VERSION 5.7 ;
  NOWIREEXTENSIONATPIN ON ;
  DIVIDERCHAR "/" ;
  BUSBITCHARS "[]" ;
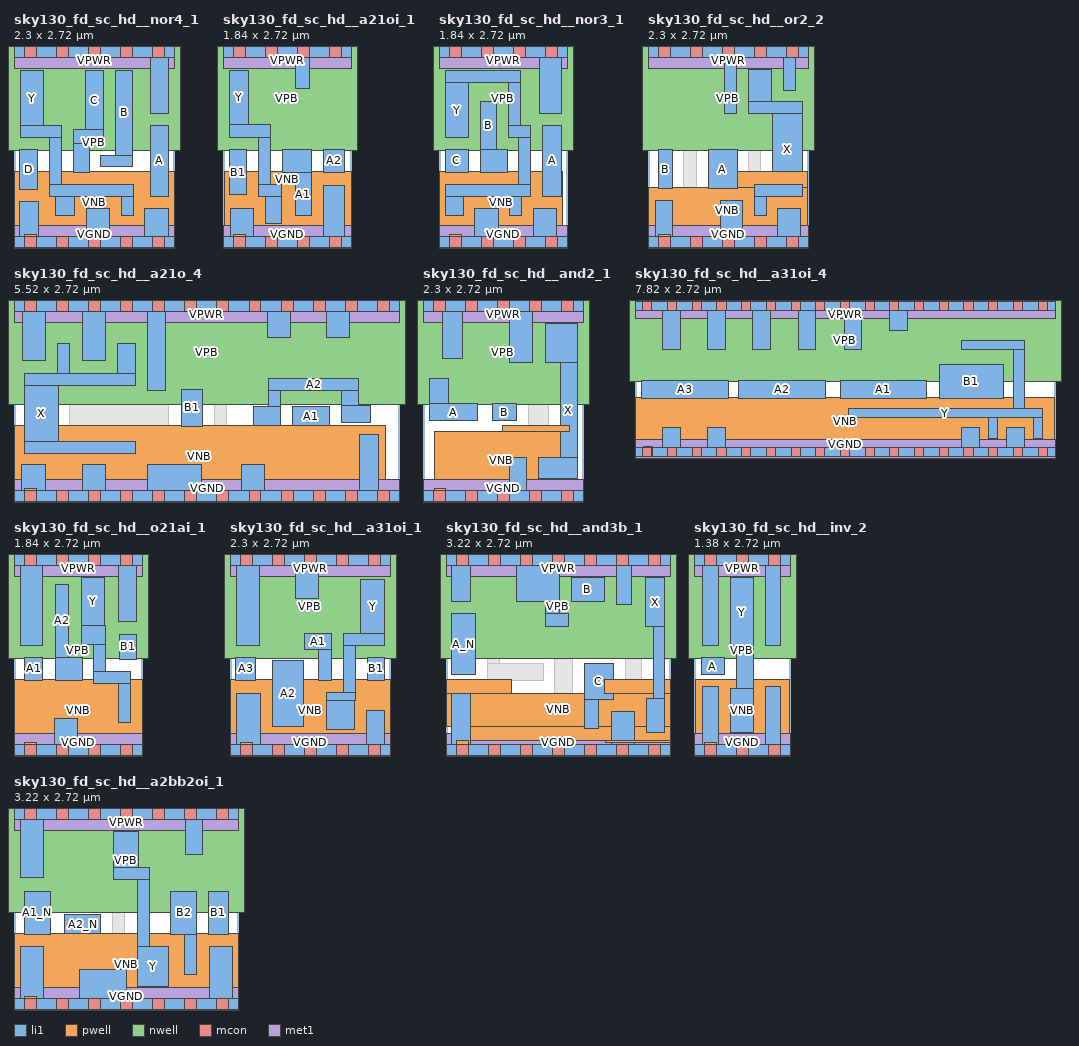
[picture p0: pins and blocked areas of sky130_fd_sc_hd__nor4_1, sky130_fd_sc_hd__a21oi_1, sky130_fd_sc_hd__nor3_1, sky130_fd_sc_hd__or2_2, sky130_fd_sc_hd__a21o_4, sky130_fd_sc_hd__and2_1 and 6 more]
MACRO sky130_fd_sc_hd__nor4_1
  CLASS BLOCK ;
  FOREIGN sky130_fd_sc_hd__nor4_1 ;
  ORIGIN 0.000 0.000 ;
  SIZE 2.300 BY 2.720 ;
  PIN D
    ANTENNAGATEAREA 0.247500 ;
    PORT
      LAYER li1 ;
        RECT 0.085 0.745 0.335 1.325 ;
    END
  END D
  PIN C
    ANTENNAGATEAREA 0.247500 ;
    PORT
      LAYER li1 ;
        RECT 1.030 1.615 1.285 2.450 ;
        RECT 0.845 1.415 1.285 1.615 ;
        RECT 0.845 0.995 1.075 1.415 ;
    END
  END C
  PIN Y
    ANTENNADIFFAREA 0.672750 ;
    PORT
      LAYER li1 ;
        RECT 0.090 1.665 0.425 2.450 ;
        RECT 0.090 1.495 0.675 1.665 ;
        RECT 0.505 0.825 0.675 1.495 ;
        RECT 0.505 0.655 1.705 0.825 ;
        RECT 0.505 0.645 0.860 0.655 ;
        RECT 0.595 0.385 0.860 0.645 ;
        RECT 1.535 0.385 1.705 0.655 ;
    END
  END Y
  PIN A
    ANTENNAGATEAREA 0.247500 ;
    PORT
      LAYER li1 ;
        RECT 1.955 0.655 2.215 1.665 ;
    END
  END A
  PIN B
    ANTENNAGATEAREA 0.247500 ;
    PORT
      LAYER li1 ;
        RECT 1.455 1.245 1.695 2.450 ;
        RECT 1.245 1.075 1.695 1.245 ;
    END
  END B
  PIN VNB
    PORT
      LAYER pwell ;
        RECT 0.005 0.105 2.295 1.015 ;
        RECT 0.145 -0.085 0.315 0.105 ;
    END
  END VNB
  PIN VPB
    PORT
      LAYER nwell ;
        RECT -0.190 1.305 2.490 2.910 ;
    END
  END VPB
  PIN VGND
    USE GROUND ;
    PORT
      LAYER li1 ;
        RECT 0.085 0.085 0.345 0.575 ;
        RECT 1.035 0.085 1.365 0.485 ;
        RECT 1.875 0.085 2.205 0.485 ;
        RECT 0.000 -0.085 2.300 0.085 ;
      LAYER mcon ;
        RECT 0.145 -0.085 0.315 0.085 ;
        RECT 0.605 -0.085 0.775 0.085 ;
        RECT 1.065 -0.085 1.235 0.085 ;
        RECT 1.525 -0.085 1.695 0.085 ;
        RECT 1.985 -0.085 2.155 0.085 ;
      LAYER met1 ;
        RECT 0.000 -0.240 2.300 0.240 ;
    END
  END VGND
  PIN VPWR
    USE POWER ;
    PORT
      LAYER li1 ;
        RECT 0.000 2.635 2.300 2.805 ;
        RECT 1.955 1.835 2.215 2.635 ;
      LAYER mcon ;
        RECT 0.145 2.635 0.315 2.805 ;
        RECT 0.605 2.635 0.775 2.805 ;
        RECT 1.065 2.635 1.235 2.805 ;
        RECT 1.525 2.635 1.695 2.805 ;
        RECT 1.985 2.635 2.155 2.805 ;
      LAYER met1 ;
        RECT 0.000 2.480 2.300 2.960 ;
    END
  END VPWR
END sky130_fd_sc_hd__nor4_1
MACRO sky130_fd_sc_hd__a21oi_1
  CLASS BLOCK ;
  FOREIGN sky130_fd_sc_hd__a21oi_1 ;
  ORIGIN 0.000 0.000 ;
  SIZE 1.840 BY 2.720 ;
  PIN A1
    ANTENNAGATEAREA 0.247500 ;
    PORT
      LAYER li1 ;
        RECT 0.850 0.995 1.265 1.325 ;
        RECT 1.035 0.375 1.265 0.995 ;
    END
  END A1
  PIN B1
    ANTENNAGATEAREA 0.247500 ;
    PORT
      LAYER li1 ;
        RECT 0.095 0.675 0.335 1.325 ;
    END
  END B1
  PIN Y
    ANTENNADIFFAREA 0.447000 ;
    PORT
      LAYER li1 ;
        RECT 0.095 1.685 0.370 2.455 ;
        RECT 0.095 1.495 0.680 1.685 ;
        RECT 0.505 0.825 0.680 1.495 ;
        RECT 0.505 0.645 0.835 0.825 ;
        RECT 0.610 0.265 0.835 0.645 ;
    END
  END Y
  PIN A2
    ANTENNAGATEAREA 0.247500 ;
    PORT
      LAYER li1 ;
        RECT 1.445 0.995 1.740 1.325 ;
    END
  END A2
  PIN VNB
    PORT
      LAYER pwell ;
        RECT 0.020 0.105 1.835 1.015 ;
        RECT 0.145 -0.085 0.315 0.105 ;
    END
  END VNB
  PIN VPB
    PORT
      LAYER nwell ;
        RECT -0.190 1.305 2.030 2.910 ;
    END
  END VPB
  PIN VPWR
    USE POWER ;
    PORT
      LAYER li1 ;
        RECT 0.000 2.635 1.840 2.805 ;
        RECT 1.040 2.195 1.235 2.635 ;
      LAYER mcon ;
        RECT 0.145 2.635 0.315 2.805 ;
        RECT 0.605 2.635 0.775 2.805 ;
        RECT 1.065 2.635 1.235 2.805 ;
        RECT 1.525 2.635 1.695 2.805 ;
      LAYER met1 ;
        RECT 0.000 2.480 1.840 2.960 ;
    END
  END VPWR
  PIN VGND
    USE GROUND ;
    PORT
      LAYER li1 ;
        RECT 0.110 0.085 0.440 0.475 ;
        RECT 1.445 0.085 1.745 0.815 ;
        RECT 0.000 -0.085 1.840 0.085 ;
      LAYER mcon ;
        RECT 0.145 -0.085 0.315 0.085 ;
        RECT 0.605 -0.085 0.775 0.085 ;
        RECT 1.065 -0.085 1.235 0.085 ;
        RECT 1.525 -0.085 1.695 0.085 ;
      LAYER met1 ;
        RECT 0.000 -0.240 1.840 0.240 ;
    END
  END VGND
  OBS
      LAYER li1 ;
        RECT 0.540 2.025 0.870 2.455 ;
        RECT 1.415 2.025 1.745 2.455 ;
        RECT 0.540 1.855 1.745 2.025 ;
        RECT 0.850 1.525 1.745 1.855 ;
  END
END sky130_fd_sc_hd__a21oi_1
MACRO sky130_fd_sc_hd__nor3_1
  CLASS BLOCK ;
  FOREIGN sky130_fd_sc_hd__nor3_1 ;
  ORIGIN 0.000 0.000 ;
  SIZE 1.840 BY 2.720 ;
  PIN C
    ANTENNAGATEAREA 0.247500 ;
    PORT
      LAYER li1 ;
        RECT 0.090 0.995 0.425 1.325 ;
    END
  END C
  PIN Y
    ANTENNADIFFAREA 0.604500 ;
    PORT
      LAYER li1 ;
        RECT 0.090 2.280 1.170 2.450 ;
        RECT 0.090 1.495 0.425 2.280 ;
        RECT 1.000 1.665 1.170 2.280 ;
        RECT 1.000 1.495 1.315 1.665 ;
        RECT 1.145 0.825 1.315 1.495 ;
        RECT 0.090 0.655 1.315 0.825 ;
        RECT 0.090 0.385 0.345 0.655 ;
        RECT 1.015 0.385 1.185 0.655 ;
    END
  END Y
  PIN A
    ANTENNAGATEAREA 0.247500 ;
    PORT
      LAYER li1 ;
        RECT 1.485 0.655 1.755 1.665 ;
    END
  END A
  PIN B
    ANTENNAGATEAREA 0.247500 ;
    PORT
      LAYER li1 ;
        RECT 0.595 1.325 0.830 2.005 ;
        RECT 0.595 0.995 0.975 1.325 ;
    END
  END B
  PIN VNB
    PORT
      LAYER pwell ;
        RECT 0.005 0.105 1.775 1.015 ;
        RECT 0.150 -0.085 0.320 0.105 ;
    END
  END VNB
  PIN VPB
    PORT
      LAYER nwell ;
        RECT -0.190 1.305 2.030 2.910 ;
    END
  END VPB
  PIN VGND
    USE GROUND ;
    PORT
      LAYER li1 ;
        RECT 0.515 0.085 0.845 0.485 ;
        RECT 1.355 0.085 1.685 0.485 ;
        RECT 0.000 -0.085 1.840 0.085 ;
      LAYER mcon ;
        RECT 0.145 -0.085 0.315 0.085 ;
        RECT 0.605 -0.085 0.775 0.085 ;
        RECT 1.065 -0.085 1.235 0.085 ;
        RECT 1.525 -0.085 1.695 0.085 ;
      LAYER met1 ;
        RECT 0.000 -0.240 1.840 0.240 ;
    END
  END VGND
  PIN VPWR
    USE POWER ;
    PORT
      LAYER li1 ;
        RECT 0.000 2.635 1.840 2.805 ;
        RECT 1.435 1.835 1.750 2.635 ;
      LAYER mcon ;
        RECT 0.145 2.635 0.315 2.805 ;
        RECT 0.605 2.635 0.775 2.805 ;
        RECT 1.065 2.635 1.235 2.805 ;
        RECT 1.525 2.635 1.695 2.805 ;
      LAYER met1 ;
        RECT 0.000 2.480 1.840 2.960 ;
    END
  END VPWR
END sky130_fd_sc_hd__nor3_1
MACRO sky130_fd_sc_hd__or2_2
  CLASS BLOCK ;
  FOREIGN sky130_fd_sc_hd__or2_2 ;
  ORIGIN 0.000 0.000 ;
  SIZE 2.300 BY 2.720 ;
  PIN B
    ANTENNAGATEAREA 0.126000 ;
    PORT
      LAYER li1 ;
        RECT 0.150 0.765 0.345 1.325 ;
    END
  END B
  PIN X
    ANTENNADIFFAREA 0.445500 ;
    PORT
      LAYER li1 ;
        RECT 1.440 2.005 1.770 2.465 ;
        RECT 1.440 1.835 2.215 2.005 ;
        RECT 1.785 0.825 2.215 1.835 ;
        RECT 1.520 0.655 2.215 0.825 ;
        RECT 1.520 0.385 1.690 0.655 ;
    END
  END X
  PIN A
    ANTENNAGATEAREA 0.126000 ;
    PORT
      LAYER li1 ;
        RECT 0.865 0.765 1.275 1.325 ;
    END
  END A
  PIN VNB
    PORT
      LAYER pwell ;
        RECT 0.910 0.785 2.280 1.015 ;
        RECT 0.005 0.105 2.280 0.785 ;
        RECT 0.150 -0.085 0.320 0.105 ;
    END
  END VNB
  PIN VPB
    PORT
      LAYER nwell ;
        RECT -0.190 1.305 2.490 2.910 ;
    END
  END VPB
  PIN VPWR
    USE POWER ;
    PORT
      LAYER li1 ;
        RECT 0.000 2.635 2.300 2.805 ;
        RECT 1.100 1.835 1.270 2.635 ;
        RECT 1.940 2.175 2.110 2.635 ;
      LAYER mcon ;
        RECT 0.145 2.635 0.315 2.805 ;
        RECT 0.605 2.635 0.775 2.805 ;
        RECT 1.065 2.635 1.235 2.805 ;
        RECT 1.525 2.635 1.695 2.805 ;
        RECT 1.985 2.635 2.155 2.805 ;
      LAYER met1 ;
        RECT 0.000 2.480 2.300 2.960 ;
    END
  END VPWR
  PIN VGND
    USE GROUND ;
    PORT
      LAYER li1 ;
        RECT 0.105 0.085 0.345 0.595 ;
        RECT 1.035 0.085 1.350 0.595 ;
        RECT 1.860 0.085 2.190 0.485 ;
        RECT 0.000 -0.085 2.300 0.085 ;
      LAYER mcon ;
        RECT 0.145 -0.085 0.315 0.085 ;
        RECT 0.605 -0.085 0.775 0.085 ;
        RECT 1.065 -0.085 1.235 0.085 ;
        RECT 1.525 -0.085 1.695 0.085 ;
        RECT 1.985 -0.085 2.155 0.085 ;
      LAYER met1 ;
        RECT 0.000 -0.240 2.300 0.240 ;
    END
  END VGND
  OBS
      LAYER li1 ;
        RECT 0.155 1.665 0.515 1.840 ;
        RECT 0.155 1.495 1.615 1.665 ;
        RECT 0.515 0.595 0.695 1.495 ;
        RECT 1.445 0.995 1.615 1.495 ;
        RECT 0.515 0.255 0.805 0.595 ;
  END
END sky130_fd_sc_hd__or2_2
MACRO sky130_fd_sc_hd__a21o_4
  CLASS BLOCK ;
  FOREIGN sky130_fd_sc_hd__a21o_4 ;
  ORIGIN 0.000 0.000 ;
  SIZE 5.520 BY 2.720 ;
  PIN A2
    ANTENNAGATEAREA 0.495000 ;
    PORT
      LAYER li1 ;
        RECT 3.645 1.510 4.935 1.680 ;
        RECT 3.645 1.275 3.820 1.510 ;
        RECT 3.425 1.010 3.820 1.275 ;
        RECT 4.685 1.290 4.935 1.510 ;
        RECT 4.685 1.055 5.100 1.290 ;
    END
  END A2
  PIN A1
    ANTENNAGATEAREA 0.495000 ;
    PORT
      LAYER li1 ;
        RECT 3.990 1.010 4.515 1.275 ;
    END
  END A1
  PIN X
    ANTENNADIFFAREA 0.924000 ;
    PORT
      LAYER li1 ;
        RECT 0.625 1.755 0.795 2.185 ;
        RECT 1.485 1.755 1.735 2.185 ;
        RECT 0.145 1.585 1.735 1.755 ;
        RECT 0.145 0.785 0.630 1.585 ;
        RECT 0.145 0.615 1.735 0.785 ;
    END
  END X
  PIN B1
    ANTENNAGATEAREA 0.495000 ;
    PORT
      LAYER li1 ;
        RECT 2.395 0.995 2.705 1.525 ;
    END
  END B1
  PIN VNB
    PORT
      LAYER pwell ;
        RECT 0.005 0.105 5.315 1.015 ;
        RECT 0.145 -0.085 0.315 0.105 ;
    END
  END VNB
  PIN VPB
    PORT
      LAYER nwell ;
        RECT -0.190 1.305 5.710 2.910 ;
    END
  END VPB
  PIN VGND
    USE GROUND ;
    PORT
      LAYER li1 ;
        RECT 0.105 0.085 0.445 0.445 ;
        RECT 0.975 0.085 1.305 0.445 ;
        RECT 1.910 0.085 2.685 0.445 ;
        RECT 3.255 0.085 3.585 0.445 ;
        RECT 4.945 0.085 5.225 0.885 ;
        RECT 0.000 -0.085 5.520 0.085 ;
      LAYER mcon ;
        RECT 0.145 -0.085 0.315 0.085 ;
        RECT 0.605 -0.085 0.775 0.085 ;
        RECT 1.065 -0.085 1.235 0.085 ;
        RECT 1.525 -0.085 1.695 0.085 ;
        RECT 1.985 -0.085 2.155 0.085 ;
        RECT 2.445 -0.085 2.615 0.085 ;
        RECT 2.905 -0.085 3.075 0.085 ;
        RECT 3.365 -0.085 3.535 0.085 ;
        RECT 3.825 -0.085 3.995 0.085 ;
        RECT 4.285 -0.085 4.455 0.085 ;
        RECT 4.745 -0.085 4.915 0.085 ;
        RECT 5.205 -0.085 5.375 0.085 ;
      LAYER met1 ;
        RECT 0.000 -0.240 5.520 0.240 ;
    END
  END VGND
  PIN VPWR
    USE POWER ;
    PORT
      LAYER li1 ;
        RECT 0.000 2.635 5.520 2.805 ;
        RECT 0.115 1.935 0.445 2.635 ;
        RECT 0.975 1.935 1.305 2.635 ;
        RECT 1.915 1.515 2.165 2.635 ;
        RECT 3.635 2.275 3.965 2.635 ;
        RECT 4.475 2.275 4.805 2.635 ;
      LAYER mcon ;
        RECT 0.145 2.635 0.315 2.805 ;
        RECT 0.605 2.635 0.775 2.805 ;
        RECT 1.065 2.635 1.235 2.805 ;
        RECT 1.525 2.635 1.695 2.805 ;
        RECT 1.985 2.635 2.155 2.805 ;
        RECT 2.445 2.635 2.615 2.805 ;
        RECT 2.905 2.635 3.075 2.805 ;
        RECT 3.365 2.635 3.535 2.805 ;
        RECT 3.825 2.635 3.995 2.805 ;
        RECT 4.285 2.635 4.455 2.805 ;
        RECT 4.745 2.635 4.915 2.805 ;
        RECT 5.205 2.635 5.375 2.805 ;
      LAYER met1 ;
        RECT 0.000 2.480 5.520 2.960 ;
    END
  END VPWR
  OBS
      LAYER li1 ;
        RECT 2.455 2.295 3.465 2.465 ;
        RECT 2.455 1.695 2.625 2.295 ;
        RECT 0.800 0.995 2.205 1.325 ;
        RECT 2.035 0.785 2.205 0.995 ;
        RECT 2.875 0.840 3.045 2.125 ;
        RECT 3.285 2.020 3.465 2.295 ;
        RECT 4.135 2.020 4.305 2.465 ;
        RECT 5.030 2.020 5.360 2.395 ;
        RECT 3.285 1.850 5.360 2.020 ;
        RECT 3.285 1.445 3.465 1.850 ;
        RECT 5.105 1.460 5.360 1.850 ;
        RECT 2.875 0.785 4.365 0.840 ;
        RECT 2.035 0.670 4.365 0.785 ;
        RECT 2.035 0.615 3.045 0.670 ;
        RECT 2.875 0.255 3.045 0.615 ;
        RECT 4.085 0.405 4.365 0.670 ;
  END
END sky130_fd_sc_hd__a21o_4
MACRO sky130_fd_sc_hd__and2_1
  CLASS BLOCK ;
  FOREIGN sky130_fd_sc_hd__and2_1 ;
  ORIGIN 0.000 0.000 ;
  SIZE 2.300 BY 2.720 ;
  PIN X
    ANTENNADIFFAREA 0.657000 ;
    PORT
      LAYER li1 ;
        RECT 1.755 1.915 2.215 2.465 ;
        RECT 1.965 0.545 2.215 1.915 ;
        RECT 1.655 0.255 2.215 0.545 ;
    END
  END X
  PIN B
    ANTENNAGATEAREA 0.126000 ;
    PORT
      LAYER li1 ;
        RECT 0.995 1.075 1.335 1.325 ;
    END
  END B
  PIN A
    ANTENNAGATEAREA 0.126000 ;
    PORT
      LAYER li1 ;
        RECT 0.100 1.325 0.365 1.685 ;
        RECT 0.100 1.075 0.775 1.325 ;
    END
  END A
  PIN VNB
    PORT
      LAYER pwell ;
        RECT 1.145 0.925 2.095 1.015 ;
        RECT 0.165 0.105 2.095 0.925 ;
        RECT 0.165 0.085 0.315 0.105 ;
        RECT 0.145 -0.085 0.315 0.085 ;
    END
  END VNB
  PIN VPB
    PORT
      LAYER nwell ;
        RECT -0.190 1.305 2.490 2.910 ;
    END
  END VPB
  PIN VPWR
    USE POWER ;
    PORT
      LAYER li1 ;
        RECT 0.000 2.635 2.300 2.805 ;
        RECT 0.285 1.965 0.565 2.635 ;
        RECT 1.235 1.915 1.565 2.635 ;
      LAYER mcon ;
        RECT 0.145 2.635 0.315 2.805 ;
        RECT 0.605 2.635 0.775 2.805 ;
        RECT 1.065 2.635 1.235 2.805 ;
        RECT 1.525 2.635 1.695 2.805 ;
        RECT 1.985 2.635 2.155 2.805 ;
      LAYER met1 ;
        RECT 0.000 2.480 2.300 2.960 ;
    END
  END VPWR
  PIN VGND
    USE GROUND ;
    PORT
      LAYER li1 ;
        RECT 1.235 0.085 1.485 0.545 ;
        RECT 0.000 -0.085 2.300 0.085 ;
      LAYER mcon ;
        RECT 0.145 -0.085 0.315 0.085 ;
        RECT 0.605 -0.085 0.775 0.085 ;
        RECT 1.065 -0.085 1.235 0.085 ;
        RECT 1.525 -0.085 1.695 0.085 ;
        RECT 1.985 -0.085 2.155 0.085 ;
      LAYER met1 ;
        RECT 0.000 -0.240 2.300 0.240 ;
    END
  END VGND
  OBS
      LAYER li1 ;
        RECT 0.735 1.745 1.035 2.295 ;
        RECT 0.735 1.575 1.675 1.745 ;
        RECT 1.505 1.325 1.675 1.575 ;
        RECT 1.505 0.995 1.795 1.325 ;
        RECT 1.505 0.905 1.675 0.995 ;
        RECT 0.285 0.715 1.675 0.905 ;
        RECT 0.285 0.355 0.615 0.715 ;
  END
END sky130_fd_sc_hd__and2_1
MACRO sky130_fd_sc_hd__a31oi_4
  CLASS BLOCK ;
  FOREIGN sky130_fd_sc_hd__a31oi_4 ;
  ORIGIN 0.000 0.000 ;
  SIZE 7.820 BY 2.720 ;
  PIN Y
    ANTENNADIFFAREA 1.443500 ;
    PORT
      LAYER li1 ;
        RECT 6.075 1.915 7.245 2.085 ;
        RECT 7.045 0.805 7.245 1.915 ;
        RECT 3.975 0.635 7.585 0.805 ;
        RECT 6.575 0.255 6.745 0.635 ;
        RECT 7.415 0.255 7.585 0.635 ;
    END
  END Y
  PIN B1
    ANTENNAGATEAREA 0.990000 ;
    PORT
      LAYER li1 ;
        RECT 5.670 0.995 6.855 1.630 ;
    END
  END B1
  PIN A1
    ANTENNAGATEAREA 0.990000 ;
    PORT
      LAYER li1 ;
        RECT 3.825 0.995 5.420 1.325 ;
    END
  END A1
  PIN A3
    ANTENNAGATEAREA 0.990000 ;
    PORT
      LAYER li1 ;
        RECT 0.120 0.995 1.735 1.325 ;
    END
  END A3
  PIN A2
    ANTENNAGATEAREA 0.990000 ;
    PORT
      LAYER li1 ;
        RECT 1.935 0.995 3.550 1.325 ;
    END
  END A2
  PIN VNB
    PORT
      LAYER pwell ;
        RECT 0.005 0.105 7.815 1.015 ;
        RECT 0.150 -0.085 0.320 0.105 ;
    END
  END VNB
  PIN VPB
    PORT
      LAYER nwell ;
        RECT -0.190 1.305 8.010 2.910 ;
    END
  END VPB
  PIN VPWR
    USE POWER ;
    PORT
      LAYER li1 ;
        RECT 0.000 2.635 7.820 2.805 ;
        RECT 0.515 1.915 0.845 2.635 ;
        RECT 1.355 1.915 1.685 2.635 ;
        RECT 2.195 1.915 2.525 2.635 ;
        RECT 3.035 1.915 3.365 2.635 ;
        RECT 3.895 1.915 4.225 2.635 ;
        RECT 4.735 2.255 5.065 2.635 ;
      LAYER mcon ;
        RECT 0.145 2.635 0.315 2.805 ;
        RECT 0.605 2.635 0.775 2.805 ;
        RECT 1.065 2.635 1.235 2.805 ;
        RECT 1.525 2.635 1.695 2.805 ;
        RECT 1.985 2.635 2.155 2.805 ;
        RECT 2.445 2.635 2.615 2.805 ;
        RECT 2.905 2.635 3.075 2.805 ;
        RECT 3.365 2.635 3.535 2.805 ;
        RECT 3.825 2.635 3.995 2.805 ;
        RECT 4.285 2.635 4.455 2.805 ;
        RECT 4.745 2.635 4.915 2.805 ;
        RECT 5.205 2.635 5.375 2.805 ;
        RECT 5.665 2.635 5.835 2.805 ;
        RECT 6.125 2.635 6.295 2.805 ;
        RECT 6.585 2.635 6.755 2.805 ;
        RECT 7.045 2.635 7.215 2.805 ;
        RECT 7.505 2.635 7.675 2.805 ;
      LAYER met1 ;
        RECT 0.000 2.480 7.820 2.960 ;
    END
  END VPWR
  PIN VGND
    USE GROUND ;
    PORT
      LAYER li1 ;
        RECT 0.515 0.085 0.845 0.465 ;
        RECT 1.355 0.085 1.685 0.465 ;
        RECT 6.075 0.085 6.405 0.465 ;
        RECT 6.915 0.085 7.245 0.465 ;
        RECT 0.000 -0.085 7.820 0.085 ;
      LAYER mcon ;
        RECT 0.145 -0.085 0.315 0.085 ;
        RECT 0.605 -0.085 0.775 0.085 ;
        RECT 1.065 -0.085 1.235 0.085 ;
        RECT 1.525 -0.085 1.695 0.085 ;
        RECT 1.985 -0.085 2.155 0.085 ;
        RECT 2.445 -0.085 2.615 0.085 ;
        RECT 2.905 -0.085 3.075 0.085 ;
        RECT 3.365 -0.085 3.535 0.085 ;
        RECT 3.825 -0.085 3.995 0.085 ;
        RECT 4.285 -0.085 4.455 0.085 ;
        RECT 4.745 -0.085 4.915 0.085 ;
        RECT 5.205 -0.085 5.375 0.085 ;
        RECT 5.665 -0.085 5.835 0.085 ;
        RECT 6.125 -0.085 6.295 0.085 ;
        RECT 6.585 -0.085 6.755 0.085 ;
        RECT 7.045 -0.085 7.215 0.085 ;
        RECT 7.505 -0.085 7.675 0.085 ;
      LAYER met1 ;
        RECT 0.000 -0.240 7.820 0.240 ;
    END
  END VGND
  OBS
      LAYER li1 ;
        RECT 0.175 1.665 0.345 2.465 ;
        RECT 1.015 1.665 1.185 2.465 ;
        RECT 1.855 1.665 2.025 2.465 ;
        RECT 2.695 1.665 2.865 2.465 ;
        RECT 3.535 1.665 3.705 2.465 ;
        RECT 4.395 1.665 4.565 2.465 ;
        RECT 5.235 2.425 5.405 2.465 ;
        RECT 5.235 2.255 7.665 2.425 ;
        RECT 5.235 1.665 5.405 2.255 ;
        RECT 0.175 1.495 5.405 1.665 ;
        RECT 7.415 1.495 7.665 2.255 ;
        RECT 0.175 0.635 3.785 0.805 ;
        RECT 0.175 0.255 0.345 0.635 ;
        RECT 1.015 0.255 1.185 0.635 ;
        RECT 1.855 0.255 2.025 0.635 ;
        RECT 2.195 0.295 5.565 0.465 ;
  END
END sky130_fd_sc_hd__a31oi_4
MACRO sky130_fd_sc_hd__o21ai_1
  CLASS BLOCK ;
  FOREIGN sky130_fd_sc_hd__o21ai_1 ;
  ORIGIN 0.000 0.000 ;
  SIZE 1.840 BY 2.720 ;
  PIN A2
    ANTENNAGATEAREA 0.247500 ;
    PORT
      LAYER li1 ;
        RECT 0.590 1.325 0.785 2.375 ;
        RECT 0.590 0.995 0.975 1.325 ;
    END
  END A2
  PIN A1
    ANTENNAGATEAREA 0.247500 ;
    PORT
      LAYER li1 ;
        RECT 0.150 0.995 0.410 1.325 ;
    END
  END A1
  PIN B1
    ANTENNAGATEAREA 0.202500 ;
    PORT
      LAYER li1 ;
        RECT 1.505 1.295 1.750 1.655 ;
    END
  END B1
  PIN Y
    ANTENNADIFFAREA 0.517000 ;
    PORT
      LAYER li1 ;
        RECT 0.965 1.785 1.295 2.465 ;
        RECT 0.965 1.505 1.315 1.785 ;
        RECT 1.145 1.125 1.315 1.505 ;
        RECT 1.145 0.955 1.665 1.125 ;
        RECT 1.495 0.390 1.665 0.955 ;
    END
  END Y
  PIN VNB
    PORT
      LAYER pwell ;
        RECT 0.005 0.105 1.835 1.015 ;
        RECT 0.150 -0.085 0.320 0.105 ;
    END
  END VNB
  PIN VPB
    PORT
      LAYER nwell ;
        RECT -0.190 1.305 2.030 2.910 ;
    END
  END VPB
  PIN VGND
    USE GROUND ;
    PORT
      LAYER li1 ;
        RECT 0.575 0.085 0.905 0.445 ;
        RECT 0.000 -0.085 1.840 0.085 ;
      LAYER mcon ;
        RECT 0.145 -0.085 0.315 0.085 ;
        RECT 0.605 -0.085 0.775 0.085 ;
        RECT 1.065 -0.085 1.235 0.085 ;
        RECT 1.525 -0.085 1.695 0.085 ;
      LAYER met1 ;
        RECT 0.000 -0.240 1.840 0.240 ;
    END
  END VGND
  PIN VPWR
    USE POWER ;
    PORT
      LAYER li1 ;
        RECT 0.000 2.635 1.840 2.805 ;
        RECT 0.090 1.495 0.410 2.635 ;
        RECT 1.495 1.835 1.750 2.635 ;
      LAYER mcon ;
        RECT 0.145 2.635 0.315 2.805 ;
        RECT 0.605 2.635 0.775 2.805 ;
        RECT 1.065 2.635 1.235 2.805 ;
        RECT 1.525 2.635 1.695 2.805 ;
      LAYER met1 ;
        RECT 0.000 2.480 1.840 2.960 ;
    END
  END VPWR
  OBS
      LAYER li1 ;
        RECT 0.090 0.615 1.305 0.785 ;
        RECT 0.090 0.265 0.380 0.615 ;
        RECT 1.075 0.310 1.305 0.615 ;
  END
END sky130_fd_sc_hd__o21ai_1
MACRO sky130_fd_sc_hd__a31oi_1
  CLASS BLOCK ;
  FOREIGN sky130_fd_sc_hd__a31oi_1 ;
  ORIGIN 0.000 0.000 ;
  SIZE 2.300 BY 2.720 ;
  PIN Y
    ANTENNADIFFAREA 0.481250 ;
    PORT
      LAYER li1 ;
        RECT 1.875 1.665 2.210 2.445 ;
        RECT 1.625 1.495 2.210 1.665 ;
        RECT 1.625 0.825 1.795 1.495 ;
        RECT 1.380 0.715 1.795 0.825 ;
        RECT 1.380 0.295 1.785 0.715 ;
    END
  END Y
  PIN B1
    ANTENNAGATEAREA 0.247500 ;
    PORT
      LAYER li1 ;
        RECT 1.965 0.995 2.215 1.325 ;
    END
  END B1
  PIN A2
    ANTENNAGATEAREA 0.247500 ;
    PORT
      LAYER li1 ;
        RECT 0.610 0.335 1.055 1.275 ;
    END
  END A2
  PIN A1
    ANTENNAGATEAREA 0.247500 ;
    PORT
      LAYER li1 ;
        RECT 1.070 1.445 1.455 1.665 ;
        RECT 1.270 0.995 1.455 1.445 ;
    END
  END A1
  PIN A3
    ANTENNAGATEAREA 0.247500 ;
    PORT
      LAYER li1 ;
        RECT 0.085 0.995 0.365 1.325 ;
    END
  END A3
  PIN VNB
    PORT
      LAYER pwell ;
        RECT 0.005 0.105 2.295 1.015 ;
        RECT 0.150 -0.085 0.320 0.105 ;
    END
  END VNB
  PIN VPB
    PORT
      LAYER nwell ;
        RECT -0.190 1.305 2.490 2.910 ;
    END
  END VPB
  PIN VGND
    USE GROUND ;
    PORT
      LAYER li1 ;
        RECT 0.090 0.085 0.430 0.815 ;
        RECT 1.955 0.085 2.215 0.565 ;
        RECT 0.000 -0.085 2.300 0.085 ;
      LAYER mcon ;
        RECT 0.145 -0.085 0.315 0.085 ;
        RECT 0.605 -0.085 0.775 0.085 ;
        RECT 1.065 -0.085 1.235 0.085 ;
        RECT 1.525 -0.085 1.695 0.085 ;
        RECT 1.985 -0.085 2.155 0.085 ;
      LAYER met1 ;
        RECT 0.000 -0.240 2.300 0.240 ;
    END
  END VGND
  PIN VPWR
    USE POWER ;
    PORT
      LAYER li1 ;
        RECT 0.000 2.635 2.300 2.805 ;
        RECT 0.090 1.495 0.420 2.635 ;
        RECT 0.935 2.175 1.265 2.635 ;
      LAYER mcon ;
        RECT 0.145 2.635 0.315 2.805 ;
        RECT 0.605 2.635 0.775 2.805 ;
        RECT 1.065 2.635 1.235 2.805 ;
        RECT 1.525 2.635 1.695 2.805 ;
        RECT 1.985 2.635 2.155 2.805 ;
      LAYER met1 ;
        RECT 0.000 2.480 2.300 2.960 ;
    END
  END VPWR
  OBS
      LAYER li1 ;
        RECT 0.590 2.005 0.765 2.415 ;
        RECT 1.470 2.005 1.695 2.415 ;
        RECT 0.590 1.835 1.695 2.005 ;
  END
END sky130_fd_sc_hd__a31oi_1
MACRO sky130_fd_sc_hd__and3b_1
  CLASS BLOCK ;
  FOREIGN sky130_fd_sc_hd__and3b_1 ;
  ORIGIN 0.000 0.000 ;
  SIZE 3.220 BY 2.720 ;
  PIN A_N
    ANTENNAGATEAREA 0.126000 ;
    PORT
      LAYER li1 ;
        RECT 0.085 1.075 0.425 1.955 ;
    END
  END A_N
  PIN B
    ANTENNAGATEAREA 0.126000 ;
    PORT
      LAYER li1 ;
        RECT 1.790 2.125 2.265 2.465 ;
    END
  END B
  PIN X
    ANTENNADIFFAREA 0.429000 ;
    PORT
      LAYER li1 ;
        RECT 2.860 1.765 3.135 2.465 ;
        RECT 2.965 0.735 3.135 1.765 ;
        RECT 2.875 0.255 3.135 0.735 ;
    END
  END X
  PIN C
    ANTENNAGATEAREA 0.126000 ;
    PORT
      LAYER li1 ;
        RECT 1.985 0.725 2.395 1.245 ;
        RECT 1.985 0.305 2.185 0.725 ;
    END
  END C
  PIN VNB
    PORT
      LAYER pwell ;
        RECT 0.005 0.815 0.935 1.015 ;
        RECT 2.265 0.815 3.215 1.015 ;
        RECT 0.005 0.335 3.215 0.815 ;
        RECT 0.150 0.135 3.215 0.335 ;
        RECT 0.150 -0.085 0.320 0.135 ;
        RECT 2.280 0.105 3.215 0.135 ;
    END
  END VNB
  PIN VPB
    PORT
      LAYER nwell ;
        RECT -0.190 1.305 3.410 2.910 ;
    END
  END VPB
  PIN VGND
    USE GROUND ;
    PORT
      LAYER li1 ;
        RECT 0.085 0.085 0.345 0.905 ;
        RECT 2.375 0.085 2.705 0.545 ;
        RECT 0.000 -0.085 3.220 0.085 ;
      LAYER mcon ;
        RECT 0.145 -0.085 0.315 0.085 ;
        RECT 0.605 -0.085 0.775 0.085 ;
        RECT 1.065 -0.085 1.235 0.085 ;
        RECT 1.525 -0.085 1.695 0.085 ;
        RECT 1.985 -0.085 2.155 0.085 ;
        RECT 2.445 -0.085 2.615 0.085 ;
        RECT 2.905 -0.085 3.075 0.085 ;
      LAYER met1 ;
        RECT 0.000 -0.240 3.220 0.240 ;
    END
  END VGND
  PIN VPWR
    USE POWER ;
    PORT
      LAYER li1 ;
        RECT 0.000 2.635 3.220 2.805 ;
        RECT 0.085 2.125 0.345 2.635 ;
        RECT 1.005 2.130 1.620 2.635 ;
        RECT 1.425 1.955 1.620 2.130 ;
        RECT 2.435 2.090 2.650 2.635 ;
        RECT 1.425 1.765 1.755 1.955 ;
      LAYER mcon ;
        RECT 0.145 2.635 0.315 2.805 ;
        RECT 0.605 2.635 0.775 2.805 ;
        RECT 1.065 2.635 1.235 2.805 ;
        RECT 1.525 2.635 1.695 2.805 ;
        RECT 1.985 2.635 2.155 2.805 ;
        RECT 2.445 2.635 2.615 2.805 ;
        RECT 2.905 2.635 3.075 2.805 ;
      LAYER met1 ;
        RECT 0.000 2.480 3.220 2.960 ;
    END
  END VPWR
  OBS
      LAYER li1 ;
        RECT 0.595 1.245 0.765 2.465 ;
        RECT 1.005 1.595 1.255 1.960 ;
        RECT 1.975 1.595 2.690 1.890 ;
        RECT 1.005 1.425 2.795 1.595 ;
        RECT 0.595 0.995 1.390 1.245 ;
        RECT 0.595 0.905 0.845 0.995 ;
        RECT 0.515 0.485 0.845 0.905 ;
        RECT 1.560 0.570 1.815 1.425 ;
        RECT 2.565 0.995 2.795 1.425 ;
        RECT 1.025 0.305 1.815 0.570 ;
  END
END sky130_fd_sc_hd__and3b_1
MACRO sky130_fd_sc_hd__inv_2
  CLASS BLOCK ;
  FOREIGN sky130_fd_sc_hd__inv_2 ;
  ORIGIN 0.000 0.000 ;
  SIZE 1.380 BY 2.720 ;
  PIN A
    ANTENNAGATEAREA 0.495000 ;
    PORT
      LAYER li1 ;
        RECT 0.105 1.075 0.435 1.325 ;
    END
  END A
  PIN Y
    ANTENNADIFFAREA 0.445500 ;
    PORT
      LAYER li1 ;
        RECT 0.525 1.485 0.855 2.465 ;
        RECT 0.605 0.885 0.855 1.485 ;
        RECT 0.525 0.255 0.855 0.885 ;
    END
  END Y
  PIN VNB
    PORT
      LAYER pwell ;
        RECT 0.015 0.105 1.365 1.015 ;
        RECT 0.145 -0.085 0.315 0.105 ;
    END
  END VNB
  PIN VPB
    PORT
      LAYER nwell ;
        RECT -0.190 1.305 1.570 2.910 ;
    END
  END VPB
  PIN VPWR
    USE POWER ;
    PORT
      LAYER li1 ;
        RECT 0.000 2.635 1.380 2.805 ;
        RECT 0.125 1.495 0.355 2.635 ;
        RECT 1.025 1.495 1.235 2.635 ;
      LAYER mcon ;
        RECT 0.145 2.635 0.315 2.805 ;
        RECT 0.605 2.635 0.775 2.805 ;
        RECT 1.065 2.635 1.235 2.805 ;
      LAYER met1 ;
        RECT 0.000 2.480 1.380 2.960 ;
    END
  END VPWR
  PIN VGND
    USE GROUND ;
    PORT
      LAYER li1 ;
        RECT 0.125 0.085 0.355 0.905 ;
        RECT 1.025 0.085 1.235 0.905 ;
        RECT 0.000 -0.085 1.380 0.085 ;
      LAYER mcon ;
        RECT 0.145 -0.085 0.315 0.085 ;
        RECT 0.605 -0.085 0.775 0.085 ;
        RECT 1.065 -0.085 1.235 0.085 ;
      LAYER met1 ;
        RECT 0.000 -0.240 1.380 0.240 ;
    END
  END VGND
END sky130_fd_sc_hd__inv_2
MACRO sky130_fd_sc_hd__a2bb2oi_1
  CLASS BLOCK ;
  FOREIGN sky130_fd_sc_hd__a2bb2oi_1 ;
  ORIGIN 0.000 0.000 ;
  SIZE 3.220 BY 2.720 ;
  PIN A1_N
    ANTENNAGATEAREA 0.247500 ;
    PORT
      LAYER li1 ;
        RECT 0.150 0.995 0.520 1.615 ;
    END
  END A1_N
  PIN Y
    ANTENNADIFFAREA 0.515500 ;
    PORT
      LAYER li1 ;
        RECT 1.420 1.955 1.785 2.465 ;
        RECT 1.420 1.785 1.945 1.955 ;
        RECT 1.775 0.825 1.945 1.785 ;
        RECT 1.775 0.255 2.205 0.825 ;
    END
  END Y
  PIN VGND
    USE GROUND ;
    PORT
      LAYER li1 ;
        RECT 0.095 0.085 0.425 0.825 ;
        RECT 0.935 0.085 1.605 0.490 ;
        RECT 2.795 0.085 3.125 0.825 ;
        RECT 0.000 -0.085 3.220 0.085 ;
      LAYER mcon ;
        RECT 0.145 -0.085 0.315 0.085 ;
        RECT 0.605 -0.085 0.775 0.085 ;
        RECT 1.065 -0.085 1.235 0.085 ;
        RECT 1.525 -0.085 1.695 0.085 ;
        RECT 1.985 -0.085 2.155 0.085 ;
        RECT 2.445 -0.085 2.615 0.085 ;
        RECT 2.905 -0.085 3.075 0.085 ;
      LAYER met1 ;
        RECT 0.000 -0.240 3.220 0.240 ;
    END
  END VGND
  PIN VPWR
    USE POWER ;
    PORT
      LAYER li1 ;
        RECT 0.000 2.635 3.220 2.805 ;
        RECT 0.095 1.805 0.425 2.635 ;
        RECT 2.455 2.135 2.705 2.635 ;
      LAYER mcon ;
        RECT 0.145 2.635 0.315 2.805 ;
        RECT 0.605 2.635 0.775 2.805 ;
        RECT 1.065 2.635 1.235 2.805 ;
        RECT 1.525 2.635 1.695 2.805 ;
        RECT 1.985 2.635 2.155 2.805 ;
        RECT 2.445 2.635 2.615 2.805 ;
        RECT 2.905 2.635 3.075 2.805 ;
      LAYER met1 ;
        RECT 0.000 2.480 3.220 2.960 ;
    END
  END VPWR
  PIN B2
    ANTENNAGATEAREA 0.247500 ;
    PORT
      LAYER li1 ;
        RECT 2.245 0.995 2.610 1.615 ;
        RECT 2.440 0.425 2.610 0.995 ;
    END
  END B2
  PIN B1
    ANTENNAGATEAREA 0.247500 ;
    PORT
      LAYER li1 ;
        RECT 2.780 0.995 3.070 1.615 ;
    END
  END B1
  PIN A2_N
    ANTENNAGATEAREA 0.247500 ;
    PORT
      LAYER li1 ;
        RECT 0.725 1.010 1.240 1.275 ;
    END
  END A2_N
  PIN VNB
    PORT
      LAYER pwell ;
        RECT 0.005 0.105 3.215 1.015 ;
        RECT 0.145 -0.085 0.315 0.105 ;
    END
  END VNB
  PIN VPB
    PORT
      LAYER nwell ;
        RECT -0.190 1.305 3.410 2.910 ;
    END
  END VPB
  OBS
      LAYER li1 ;
        RECT 0.875 1.615 1.205 2.465 ;
        RECT 1.955 2.235 2.285 2.465 ;
        RECT 2.115 1.955 2.285 2.235 ;
        RECT 2.875 1.955 3.130 2.465 ;
        RECT 2.115 1.785 3.130 1.955 ;
        RECT 0.875 1.445 1.580 1.615 ;
        RECT 1.410 0.830 1.580 1.445 ;
        RECT 0.595 0.660 1.580 0.830 ;
        RECT 0.595 0.255 0.765 0.660 ;
  END
END sky130_fd_sc_hd__a2bb2oi_1
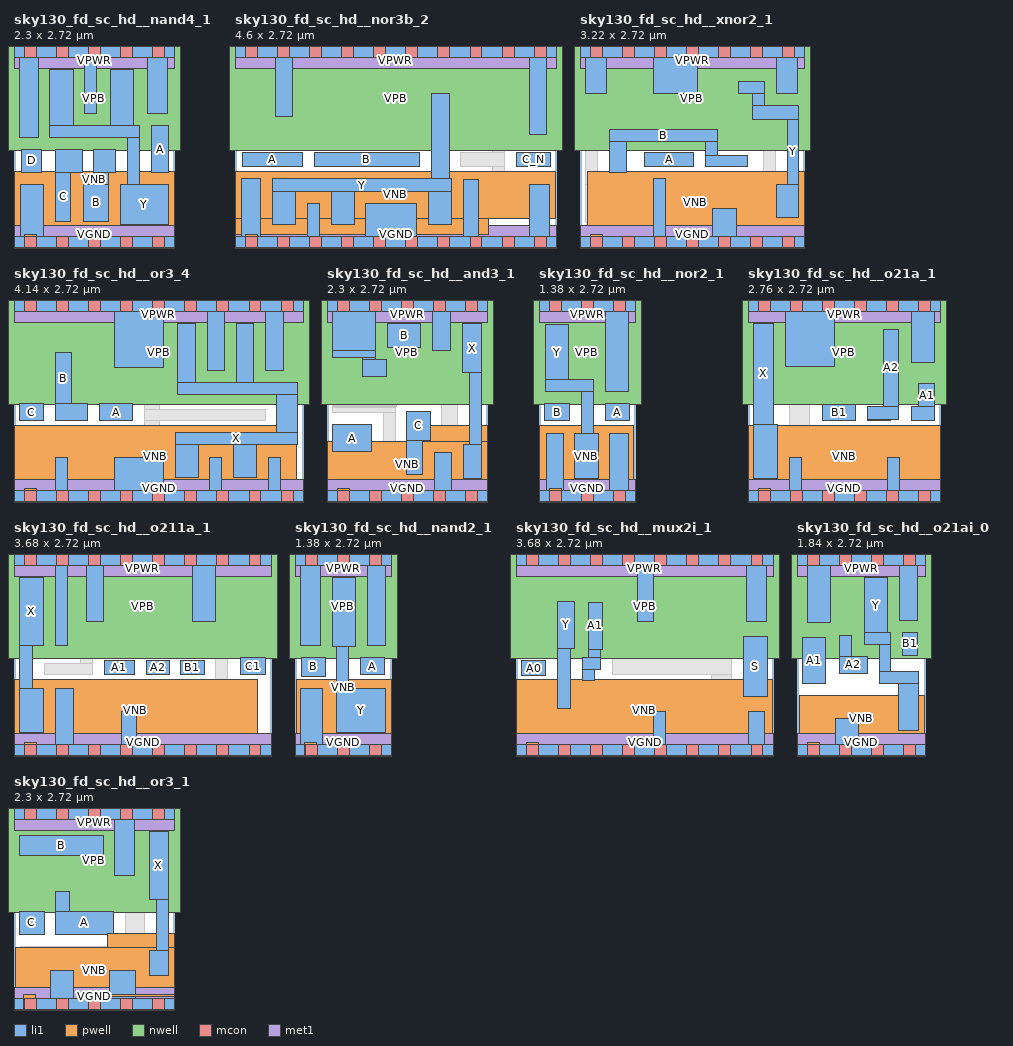
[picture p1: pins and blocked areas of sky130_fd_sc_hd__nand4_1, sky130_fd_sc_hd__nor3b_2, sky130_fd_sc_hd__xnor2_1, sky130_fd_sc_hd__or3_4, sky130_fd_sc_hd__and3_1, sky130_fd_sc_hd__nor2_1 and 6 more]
MACRO sky130_fd_sc_hd__nand4_1
  CLASS BLOCK ;
  FOREIGN sky130_fd_sc_hd__nand4_1 ;
  ORIGIN 0.000 0.000 ;
  SIZE 2.300 BY 2.720 ;
  PIN C
    ANTENNAGATEAREA 0.247500 ;
    PORT
      LAYER li1 ;
        RECT 0.595 0.995 0.975 1.325 ;
        RECT 0.595 0.300 0.810 0.995 ;
    END
  END C
  PIN B
    ANTENNAGATEAREA 0.247500 ;
    PORT
      LAYER li1 ;
        RECT 1.145 0.995 1.455 1.325 ;
        RECT 1.145 0.825 1.350 0.995 ;
        RECT 1.000 0.300 1.350 0.825 ;
    END
  END B
  PIN Y
    ANTENNADIFFAREA 0.795000 ;
    PORT
      LAYER li1 ;
        RECT 0.515 1.665 0.845 2.465 ;
        RECT 1.385 1.665 1.715 2.465 ;
        RECT 0.515 1.495 1.795 1.665 ;
        RECT 1.625 0.825 1.795 1.495 ;
        RECT 1.520 0.255 2.215 0.825 ;
    END
  END Y
  PIN D
    ANTENNAGATEAREA 0.247500 ;
    PORT
      LAYER li1 ;
        RECT 0.110 0.995 0.395 1.325 ;
    END
  END D
  PIN A
    ANTENNAGATEAREA 0.247500 ;
    PORT
      LAYER li1 ;
        RECT 1.975 0.995 2.215 1.665 ;
    END
  END A
  PIN VNB
    PORT
      LAYER pwell ;
        RECT 0.005 0.105 2.295 1.015 ;
        RECT 0.150 -0.085 0.320 0.105 ;
    END
  END VNB
  PIN VPB
    PORT
      LAYER nwell ;
        RECT -0.190 1.305 2.490 2.910 ;
    END
  END VPB
  PIN VPWR
    USE POWER ;
    PORT
      LAYER li1 ;
        RECT 0.000 2.635 2.300 2.805 ;
        RECT 0.085 1.495 0.345 2.635 ;
        RECT 1.015 1.835 1.185 2.635 ;
        RECT 1.915 1.835 2.195 2.635 ;
      LAYER mcon ;
        RECT 0.145 2.635 0.315 2.805 ;
        RECT 0.605 2.635 0.775 2.805 ;
        RECT 1.065 2.635 1.235 2.805 ;
        RECT 1.525 2.635 1.695 2.805 ;
        RECT 1.985 2.635 2.155 2.805 ;
      LAYER met1 ;
        RECT 0.000 2.480 2.300 2.960 ;
    END
  END VPWR
  PIN VGND
    USE GROUND ;
    PORT
      LAYER li1 ;
        RECT 0.090 0.085 0.425 0.825 ;
        RECT 0.000 -0.085 2.300 0.085 ;
      LAYER mcon ;
        RECT 0.145 -0.085 0.315 0.085 ;
        RECT 0.605 -0.085 0.775 0.085 ;
        RECT 1.065 -0.085 1.235 0.085 ;
        RECT 1.525 -0.085 1.695 0.085 ;
        RECT 1.985 -0.085 2.155 0.085 ;
      LAYER met1 ;
        RECT 0.000 -0.240 2.300 0.240 ;
    END
  END VGND
END sky130_fd_sc_hd__nand4_1
MACRO sky130_fd_sc_hd__nor3b_2
  CLASS BLOCK ;
  FOREIGN sky130_fd_sc_hd__nor3b_2 ;
  ORIGIN 0.000 0.000 ;
  SIZE 4.600 BY 2.720 ;
  PIN C_N
    ANTENNAGATEAREA 0.126000 ;
    PORT
      LAYER li1 ;
        RECT 4.030 1.075 4.515 1.285 ;
    END
  END C_N
  PIN Y
    ANTENNADIFFAREA 0.796500 ;
    PORT
      LAYER li1 ;
        RECT 2.815 0.905 3.065 2.125 ;
        RECT 0.535 0.725 3.105 0.905 ;
        RECT 0.535 0.255 0.865 0.725 ;
        RECT 1.375 0.255 1.705 0.725 ;
        RECT 2.775 0.255 3.105 0.725 ;
    END
  END Y
  PIN A
    ANTENNAGATEAREA 0.495000 ;
    PORT
      LAYER li1 ;
        RECT 0.110 1.075 0.965 1.285 ;
    END
  END A
  PIN B
    ANTENNAGATEAREA 0.495000 ;
    PORT
      LAYER li1 ;
        RECT 1.135 1.075 2.640 1.285 ;
    END
  END B
  PIN VNB
    PORT
      LAYER pwell ;
        RECT 0.005 0.335 4.595 1.015 ;
        RECT 0.005 0.105 3.635 0.335 ;
        RECT 0.150 -0.085 0.320 0.105 ;
    END
  END VNB
  PIN VPB
    PORT
      LAYER nwell ;
        RECT -0.190 1.305 4.790 2.910 ;
    END
  END VPB
  PIN VGND
    USE GROUND ;
    PORT
      LAYER li1 ;
        RECT 0.090 0.085 0.365 0.905 ;
        RECT 1.035 0.085 1.205 0.555 ;
        RECT 1.875 0.085 2.605 0.555 ;
        RECT 3.275 0.085 3.480 0.895 ;
        RECT 4.215 0.085 4.505 0.825 ;
        RECT 0.000 -0.085 4.600 0.085 ;
      LAYER mcon ;
        RECT 0.145 -0.085 0.315 0.085 ;
        RECT 0.605 -0.085 0.775 0.085 ;
        RECT 1.065 -0.085 1.235 0.085 ;
        RECT 1.525 -0.085 1.695 0.085 ;
        RECT 1.985 -0.085 2.155 0.085 ;
        RECT 2.445 -0.085 2.615 0.085 ;
        RECT 2.905 -0.085 3.075 0.085 ;
        RECT 3.365 -0.085 3.535 0.085 ;
        RECT 3.825 -0.085 3.995 0.085 ;
        RECT 4.285 -0.085 4.455 0.085 ;
      LAYER met1 ;
        RECT 0.000 -0.240 4.600 0.240 ;
    END
  END VGND
  PIN VPWR
    USE POWER ;
    PORT
      LAYER li1 ;
        RECT 0.000 2.635 4.600 2.805 ;
        RECT 0.575 1.795 0.825 2.635 ;
        RECT 4.215 1.540 4.465 2.635 ;
      LAYER mcon ;
        RECT 0.145 2.635 0.315 2.805 ;
        RECT 0.605 2.635 0.775 2.805 ;
        RECT 1.065 2.635 1.235 2.805 ;
        RECT 1.525 2.635 1.695 2.805 ;
        RECT 1.985 2.635 2.155 2.805 ;
        RECT 2.445 2.635 2.615 2.805 ;
        RECT 2.905 2.635 3.075 2.805 ;
        RECT 3.365 2.635 3.535 2.805 ;
        RECT 3.825 2.635 3.995 2.805 ;
        RECT 4.285 2.635 4.455 2.805 ;
      LAYER met1 ;
        RECT 0.000 2.480 4.600 2.960 ;
    END
  END VPWR
  OBS
      LAYER li1 ;
        RECT 0.090 1.625 0.405 2.465 ;
        RECT 0.995 1.625 1.245 2.465 ;
        RECT 1.415 2.295 3.480 2.465 ;
        RECT 1.415 1.795 1.665 2.295 ;
        RECT 1.835 1.625 2.085 2.125 ;
        RECT 0.090 1.455 2.085 1.625 ;
        RECT 2.375 1.455 2.645 2.295 ;
        RECT 3.235 1.455 3.480 2.295 ;
        RECT 3.690 1.455 4.045 1.870 ;
        RECT 3.690 1.285 3.860 1.455 ;
        RECT 3.235 1.075 3.860 1.285 ;
        RECT 3.690 0.905 3.860 1.075 ;
        RECT 3.690 0.380 4.045 0.905 ;
  END
END sky130_fd_sc_hd__nor3b_2
MACRO sky130_fd_sc_hd__xnor2_1
  CLASS BLOCK ;
  FOREIGN sky130_fd_sc_hd__xnor2_1 ;
  ORIGIN 0.000 0.000 ;
  SIZE 3.220 BY 2.720 ;
  PIN B
    ANTENNAGATEAREA 0.495000 ;
    PORT
      LAYER li1 ;
        RECT 0.425 1.445 1.965 1.615 ;
        RECT 0.425 0.995 0.670 1.445 ;
        RECT 1.795 1.245 1.965 1.445 ;
        RECT 1.795 1.075 2.395 1.245 ;
    END
  END B
  PIN Y
    ANTENNADIFFAREA 0.525000 ;
    PORT
      LAYER li1 ;
        RECT 2.265 2.125 2.645 2.295 ;
        RECT 2.475 1.955 2.645 2.125 ;
        RECT 2.475 1.755 3.135 1.955 ;
        RECT 2.965 0.825 3.135 1.755 ;
        RECT 2.815 0.345 3.135 0.825 ;
    END
  END Y
  PIN A
    ANTENNAGATEAREA 0.495000 ;
    PORT
      LAYER li1 ;
        RECT 0.930 1.075 1.625 1.275 ;
    END
  END A
  PIN VNB
    PORT
      LAYER pwell ;
        RECT 0.105 0.105 3.215 1.015 ;
        RECT 0.145 -0.085 0.315 0.105 ;
    END
  END VNB
  PIN VPB
    PORT
      LAYER nwell ;
        RECT -0.190 1.305 3.410 2.910 ;
    END
  END VPB
  PIN VGND
    USE GROUND ;
    PORT
      LAYER li1 ;
        RECT 1.055 0.085 1.225 0.905 ;
        RECT 1.895 0.085 2.245 0.475 ;
        RECT 0.000 -0.085 3.220 0.085 ;
      LAYER mcon ;
        RECT 0.145 -0.085 0.315 0.085 ;
        RECT 0.605 -0.085 0.775 0.085 ;
        RECT 1.065 -0.085 1.235 0.085 ;
        RECT 1.525 -0.085 1.695 0.085 ;
        RECT 1.985 -0.085 2.155 0.085 ;
        RECT 2.445 -0.085 2.615 0.085 ;
        RECT 2.905 -0.085 3.075 0.085 ;
      LAYER met1 ;
        RECT 0.000 -0.240 3.220 0.240 ;
    END
  END VGND
  PIN VPWR
    USE POWER ;
    PORT
      LAYER li1 ;
        RECT 0.000 2.635 3.220 2.805 ;
        RECT 0.085 2.125 0.385 2.635 ;
        RECT 1.055 2.125 1.685 2.635 ;
        RECT 2.815 2.125 3.115 2.635 ;
      LAYER mcon ;
        RECT 0.145 2.635 0.315 2.805 ;
        RECT 0.605 2.635 0.775 2.805 ;
        RECT 1.065 2.635 1.235 2.805 ;
        RECT 1.525 2.635 1.695 2.805 ;
        RECT 1.985 2.635 2.155 2.805 ;
        RECT 2.445 2.635 2.615 2.805 ;
        RECT 2.905 2.635 3.075 2.805 ;
      LAYER met1 ;
        RECT 0.000 2.480 3.220 2.960 ;
    END
  END VPWR
  OBS
      LAYER li1 ;
        RECT 0.555 1.955 0.885 2.465 ;
        RECT 0.085 1.785 2.305 1.955 ;
        RECT 0.085 0.825 0.255 1.785 ;
        RECT 2.135 1.585 2.305 1.785 ;
        RECT 2.135 1.415 2.795 1.585 ;
        RECT 2.625 0.995 2.795 1.415 ;
        RECT 1.395 0.825 2.305 0.905 ;
        RECT 0.085 0.280 0.550 0.825 ;
        RECT 1.395 0.735 2.645 0.825 ;
        RECT 1.395 0.255 1.725 0.735 ;
        RECT 2.135 0.655 2.645 0.735 ;
        RECT 2.415 0.255 2.645 0.655 ;
  END
END sky130_fd_sc_hd__xnor2_1
MACRO sky130_fd_sc_hd__or3_4
  CLASS BLOCK ;
  FOREIGN sky130_fd_sc_hd__or3_4 ;
  ORIGIN 0.000 0.000 ;
  SIZE 4.140 BY 2.720 ;
  PIN A
    ANTENNAGATEAREA 0.247500 ;
    PORT
      LAYER li1 ;
        RECT 1.225 1.075 1.700 1.325 ;
    END
  END A
  PIN X
    ANTENNADIFFAREA 0.891000 ;
    PORT
      LAYER li1 ;
        RECT 2.345 1.625 2.595 2.465 ;
        RECT 3.185 1.625 3.435 2.465 ;
        RECT 2.345 1.455 4.055 1.625 ;
        RECT 3.765 0.905 4.055 1.455 ;
        RECT 2.305 0.735 4.055 0.905 ;
        RECT 2.305 0.265 2.635 0.735 ;
        RECT 3.145 0.265 3.475 0.735 ;
    END
  END X
  PIN B
    ANTENNAGATEAREA 0.247500 ;
    PORT
      LAYER li1 ;
        RECT 0.595 1.325 0.830 2.050 ;
        RECT 0.595 1.075 1.055 1.325 ;
    END
  END B
  PIN C
    ANTENNAGATEAREA 0.247500 ;
    PORT
      LAYER li1 ;
        RECT 0.085 1.075 0.425 1.325 ;
    END
  END C
  PIN VNB
    PORT
      LAYER pwell ;
        RECT 0.005 0.105 4.040 1.015 ;
        RECT 0.150 -0.085 0.320 0.105 ;
    END
  END VNB
  PIN VPB
    PORT
      LAYER nwell ;
        RECT -0.190 1.305 4.330 2.910 ;
    END
  END VPB
  PIN VPWR
    USE POWER ;
    PORT
      LAYER li1 ;
        RECT 0.000 2.635 4.140 2.805 ;
        RECT 1.435 1.835 2.135 2.635 ;
        RECT 2.765 1.795 3.015 2.635 ;
        RECT 3.605 1.795 3.855 2.635 ;
      LAYER mcon ;
        RECT 0.145 2.635 0.315 2.805 ;
        RECT 0.605 2.635 0.775 2.805 ;
        RECT 1.065 2.635 1.235 2.805 ;
        RECT 1.525 2.635 1.695 2.805 ;
        RECT 1.985 2.635 2.155 2.805 ;
        RECT 2.445 2.635 2.615 2.805 ;
        RECT 2.905 2.635 3.075 2.805 ;
        RECT 3.365 2.635 3.535 2.805 ;
        RECT 3.825 2.635 3.995 2.805 ;
      LAYER met1 ;
        RECT 0.000 2.480 4.140 2.960 ;
    END
  END VPWR
  PIN VGND
    USE GROUND ;
    PORT
      LAYER li1 ;
        RECT 0.595 0.085 0.765 0.555 ;
        RECT 1.435 0.085 2.135 0.555 ;
        RECT 2.805 0.085 2.975 0.555 ;
        RECT 3.645 0.085 3.815 0.555 ;
        RECT 0.000 -0.085 4.140 0.085 ;
      LAYER mcon ;
        RECT 0.145 -0.085 0.315 0.085 ;
        RECT 0.605 -0.085 0.775 0.085 ;
        RECT 1.065 -0.085 1.235 0.085 ;
        RECT 1.525 -0.085 1.695 0.085 ;
        RECT 1.985 -0.085 2.155 0.085 ;
        RECT 2.445 -0.085 2.615 0.085 ;
        RECT 2.905 -0.085 3.075 0.085 ;
        RECT 3.365 -0.085 3.535 0.085 ;
        RECT 3.825 -0.085 3.995 0.085 ;
      LAYER met1 ;
        RECT 0.000 -0.240 4.140 0.240 ;
    END
  END VGND
  OBS
      LAYER li1 ;
        RECT 0.085 2.295 1.265 2.465 ;
        RECT 0.085 1.495 0.425 2.295 ;
        RECT 1.000 1.665 1.265 2.295 ;
        RECT 1.000 1.495 2.090 1.665 ;
        RECT 1.870 1.245 2.090 1.495 ;
        RECT 1.870 1.075 3.595 1.245 ;
        RECT 1.870 0.905 2.090 1.075 ;
        RECT 0.085 0.725 2.090 0.905 ;
        RECT 0.085 0.255 0.425 0.725 ;
        RECT 0.935 0.255 1.265 0.725 ;
  END
END sky130_fd_sc_hd__or3_4
MACRO sky130_fd_sc_hd__and3_1
  CLASS BLOCK ;
  FOREIGN sky130_fd_sc_hd__and3_1 ;
  ORIGIN 0.000 0.000 ;
  SIZE 2.300 BY 2.720 ;
  PIN X
    ANTENNADIFFAREA 0.429000 ;
    PORT
      LAYER li1 ;
        RECT 1.940 1.765 2.215 2.465 ;
        RECT 2.045 0.735 2.215 1.765 ;
        RECT 1.955 0.255 2.215 0.735 ;
    END
  END X
  PIN B
    ANTENNAGATEAREA 0.126000 ;
    PORT
      LAYER li1 ;
        RECT 0.865 2.125 1.345 2.465 ;
    END
  END B
  PIN A
    ANTENNAGATEAREA 0.126000 ;
    PORT
      LAYER li1 ;
        RECT 0.085 0.635 0.635 1.020 ;
    END
  END A
  PIN C
    ANTENNAGATEAREA 0.126000 ;
    PORT
      LAYER li1 ;
        RECT 1.145 0.790 1.475 1.215 ;
        RECT 1.145 0.305 1.365 0.790 ;
    END
  END C
  PIN VNB
    PORT
      LAYER pwell ;
        RECT 1.375 0.785 2.295 1.015 ;
        RECT 0.005 0.105 2.295 0.785 ;
        RECT 0.145 -0.085 0.315 0.105 ;
    END
  END VNB
  PIN VPB
    PORT
      LAYER nwell ;
        RECT -0.190 1.305 2.490 2.910 ;
    END
  END VPB
  PIN VGND
    USE GROUND ;
    PORT
      LAYER li1 ;
        RECT 1.535 0.085 1.785 0.625 ;
        RECT 0.000 -0.085 2.300 0.085 ;
      LAYER mcon ;
        RECT 0.145 -0.085 0.315 0.085 ;
        RECT 0.605 -0.085 0.775 0.085 ;
        RECT 1.065 -0.085 1.235 0.085 ;
        RECT 1.525 -0.085 1.695 0.085 ;
        RECT 1.985 -0.085 2.155 0.085 ;
      LAYER met1 ;
        RECT 0.000 -0.240 2.300 0.240 ;
    END
  END VGND
  PIN VPWR
    USE POWER ;
    PORT
      LAYER li1 ;
        RECT 0.000 2.635 2.300 2.805 ;
        RECT 0.085 2.080 0.690 2.635 ;
        RECT 1.515 2.090 1.770 2.635 ;
        RECT 0.085 1.980 0.700 2.080 ;
        RECT 0.515 1.955 0.700 1.980 ;
        RECT 0.515 1.710 0.845 1.955 ;
      LAYER mcon ;
        RECT 0.145 2.635 0.315 2.805 ;
        RECT 0.605 2.635 0.775 2.805 ;
        RECT 1.065 2.635 1.235 2.805 ;
        RECT 1.525 2.635 1.695 2.805 ;
        RECT 1.985 2.635 2.155 2.805 ;
      LAYER met1 ;
        RECT 0.000 2.480 2.300 2.960 ;
    END
  END VPWR
  OBS
      LAYER li1 ;
        RECT 0.085 1.360 0.345 1.810 ;
        RECT 1.015 1.635 1.770 1.885 ;
        RECT 1.000 1.600 1.770 1.635 ;
        RECT 0.985 1.590 1.770 1.600 ;
        RECT 0.980 1.575 1.875 1.590 ;
        RECT 0.960 1.560 1.875 1.575 ;
        RECT 0.940 1.550 1.875 1.560 ;
        RECT 0.915 1.540 1.875 1.550 ;
        RECT 0.845 1.510 1.875 1.540 ;
        RECT 0.825 1.480 1.875 1.510 ;
        RECT 0.805 1.450 1.875 1.480 ;
        RECT 0.775 1.425 1.875 1.450 ;
        RECT 0.740 1.390 1.875 1.425 ;
        RECT 0.710 1.385 1.875 1.390 ;
        RECT 0.710 1.380 1.100 1.385 ;
        RECT 0.710 1.370 1.075 1.380 ;
        RECT 0.710 1.365 1.060 1.370 ;
        RECT 0.710 1.360 1.045 1.365 ;
        RECT 0.085 1.355 1.045 1.360 ;
        RECT 0.085 1.345 1.035 1.355 ;
        RECT 0.085 1.340 1.025 1.345 ;
        RECT 0.085 1.330 1.015 1.340 ;
        RECT 0.085 1.320 1.010 1.330 ;
        RECT 0.085 1.315 1.005 1.320 ;
        RECT 0.085 1.300 0.995 1.315 ;
        RECT 0.085 1.285 0.990 1.300 ;
        RECT 0.085 1.260 0.980 1.285 ;
        RECT 0.085 1.190 0.975 1.260 ;
        RECT 0.805 0.465 0.975 1.190 ;
        RECT 1.645 0.990 1.875 1.385 ;
        RECT 0.085 0.295 0.975 0.465 ;
  END
END sky130_fd_sc_hd__and3_1
MACRO sky130_fd_sc_hd__nor2_1
  CLASS BLOCK ;
  FOREIGN sky130_fd_sc_hd__nor2_1 ;
  ORIGIN 0.000 0.000 ;
  SIZE 1.380 BY 2.720 ;
  PIN B
    ANTENNAGATEAREA 0.247500 ;
    PORT
      LAYER li1 ;
        RECT 0.085 1.075 0.435 1.325 ;
    END
  END B
  PIN Y
    ANTENNADIFFAREA 0.435500 ;
    PORT
      LAYER li1 ;
        RECT 0.095 1.665 0.425 2.450 ;
        RECT 0.095 1.495 0.775 1.665 ;
        RECT 0.605 0.895 0.775 1.495 ;
        RECT 0.515 0.255 0.845 0.895 ;
    END
  END Y
  PIN A
    ANTENNAGATEAREA 0.247500 ;
    PORT
      LAYER li1 ;
        RECT 0.945 1.075 1.295 1.325 ;
    END
  END A
  PIN VNB
    PORT
      LAYER pwell ;
        RECT 0.005 0.105 1.355 1.015 ;
        RECT 0.150 -0.085 0.320 0.105 ;
    END
  END VNB
  PIN VPB
    PORT
      LAYER nwell ;
        RECT -0.190 1.305 1.570 2.910 ;
    END
  END VPB
  PIN VGND
    USE GROUND ;
    PORT
      LAYER li1 ;
        RECT 0.105 0.085 0.345 0.895 ;
        RECT 1.015 0.085 1.285 0.895 ;
        RECT 0.000 -0.085 1.380 0.085 ;
      LAYER mcon ;
        RECT 0.145 -0.085 0.315 0.085 ;
        RECT 0.605 -0.085 0.775 0.085 ;
        RECT 1.065 -0.085 1.235 0.085 ;
      LAYER met1 ;
        RECT 0.000 -0.240 1.380 0.240 ;
    END
  END VGND
  PIN VPWR
    USE POWER ;
    PORT
      LAYER li1 ;
        RECT 0.000 2.635 1.380 2.805 ;
        RECT 0.955 1.495 1.285 2.635 ;
      LAYER mcon ;
        RECT 0.145 2.635 0.315 2.805 ;
        RECT 0.605 2.635 0.775 2.805 ;
        RECT 1.065 2.635 1.235 2.805 ;
      LAYER met1 ;
        RECT 0.000 2.480 1.380 2.960 ;
    END
  END VPWR
END sky130_fd_sc_hd__nor2_1
MACRO sky130_fd_sc_hd__o21a_1
  CLASS BLOCK ;
  FOREIGN sky130_fd_sc_hd__o21a_1 ;
  ORIGIN 0.000 0.000 ;
  SIZE 2.760 BY 2.720 ;
  PIN X
    ANTENNADIFFAREA 0.449000 ;
    PORT
      LAYER li1 ;
        RECT 0.085 1.030 0.365 2.465 ;
        RECT 0.085 0.255 0.425 1.030 ;
    END
  END X
  PIN A1
    ANTENNAGATEAREA 0.247500 ;
    PORT
      LAYER li1 ;
        RECT 2.445 1.275 2.675 1.615 ;
        RECT 2.345 1.075 2.675 1.275 ;
    END
  END A1
  PIN B1
    ANTENNAGATEAREA 0.247500 ;
    PORT
      LAYER li1 ;
        RECT 1.065 1.075 1.535 1.305 ;
    END
  END B1
  PIN A2
    ANTENNAGATEAREA 0.247500 ;
    PORT
      LAYER li1 ;
        RECT 1.940 1.275 2.155 2.390 ;
        RECT 1.705 1.095 2.155 1.275 ;
        RECT 1.705 1.075 2.035 1.095 ;
    END
  END A2
  PIN VNB
    PORT
      LAYER pwell ;
        RECT 0.005 0.105 2.755 1.015 ;
        RECT 0.145 -0.085 0.315 0.105 ;
    END
  END VNB
  PIN VPB
    PORT
      LAYER nwell ;
        RECT -0.190 1.305 2.950 2.910 ;
    END
  END VPB
  PIN VGND
    USE GROUND ;
    PORT
      LAYER li1 ;
        RECT 0.595 0.085 0.765 0.545 ;
        RECT 1.995 0.085 2.165 0.545 ;
        RECT 0.000 -0.085 2.760 0.085 ;
      LAYER mcon ;
        RECT 0.145 -0.085 0.315 0.085 ;
        RECT 0.605 -0.085 0.775 0.085 ;
        RECT 1.065 -0.085 1.235 0.085 ;
        RECT 1.525 -0.085 1.695 0.085 ;
        RECT 1.985 -0.085 2.155 0.085 ;
        RECT 2.445 -0.085 2.615 0.085 ;
      LAYER met1 ;
        RECT 0.000 -0.240 2.760 0.240 ;
    END
  END VGND
  PIN VPWR
    USE POWER ;
    PORT
      LAYER li1 ;
        RECT 0.000 2.635 2.760 2.805 ;
        RECT 0.535 1.860 1.245 2.635 ;
        RECT 2.335 1.915 2.665 2.635 ;
      LAYER mcon ;
        RECT 0.145 2.635 0.315 2.805 ;
        RECT 0.605 2.635 0.775 2.805 ;
        RECT 1.065 2.635 1.235 2.805 ;
        RECT 1.525 2.635 1.695 2.805 ;
        RECT 1.985 2.635 2.155 2.805 ;
        RECT 2.445 2.635 2.615 2.805 ;
      LAYER met1 ;
        RECT 0.000 2.480 2.760 2.960 ;
    END
  END VPWR
  OBS
      LAYER li1 ;
        RECT 1.415 1.690 1.745 2.465 ;
        RECT 0.595 1.475 1.745 1.690 ;
        RECT 0.595 0.905 0.880 1.475 ;
        RECT 0.595 0.715 1.305 0.905 ;
        RECT 1.005 0.575 1.305 0.715 ;
        RECT 1.495 0.715 2.675 0.905 ;
        RECT 1.495 0.635 1.825 0.715 ;
        RECT 1.005 0.565 1.320 0.575 ;
        RECT 1.005 0.555 1.330 0.565 ;
        RECT 1.005 0.550 1.340 0.555 ;
        RECT 1.005 0.540 1.345 0.550 ;
        RECT 1.005 0.535 1.350 0.540 ;
        RECT 1.005 0.525 1.355 0.535 ;
        RECT 1.005 0.520 1.360 0.525 ;
        RECT 1.005 0.255 1.365 0.520 ;
        RECT 2.335 0.255 2.675 0.715 ;
  END
END sky130_fd_sc_hd__o21a_1
MACRO sky130_fd_sc_hd__o211a_1
  CLASS BLOCK ;
  FOREIGN sky130_fd_sc_hd__o211a_1 ;
  ORIGIN 0.000 0.000 ;
  SIZE 3.680 BY 2.720 ;
  PIN C1
    ANTENNAGATEAREA 0.247500 ;
    PORT
      LAYER li1 ;
        RECT 3.245 1.075 3.595 1.325 ;
    END
  END C1
  PIN B1
    ANTENNAGATEAREA 0.247500 ;
    PORT
      LAYER li1 ;
        RECT 2.390 1.075 2.720 1.275 ;
    END
  END B1
  PIN A2
    ANTENNAGATEAREA 0.247500 ;
    PORT
      LAYER li1 ;
        RECT 1.890 1.075 2.220 1.275 ;
    END
  END A2
  PIN A1
    ANTENNAGATEAREA 0.247500 ;
    PORT
      LAYER li1 ;
        RECT 1.300 1.075 1.720 1.275 ;
    END
  END A1
  PIN X
    ANTENNADIFFAREA 0.429000 ;
    PORT
      LAYER li1 ;
        RECT 0.085 1.495 0.425 2.465 ;
        RECT 0.085 0.885 0.260 1.495 ;
        RECT 0.085 0.255 0.425 0.885 ;
    END
  END X
  PIN VNB
    PORT
      LAYER pwell ;
        RECT 0.005 0.105 3.480 1.015 ;
        RECT 0.150 -0.085 0.320 0.105 ;
    END
  END VNB
  PIN VPB
    PORT
      LAYER nwell ;
        RECT -0.190 1.305 3.870 2.910 ;
    END
  END VPB
  PIN VGND
    USE GROUND ;
    PORT
      LAYER li1 ;
        RECT 0.595 0.085 0.845 0.885 ;
        RECT 1.535 0.085 1.760 0.545 ;
        RECT 0.000 -0.085 3.680 0.085 ;
      LAYER mcon ;
        RECT 0.145 -0.085 0.315 0.085 ;
        RECT 0.605 -0.085 0.775 0.085 ;
        RECT 1.065 -0.085 1.235 0.085 ;
        RECT 1.525 -0.085 1.695 0.085 ;
        RECT 1.985 -0.085 2.155 0.085 ;
        RECT 2.445 -0.085 2.615 0.085 ;
        RECT 2.905 -0.085 3.075 0.085 ;
        RECT 3.365 -0.085 3.535 0.085 ;
      LAYER met1 ;
        RECT 0.000 -0.240 3.680 0.240 ;
    END
  END VGND
  PIN VPWR
    USE POWER ;
    PORT
      LAYER li1 ;
        RECT 0.000 2.635 3.680 2.805 ;
        RECT 0.595 1.495 0.765 2.635 ;
        RECT 1.035 1.835 1.285 2.635 ;
        RECT 2.560 1.835 2.890 2.635 ;
      LAYER mcon ;
        RECT 0.145 2.635 0.315 2.805 ;
        RECT 0.605 2.635 0.775 2.805 ;
        RECT 1.065 2.635 1.235 2.805 ;
        RECT 1.525 2.635 1.695 2.805 ;
        RECT 1.985 2.635 2.155 2.805 ;
        RECT 2.445 2.635 2.615 2.805 ;
        RECT 2.905 2.635 3.075 2.805 ;
        RECT 3.365 2.635 3.535 2.805 ;
      LAYER met1 ;
        RECT 0.000 2.480 3.680 2.960 ;
    END
  END VPWR
  OBS
      LAYER li1 ;
        RECT 1.930 1.665 2.260 2.465 ;
        RECT 3.060 1.665 3.390 2.465 ;
        RECT 0.955 1.495 3.390 1.665 ;
        RECT 0.955 1.245 1.125 1.495 ;
        RECT 0.430 1.075 1.125 1.245 ;
        RECT 1.035 0.735 2.260 0.905 ;
        RECT 1.035 0.255 1.365 0.735 ;
        RECT 1.930 0.255 2.260 0.735 ;
        RECT 2.890 0.865 3.060 1.495 ;
        RECT 2.890 0.255 3.390 0.865 ;
  END
END sky130_fd_sc_hd__o211a_1
MACRO sky130_fd_sc_hd__nand2_1
  CLASS BLOCK ;
  FOREIGN sky130_fd_sc_hd__nand2_1 ;
  ORIGIN 0.000 0.000 ;
  SIZE 1.380 BY 2.720 ;
  PIN Y
    ANTENNADIFFAREA 0.439000 ;
    PORT
      LAYER li1 ;
        RECT 0.535 1.485 0.865 2.465 ;
        RECT 0.600 0.885 0.770 1.485 ;
        RECT 0.600 0.255 1.295 0.885 ;
    END
  END Y
  PIN B
    ANTENNAGATEAREA 0.247500 ;
    PORT
      LAYER li1 ;
        RECT 0.095 1.055 0.430 1.325 ;
    END
  END B
  PIN A
    ANTENNAGATEAREA 0.247500 ;
    PORT
      LAYER li1 ;
        RECT 0.940 1.075 1.275 1.325 ;
    END
  END A
  PIN VNB
    PORT
      LAYER pwell ;
        RECT 0.025 0.105 1.375 1.015 ;
        RECT 0.140 -0.085 0.310 0.105 ;
    END
  END VNB
  PIN VPB
    PORT
      LAYER nwell ;
        RECT -0.190 1.305 1.570 2.910 ;
    END
  END VPB
  PIN VGND
    USE GROUND ;
    PORT
      LAYER li1 ;
        RECT 0.085 0.085 0.395 0.885 ;
        RECT 0.000 -0.085 1.380 0.085 ;
      LAYER mcon ;
        RECT 0.145 -0.085 0.315 0.085 ;
        RECT 0.605 -0.085 0.775 0.085 ;
        RECT 1.065 -0.085 1.235 0.085 ;
      LAYER met1 ;
        RECT 0.000 -0.240 1.380 0.240 ;
    END
  END VGND
  PIN VPWR
    USE POWER ;
    PORT
      LAYER li1 ;
        RECT 0.000 2.635 1.380 2.805 ;
        RECT 0.085 1.495 0.365 2.635 ;
        RECT 1.035 1.495 1.295 2.635 ;
      LAYER mcon ;
        RECT 0.145 2.635 0.315 2.805 ;
        RECT 0.605 2.635 0.775 2.805 ;
        RECT 1.065 2.635 1.235 2.805 ;
      LAYER met1 ;
        RECT 0.000 2.480 1.380 2.960 ;
    END
  END VPWR
END sky130_fd_sc_hd__nand2_1
MACRO VIA_via4_1600x1600
  CLASS BLOCK ;
  FOREIGN VIA_via4_1600x1600 ;
  ORIGIN 0.800 0.800 ;
  SIZE 1.600 BY 1.600 ;
  OBS
      LAYER met4 ;
        RECT -0.800 -0.800 0.800 0.800 ;
      LAYER via4 ;
        RECT -0.590 -0.590 0.590 0.590 ;
      LAYER met5 ;
        RECT -0.800 -0.800 0.800 0.800 ;
  END
END VIA_via4_1600x1600
MACRO sky130_fd_sc_hd__mux2i_1
  CLASS BLOCK ;
  FOREIGN sky130_fd_sc_hd__mux2i_1 ;
  ORIGIN 0.000 0.000 ;
  SIZE 3.680 BY 2.720 ;
  PIN A1
    ANTENNAGATEAREA 0.247500 ;
    PORT
      LAYER li1 ;
        RECT 1.035 1.445 1.235 2.110 ;
        RECT 1.035 1.325 1.205 1.445 ;
        RECT 0.955 1.155 1.205 1.325 ;
        RECT 0.955 0.995 1.125 1.155 ;
    END
  END A1
  PIN S
    ANTENNAGATEAREA 0.495000 ;
    PORT
      LAYER li1 ;
        RECT 3.260 0.760 3.595 1.620 ;
    END
  END S
  PIN A0
    ANTENNAGATEAREA 0.247500 ;
    PORT
      LAYER li1 ;
        RECT 0.085 1.060 0.420 1.285 ;
    END
  END A0
  PIN Y
    ANTENNADIFFAREA 0.480500 ;
    PORT
      LAYER li1 ;
        RECT 0.590 1.455 0.840 2.125 ;
        RECT 0.590 0.595 0.780 1.455 ;
    END
  END Y
  PIN VNB
    PORT
      LAYER pwell ;
        RECT 0.005 0.105 3.675 1.015 ;
        RECT 0.145 -0.085 0.315 0.105 ;
    END
  END VNB
  PIN VPB
    PORT
      LAYER nwell ;
        RECT -0.190 1.305 3.870 2.910 ;
    END
  END VPB
  PIN VGND
    USE GROUND ;
    PORT
      LAYER li1 ;
        RECT 1.975 0.085 2.145 0.545 ;
        RECT 3.335 0.085 3.555 0.545 ;
        RECT 0.000 -0.085 3.680 0.085 ;
      LAYER mcon ;
        RECT 0.145 -0.085 0.315 0.085 ;
        RECT 0.605 -0.085 0.775 0.085 ;
        RECT 1.065 -0.085 1.235 0.085 ;
        RECT 1.525 -0.085 1.695 0.085 ;
        RECT 1.985 -0.085 2.155 0.085 ;
        RECT 2.445 -0.085 2.615 0.085 ;
        RECT 2.905 -0.085 3.075 0.085 ;
        RECT 3.365 -0.085 3.535 0.085 ;
      LAYER met1 ;
        RECT 0.000 -0.240 3.680 0.240 ;
    END
  END VGND
  PIN VPWR
    USE POWER ;
    PORT
      LAYER li1 ;
        RECT 0.000 2.635 3.680 2.805 ;
        RECT 1.745 1.835 1.975 2.635 ;
        RECT 3.295 1.835 3.590 2.635 ;
      LAYER mcon ;
        RECT 0.145 2.635 0.315 2.805 ;
        RECT 0.605 2.635 0.775 2.805 ;
        RECT 1.065 2.635 1.235 2.805 ;
        RECT 1.525 2.635 1.695 2.805 ;
        RECT 1.985 2.635 2.155 2.805 ;
        RECT 2.445 2.635 2.615 2.805 ;
        RECT 2.905 2.635 3.075 2.805 ;
        RECT 3.365 2.635 3.535 2.805 ;
      LAYER met1 ;
        RECT 0.000 2.480 3.680 2.960 ;
    END
  END VPWR
  OBS
      LAYER li1 ;
        RECT 0.120 2.295 1.575 2.465 ;
        RECT 0.120 1.455 0.420 2.295 ;
        RECT 1.405 1.650 1.575 2.295 ;
        RECT 2.285 1.650 2.615 2.465 ;
        RECT 1.405 1.480 2.615 1.650 ;
        RECT 2.860 1.310 3.085 2.465 ;
        RECT 1.385 1.075 3.085 1.310 ;
        RECT 0.085 0.465 0.345 0.885 ;
        RECT 1.295 0.825 2.620 0.885 ;
        RECT 0.955 0.715 2.620 0.825 ;
        RECT 0.955 0.655 1.520 0.715 ;
        RECT 0.085 0.425 0.440 0.465 ;
        RECT 0.965 0.425 1.805 0.465 ;
        RECT 0.085 0.255 1.805 0.425 ;
        RECT 2.385 0.255 2.620 0.715 ;
        RECT 2.800 0.485 3.085 1.075 ;
        RECT 2.800 0.255 3.165 0.485 ;
  END
END sky130_fd_sc_hd__mux2i_1
MACRO VIA_via4_4200x1600
  CLASS BLOCK ;
  FOREIGN VIA_via4_4200x1600 ;
  ORIGIN 2.100 0.800 ;
  SIZE 4.200 BY 1.600 ;
  OBS
      LAYER met4 ;
        RECT -2.100 -0.800 2.100 0.800 ;
      LAYER via4 ;
        RECT -1.390 -0.590 -0.210 0.590 ;
        RECT 0.210 -0.590 1.390 0.590 ;
      LAYER met5 ;
        RECT -2.100 -0.800 2.100 0.800 ;
  END
END VIA_via4_4200x1600
MACRO sky130_fd_sc_hd__o21ai_0
  CLASS BLOCK ;
  FOREIGN sky130_fd_sc_hd__o21ai_0 ;
  ORIGIN 0.000 0.000 ;
  SIZE 1.840 BY 2.720 ;
  PIN Y
    ANTENNADIFFAREA 0.290500 ;
    PORT
      LAYER li1 ;
        RECT 0.965 1.680 1.300 2.465 ;
        RECT 0.965 1.510 1.345 1.680 ;
        RECT 1.175 1.125 1.345 1.510 ;
        RECT 1.175 0.955 1.740 1.125 ;
        RECT 1.455 0.280 1.740 0.955 ;
    END
  END Y
  PIN B1
    ANTENNAGATEAREA 0.159000 ;
    PORT
      LAYER li1 ;
        RECT 1.515 1.355 1.730 1.685 ;
    END
  END B1
  PIN A2
    ANTENNAGATEAREA 0.159000 ;
    PORT
      LAYER li1 ;
        RECT 0.605 1.340 0.775 1.645 ;
        RECT 0.605 1.100 1.005 1.340 ;
    END
  END A2
  PIN A1
    ANTENNAGATEAREA 0.159000 ;
    PORT
      LAYER li1 ;
        RECT 0.085 0.955 0.415 1.615 ;
    END
  END A1
  PIN VNB
    PORT
      LAYER pwell ;
        RECT 0.030 0.105 1.830 0.785 ;
        RECT 0.145 -0.085 0.315 0.105 ;
    END
  END VNB
  PIN VPB
    PORT
      LAYER nwell ;
        RECT -0.190 1.305 2.030 2.910 ;
    END
  END VPB
  PIN VGND
    USE GROUND ;
    PORT
      LAYER li1 ;
        RECT 0.550 0.085 0.880 0.445 ;
        RECT 0.000 -0.085 1.840 0.085 ;
      LAYER mcon ;
        RECT 0.145 -0.085 0.315 0.085 ;
        RECT 0.605 -0.085 0.775 0.085 ;
        RECT 1.065 -0.085 1.235 0.085 ;
        RECT 1.525 -0.085 1.695 0.085 ;
      LAYER met1 ;
        RECT 0.000 -0.240 1.840 0.240 ;
    END
  END VGND
  PIN VPWR
    USE POWER ;
    PORT
      LAYER li1 ;
        RECT 0.000 2.635 1.840 2.805 ;
        RECT 0.145 1.825 0.475 2.635 ;
        RECT 1.470 1.855 1.725 2.635 ;
      LAYER mcon ;
        RECT 0.145 2.635 0.315 2.805 ;
        RECT 0.605 2.635 0.775 2.805 ;
        RECT 1.065 2.635 1.235 2.805 ;
        RECT 1.525 2.635 1.695 2.805 ;
      LAYER met1 ;
        RECT 0.000 2.480 1.840 2.960 ;
    END
  END VPWR
  OBS
      LAYER li1 ;
        RECT 0.120 0.615 1.285 0.785 ;
        RECT 0.120 0.280 0.380 0.615 ;
        RECT 1.050 0.280 1.285 0.615 ;
  END
END sky130_fd_sc_hd__o21ai_0
MACRO sky130_fd_sc_hd__or3_1
  CLASS BLOCK ;
  FOREIGN sky130_fd_sc_hd__or3_1 ;
  ORIGIN 0.000 0.000 ;
  SIZE 2.300 BY 2.720 ;
  PIN A
    ANTENNAGATEAREA 0.126000 ;
    PORT
      LAYER li1 ;
        RECT 0.600 1.325 0.795 1.615 ;
        RECT 0.600 0.995 1.425 1.325 ;
    END
  END A
  PIN X
    ANTENNADIFFAREA 0.462000 ;
    PORT
      LAYER li1 ;
        RECT 1.935 1.495 2.210 2.465 ;
        RECT 2.040 0.760 2.210 1.495 ;
        RECT 1.935 0.415 2.210 0.760 ;
    END
  END X
  PIN B
    ANTENNAGATEAREA 0.126000 ;
    PORT
      LAYER li1 ;
        RECT 0.085 2.125 1.275 2.415 ;
    END
  END B
  PIN C
    ANTENNAGATEAREA 0.126000 ;
    PORT
      LAYER li1 ;
        RECT 0.085 0.995 0.430 1.325 ;
    END
  END C
  PIN VNB
    PORT
      LAYER pwell ;
        RECT 1.340 0.815 2.295 1.015 ;
        RECT 0.015 0.135 2.295 0.815 ;
        RECT 0.140 -0.085 0.310 0.135 ;
        RECT 1.340 0.105 2.295 0.135 ;
    END
  END VNB
  PIN VPB
    PORT
      LAYER nwell ;
        RECT -0.190 1.305 2.490 2.910 ;
    END
  END VPB
  PIN VPWR
    USE POWER ;
    PORT
      LAYER li1 ;
        RECT 0.000 2.635 2.300 2.805 ;
        RECT 1.445 1.835 1.725 2.635 ;
      LAYER mcon ;
        RECT 0.145 2.635 0.315 2.805 ;
        RECT 0.605 2.635 0.775 2.805 ;
        RECT 1.065 2.635 1.235 2.805 ;
        RECT 1.525 2.635 1.695 2.805 ;
        RECT 1.985 2.635 2.155 2.805 ;
      LAYER met1 ;
        RECT 0.000 2.480 2.300 2.960 ;
    END
  END VPWR
  PIN VGND
    USE GROUND ;
    PORT
      LAYER li1 ;
        RECT 0.525 0.085 0.855 0.485 ;
        RECT 1.365 0.085 1.745 0.485 ;
        RECT 0.000 -0.085 2.300 0.085 ;
      LAYER mcon ;
        RECT 0.145 -0.085 0.315 0.085 ;
        RECT 0.605 -0.085 0.775 0.085 ;
        RECT 1.065 -0.085 1.235 0.085 ;
        RECT 1.525 -0.085 1.695 0.085 ;
        RECT 1.985 -0.085 2.155 0.085 ;
      LAYER met1 ;
        RECT 0.000 -0.240 2.300 0.240 ;
    END
  END VGND
  OBS
      LAYER li1 ;
        RECT 0.105 1.785 1.275 1.955 ;
        RECT 0.105 1.495 0.430 1.785 ;
        RECT 1.105 1.665 1.275 1.785 ;
        RECT 1.105 1.495 1.765 1.665 ;
        RECT 1.595 1.325 1.765 1.495 ;
        RECT 1.595 0.995 1.870 1.325 ;
        RECT 1.595 0.825 1.765 0.995 ;
        RECT 0.100 0.655 1.765 0.825 ;
        RECT 0.100 0.305 0.355 0.655 ;
        RECT 1.025 0.305 1.195 0.655 ;
  END
END sky130_fd_sc_hd__or3_1
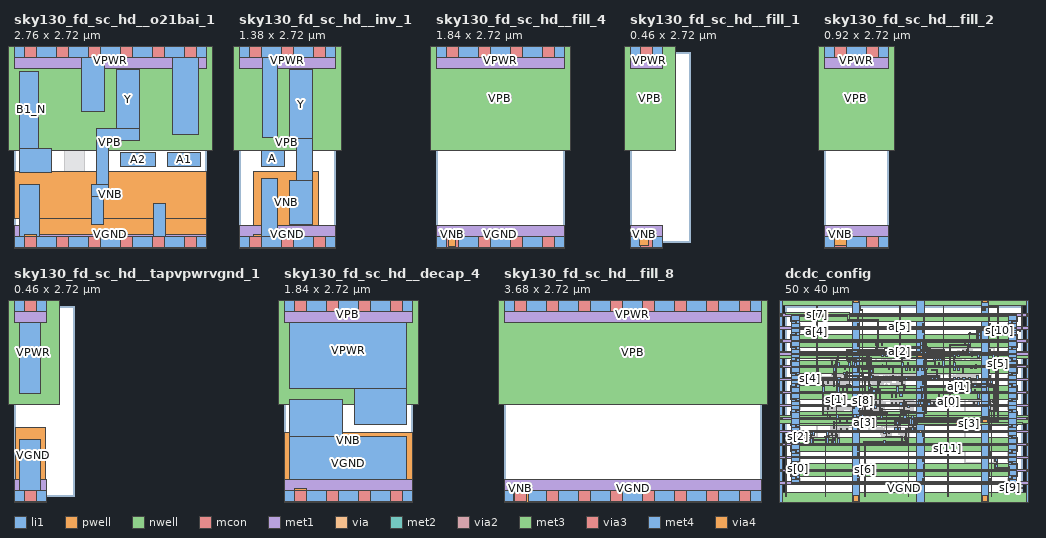
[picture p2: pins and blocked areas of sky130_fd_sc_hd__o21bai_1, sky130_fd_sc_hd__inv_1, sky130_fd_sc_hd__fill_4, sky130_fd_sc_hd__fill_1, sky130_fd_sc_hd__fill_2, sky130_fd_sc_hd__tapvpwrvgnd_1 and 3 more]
MACRO sky130_fd_sc_hd__o21bai_1
  CLASS BLOCK ;
  FOREIGN sky130_fd_sc_hd__o21bai_1 ;
  ORIGIN 0.000 0.000 ;
  SIZE 2.760 BY 2.720 ;
  PIN A1
    ANTENNAGATEAREA 0.247500 ;
    PORT
      LAYER li1 ;
        RECT 2.195 1.075 2.675 1.285 ;
    END
  END A1
  PIN Y
    ANTENNADIFFAREA 0.474000 ;
    PORT
      LAYER li1 ;
        RECT 1.470 1.625 1.795 2.465 ;
        RECT 1.185 1.455 1.795 1.625 ;
        RECT 1.185 0.825 1.355 1.455 ;
        RECT 1.115 0.645 1.355 0.825 ;
        RECT 1.115 0.255 1.285 0.645 ;
    END
  END Y
  PIN B1_N
    ANTENNAGATEAREA 0.126000 ;
    PORT
      LAYER li1 ;
        RECT 0.085 1.345 0.355 2.445 ;
        RECT 0.085 0.995 0.535 1.345 ;
    END
  END B1_N
  PIN A2
    ANTENNAGATEAREA 0.247500 ;
    PORT
      LAYER li1 ;
        RECT 1.525 1.075 2.025 1.285 ;
    END
  END A2
  PIN VNB
    PORT
      LAYER pwell ;
        RECT 0.005 0.335 2.755 1.015 ;
        RECT 0.145 0.105 2.755 0.335 ;
        RECT 0.145 -0.085 0.315 0.105 ;
    END
  END VNB
  PIN VPB
    PORT
      LAYER nwell ;
        RECT -0.190 1.305 2.950 2.910 ;
    END
  END VPB
  PIN VPWR
    USE POWER ;
    PORT
      LAYER li1 ;
        RECT 0.000 2.635 2.760 2.805 ;
        RECT 0.970 1.875 1.300 2.635 ;
        RECT 2.270 1.535 2.645 2.635 ;
      LAYER mcon ;
        RECT 0.145 2.635 0.315 2.805 ;
        RECT 0.605 2.635 0.775 2.805 ;
        RECT 1.065 2.635 1.235 2.805 ;
        RECT 1.525 2.635 1.695 2.805 ;
        RECT 1.985 2.635 2.155 2.805 ;
        RECT 2.445 2.635 2.615 2.805 ;
      LAYER met1 ;
        RECT 0.000 2.480 2.760 2.960 ;
    END
  END VPWR
  PIN VGND
    USE GROUND ;
    PORT
      LAYER li1 ;
        RECT 0.085 0.085 0.360 0.825 ;
        RECT 1.995 0.085 2.165 0.555 ;
        RECT 0.000 -0.085 2.760 0.085 ;
      LAYER mcon ;
        RECT 0.145 -0.085 0.315 0.085 ;
        RECT 0.605 -0.085 0.775 0.085 ;
        RECT 1.065 -0.085 1.235 0.085 ;
        RECT 1.525 -0.085 1.695 0.085 ;
        RECT 1.985 -0.085 2.155 0.085 ;
        RECT 2.445 -0.085 2.615 0.085 ;
      LAYER met1 ;
        RECT 0.000 -0.240 2.760 0.240 ;
    END
  END VGND
  OBS
      LAYER li1 ;
        RECT 0.525 1.705 0.800 2.210 ;
        RECT 0.525 1.535 1.015 1.705 ;
        RECT 0.720 0.995 1.015 1.535 ;
        RECT 0.720 0.825 0.890 0.995 ;
        RECT 0.580 0.655 0.890 0.825 ;
        RECT 1.570 0.735 2.665 0.905 ;
        RECT 0.580 0.495 0.770 0.655 ;
        RECT 1.570 0.485 1.740 0.735 ;
        RECT 1.490 0.255 1.820 0.485 ;
        RECT 2.335 0.270 2.665 0.735 ;
  END
END sky130_fd_sc_hd__o21bai_1
MACRO VIA_L1M1_PR_MR
  CLASS BLOCK ;
  FOREIGN VIA_L1M1_PR_MR ;
  ORIGIN 0.145 0.115 ;
  SIZE 0.290 BY 0.230 ;
  OBS
      LAYER li1 ;
        RECT -0.085 -0.085 0.085 0.085 ;
      LAYER met1 ;
        RECT -0.145 -0.115 0.145 0.115 ;
  END
END VIA_L1M1_PR_MR
MACRO sky130_fd_sc_hd__inv_1
  CLASS BLOCK ;
  FOREIGN sky130_fd_sc_hd__inv_1 ;
  ORIGIN 0.000 0.000 ;
  SIZE 1.380 BY 2.720 ;
  PIN Y
    ANTENNADIFFAREA 0.429000 ;
    PORT
      LAYER li1 ;
        RECT 0.720 1.485 1.050 2.465 ;
        RECT 0.820 0.885 1.050 1.485 ;
        RECT 0.720 0.255 1.050 0.885 ;
    END
  END Y
  PIN A
    ANTENNAGATEAREA 0.247500 ;
    PORT
      LAYER li1 ;
        RECT 0.320 1.075 0.650 1.315 ;
    END
  END A
  PIN VNB
    PORT
      LAYER pwell ;
        RECT 0.210 0.105 1.140 1.015 ;
        RECT 0.210 0.085 0.315 0.105 ;
        RECT 0.145 -0.085 0.315 0.085 ;
    END
  END VNB
  PIN VPB
    PORT
      LAYER nwell ;
        RECT -0.190 1.305 1.570 2.910 ;
    END
  END VPB
  PIN VGND
    USE GROUND ;
    PORT
      LAYER li1 ;
        RECT 0.320 0.085 0.550 0.905 ;
        RECT 0.000 -0.085 1.380 0.085 ;
      LAYER mcon ;
        RECT 0.145 -0.085 0.315 0.085 ;
        RECT 0.605 -0.085 0.775 0.085 ;
        RECT 1.065 -0.085 1.235 0.085 ;
      LAYER met1 ;
        RECT 0.000 -0.240 1.380 0.240 ;
    END
  END VGND
  PIN VPWR
    USE POWER ;
    PORT
      LAYER li1 ;
        RECT 0.000 2.635 1.380 2.805 ;
        RECT 0.340 1.495 0.550 2.635 ;
      LAYER mcon ;
        RECT 0.145 2.635 0.315 2.805 ;
        RECT 0.605 2.635 0.775 2.805 ;
        RECT 1.065 2.635 1.235 2.805 ;
      LAYER met1 ;
        RECT 0.000 2.480 1.380 2.960 ;
    END
  END VPWR
END sky130_fd_sc_hd__inv_1
MACRO VIA_M1M2_PR
  CLASS BLOCK ;
  FOREIGN VIA_M1M2_PR ;
  ORIGIN 0.160 0.160 ;
  SIZE 0.320 BY 0.320 ;
  OBS
      LAYER met1 ;
        RECT -0.160 -0.130 0.160 0.130 ;
      LAYER via ;
        RECT -0.130 -0.130 0.130 0.130 ;
      LAYER met2 ;
        RECT -0.130 -0.160 0.130 0.160 ;
  END
END VIA_M1M2_PR
MACRO VIA_M2M3_PR
  CLASS BLOCK ;
  FOREIGN VIA_M2M3_PR ;
  ORIGIN 0.165 0.185 ;
  SIZE 0.330 BY 0.370 ;
  OBS
      LAYER met2 ;
        RECT -0.140 -0.185 0.140 0.185 ;
      LAYER via2 ;
        RECT -0.140 -0.140 0.140 0.140 ;
      LAYER met3 ;
        RECT -0.165 -0.165 0.165 0.165 ;
  END
END VIA_M2M3_PR
MACRO sky130_fd_sc_hd__fill_4
  CLASS BLOCK ;
  FOREIGN sky130_fd_sc_hd__fill_4 ;
  ORIGIN 0.000 0.000 ;
  SIZE 1.840 BY 2.720 ;
  PIN VNB
    PORT
      LAYER pwell ;
        RECT 0.175 -0.060 0.285 0.060 ;
    END
  END VNB
  PIN VPB
    PORT
      LAYER nwell ;
        RECT -0.190 1.305 2.030 2.910 ;
    END
  END VPB
  PIN VGND
    USE GROUND ;
    PORT
      LAYER li1 ;
        RECT 0.000 -0.085 1.840 0.085 ;
      LAYER mcon ;
        RECT 0.145 -0.085 0.315 0.085 ;
        RECT 0.605 -0.085 0.775 0.085 ;
        RECT 1.065 -0.085 1.235 0.085 ;
        RECT 1.525 -0.085 1.695 0.085 ;
      LAYER met1 ;
        RECT 0.000 -0.240 1.840 0.240 ;
    END
  END VGND
  PIN VPWR
    USE POWER ;
    PORT
      LAYER li1 ;
        RECT 0.000 2.635 1.840 2.805 ;
      LAYER mcon ;
        RECT 0.145 2.635 0.315 2.805 ;
        RECT 0.605 2.635 0.775 2.805 ;
        RECT 1.065 2.635 1.235 2.805 ;
        RECT 1.525 2.635 1.695 2.805 ;
      LAYER met1 ;
        RECT 0.000 2.480 1.840 2.960 ;
    END
  END VPWR
END sky130_fd_sc_hd__fill_4
MACRO sky130_fd_sc_hd__fill_1
  CLASS BLOCK ;
  FOREIGN sky130_fd_sc_hd__fill_1 ;
  ORIGIN 0.000 0.000 ;
  SIZE 0.460 BY 2.720 ;
  PIN VNB
    PORT
      LAYER pwell ;
        RECT 0.140 -0.055 0.260 0.055 ;
    END
  END VNB
  PIN VPB
    PORT
      LAYER nwell ;
        RECT -0.190 1.305 0.650 2.910 ;
    END
  END VPB
  PIN VPWR
    USE POWER ;
    PORT
      LAYER li1 ;
        RECT 0.000 2.635 0.460 2.805 ;
      LAYER mcon ;
        RECT 0.145 2.635 0.315 2.805 ;
      LAYER met1 ;
        RECT 0.000 2.480 0.460 2.960 ;
    END
  END VPWR
  PIN VGND
    USE GROUND ;
    PORT
      LAYER li1 ;
        RECT 0.000 -0.085 0.460 0.085 ;
      LAYER mcon ;
        RECT 0.145 -0.085 0.315 0.085 ;
      LAYER met1 ;
        RECT 0.000 -0.240 0.460 0.240 ;
    END
  END VGND
END sky130_fd_sc_hd__fill_1
MACRO VIA_via_1600x480
  CLASS BLOCK ;
  FOREIGN VIA_via_1600x480 ;
  ORIGIN 0.800 0.240 ;
  SIZE 1.600 BY 0.480 ;
  OBS
      LAYER met1 ;
        RECT -0.800 -0.240 0.800 0.240 ;
      LAYER via ;
        RECT -0.770 -0.130 -0.510 0.130 ;
        RECT -0.450 -0.130 -0.190 0.130 ;
        RECT -0.130 -0.130 0.130 0.130 ;
        RECT 0.190 -0.130 0.450 0.130 ;
        RECT 0.510 -0.130 0.770 0.130 ;
      LAYER met2 ;
        RECT -0.770 -0.240 0.770 0.240 ;
  END
END VIA_via_1600x480
MACRO VIA_via2_1600x480
  CLASS BLOCK ;
  FOREIGN VIA_via2_1600x480 ;
  ORIGIN 0.800 0.240 ;
  SIZE 1.600 BY 0.480 ;
  OBS
      LAYER met2 ;
        RECT -0.740 -0.240 0.740 0.240 ;
      LAYER via2 ;
        RECT -0.740 -0.140 -0.460 0.140 ;
        RECT -0.340 -0.140 -0.060 0.140 ;
        RECT 0.060 -0.140 0.340 0.140 ;
        RECT 0.460 -0.140 0.740 0.140 ;
      LAYER met3 ;
        RECT -0.800 -0.165 0.800 0.165 ;
  END
END VIA_via2_1600x480
MACRO VIA_via3_1600x480
  CLASS BLOCK ;
  FOREIGN VIA_via3_1600x480 ;
  ORIGIN 0.800 0.240 ;
  SIZE 1.600 BY 0.480 ;
  OBS
      LAYER met3 ;
        RECT -0.800 -0.160 0.800 0.160 ;
      LAYER via3 ;
        RECT -0.760 -0.160 -0.440 0.160 ;
        RECT -0.360 -0.160 -0.040 0.160 ;
        RECT 0.040 -0.160 0.360 0.160 ;
        RECT 0.440 -0.160 0.760 0.160 ;
      LAYER met4 ;
        RECT -0.800 -0.240 0.800 0.240 ;
  END
END VIA_via3_1600x480
MACRO sky130_fd_sc_hd__fill_2
  CLASS BLOCK ;
  FOREIGN sky130_fd_sc_hd__fill_2 ;
  ORIGIN 0.000 0.000 ;
  SIZE 0.920 BY 2.720 ;
  PIN VNB
    PORT
      LAYER pwell ;
        RECT 0.155 -0.050 0.315 0.060 ;
    END
  END VNB
  PIN VPB
    PORT
      LAYER nwell ;
        RECT -0.190 1.305 1.110 2.910 ;
    END
  END VPB
  PIN VGND
    USE GROUND ;
    PORT
      LAYER li1 ;
        RECT 0.000 -0.085 0.920 0.085 ;
      LAYER mcon ;
        RECT 0.145 -0.085 0.315 0.085 ;
        RECT 0.605 -0.085 0.775 0.085 ;
      LAYER met1 ;
        RECT 0.000 -0.240 0.920 0.240 ;
    END
  END VGND
  PIN VPWR
    USE POWER ;
    PORT
      LAYER li1 ;
        RECT 0.000 2.635 0.920 2.805 ;
      LAYER mcon ;
        RECT 0.145 2.635 0.315 2.805 ;
        RECT 0.605 2.635 0.775 2.805 ;
      LAYER met1 ;
        RECT 0.000 2.480 0.920 2.960 ;
    END
  END VPWR
END sky130_fd_sc_hd__fill_2
MACRO sky130_fd_sc_hd__tapvpwrvgnd_1
  CLASS BLOCK ;
  FOREIGN sky130_fd_sc_hd__tapvpwrvgnd_1 ;
  ORIGIN 0.000 0.000 ;
  SIZE 0.460 BY 2.720 ;
  PIN VPWR
    USE POWER ;
    PORT
      LAYER nwell ;
        RECT -0.190 1.305 0.650 2.910 ;
      LAYER li1 ;
        RECT 0.000 2.635 0.460 2.805 ;
        RECT 0.085 1.470 0.375 2.635 ;
      LAYER mcon ;
        RECT 0.145 2.635 0.315 2.805 ;
      LAYER met1 ;
        RECT 0.000 2.480 0.460 2.960 ;
    END
  END VPWR
  PIN VGND
    USE GROUND ;
    PORT
      LAYER pwell ;
        RECT 0.015 0.190 0.445 0.975 ;
      LAYER li1 ;
        RECT 0.085 0.085 0.375 0.810 ;
        RECT 0.000 -0.085 0.460 0.085 ;
      LAYER mcon ;
        RECT 0.145 -0.085 0.315 0.085 ;
      LAYER met1 ;
        RECT 0.000 -0.240 0.460 0.240 ;
    END
  END VGND
END sky130_fd_sc_hd__tapvpwrvgnd_1
MACRO sky130_fd_sc_hd__decap_4
  CLASS BLOCK ;
  FOREIGN sky130_fd_sc_hd__decap_4 ;
  ORIGIN 0.000 0.000 ;
  SIZE 1.840 BY 2.720 ;
  PIN VNB
    PORT
      LAYER pwell ;
        RECT 0.005 0.105 1.835 0.915 ;
        RECT 0.145 -0.085 0.315 0.105 ;
    END
  END VNB
  PIN VPB
    PORT
      LAYER nwell ;
        RECT -0.190 1.305 2.030 2.910 ;
    END
  END VPB
  PIN VGND
    USE GROUND ;
    PORT
      LAYER li1 ;
        RECT 0.085 0.855 0.835 1.375 ;
        RECT 0.085 0.085 1.755 0.855 ;
        RECT 0.000 -0.085 1.840 0.085 ;
      LAYER mcon ;
        RECT 0.145 -0.085 0.315 0.085 ;
        RECT 0.605 -0.085 0.775 0.085 ;
        RECT 1.065 -0.085 1.235 0.085 ;
        RECT 1.525 -0.085 1.695 0.085 ;
      LAYER met1 ;
        RECT 0.000 -0.240 1.840 0.240 ;
    END
  END VGND
  PIN VPWR
    USE POWER ;
    PORT
      LAYER li1 ;
        RECT 0.000 2.635 1.840 2.805 ;
        RECT 0.085 1.545 1.755 2.635 ;
        RECT 1.005 1.025 1.755 1.545 ;
      LAYER mcon ;
        RECT 0.145 2.635 0.315 2.805 ;
        RECT 0.605 2.635 0.775 2.805 ;
        RECT 1.065 2.635 1.235 2.805 ;
        RECT 1.525 2.635 1.695 2.805 ;
      LAYER met1 ;
        RECT 0.000 2.480 1.840 2.960 ;
    END
  END VPWR
END sky130_fd_sc_hd__decap_4
MACRO sky130_fd_sc_hd__fill_8
  CLASS BLOCK ;
  FOREIGN sky130_fd_sc_hd__fill_8 ;
  ORIGIN 0.000 0.000 ;
  SIZE 3.680 BY 2.720 ;
  PIN VNB
    PORT
      LAYER pwell ;
        RECT 0.130 -0.120 0.350 0.050 ;
    END
  END VNB
  PIN VPB
    PORT
      LAYER nwell ;
        RECT -0.190 1.305 3.870 2.910 ;
    END
  END VPB
  PIN VGND
    USE GROUND ;
    PORT
      LAYER li1 ;
        RECT 0.000 -0.085 3.680 0.085 ;
      LAYER mcon ;
        RECT 0.145 -0.085 0.315 0.085 ;
        RECT 0.605 -0.085 0.775 0.085 ;
        RECT 1.065 -0.085 1.235 0.085 ;
        RECT 1.525 -0.085 1.695 0.085 ;
        RECT 1.985 -0.085 2.155 0.085 ;
        RECT 2.445 -0.085 2.615 0.085 ;
        RECT 2.905 -0.085 3.075 0.085 ;
        RECT 3.365 -0.085 3.535 0.085 ;
      LAYER met1 ;
        RECT 0.000 -0.240 3.680 0.240 ;
    END
  END VGND
  PIN VPWR
    USE POWER ;
    PORT
      LAYER li1 ;
        RECT 0.000 2.635 3.680 2.805 ;
      LAYER mcon ;
        RECT 0.145 2.635 0.315 2.805 ;
        RECT 0.605 2.635 0.775 2.805 ;
        RECT 1.065 2.635 1.235 2.805 ;
        RECT 1.525 2.635 1.695 2.805 ;
        RECT 1.985 2.635 2.155 2.805 ;
        RECT 2.445 2.635 2.615 2.805 ;
        RECT 2.905 2.635 3.075 2.805 ;
        RECT 3.365 2.635 3.535 2.805 ;
      LAYER met1 ;
        RECT 0.000 2.480 3.680 2.960 ;
    END
  END VPWR
END sky130_fd_sc_hd__fill_8
MACRO VIA_via_4200x480
  CLASS BLOCK ;
  FOREIGN VIA_via_4200x480 ;
  ORIGIN 2.100 0.240 ;
  SIZE 4.200 BY 0.480 ;
  OBS
      LAYER met1 ;
        RECT -2.100 -0.240 2.100 0.240 ;
      LAYER via ;
        RECT -2.050 -0.130 -1.790 0.130 ;
        RECT -1.730 -0.130 -1.470 0.130 ;
        RECT -1.410 -0.130 -1.150 0.130 ;
        RECT -1.090 -0.130 -0.830 0.130 ;
        RECT -0.770 -0.130 -0.510 0.130 ;
        RECT -0.450 -0.130 -0.190 0.130 ;
        RECT -0.130 -0.130 0.130 0.130 ;
        RECT 0.190 -0.130 0.450 0.130 ;
        RECT 0.510 -0.130 0.770 0.130 ;
        RECT 0.830 -0.130 1.090 0.130 ;
        RECT 1.150 -0.130 1.410 0.130 ;
        RECT 1.470 -0.130 1.730 0.130 ;
        RECT 1.790 -0.130 2.050 0.130 ;
      LAYER met2 ;
        RECT -2.050 -0.240 2.050 0.240 ;
  END
END VIA_via_4200x480
MACRO VIA_via3_4200x480
  CLASS BLOCK ;
  FOREIGN VIA_via3_4200x480 ;
  ORIGIN 2.100 0.240 ;
  SIZE 4.200 BY 0.480 ;
  OBS
      LAYER met3 ;
        RECT -2.100 -0.160 2.100 0.160 ;
      LAYER via3 ;
        RECT -1.960 -0.160 -1.640 0.160 ;
        RECT -1.560 -0.160 -1.240 0.160 ;
        RECT -1.160 -0.160 -0.840 0.160 ;
        RECT -0.760 -0.160 -0.440 0.160 ;
        RECT -0.360 -0.160 -0.040 0.160 ;
        RECT 0.040 -0.160 0.360 0.160 ;
        RECT 0.440 -0.160 0.760 0.160 ;
        RECT 0.840 -0.160 1.160 0.160 ;
        RECT 1.240 -0.160 1.560 0.160 ;
        RECT 1.640 -0.160 1.960 0.160 ;
      LAYER met4 ;
        RECT -2.100 -0.240 2.100 0.240 ;
  END
END VIA_via3_4200x480
MACRO VIA_via2_4200x480
  CLASS BLOCK ;
  FOREIGN VIA_via2_4200x480 ;
  ORIGIN 2.100 0.240 ;
  SIZE 4.200 BY 0.480 ;
  OBS
      LAYER met2 ;
        RECT -1.940 -0.240 1.940 0.240 ;
      LAYER via2 ;
        RECT -1.940 -0.140 -1.660 0.140 ;
        RECT -1.540 -0.140 -1.260 0.140 ;
        RECT -1.140 -0.140 -0.860 0.140 ;
        RECT -0.740 -0.140 -0.460 0.140 ;
        RECT -0.340 -0.140 -0.060 0.140 ;
        RECT 0.060 -0.140 0.340 0.140 ;
        RECT 0.460 -0.140 0.740 0.140 ;
        RECT 0.860 -0.140 1.140 0.140 ;
        RECT 1.260 -0.140 1.540 0.140 ;
        RECT 1.660 -0.140 1.940 0.140 ;
      LAYER met3 ;
        RECT -2.100 -0.165 2.100 0.165 ;
  END
END VIA_via2_4200x480
MACRO VIA_via4_1600x4200
  CLASS BLOCK ;
  FOREIGN VIA_via4_1600x4200 ;
  ORIGIN 0.800 2.100 ;
  SIZE 1.600 BY 4.200 ;
  OBS
      LAYER met4 ;
        RECT -0.800 -2.100 0.800 2.100 ;
      LAYER via4 ;
        RECT -0.590 0.210 0.590 1.390 ;
        RECT -0.590 -1.390 0.590 -0.210 ;
      LAYER met5 ;
        RECT -0.800 -2.100 0.800 2.100 ;
  END
END VIA_via4_1600x4200
MACRO VIA_via4_4200x4200
  CLASS BLOCK ;
  FOREIGN VIA_via4_4200x4200 ;
  ORIGIN 2.100 2.100 ;
  SIZE 4.200 BY 4.200 ;
  OBS
      LAYER met4 ;
        RECT -2.100 -2.100 2.100 2.100 ;
      LAYER via4 ;
        RECT -1.390 -1.390 1.390 1.390 ;
      LAYER met5 ;
        RECT -2.100 -2.100 2.100 2.100 ;
  END
END VIA_via4_4200x4200
MACRO dcdc_config
  CLASS BLOCK ;
  FOREIGN dcdc_config ;
  ORIGIN 0.000 0.000 ;
  SIZE 50.000 BY 40.000 ;
  PIN VPWR
    ANTENNAGATEAREA 15.014999 ;
    ANTENNADIFFAREA 38.810200 ;
    PORT
      LAYER nwell ;
        RECT 1.190 36.665 48.950 38.270 ;
        RECT 1.190 31.225 48.950 34.055 ;
        RECT 1.190 25.785 48.950 28.615 ;
        RECT 1.190 20.345 48.950 23.175 ;
        RECT 1.190 14.905 48.950 17.735 ;
        RECT 1.190 9.465 48.950 12.295 ;
        RECT 1.190 4.025 48.950 6.855 ;
      LAYER li1 ;
        RECT 1.380 37.995 48.760 38.165 ;
        RECT 1.465 36.905 3.135 37.995 ;
        RECT 2.385 36.385 3.135 36.905 ;
        RECT 15.265 36.830 15.555 37.995 ;
        RECT 29.065 36.830 29.355 37.995 ;
        RECT 42.865 36.830 43.155 37.995 ;
        RECT 47.005 36.905 48.675 37.995 ;
        RECT 47.005 36.385 47.755 36.905 ;
        RECT 2.385 33.815 3.135 34.335 ;
        RECT 1.465 32.725 3.135 33.815 ;
        RECT 29.065 32.725 29.355 33.890 ;
        RECT 40.360 32.725 40.570 33.865 ;
        RECT 47.005 33.815 47.755 34.335 ;
        RECT 47.005 32.725 48.675 33.815 ;
        RECT 1.380 32.555 48.760 32.725 ;
        RECT 1.465 31.465 3.135 32.555 ;
        RECT 2.385 30.945 3.135 31.465 ;
        RECT 15.265 31.390 15.555 32.555 ;
        RECT 18.975 31.775 19.230 32.555 ;
        RECT 20.225 31.745 20.555 32.555 ;
        RECT 28.605 31.755 28.865 32.555 ;
        RECT 37.865 32.115 38.060 32.555 ;
        RECT 42.865 31.390 43.155 32.555 ;
        RECT 47.005 31.465 48.675 32.555 ;
        RECT 47.005 30.945 47.755 31.465 ;
        RECT 2.385 28.375 3.135 28.895 ;
        RECT 1.465 27.285 3.135 28.375 ;
        RECT 9.750 27.285 10.070 28.425 ;
        RECT 11.155 27.285 11.410 28.085 ;
        RECT 13.455 27.285 13.710 28.065 ;
        RECT 14.705 27.285 15.035 28.095 ;
        RECT 17.105 27.285 17.385 28.425 ;
        RECT 18.055 27.285 18.315 28.425 ;
        RECT 20.430 27.285 20.600 27.745 ;
        RECT 21.270 27.285 21.440 28.085 ;
        RECT 24.525 27.285 24.855 28.095 ;
        RECT 25.850 27.285 26.105 28.065 ;
        RECT 29.065 27.285 29.355 28.450 ;
        RECT 31.385 27.285 31.665 28.085 ;
        RECT 32.395 27.285 32.565 28.085 ;
        RECT 33.235 27.285 33.495 28.425 ;
        RECT 35.510 27.285 35.825 28.085 ;
        RECT 40.140 27.285 40.335 27.725 ;
        RECT 42.865 27.285 43.125 28.425 ;
        RECT 43.795 27.285 44.075 28.425 ;
        RECT 47.005 28.375 47.755 28.895 ;
        RECT 47.005 27.285 48.675 28.375 ;
        RECT 1.380 27.115 48.760 27.285 ;
        RECT 1.465 26.025 3.135 27.115 ;
        RECT 2.385 25.505 3.135 26.025 ;
        RECT 6.780 25.975 6.990 27.115 ;
        RECT 10.215 26.285 10.545 27.115 ;
        RECT 12.575 26.615 12.825 27.115 ;
        RECT 15.265 25.950 15.555 27.115 ;
        RECT 17.625 25.975 17.835 27.115 ;
        RECT 18.505 25.975 18.735 27.115 ;
        RECT 21.735 26.655 22.065 27.115 ;
        RECT 22.580 25.975 22.910 27.115 ;
        RECT 25.355 26.395 25.685 27.115 ;
        RECT 26.195 26.395 26.525 27.115 ;
        RECT 27.035 26.395 27.365 27.115 ;
        RECT 27.875 26.395 28.205 27.115 ;
        RECT 28.735 26.395 29.065 27.115 ;
        RECT 29.575 26.735 29.905 27.115 ;
        RECT 35.535 26.415 35.865 27.115 ;
        RECT 36.395 26.415 36.725 27.115 ;
        RECT 37.335 25.995 37.585 27.115 ;
        RECT 39.055 26.755 39.385 27.115 ;
        RECT 39.895 26.755 40.225 27.115 ;
        RECT 42.865 25.950 43.155 27.115 ;
        RECT 47.005 26.025 48.675 27.115 ;
        RECT 47.005 25.505 47.755 26.025 ;
        RECT 2.385 22.935 3.135 23.455 ;
        RECT 1.465 21.845 3.135 22.935 ;
        RECT 7.915 21.845 8.245 22.985 ;
        RECT 11.125 21.845 11.385 22.985 ;
        RECT 12.055 21.845 12.225 22.645 ;
        RECT 12.955 21.845 13.235 22.645 ;
        RECT 18.905 22.525 19.235 22.715 ;
        RECT 17.565 21.845 17.825 22.355 ;
        RECT 18.905 22.350 19.100 22.525 ;
        RECT 18.485 21.845 19.100 22.350 ;
        RECT 19.915 21.845 20.130 22.390 ;
        RECT 23.550 21.845 23.870 22.985 ;
        RECT 24.955 21.845 25.210 22.645 ;
        RECT 29.065 21.845 29.355 23.010 ;
        RECT 38.915 21.845 39.245 22.565 ;
        RECT 39.915 21.845 40.195 22.515 ;
        RECT 42.415 21.845 42.745 22.985 ;
        RECT 47.005 22.935 47.755 23.455 ;
        RECT 47.005 21.845 48.675 22.935 ;
        RECT 1.380 21.675 48.760 21.845 ;
        RECT 1.465 20.585 3.135 21.675 ;
        RECT 9.805 20.865 10.135 21.675 ;
        RECT 11.130 20.895 11.385 21.675 ;
        RECT 2.385 20.065 3.135 20.585 ;
        RECT 15.265 20.510 15.555 21.675 ;
        RECT 18.955 20.535 19.285 21.675 ;
        RECT 22.365 20.835 22.615 21.675 ;
        RECT 23.205 20.835 23.455 21.675 ;
        RECT 24.085 20.875 24.785 21.675 ;
        RECT 28.635 20.835 28.885 21.675 ;
        RECT 32.275 20.580 32.525 21.675 ;
        RECT 40.515 20.535 40.845 21.675 ;
        RECT 42.865 20.510 43.155 21.675 ;
        RECT 47.005 20.585 48.675 21.675 ;
        RECT 47.005 20.065 47.755 20.585 ;
        RECT 2.385 17.495 3.135 18.015 ;
        RECT 1.465 16.405 3.135 17.495 ;
        RECT 8.875 16.405 9.045 17.545 ;
        RECT 9.315 16.405 9.565 17.205 ;
        RECT 10.840 16.405 11.170 17.205 ;
        RECT 14.335 16.405 15.045 17.180 ;
        RECT 16.135 16.405 16.465 17.125 ;
        RECT 19.855 17.085 20.185 17.330 ;
        RECT 20.000 17.060 20.185 17.085 ;
        RECT 20.000 16.960 20.615 17.060 ;
        RECT 18.930 16.405 19.185 16.950 ;
        RECT 20.010 16.405 20.615 16.960 ;
        RECT 24.005 16.405 24.305 16.915 ;
        RECT 24.975 16.405 25.605 16.915 ;
        RECT 26.735 16.405 27.035 16.915 ;
        RECT 29.065 16.405 29.355 17.570 ;
        RECT 42.865 16.405 43.145 17.545 ;
        RECT 43.815 16.405 44.075 17.545 ;
        RECT 47.005 17.495 47.755 18.015 ;
        RECT 47.005 16.405 48.675 17.495 ;
        RECT 1.380 16.235 48.760 16.405 ;
        RECT 1.465 15.145 3.135 16.235 ;
        RECT 11.405 15.435 11.635 16.235 ;
        RECT 12.955 15.435 13.250 16.235 ;
        RECT 2.385 14.625 3.135 15.145 ;
        RECT 15.265 15.070 15.555 16.235 ;
        RECT 17.595 15.455 17.850 16.235 ;
        RECT 18.845 15.425 19.175 16.235 ;
        RECT 23.085 15.095 23.345 16.235 ;
        RECT 24.015 15.095 24.295 16.235 ;
        RECT 26.305 15.095 26.565 16.235 ;
        RECT 27.235 15.095 27.515 16.235 ;
        RECT 42.865 15.070 43.155 16.235 ;
        RECT 47.005 15.145 48.675 16.235 ;
        RECT 47.005 14.625 47.755 15.145 ;
        RECT 2.385 12.055 3.135 12.575 ;
        RECT 1.465 10.965 3.135 12.055 ;
        RECT 5.890 10.965 6.100 12.105 ;
        RECT 9.710 10.965 10.040 11.725 ;
        RECT 11.010 10.965 11.385 12.065 ;
        RECT 20.815 10.965 21.095 11.765 ;
        RECT 24.495 10.965 24.750 11.745 ;
        RECT 25.745 10.965 26.075 11.775 ;
        RECT 29.065 10.965 29.355 12.130 ;
        RECT 47.005 12.055 47.755 12.575 ;
        RECT 47.005 10.965 48.675 12.055 ;
        RECT 1.380 10.795 48.760 10.965 ;
        RECT 1.465 9.705 3.135 10.795 ;
        RECT 2.385 9.185 3.135 9.705 ;
        RECT 15.265 9.630 15.555 10.795 ;
        RECT 42.865 9.630 43.155 10.795 ;
        RECT 47.005 9.705 48.675 10.795 ;
        RECT 47.005 9.185 47.755 9.705 ;
        RECT 2.385 6.615 3.135 7.135 ;
        RECT 1.465 5.525 3.135 6.615 ;
        RECT 29.065 5.525 29.355 6.690 ;
        RECT 44.040 5.525 44.250 6.665 ;
        RECT 47.005 6.615 47.755 7.135 ;
        RECT 47.005 5.525 48.675 6.615 ;
        RECT 1.380 5.355 48.760 5.525 ;
        RECT 1.465 4.265 3.135 5.355 ;
        RECT 2.385 3.745 3.135 4.265 ;
        RECT 15.265 4.190 15.555 5.355 ;
        RECT 29.065 4.190 29.355 5.355 ;
        RECT 42.865 4.190 43.155 5.355 ;
        RECT 47.005 4.265 48.675 5.355 ;
        RECT 47.005 3.745 47.755 4.265 ;
      LAYER mcon ;
        RECT 1.525 37.995 1.695 38.165 ;
        RECT 1.985 37.995 2.155 38.165 ;
        RECT 2.445 37.995 2.615 38.165 ;
        RECT 2.905 37.995 3.075 38.165 ;
        RECT 3.365 37.995 3.535 38.165 ;
        RECT 3.825 37.995 3.995 38.165 ;
        RECT 4.285 37.995 4.455 38.165 ;
        RECT 4.745 37.995 4.915 38.165 ;
        RECT 5.205 37.995 5.375 38.165 ;
        RECT 5.665 37.995 5.835 38.165 ;
        RECT 6.125 37.995 6.295 38.165 ;
        RECT 6.585 37.995 6.755 38.165 ;
        RECT 7.045 37.995 7.215 38.165 ;
        RECT 7.505 37.995 7.675 38.165 ;
        RECT 7.965 37.995 8.135 38.165 ;
        RECT 8.425 37.995 8.595 38.165 ;
        RECT 8.885 37.995 9.055 38.165 ;
        RECT 9.345 37.995 9.515 38.165 ;
        RECT 9.805 37.995 9.975 38.165 ;
        RECT 10.265 37.995 10.435 38.165 ;
        RECT 10.725 37.995 10.895 38.165 ;
        RECT 11.185 37.995 11.355 38.165 ;
        RECT 11.645 37.995 11.815 38.165 ;
        RECT 12.105 37.995 12.275 38.165 ;
        RECT 12.565 37.995 12.735 38.165 ;
        RECT 13.025 37.995 13.195 38.165 ;
        RECT 13.485 37.995 13.655 38.165 ;
        RECT 13.945 37.995 14.115 38.165 ;
        RECT 14.405 37.995 14.575 38.165 ;
        RECT 14.865 37.995 15.035 38.165 ;
        RECT 15.325 37.995 15.495 38.165 ;
        RECT 15.785 37.995 15.955 38.165 ;
        RECT 16.245 37.995 16.415 38.165 ;
        RECT 16.705 37.995 16.875 38.165 ;
        RECT 17.165 37.995 17.335 38.165 ;
        RECT 17.625 37.995 17.795 38.165 ;
        RECT 18.085 37.995 18.255 38.165 ;
        RECT 18.545 37.995 18.715 38.165 ;
        RECT 19.005 37.995 19.175 38.165 ;
        RECT 19.465 37.995 19.635 38.165 ;
        RECT 19.925 37.995 20.095 38.165 ;
        RECT 20.385 37.995 20.555 38.165 ;
        RECT 20.845 37.995 21.015 38.165 ;
        RECT 21.305 37.995 21.475 38.165 ;
        RECT 21.765 37.995 21.935 38.165 ;
        RECT 22.225 37.995 22.395 38.165 ;
        RECT 22.685 37.995 22.855 38.165 ;
        RECT 23.145 37.995 23.315 38.165 ;
        RECT 23.605 37.995 23.775 38.165 ;
        RECT 24.065 37.995 24.235 38.165 ;
        RECT 24.525 37.995 24.695 38.165 ;
        RECT 24.985 37.995 25.155 38.165 ;
        RECT 25.445 37.995 25.615 38.165 ;
        RECT 25.905 37.995 26.075 38.165 ;
        RECT 26.365 37.995 26.535 38.165 ;
        RECT 26.825 37.995 26.995 38.165 ;
        RECT 27.285 37.995 27.455 38.165 ;
        RECT 27.745 37.995 27.915 38.165 ;
        RECT 28.205 37.995 28.375 38.165 ;
        RECT 28.665 37.995 28.835 38.165 ;
        RECT 29.125 37.995 29.295 38.165 ;
        RECT 29.585 37.995 29.755 38.165 ;
        RECT 30.045 37.995 30.215 38.165 ;
        RECT 30.505 37.995 30.675 38.165 ;
        RECT 30.965 37.995 31.135 38.165 ;
        RECT 31.425 37.995 31.595 38.165 ;
        RECT 31.885 37.995 32.055 38.165 ;
        RECT 32.345 37.995 32.515 38.165 ;
        RECT 32.805 37.995 32.975 38.165 ;
        RECT 33.265 37.995 33.435 38.165 ;
        RECT 33.725 37.995 33.895 38.165 ;
        RECT 34.185 37.995 34.355 38.165 ;
        RECT 34.645 37.995 34.815 38.165 ;
        RECT 35.105 37.995 35.275 38.165 ;
        RECT 35.565 37.995 35.735 38.165 ;
        RECT 36.025 37.995 36.195 38.165 ;
        RECT 36.485 37.995 36.655 38.165 ;
        RECT 36.945 37.995 37.115 38.165 ;
        RECT 37.405 37.995 37.575 38.165 ;
        RECT 37.865 37.995 38.035 38.165 ;
        RECT 38.325 37.995 38.495 38.165 ;
        RECT 38.785 37.995 38.955 38.165 ;
        RECT 39.245 37.995 39.415 38.165 ;
        RECT 39.705 37.995 39.875 38.165 ;
        RECT 40.165 37.995 40.335 38.165 ;
        RECT 40.625 37.995 40.795 38.165 ;
        RECT 41.085 37.995 41.255 38.165 ;
        RECT 41.545 37.995 41.715 38.165 ;
        RECT 42.005 37.995 42.175 38.165 ;
        RECT 42.465 37.995 42.635 38.165 ;
        RECT 42.925 37.995 43.095 38.165 ;
        RECT 43.385 37.995 43.555 38.165 ;
        RECT 43.845 37.995 44.015 38.165 ;
        RECT 44.305 37.995 44.475 38.165 ;
        RECT 44.765 37.995 44.935 38.165 ;
        RECT 45.225 37.995 45.395 38.165 ;
        RECT 45.685 37.995 45.855 38.165 ;
        RECT 46.145 37.995 46.315 38.165 ;
        RECT 46.605 37.995 46.775 38.165 ;
        RECT 47.065 37.995 47.235 38.165 ;
        RECT 47.525 37.995 47.695 38.165 ;
        RECT 47.985 37.995 48.155 38.165 ;
        RECT 48.445 37.995 48.615 38.165 ;
        RECT 1.525 32.555 1.695 32.725 ;
        RECT 1.985 32.555 2.155 32.725 ;
        RECT 2.445 32.555 2.615 32.725 ;
        RECT 2.905 32.555 3.075 32.725 ;
        RECT 3.365 32.555 3.535 32.725 ;
        RECT 3.825 32.555 3.995 32.725 ;
        RECT 4.285 32.555 4.455 32.725 ;
        RECT 4.745 32.555 4.915 32.725 ;
        RECT 5.205 32.555 5.375 32.725 ;
        RECT 5.665 32.555 5.835 32.725 ;
        RECT 6.125 32.555 6.295 32.725 ;
        RECT 6.585 32.555 6.755 32.725 ;
        RECT 7.045 32.555 7.215 32.725 ;
        RECT 7.505 32.555 7.675 32.725 ;
        RECT 7.965 32.555 8.135 32.725 ;
        RECT 8.425 32.555 8.595 32.725 ;
        RECT 8.885 32.555 9.055 32.725 ;
        RECT 9.345 32.555 9.515 32.725 ;
        RECT 9.805 32.555 9.975 32.725 ;
        RECT 10.265 32.555 10.435 32.725 ;
        RECT 10.725 32.555 10.895 32.725 ;
        RECT 11.185 32.555 11.355 32.725 ;
        RECT 11.645 32.555 11.815 32.725 ;
        RECT 12.105 32.555 12.275 32.725 ;
        RECT 12.565 32.555 12.735 32.725 ;
        RECT 13.025 32.555 13.195 32.725 ;
        RECT 13.485 32.555 13.655 32.725 ;
        RECT 13.945 32.555 14.115 32.725 ;
        RECT 14.405 32.555 14.575 32.725 ;
        RECT 14.865 32.555 15.035 32.725 ;
        RECT 15.325 32.555 15.495 32.725 ;
        RECT 15.785 32.555 15.955 32.725 ;
        RECT 16.245 32.555 16.415 32.725 ;
        RECT 16.705 32.555 16.875 32.725 ;
        RECT 17.165 32.555 17.335 32.725 ;
        RECT 17.625 32.555 17.795 32.725 ;
        RECT 18.085 32.555 18.255 32.725 ;
        RECT 18.545 32.555 18.715 32.725 ;
        RECT 19.005 32.555 19.175 32.725 ;
        RECT 19.465 32.555 19.635 32.725 ;
        RECT 19.925 32.555 20.095 32.725 ;
        RECT 20.385 32.555 20.555 32.725 ;
        RECT 20.845 32.555 21.015 32.725 ;
        RECT 21.305 32.555 21.475 32.725 ;
        RECT 21.765 32.555 21.935 32.725 ;
        RECT 22.225 32.555 22.395 32.725 ;
        RECT 22.685 32.555 22.855 32.725 ;
        RECT 23.145 32.555 23.315 32.725 ;
        RECT 23.605 32.555 23.775 32.725 ;
        RECT 24.065 32.555 24.235 32.725 ;
        RECT 24.525 32.555 24.695 32.725 ;
        RECT 24.985 32.555 25.155 32.725 ;
        RECT 25.445 32.555 25.615 32.725 ;
        RECT 25.905 32.555 26.075 32.725 ;
        RECT 26.365 32.555 26.535 32.725 ;
        RECT 26.825 32.555 26.995 32.725 ;
        RECT 27.285 32.555 27.455 32.725 ;
        RECT 27.745 32.555 27.915 32.725 ;
        RECT 28.205 32.555 28.375 32.725 ;
        RECT 28.665 32.555 28.835 32.725 ;
        RECT 29.125 32.555 29.295 32.725 ;
        RECT 29.585 32.555 29.755 32.725 ;
        RECT 30.045 32.555 30.215 32.725 ;
        RECT 30.505 32.555 30.675 32.725 ;
        RECT 30.965 32.555 31.135 32.725 ;
        RECT 31.425 32.555 31.595 32.725 ;
        RECT 31.885 32.555 32.055 32.725 ;
        RECT 32.345 32.555 32.515 32.725 ;
        RECT 32.805 32.555 32.975 32.725 ;
        RECT 33.265 32.555 33.435 32.725 ;
        RECT 33.725 32.555 33.895 32.725 ;
        RECT 34.185 32.555 34.355 32.725 ;
        RECT 34.645 32.555 34.815 32.725 ;
        RECT 35.105 32.555 35.275 32.725 ;
        RECT 35.565 32.555 35.735 32.725 ;
        RECT 36.025 32.555 36.195 32.725 ;
        RECT 36.485 32.555 36.655 32.725 ;
        RECT 36.945 32.555 37.115 32.725 ;
        RECT 37.405 32.555 37.575 32.725 ;
        RECT 37.865 32.555 38.035 32.725 ;
        RECT 38.325 32.555 38.495 32.725 ;
        RECT 38.785 32.555 38.955 32.725 ;
        RECT 39.245 32.555 39.415 32.725 ;
        RECT 39.705 32.555 39.875 32.725 ;
        RECT 40.165 32.555 40.335 32.725 ;
        RECT 40.625 32.555 40.795 32.725 ;
        RECT 41.085 32.555 41.255 32.725 ;
        RECT 41.545 32.555 41.715 32.725 ;
        RECT 42.005 32.555 42.175 32.725 ;
        RECT 42.465 32.555 42.635 32.725 ;
        RECT 42.925 32.555 43.095 32.725 ;
        RECT 43.385 32.555 43.555 32.725 ;
        RECT 43.845 32.555 44.015 32.725 ;
        RECT 44.305 32.555 44.475 32.725 ;
        RECT 44.765 32.555 44.935 32.725 ;
        RECT 45.225 32.555 45.395 32.725 ;
        RECT 45.685 32.555 45.855 32.725 ;
        RECT 46.145 32.555 46.315 32.725 ;
        RECT 46.605 32.555 46.775 32.725 ;
        RECT 47.065 32.555 47.235 32.725 ;
        RECT 47.525 32.555 47.695 32.725 ;
        RECT 47.985 32.555 48.155 32.725 ;
        RECT 48.445 32.555 48.615 32.725 ;
        RECT 1.525 27.115 1.695 27.285 ;
        RECT 1.985 27.115 2.155 27.285 ;
        RECT 2.445 27.115 2.615 27.285 ;
        RECT 2.905 27.115 3.075 27.285 ;
        RECT 3.365 27.115 3.535 27.285 ;
        RECT 3.825 27.115 3.995 27.285 ;
        RECT 4.285 27.115 4.455 27.285 ;
        RECT 4.745 27.115 4.915 27.285 ;
        RECT 5.205 27.115 5.375 27.285 ;
        RECT 5.665 27.115 5.835 27.285 ;
        RECT 6.125 27.115 6.295 27.285 ;
        RECT 6.585 27.115 6.755 27.285 ;
        RECT 7.045 27.115 7.215 27.285 ;
        RECT 7.505 27.115 7.675 27.285 ;
        RECT 7.965 27.115 8.135 27.285 ;
        RECT 8.425 27.115 8.595 27.285 ;
        RECT 8.885 27.115 9.055 27.285 ;
        RECT 9.345 27.115 9.515 27.285 ;
        RECT 9.805 27.115 9.975 27.285 ;
        RECT 10.265 27.115 10.435 27.285 ;
        RECT 10.725 27.115 10.895 27.285 ;
        RECT 11.185 27.115 11.355 27.285 ;
        RECT 11.645 27.115 11.815 27.285 ;
        RECT 12.105 27.115 12.275 27.285 ;
        RECT 12.565 27.115 12.735 27.285 ;
        RECT 13.025 27.115 13.195 27.285 ;
        RECT 13.485 27.115 13.655 27.285 ;
        RECT 13.945 27.115 14.115 27.285 ;
        RECT 14.405 27.115 14.575 27.285 ;
        RECT 14.865 27.115 15.035 27.285 ;
        RECT 15.325 27.115 15.495 27.285 ;
        RECT 15.785 27.115 15.955 27.285 ;
        RECT 16.245 27.115 16.415 27.285 ;
        RECT 16.705 27.115 16.875 27.285 ;
        RECT 17.165 27.115 17.335 27.285 ;
        RECT 17.625 27.115 17.795 27.285 ;
        RECT 18.085 27.115 18.255 27.285 ;
        RECT 18.545 27.115 18.715 27.285 ;
        RECT 19.005 27.115 19.175 27.285 ;
        RECT 19.465 27.115 19.635 27.285 ;
        RECT 19.925 27.115 20.095 27.285 ;
        RECT 20.385 27.115 20.555 27.285 ;
        RECT 20.845 27.115 21.015 27.285 ;
        RECT 21.305 27.115 21.475 27.285 ;
        RECT 21.765 27.115 21.935 27.285 ;
        RECT 22.225 27.115 22.395 27.285 ;
        RECT 22.685 27.115 22.855 27.285 ;
        RECT 23.145 27.115 23.315 27.285 ;
        RECT 23.605 27.115 23.775 27.285 ;
        RECT 24.065 27.115 24.235 27.285 ;
        RECT 24.525 27.115 24.695 27.285 ;
        RECT 24.985 27.115 25.155 27.285 ;
        RECT 25.445 27.115 25.615 27.285 ;
        RECT 25.905 27.115 26.075 27.285 ;
        RECT 26.365 27.115 26.535 27.285 ;
        RECT 26.825 27.115 26.995 27.285 ;
        RECT 27.285 27.115 27.455 27.285 ;
        RECT 27.745 27.115 27.915 27.285 ;
        RECT 28.205 27.115 28.375 27.285 ;
        RECT 28.665 27.115 28.835 27.285 ;
        RECT 29.125 27.115 29.295 27.285 ;
        RECT 29.585 27.115 29.755 27.285 ;
        RECT 30.045 27.115 30.215 27.285 ;
        RECT 30.505 27.115 30.675 27.285 ;
        RECT 30.965 27.115 31.135 27.285 ;
        RECT 31.425 27.115 31.595 27.285 ;
        RECT 31.885 27.115 32.055 27.285 ;
        RECT 32.345 27.115 32.515 27.285 ;
        RECT 32.805 27.115 32.975 27.285 ;
        RECT 33.265 27.115 33.435 27.285 ;
        RECT 33.725 27.115 33.895 27.285 ;
        RECT 34.185 27.115 34.355 27.285 ;
        RECT 34.645 27.115 34.815 27.285 ;
        RECT 35.105 27.115 35.275 27.285 ;
        RECT 35.565 27.115 35.735 27.285 ;
        RECT 36.025 27.115 36.195 27.285 ;
        RECT 36.485 27.115 36.655 27.285 ;
        RECT 36.945 27.115 37.115 27.285 ;
        RECT 37.405 27.115 37.575 27.285 ;
        RECT 37.865 27.115 38.035 27.285 ;
        RECT 38.325 27.115 38.495 27.285 ;
        RECT 38.785 27.115 38.955 27.285 ;
        RECT 39.245 27.115 39.415 27.285 ;
        RECT 39.705 27.115 39.875 27.285 ;
        RECT 40.165 27.115 40.335 27.285 ;
        RECT 40.625 27.115 40.795 27.285 ;
        RECT 41.085 27.115 41.255 27.285 ;
        RECT 41.545 27.115 41.715 27.285 ;
        RECT 42.005 27.115 42.175 27.285 ;
        RECT 42.465 27.115 42.635 27.285 ;
        RECT 42.925 27.115 43.095 27.285 ;
        RECT 43.385 27.115 43.555 27.285 ;
        RECT 43.845 27.115 44.015 27.285 ;
        RECT 44.305 27.115 44.475 27.285 ;
        RECT 44.765 27.115 44.935 27.285 ;
        RECT 45.225 27.115 45.395 27.285 ;
        RECT 45.685 27.115 45.855 27.285 ;
        RECT 46.145 27.115 46.315 27.285 ;
        RECT 46.605 27.115 46.775 27.285 ;
        RECT 47.065 27.115 47.235 27.285 ;
        RECT 47.525 27.115 47.695 27.285 ;
        RECT 47.985 27.115 48.155 27.285 ;
        RECT 48.445 27.115 48.615 27.285 ;
        RECT 1.525 21.675 1.695 21.845 ;
        RECT 1.985 21.675 2.155 21.845 ;
        RECT 2.445 21.675 2.615 21.845 ;
        RECT 2.905 21.675 3.075 21.845 ;
        RECT 3.365 21.675 3.535 21.845 ;
        RECT 3.825 21.675 3.995 21.845 ;
        RECT 4.285 21.675 4.455 21.845 ;
        RECT 4.745 21.675 4.915 21.845 ;
        RECT 5.205 21.675 5.375 21.845 ;
        RECT 5.665 21.675 5.835 21.845 ;
        RECT 6.125 21.675 6.295 21.845 ;
        RECT 6.585 21.675 6.755 21.845 ;
        RECT 7.045 21.675 7.215 21.845 ;
        RECT 7.505 21.675 7.675 21.845 ;
        RECT 7.965 21.675 8.135 21.845 ;
        RECT 8.425 21.675 8.595 21.845 ;
        RECT 8.885 21.675 9.055 21.845 ;
        RECT 9.345 21.675 9.515 21.845 ;
        RECT 9.805 21.675 9.975 21.845 ;
        RECT 10.265 21.675 10.435 21.845 ;
        RECT 10.725 21.675 10.895 21.845 ;
        RECT 11.185 21.675 11.355 21.845 ;
        RECT 11.645 21.675 11.815 21.845 ;
        RECT 12.105 21.675 12.275 21.845 ;
        RECT 12.565 21.675 12.735 21.845 ;
        RECT 13.025 21.675 13.195 21.845 ;
        RECT 13.485 21.675 13.655 21.845 ;
        RECT 13.945 21.675 14.115 21.845 ;
        RECT 14.405 21.675 14.575 21.845 ;
        RECT 14.865 21.675 15.035 21.845 ;
        RECT 15.325 21.675 15.495 21.845 ;
        RECT 15.785 21.675 15.955 21.845 ;
        RECT 16.245 21.675 16.415 21.845 ;
        RECT 16.705 21.675 16.875 21.845 ;
        RECT 17.165 21.675 17.335 21.845 ;
        RECT 17.625 21.675 17.795 21.845 ;
        RECT 18.085 21.675 18.255 21.845 ;
        RECT 18.545 21.675 18.715 21.845 ;
        RECT 19.005 21.675 19.175 21.845 ;
        RECT 19.465 21.675 19.635 21.845 ;
        RECT 19.925 21.675 20.095 21.845 ;
        RECT 20.385 21.675 20.555 21.845 ;
        RECT 20.845 21.675 21.015 21.845 ;
        RECT 21.305 21.675 21.475 21.845 ;
        RECT 21.765 21.675 21.935 21.845 ;
        RECT 22.225 21.675 22.395 21.845 ;
        RECT 22.685 21.675 22.855 21.845 ;
        RECT 23.145 21.675 23.315 21.845 ;
        RECT 23.605 21.675 23.775 21.845 ;
        RECT 24.065 21.675 24.235 21.845 ;
        RECT 24.525 21.675 24.695 21.845 ;
        RECT 24.985 21.675 25.155 21.845 ;
        RECT 25.445 21.675 25.615 21.845 ;
        RECT 25.905 21.675 26.075 21.845 ;
        RECT 26.365 21.675 26.535 21.845 ;
        RECT 26.825 21.675 26.995 21.845 ;
        RECT 27.285 21.675 27.455 21.845 ;
        RECT 27.745 21.675 27.915 21.845 ;
        RECT 28.205 21.675 28.375 21.845 ;
        RECT 28.665 21.675 28.835 21.845 ;
        RECT 29.125 21.675 29.295 21.845 ;
        RECT 29.585 21.675 29.755 21.845 ;
        RECT 30.045 21.675 30.215 21.845 ;
        RECT 30.505 21.675 30.675 21.845 ;
        RECT 30.965 21.675 31.135 21.845 ;
        RECT 31.425 21.675 31.595 21.845 ;
        RECT 31.885 21.675 32.055 21.845 ;
        RECT 32.345 21.675 32.515 21.845 ;
        RECT 32.805 21.675 32.975 21.845 ;
        RECT 33.265 21.675 33.435 21.845 ;
        RECT 33.725 21.675 33.895 21.845 ;
        RECT 34.185 21.675 34.355 21.845 ;
        RECT 34.645 21.675 34.815 21.845 ;
        RECT 35.105 21.675 35.275 21.845 ;
        RECT 35.565 21.675 35.735 21.845 ;
        RECT 36.025 21.675 36.195 21.845 ;
        RECT 36.485 21.675 36.655 21.845 ;
        RECT 36.945 21.675 37.115 21.845 ;
        RECT 37.405 21.675 37.575 21.845 ;
        RECT 37.865 21.675 38.035 21.845 ;
        RECT 38.325 21.675 38.495 21.845 ;
        RECT 38.785 21.675 38.955 21.845 ;
        RECT 39.245 21.675 39.415 21.845 ;
        RECT 39.705 21.675 39.875 21.845 ;
        RECT 40.165 21.675 40.335 21.845 ;
        RECT 40.625 21.675 40.795 21.845 ;
        RECT 41.085 21.675 41.255 21.845 ;
        RECT 41.545 21.675 41.715 21.845 ;
        RECT 42.005 21.675 42.175 21.845 ;
        RECT 42.465 21.675 42.635 21.845 ;
        RECT 42.925 21.675 43.095 21.845 ;
        RECT 43.385 21.675 43.555 21.845 ;
        RECT 43.845 21.675 44.015 21.845 ;
        RECT 44.305 21.675 44.475 21.845 ;
        RECT 44.765 21.675 44.935 21.845 ;
        RECT 45.225 21.675 45.395 21.845 ;
        RECT 45.685 21.675 45.855 21.845 ;
        RECT 46.145 21.675 46.315 21.845 ;
        RECT 46.605 21.675 46.775 21.845 ;
        RECT 47.065 21.675 47.235 21.845 ;
        RECT 47.525 21.675 47.695 21.845 ;
        RECT 47.985 21.675 48.155 21.845 ;
        RECT 48.445 21.675 48.615 21.845 ;
        RECT 1.525 16.235 1.695 16.405 ;
        RECT 1.985 16.235 2.155 16.405 ;
        RECT 2.445 16.235 2.615 16.405 ;
        RECT 2.905 16.235 3.075 16.405 ;
        RECT 3.365 16.235 3.535 16.405 ;
        RECT 3.825 16.235 3.995 16.405 ;
        RECT 4.285 16.235 4.455 16.405 ;
        RECT 4.745 16.235 4.915 16.405 ;
        RECT 5.205 16.235 5.375 16.405 ;
        RECT 5.665 16.235 5.835 16.405 ;
        RECT 6.125 16.235 6.295 16.405 ;
        RECT 6.585 16.235 6.755 16.405 ;
        RECT 7.045 16.235 7.215 16.405 ;
        RECT 7.505 16.235 7.675 16.405 ;
        RECT 7.965 16.235 8.135 16.405 ;
        RECT 8.425 16.235 8.595 16.405 ;
        RECT 8.885 16.235 9.055 16.405 ;
        RECT 9.345 16.235 9.515 16.405 ;
        RECT 9.805 16.235 9.975 16.405 ;
        RECT 10.265 16.235 10.435 16.405 ;
        RECT 10.725 16.235 10.895 16.405 ;
        RECT 11.185 16.235 11.355 16.405 ;
        RECT 11.645 16.235 11.815 16.405 ;
        RECT 12.105 16.235 12.275 16.405 ;
        RECT 12.565 16.235 12.735 16.405 ;
        RECT 13.025 16.235 13.195 16.405 ;
        RECT 13.485 16.235 13.655 16.405 ;
        RECT 13.945 16.235 14.115 16.405 ;
        RECT 14.405 16.235 14.575 16.405 ;
        RECT 14.865 16.235 15.035 16.405 ;
        RECT 15.325 16.235 15.495 16.405 ;
        RECT 15.785 16.235 15.955 16.405 ;
        RECT 16.245 16.235 16.415 16.405 ;
        RECT 16.705 16.235 16.875 16.405 ;
        RECT 17.165 16.235 17.335 16.405 ;
        RECT 17.625 16.235 17.795 16.405 ;
        RECT 18.085 16.235 18.255 16.405 ;
        RECT 18.545 16.235 18.715 16.405 ;
        RECT 19.005 16.235 19.175 16.405 ;
        RECT 19.465 16.235 19.635 16.405 ;
        RECT 19.925 16.235 20.095 16.405 ;
        RECT 20.385 16.235 20.555 16.405 ;
        RECT 20.845 16.235 21.015 16.405 ;
        RECT 21.305 16.235 21.475 16.405 ;
        RECT 21.765 16.235 21.935 16.405 ;
        RECT 22.225 16.235 22.395 16.405 ;
        RECT 22.685 16.235 22.855 16.405 ;
        RECT 23.145 16.235 23.315 16.405 ;
        RECT 23.605 16.235 23.775 16.405 ;
        RECT 24.065 16.235 24.235 16.405 ;
        RECT 24.525 16.235 24.695 16.405 ;
        RECT 24.985 16.235 25.155 16.405 ;
        RECT 25.445 16.235 25.615 16.405 ;
        RECT 25.905 16.235 26.075 16.405 ;
        RECT 26.365 16.235 26.535 16.405 ;
        RECT 26.825 16.235 26.995 16.405 ;
        RECT 27.285 16.235 27.455 16.405 ;
        RECT 27.745 16.235 27.915 16.405 ;
        RECT 28.205 16.235 28.375 16.405 ;
        RECT 28.665 16.235 28.835 16.405 ;
        RECT 29.125 16.235 29.295 16.405 ;
        RECT 29.585 16.235 29.755 16.405 ;
        RECT 30.045 16.235 30.215 16.405 ;
        RECT 30.505 16.235 30.675 16.405 ;
        RECT 30.965 16.235 31.135 16.405 ;
        RECT 31.425 16.235 31.595 16.405 ;
        RECT 31.885 16.235 32.055 16.405 ;
        RECT 32.345 16.235 32.515 16.405 ;
        RECT 32.805 16.235 32.975 16.405 ;
        RECT 33.265 16.235 33.435 16.405 ;
        RECT 33.725 16.235 33.895 16.405 ;
        RECT 34.185 16.235 34.355 16.405 ;
        RECT 34.645 16.235 34.815 16.405 ;
        RECT 35.105 16.235 35.275 16.405 ;
        RECT 35.565 16.235 35.735 16.405 ;
        RECT 36.025 16.235 36.195 16.405 ;
        RECT 36.485 16.235 36.655 16.405 ;
        RECT 36.945 16.235 37.115 16.405 ;
        RECT 37.405 16.235 37.575 16.405 ;
        RECT 37.865 16.235 38.035 16.405 ;
        RECT 38.325 16.235 38.495 16.405 ;
        RECT 38.785 16.235 38.955 16.405 ;
        RECT 39.245 16.235 39.415 16.405 ;
        RECT 39.705 16.235 39.875 16.405 ;
        RECT 40.165 16.235 40.335 16.405 ;
        RECT 40.625 16.235 40.795 16.405 ;
        RECT 41.085 16.235 41.255 16.405 ;
        RECT 41.545 16.235 41.715 16.405 ;
        RECT 42.005 16.235 42.175 16.405 ;
        RECT 42.465 16.235 42.635 16.405 ;
        RECT 42.925 16.235 43.095 16.405 ;
        RECT 43.385 16.235 43.555 16.405 ;
        RECT 43.845 16.235 44.015 16.405 ;
        RECT 44.305 16.235 44.475 16.405 ;
        RECT 44.765 16.235 44.935 16.405 ;
        RECT 45.225 16.235 45.395 16.405 ;
        RECT 45.685 16.235 45.855 16.405 ;
        RECT 46.145 16.235 46.315 16.405 ;
        RECT 46.605 16.235 46.775 16.405 ;
        RECT 47.065 16.235 47.235 16.405 ;
        RECT 47.525 16.235 47.695 16.405 ;
        RECT 47.985 16.235 48.155 16.405 ;
        RECT 48.445 16.235 48.615 16.405 ;
        RECT 1.525 10.795 1.695 10.965 ;
        RECT 1.985 10.795 2.155 10.965 ;
        RECT 2.445 10.795 2.615 10.965 ;
        RECT 2.905 10.795 3.075 10.965 ;
        RECT 3.365 10.795 3.535 10.965 ;
        RECT 3.825 10.795 3.995 10.965 ;
        RECT 4.285 10.795 4.455 10.965 ;
        RECT 4.745 10.795 4.915 10.965 ;
        RECT 5.205 10.795 5.375 10.965 ;
        RECT 5.665 10.795 5.835 10.965 ;
        RECT 6.125 10.795 6.295 10.965 ;
        RECT 6.585 10.795 6.755 10.965 ;
        RECT 7.045 10.795 7.215 10.965 ;
        RECT 7.505 10.795 7.675 10.965 ;
        RECT 7.965 10.795 8.135 10.965 ;
        RECT 8.425 10.795 8.595 10.965 ;
        RECT 8.885 10.795 9.055 10.965 ;
        RECT 9.345 10.795 9.515 10.965 ;
        RECT 9.805 10.795 9.975 10.965 ;
        RECT 10.265 10.795 10.435 10.965 ;
        RECT 10.725 10.795 10.895 10.965 ;
        RECT 11.185 10.795 11.355 10.965 ;
        RECT 11.645 10.795 11.815 10.965 ;
        RECT 12.105 10.795 12.275 10.965 ;
        RECT 12.565 10.795 12.735 10.965 ;
        RECT 13.025 10.795 13.195 10.965 ;
        RECT 13.485 10.795 13.655 10.965 ;
        RECT 13.945 10.795 14.115 10.965 ;
        RECT 14.405 10.795 14.575 10.965 ;
        RECT 14.865 10.795 15.035 10.965 ;
        RECT 15.325 10.795 15.495 10.965 ;
        RECT 15.785 10.795 15.955 10.965 ;
        RECT 16.245 10.795 16.415 10.965 ;
        RECT 16.705 10.795 16.875 10.965 ;
        RECT 17.165 10.795 17.335 10.965 ;
        RECT 17.625 10.795 17.795 10.965 ;
        RECT 18.085 10.795 18.255 10.965 ;
        RECT 18.545 10.795 18.715 10.965 ;
        RECT 19.005 10.795 19.175 10.965 ;
        RECT 19.465 10.795 19.635 10.965 ;
        RECT 19.925 10.795 20.095 10.965 ;
        RECT 20.385 10.795 20.555 10.965 ;
        RECT 20.845 10.795 21.015 10.965 ;
        RECT 21.305 10.795 21.475 10.965 ;
        RECT 21.765 10.795 21.935 10.965 ;
        RECT 22.225 10.795 22.395 10.965 ;
        RECT 22.685 10.795 22.855 10.965 ;
        RECT 23.145 10.795 23.315 10.965 ;
        RECT 23.605 10.795 23.775 10.965 ;
        RECT 24.065 10.795 24.235 10.965 ;
        RECT 24.525 10.795 24.695 10.965 ;
        RECT 24.985 10.795 25.155 10.965 ;
        RECT 25.445 10.795 25.615 10.965 ;
        RECT 25.905 10.795 26.075 10.965 ;
        RECT 26.365 10.795 26.535 10.965 ;
        RECT 26.825 10.795 26.995 10.965 ;
        RECT 27.285 10.795 27.455 10.965 ;
        RECT 27.745 10.795 27.915 10.965 ;
        RECT 28.205 10.795 28.375 10.965 ;
        RECT 28.665 10.795 28.835 10.965 ;
        RECT 29.125 10.795 29.295 10.965 ;
        RECT 29.585 10.795 29.755 10.965 ;
        RECT 30.045 10.795 30.215 10.965 ;
        RECT 30.505 10.795 30.675 10.965 ;
        RECT 30.965 10.795 31.135 10.965 ;
        RECT 31.425 10.795 31.595 10.965 ;
        RECT 31.885 10.795 32.055 10.965 ;
        RECT 32.345 10.795 32.515 10.965 ;
        RECT 32.805 10.795 32.975 10.965 ;
        RECT 33.265 10.795 33.435 10.965 ;
        RECT 33.725 10.795 33.895 10.965 ;
        RECT 34.185 10.795 34.355 10.965 ;
        RECT 34.645 10.795 34.815 10.965 ;
        RECT 35.105 10.795 35.275 10.965 ;
        RECT 35.565 10.795 35.735 10.965 ;
        RECT 36.025 10.795 36.195 10.965 ;
        RECT 36.485 10.795 36.655 10.965 ;
        RECT 36.945 10.795 37.115 10.965 ;
        RECT 37.405 10.795 37.575 10.965 ;
        RECT 37.865 10.795 38.035 10.965 ;
        RECT 38.325 10.795 38.495 10.965 ;
        RECT 38.785 10.795 38.955 10.965 ;
        RECT 39.245 10.795 39.415 10.965 ;
        RECT 39.705 10.795 39.875 10.965 ;
        RECT 40.165 10.795 40.335 10.965 ;
        RECT 40.625 10.795 40.795 10.965 ;
        RECT 41.085 10.795 41.255 10.965 ;
        RECT 41.545 10.795 41.715 10.965 ;
        RECT 42.005 10.795 42.175 10.965 ;
        RECT 42.465 10.795 42.635 10.965 ;
        RECT 42.925 10.795 43.095 10.965 ;
        RECT 43.385 10.795 43.555 10.965 ;
        RECT 43.845 10.795 44.015 10.965 ;
        RECT 44.305 10.795 44.475 10.965 ;
        RECT 44.765 10.795 44.935 10.965 ;
        RECT 45.225 10.795 45.395 10.965 ;
        RECT 45.685 10.795 45.855 10.965 ;
        RECT 46.145 10.795 46.315 10.965 ;
        RECT 46.605 10.795 46.775 10.965 ;
        RECT 47.065 10.795 47.235 10.965 ;
        RECT 47.525 10.795 47.695 10.965 ;
        RECT 47.985 10.795 48.155 10.965 ;
        RECT 48.445 10.795 48.615 10.965 ;
        RECT 1.525 5.355 1.695 5.525 ;
        RECT 1.985 5.355 2.155 5.525 ;
        RECT 2.445 5.355 2.615 5.525 ;
        RECT 2.905 5.355 3.075 5.525 ;
        RECT 3.365 5.355 3.535 5.525 ;
        RECT 3.825 5.355 3.995 5.525 ;
        RECT 4.285 5.355 4.455 5.525 ;
        RECT 4.745 5.355 4.915 5.525 ;
        RECT 5.205 5.355 5.375 5.525 ;
        RECT 5.665 5.355 5.835 5.525 ;
        RECT 6.125 5.355 6.295 5.525 ;
        RECT 6.585 5.355 6.755 5.525 ;
        RECT 7.045 5.355 7.215 5.525 ;
        RECT 7.505 5.355 7.675 5.525 ;
        RECT 7.965 5.355 8.135 5.525 ;
        RECT 8.425 5.355 8.595 5.525 ;
        RECT 8.885 5.355 9.055 5.525 ;
        RECT 9.345 5.355 9.515 5.525 ;
        RECT 9.805 5.355 9.975 5.525 ;
        RECT 10.265 5.355 10.435 5.525 ;
        RECT 10.725 5.355 10.895 5.525 ;
        RECT 11.185 5.355 11.355 5.525 ;
        RECT 11.645 5.355 11.815 5.525 ;
        RECT 12.105 5.355 12.275 5.525 ;
        RECT 12.565 5.355 12.735 5.525 ;
        RECT 13.025 5.355 13.195 5.525 ;
        RECT 13.485 5.355 13.655 5.525 ;
        RECT 13.945 5.355 14.115 5.525 ;
        RECT 14.405 5.355 14.575 5.525 ;
        RECT 14.865 5.355 15.035 5.525 ;
        RECT 15.325 5.355 15.495 5.525 ;
        RECT 15.785 5.355 15.955 5.525 ;
        RECT 16.245 5.355 16.415 5.525 ;
        RECT 16.705 5.355 16.875 5.525 ;
        RECT 17.165 5.355 17.335 5.525 ;
        RECT 17.625 5.355 17.795 5.525 ;
        RECT 18.085 5.355 18.255 5.525 ;
        RECT 18.545 5.355 18.715 5.525 ;
        RECT 19.005 5.355 19.175 5.525 ;
        RECT 19.465 5.355 19.635 5.525 ;
        RECT 19.925 5.355 20.095 5.525 ;
        RECT 20.385 5.355 20.555 5.525 ;
        RECT 20.845 5.355 21.015 5.525 ;
        RECT 21.305 5.355 21.475 5.525 ;
        RECT 21.765 5.355 21.935 5.525 ;
        RECT 22.225 5.355 22.395 5.525 ;
        RECT 22.685 5.355 22.855 5.525 ;
        RECT 23.145 5.355 23.315 5.525 ;
        RECT 23.605 5.355 23.775 5.525 ;
        RECT 24.065 5.355 24.235 5.525 ;
        RECT 24.525 5.355 24.695 5.525 ;
        RECT 24.985 5.355 25.155 5.525 ;
        RECT 25.445 5.355 25.615 5.525 ;
        RECT 25.905 5.355 26.075 5.525 ;
        RECT 26.365 5.355 26.535 5.525 ;
        RECT 26.825 5.355 26.995 5.525 ;
        RECT 27.285 5.355 27.455 5.525 ;
        RECT 27.745 5.355 27.915 5.525 ;
        RECT 28.205 5.355 28.375 5.525 ;
        RECT 28.665 5.355 28.835 5.525 ;
        RECT 29.125 5.355 29.295 5.525 ;
        RECT 29.585 5.355 29.755 5.525 ;
        RECT 30.045 5.355 30.215 5.525 ;
        RECT 30.505 5.355 30.675 5.525 ;
        RECT 30.965 5.355 31.135 5.525 ;
        RECT 31.425 5.355 31.595 5.525 ;
        RECT 31.885 5.355 32.055 5.525 ;
        RECT 32.345 5.355 32.515 5.525 ;
        RECT 32.805 5.355 32.975 5.525 ;
        RECT 33.265 5.355 33.435 5.525 ;
        RECT 33.725 5.355 33.895 5.525 ;
        RECT 34.185 5.355 34.355 5.525 ;
        RECT 34.645 5.355 34.815 5.525 ;
        RECT 35.105 5.355 35.275 5.525 ;
        RECT 35.565 5.355 35.735 5.525 ;
        RECT 36.025 5.355 36.195 5.525 ;
        RECT 36.485 5.355 36.655 5.525 ;
        RECT 36.945 5.355 37.115 5.525 ;
        RECT 37.405 5.355 37.575 5.525 ;
        RECT 37.865 5.355 38.035 5.525 ;
        RECT 38.325 5.355 38.495 5.525 ;
        RECT 38.785 5.355 38.955 5.525 ;
        RECT 39.245 5.355 39.415 5.525 ;
        RECT 39.705 5.355 39.875 5.525 ;
        RECT 40.165 5.355 40.335 5.525 ;
        RECT 40.625 5.355 40.795 5.525 ;
        RECT 41.085 5.355 41.255 5.525 ;
        RECT 41.545 5.355 41.715 5.525 ;
        RECT 42.005 5.355 42.175 5.525 ;
        RECT 42.465 5.355 42.635 5.525 ;
        RECT 42.925 5.355 43.095 5.525 ;
        RECT 43.385 5.355 43.555 5.525 ;
        RECT 43.845 5.355 44.015 5.525 ;
        RECT 44.305 5.355 44.475 5.525 ;
        RECT 44.765 5.355 44.935 5.525 ;
        RECT 45.225 5.355 45.395 5.525 ;
        RECT 45.685 5.355 45.855 5.525 ;
        RECT 46.145 5.355 46.315 5.525 ;
        RECT 46.605 5.355 46.775 5.525 ;
        RECT 47.065 5.355 47.235 5.525 ;
        RECT 47.525 5.355 47.695 5.525 ;
        RECT 47.985 5.355 48.155 5.525 ;
        RECT 48.445 5.355 48.615 5.525 ;
      LAYER met1 ;
        RECT -10.620 37.840 60.760 38.320 ;
        RECT -10.620 32.400 60.760 32.880 ;
        RECT -10.620 26.960 60.760 27.440 ;
        RECT -10.620 21.520 60.760 22.000 ;
        RECT -10.620 16.080 60.760 16.560 ;
        RECT -10.620 10.640 60.760 11.120 ;
        RECT -10.620 5.200 60.760 5.680 ;
      LAYER via ;
        RECT -4.770 37.950 -4.510 38.210 ;
        RECT -4.450 37.950 -4.190 38.210 ;
        RECT -4.130 37.950 -3.870 38.210 ;
        RECT -3.810 37.950 -3.550 38.210 ;
        RECT -3.490 37.950 -3.230 38.210 ;
        RECT -3.170 37.950 -2.910 38.210 ;
        RECT -2.850 37.950 -2.590 38.210 ;
        RECT -2.530 37.950 -2.270 38.210 ;
        RECT -2.210 37.950 -1.950 38.210 ;
        RECT -1.890 37.950 -1.630 38.210 ;
        RECT -1.570 37.950 -1.310 38.210 ;
        RECT -1.250 37.950 -0.990 38.210 ;
        RECT -0.930 37.950 -0.670 38.210 ;
        RECT 14.180 37.950 14.440 38.210 ;
        RECT 14.500 37.950 14.760 38.210 ;
        RECT 14.820 37.950 15.080 38.210 ;
        RECT 15.140 37.950 15.400 38.210 ;
        RECT 15.460 37.950 15.720 38.210 ;
        RECT 41.320 37.950 41.580 38.210 ;
        RECT 41.640 37.950 41.900 38.210 ;
        RECT 41.960 37.950 42.220 38.210 ;
        RECT 42.280 37.950 42.540 38.210 ;
        RECT 42.600 37.950 42.860 38.210 ;
        RECT 50.810 37.950 51.070 38.210 ;
        RECT 51.130 37.950 51.390 38.210 ;
        RECT 51.450 37.950 51.710 38.210 ;
        RECT 51.770 37.950 52.030 38.210 ;
        RECT 52.090 37.950 52.350 38.210 ;
        RECT 52.410 37.950 52.670 38.210 ;
        RECT 52.730 37.950 52.990 38.210 ;
        RECT 53.050 37.950 53.310 38.210 ;
        RECT 53.370 37.950 53.630 38.210 ;
        RECT 53.690 37.950 53.950 38.210 ;
        RECT 54.010 37.950 54.270 38.210 ;
        RECT 54.330 37.950 54.590 38.210 ;
        RECT 54.650 37.950 54.910 38.210 ;
        RECT -4.770 32.510 -4.510 32.770 ;
        RECT -4.450 32.510 -4.190 32.770 ;
        RECT -4.130 32.510 -3.870 32.770 ;
        RECT -3.810 32.510 -3.550 32.770 ;
        RECT -3.490 32.510 -3.230 32.770 ;
        RECT -3.170 32.510 -2.910 32.770 ;
        RECT -2.850 32.510 -2.590 32.770 ;
        RECT -2.530 32.510 -2.270 32.770 ;
        RECT -2.210 32.510 -1.950 32.770 ;
        RECT -1.890 32.510 -1.630 32.770 ;
        RECT -1.570 32.510 -1.310 32.770 ;
        RECT -1.250 32.510 -0.990 32.770 ;
        RECT -0.930 32.510 -0.670 32.770 ;
        RECT 14.180 32.510 14.440 32.770 ;
        RECT 14.500 32.510 14.760 32.770 ;
        RECT 14.820 32.510 15.080 32.770 ;
        RECT 15.140 32.510 15.400 32.770 ;
        RECT 15.460 32.510 15.720 32.770 ;
        RECT 41.320 32.510 41.580 32.770 ;
        RECT 41.640 32.510 41.900 32.770 ;
        RECT 41.960 32.510 42.220 32.770 ;
        RECT 42.280 32.510 42.540 32.770 ;
        RECT 42.600 32.510 42.860 32.770 ;
        RECT 50.810 32.510 51.070 32.770 ;
        RECT 51.130 32.510 51.390 32.770 ;
        RECT 51.450 32.510 51.710 32.770 ;
        RECT 51.770 32.510 52.030 32.770 ;
        RECT 52.090 32.510 52.350 32.770 ;
        RECT 52.410 32.510 52.670 32.770 ;
        RECT 52.730 32.510 52.990 32.770 ;
        RECT 53.050 32.510 53.310 32.770 ;
        RECT 53.370 32.510 53.630 32.770 ;
        RECT 53.690 32.510 53.950 32.770 ;
        RECT 54.010 32.510 54.270 32.770 ;
        RECT 54.330 32.510 54.590 32.770 ;
        RECT 54.650 32.510 54.910 32.770 ;
        RECT -4.770 27.070 -4.510 27.330 ;
        RECT -4.450 27.070 -4.190 27.330 ;
        RECT -4.130 27.070 -3.870 27.330 ;
        RECT -3.810 27.070 -3.550 27.330 ;
        RECT -3.490 27.070 -3.230 27.330 ;
        RECT -3.170 27.070 -2.910 27.330 ;
        RECT -2.850 27.070 -2.590 27.330 ;
        RECT -2.530 27.070 -2.270 27.330 ;
        RECT -2.210 27.070 -1.950 27.330 ;
        RECT -1.890 27.070 -1.630 27.330 ;
        RECT -1.570 27.070 -1.310 27.330 ;
        RECT -1.250 27.070 -0.990 27.330 ;
        RECT -0.930 27.070 -0.670 27.330 ;
        RECT 14.180 27.070 14.440 27.330 ;
        RECT 14.500 27.070 14.760 27.330 ;
        RECT 14.820 27.070 15.080 27.330 ;
        RECT 15.140 27.070 15.400 27.330 ;
        RECT 15.460 27.070 15.720 27.330 ;
        RECT 41.320 27.070 41.580 27.330 ;
        RECT 41.640 27.070 41.900 27.330 ;
        RECT 41.960 27.070 42.220 27.330 ;
        RECT 42.280 27.070 42.540 27.330 ;
        RECT 42.600 27.070 42.860 27.330 ;
        RECT 50.810 27.070 51.070 27.330 ;
        RECT 51.130 27.070 51.390 27.330 ;
        RECT 51.450 27.070 51.710 27.330 ;
        RECT 51.770 27.070 52.030 27.330 ;
        RECT 52.090 27.070 52.350 27.330 ;
        RECT 52.410 27.070 52.670 27.330 ;
        RECT 52.730 27.070 52.990 27.330 ;
        RECT 53.050 27.070 53.310 27.330 ;
        RECT 53.370 27.070 53.630 27.330 ;
        RECT 53.690 27.070 53.950 27.330 ;
        RECT 54.010 27.070 54.270 27.330 ;
        RECT 54.330 27.070 54.590 27.330 ;
        RECT 54.650 27.070 54.910 27.330 ;
        RECT -4.770 21.630 -4.510 21.890 ;
        RECT -4.450 21.630 -4.190 21.890 ;
        RECT -4.130 21.630 -3.870 21.890 ;
        RECT -3.810 21.630 -3.550 21.890 ;
        RECT -3.490 21.630 -3.230 21.890 ;
        RECT -3.170 21.630 -2.910 21.890 ;
        RECT -2.850 21.630 -2.590 21.890 ;
        RECT -2.530 21.630 -2.270 21.890 ;
        RECT -2.210 21.630 -1.950 21.890 ;
        RECT -1.890 21.630 -1.630 21.890 ;
        RECT -1.570 21.630 -1.310 21.890 ;
        RECT -1.250 21.630 -0.990 21.890 ;
        RECT -0.930 21.630 -0.670 21.890 ;
        RECT 14.180 21.630 14.440 21.890 ;
        RECT 14.500 21.630 14.760 21.890 ;
        RECT 14.820 21.630 15.080 21.890 ;
        RECT 15.140 21.630 15.400 21.890 ;
        RECT 15.460 21.630 15.720 21.890 ;
        RECT 41.320 21.630 41.580 21.890 ;
        RECT 41.640 21.630 41.900 21.890 ;
        RECT 41.960 21.630 42.220 21.890 ;
        RECT 42.280 21.630 42.540 21.890 ;
        RECT 42.600 21.630 42.860 21.890 ;
        RECT 50.810 21.630 51.070 21.890 ;
        RECT 51.130 21.630 51.390 21.890 ;
        RECT 51.450 21.630 51.710 21.890 ;
        RECT 51.770 21.630 52.030 21.890 ;
        RECT 52.090 21.630 52.350 21.890 ;
        RECT 52.410 21.630 52.670 21.890 ;
        RECT 52.730 21.630 52.990 21.890 ;
        RECT 53.050 21.630 53.310 21.890 ;
        RECT 53.370 21.630 53.630 21.890 ;
        RECT 53.690 21.630 53.950 21.890 ;
        RECT 54.010 21.630 54.270 21.890 ;
        RECT 54.330 21.630 54.590 21.890 ;
        RECT 54.650 21.630 54.910 21.890 ;
        RECT -4.770 16.190 -4.510 16.450 ;
        RECT -4.450 16.190 -4.190 16.450 ;
        RECT -4.130 16.190 -3.870 16.450 ;
        RECT -3.810 16.190 -3.550 16.450 ;
        RECT -3.490 16.190 -3.230 16.450 ;
        RECT -3.170 16.190 -2.910 16.450 ;
        RECT -2.850 16.190 -2.590 16.450 ;
        RECT -2.530 16.190 -2.270 16.450 ;
        RECT -2.210 16.190 -1.950 16.450 ;
        RECT -1.890 16.190 -1.630 16.450 ;
        RECT -1.570 16.190 -1.310 16.450 ;
        RECT -1.250 16.190 -0.990 16.450 ;
        RECT -0.930 16.190 -0.670 16.450 ;
        RECT 14.180 16.190 14.440 16.450 ;
        RECT 14.500 16.190 14.760 16.450 ;
        RECT 14.820 16.190 15.080 16.450 ;
        RECT 15.140 16.190 15.400 16.450 ;
        RECT 15.460 16.190 15.720 16.450 ;
        RECT 41.320 16.190 41.580 16.450 ;
        RECT 41.640 16.190 41.900 16.450 ;
        RECT 41.960 16.190 42.220 16.450 ;
        RECT 42.280 16.190 42.540 16.450 ;
        RECT 42.600 16.190 42.860 16.450 ;
        RECT 50.810 16.190 51.070 16.450 ;
        RECT 51.130 16.190 51.390 16.450 ;
        RECT 51.450 16.190 51.710 16.450 ;
        RECT 51.770 16.190 52.030 16.450 ;
        RECT 52.090 16.190 52.350 16.450 ;
        RECT 52.410 16.190 52.670 16.450 ;
        RECT 52.730 16.190 52.990 16.450 ;
        RECT 53.050 16.190 53.310 16.450 ;
        RECT 53.370 16.190 53.630 16.450 ;
        RECT 53.690 16.190 53.950 16.450 ;
        RECT 54.010 16.190 54.270 16.450 ;
        RECT 54.330 16.190 54.590 16.450 ;
        RECT 54.650 16.190 54.910 16.450 ;
        RECT -4.770 10.750 -4.510 11.010 ;
        RECT -4.450 10.750 -4.190 11.010 ;
        RECT -4.130 10.750 -3.870 11.010 ;
        RECT -3.810 10.750 -3.550 11.010 ;
        RECT -3.490 10.750 -3.230 11.010 ;
        RECT -3.170 10.750 -2.910 11.010 ;
        RECT -2.850 10.750 -2.590 11.010 ;
        RECT -2.530 10.750 -2.270 11.010 ;
        RECT -2.210 10.750 -1.950 11.010 ;
        RECT -1.890 10.750 -1.630 11.010 ;
        RECT -1.570 10.750 -1.310 11.010 ;
        RECT -1.250 10.750 -0.990 11.010 ;
        RECT -0.930 10.750 -0.670 11.010 ;
        RECT 14.180 10.750 14.440 11.010 ;
        RECT 14.500 10.750 14.760 11.010 ;
        RECT 14.820 10.750 15.080 11.010 ;
        RECT 15.140 10.750 15.400 11.010 ;
        RECT 15.460 10.750 15.720 11.010 ;
        RECT 41.320 10.750 41.580 11.010 ;
        RECT 41.640 10.750 41.900 11.010 ;
        RECT 41.960 10.750 42.220 11.010 ;
        RECT 42.280 10.750 42.540 11.010 ;
        RECT 42.600 10.750 42.860 11.010 ;
        RECT 50.810 10.750 51.070 11.010 ;
        RECT 51.130 10.750 51.390 11.010 ;
        RECT 51.450 10.750 51.710 11.010 ;
        RECT 51.770 10.750 52.030 11.010 ;
        RECT 52.090 10.750 52.350 11.010 ;
        RECT 52.410 10.750 52.670 11.010 ;
        RECT 52.730 10.750 52.990 11.010 ;
        RECT 53.050 10.750 53.310 11.010 ;
        RECT 53.370 10.750 53.630 11.010 ;
        RECT 53.690 10.750 53.950 11.010 ;
        RECT 54.010 10.750 54.270 11.010 ;
        RECT 54.330 10.750 54.590 11.010 ;
        RECT 54.650 10.750 54.910 11.010 ;
        RECT -4.770 5.310 -4.510 5.570 ;
        RECT -4.450 5.310 -4.190 5.570 ;
        RECT -4.130 5.310 -3.870 5.570 ;
        RECT -3.810 5.310 -3.550 5.570 ;
        RECT -3.490 5.310 -3.230 5.570 ;
        RECT -3.170 5.310 -2.910 5.570 ;
        RECT -2.850 5.310 -2.590 5.570 ;
        RECT -2.530 5.310 -2.270 5.570 ;
        RECT -2.210 5.310 -1.950 5.570 ;
        RECT -1.890 5.310 -1.630 5.570 ;
        RECT -1.570 5.310 -1.310 5.570 ;
        RECT -1.250 5.310 -0.990 5.570 ;
        RECT -0.930 5.310 -0.670 5.570 ;
        RECT 14.180 5.310 14.440 5.570 ;
        RECT 14.500 5.310 14.760 5.570 ;
        RECT 14.820 5.310 15.080 5.570 ;
        RECT 15.140 5.310 15.400 5.570 ;
        RECT 15.460 5.310 15.720 5.570 ;
        RECT 41.320 5.310 41.580 5.570 ;
        RECT 41.640 5.310 41.900 5.570 ;
        RECT 41.960 5.310 42.220 5.570 ;
        RECT 42.280 5.310 42.540 5.570 ;
        RECT 42.600 5.310 42.860 5.570 ;
        RECT 50.810 5.310 51.070 5.570 ;
        RECT 51.130 5.310 51.390 5.570 ;
        RECT 51.450 5.310 51.710 5.570 ;
        RECT 51.770 5.310 52.030 5.570 ;
        RECT 52.090 5.310 52.350 5.570 ;
        RECT 52.410 5.310 52.670 5.570 ;
        RECT 52.730 5.310 52.990 5.570 ;
        RECT 53.050 5.310 53.310 5.570 ;
        RECT 53.370 5.310 53.630 5.570 ;
        RECT 53.690 5.310 53.950 5.570 ;
        RECT 54.010 5.310 54.270 5.570 ;
        RECT 54.330 5.310 54.590 5.570 ;
        RECT 54.650 5.310 54.910 5.570 ;
      LAYER met2 ;
        RECT -4.770 37.840 -0.670 38.320 ;
        RECT 14.180 37.840 15.720 38.320 ;
        RECT 41.320 37.840 42.860 38.320 ;
        RECT 50.810 37.840 54.910 38.320 ;
        RECT -4.770 32.400 -0.670 32.880 ;
        RECT 14.180 32.400 15.720 32.880 ;
        RECT 41.320 32.400 42.860 32.880 ;
        RECT 50.810 32.400 54.910 32.880 ;
        RECT -4.770 26.960 -0.670 27.440 ;
        RECT 14.180 26.960 15.720 27.440 ;
        RECT 41.320 26.960 42.860 27.440 ;
        RECT 50.810 26.960 54.910 27.440 ;
        RECT -4.770 21.520 -0.670 22.000 ;
        RECT 14.180 21.520 15.720 22.000 ;
        RECT 41.320 21.520 42.860 22.000 ;
        RECT 50.810 21.520 54.910 22.000 ;
        RECT -4.770 16.080 -0.670 16.560 ;
        RECT 14.180 16.080 15.720 16.560 ;
        RECT 41.320 16.080 42.860 16.560 ;
        RECT 50.810 16.080 54.910 16.560 ;
        RECT -4.770 10.640 -0.670 11.120 ;
        RECT 14.180 10.640 15.720 11.120 ;
        RECT 41.320 10.640 42.860 11.120 ;
        RECT 50.810 10.640 54.910 11.120 ;
        RECT -4.770 5.200 -0.670 5.680 ;
        RECT 14.180 5.200 15.720 5.680 ;
        RECT 41.320 5.200 42.860 5.680 ;
        RECT 50.810 5.200 54.910 5.680 ;
      LAYER via2 ;
        RECT -4.660 37.940 -4.380 38.220 ;
        RECT -4.260 37.940 -3.980 38.220 ;
        RECT -3.860 37.940 -3.580 38.220 ;
        RECT -3.460 37.940 -3.180 38.220 ;
        RECT -3.060 37.940 -2.780 38.220 ;
        RECT -2.660 37.940 -2.380 38.220 ;
        RECT -2.260 37.940 -1.980 38.220 ;
        RECT -1.860 37.940 -1.580 38.220 ;
        RECT -1.460 37.940 -1.180 38.220 ;
        RECT -1.060 37.940 -0.780 38.220 ;
        RECT 14.210 37.940 14.490 38.220 ;
        RECT 14.610 37.940 14.890 38.220 ;
        RECT 15.010 37.940 15.290 38.220 ;
        RECT 15.410 37.940 15.690 38.220 ;
        RECT 41.350 37.940 41.630 38.220 ;
        RECT 41.750 37.940 42.030 38.220 ;
        RECT 42.150 37.940 42.430 38.220 ;
        RECT 42.550 37.940 42.830 38.220 ;
        RECT 50.920 37.940 51.200 38.220 ;
        RECT 51.320 37.940 51.600 38.220 ;
        RECT 51.720 37.940 52.000 38.220 ;
        RECT 52.120 37.940 52.400 38.220 ;
        RECT 52.520 37.940 52.800 38.220 ;
        RECT 52.920 37.940 53.200 38.220 ;
        RECT 53.320 37.940 53.600 38.220 ;
        RECT 53.720 37.940 54.000 38.220 ;
        RECT 54.120 37.940 54.400 38.220 ;
        RECT 54.520 37.940 54.800 38.220 ;
        RECT -4.660 32.500 -4.380 32.780 ;
        RECT -4.260 32.500 -3.980 32.780 ;
        RECT -3.860 32.500 -3.580 32.780 ;
        RECT -3.460 32.500 -3.180 32.780 ;
        RECT -3.060 32.500 -2.780 32.780 ;
        RECT -2.660 32.500 -2.380 32.780 ;
        RECT -2.260 32.500 -1.980 32.780 ;
        RECT -1.860 32.500 -1.580 32.780 ;
        RECT -1.460 32.500 -1.180 32.780 ;
        RECT -1.060 32.500 -0.780 32.780 ;
        RECT 14.210 32.500 14.490 32.780 ;
        RECT 14.610 32.500 14.890 32.780 ;
        RECT 15.010 32.500 15.290 32.780 ;
        RECT 15.410 32.500 15.690 32.780 ;
        RECT 41.350 32.500 41.630 32.780 ;
        RECT 41.750 32.500 42.030 32.780 ;
        RECT 42.150 32.500 42.430 32.780 ;
        RECT 42.550 32.500 42.830 32.780 ;
        RECT 50.920 32.500 51.200 32.780 ;
        RECT 51.320 32.500 51.600 32.780 ;
        RECT 51.720 32.500 52.000 32.780 ;
        RECT 52.120 32.500 52.400 32.780 ;
        RECT 52.520 32.500 52.800 32.780 ;
        RECT 52.920 32.500 53.200 32.780 ;
        RECT 53.320 32.500 53.600 32.780 ;
        RECT 53.720 32.500 54.000 32.780 ;
        RECT 54.120 32.500 54.400 32.780 ;
        RECT 54.520 32.500 54.800 32.780 ;
        RECT -4.660 27.060 -4.380 27.340 ;
        RECT -4.260 27.060 -3.980 27.340 ;
        RECT -3.860 27.060 -3.580 27.340 ;
        RECT -3.460 27.060 -3.180 27.340 ;
        RECT -3.060 27.060 -2.780 27.340 ;
        RECT -2.660 27.060 -2.380 27.340 ;
        RECT -2.260 27.060 -1.980 27.340 ;
        RECT -1.860 27.060 -1.580 27.340 ;
        RECT -1.460 27.060 -1.180 27.340 ;
        RECT -1.060 27.060 -0.780 27.340 ;
        RECT 14.210 27.060 14.490 27.340 ;
        RECT 14.610 27.060 14.890 27.340 ;
        RECT 15.010 27.060 15.290 27.340 ;
        RECT 15.410 27.060 15.690 27.340 ;
        RECT 41.350 27.060 41.630 27.340 ;
        RECT 41.750 27.060 42.030 27.340 ;
        RECT 42.150 27.060 42.430 27.340 ;
        RECT 42.550 27.060 42.830 27.340 ;
        RECT 50.920 27.060 51.200 27.340 ;
        RECT 51.320 27.060 51.600 27.340 ;
        RECT 51.720 27.060 52.000 27.340 ;
        RECT 52.120 27.060 52.400 27.340 ;
        RECT 52.520 27.060 52.800 27.340 ;
        RECT 52.920 27.060 53.200 27.340 ;
        RECT 53.320 27.060 53.600 27.340 ;
        RECT 53.720 27.060 54.000 27.340 ;
        RECT 54.120 27.060 54.400 27.340 ;
        RECT 54.520 27.060 54.800 27.340 ;
        RECT -4.660 21.620 -4.380 21.900 ;
        RECT -4.260 21.620 -3.980 21.900 ;
        RECT -3.860 21.620 -3.580 21.900 ;
        RECT -3.460 21.620 -3.180 21.900 ;
        RECT -3.060 21.620 -2.780 21.900 ;
        RECT -2.660 21.620 -2.380 21.900 ;
        RECT -2.260 21.620 -1.980 21.900 ;
        RECT -1.860 21.620 -1.580 21.900 ;
        RECT -1.460 21.620 -1.180 21.900 ;
        RECT -1.060 21.620 -0.780 21.900 ;
        RECT 14.210 21.620 14.490 21.900 ;
        RECT 14.610 21.620 14.890 21.900 ;
        RECT 15.010 21.620 15.290 21.900 ;
        RECT 15.410 21.620 15.690 21.900 ;
        RECT 41.350 21.620 41.630 21.900 ;
        RECT 41.750 21.620 42.030 21.900 ;
        RECT 42.150 21.620 42.430 21.900 ;
        RECT 42.550 21.620 42.830 21.900 ;
        RECT 50.920 21.620 51.200 21.900 ;
        RECT 51.320 21.620 51.600 21.900 ;
        RECT 51.720 21.620 52.000 21.900 ;
        RECT 52.120 21.620 52.400 21.900 ;
        RECT 52.520 21.620 52.800 21.900 ;
        RECT 52.920 21.620 53.200 21.900 ;
        RECT 53.320 21.620 53.600 21.900 ;
        RECT 53.720 21.620 54.000 21.900 ;
        RECT 54.120 21.620 54.400 21.900 ;
        RECT 54.520 21.620 54.800 21.900 ;
        RECT -4.660 16.180 -4.380 16.460 ;
        RECT -4.260 16.180 -3.980 16.460 ;
        RECT -3.860 16.180 -3.580 16.460 ;
        RECT -3.460 16.180 -3.180 16.460 ;
        RECT -3.060 16.180 -2.780 16.460 ;
        RECT -2.660 16.180 -2.380 16.460 ;
        RECT -2.260 16.180 -1.980 16.460 ;
        RECT -1.860 16.180 -1.580 16.460 ;
        RECT -1.460 16.180 -1.180 16.460 ;
        RECT -1.060 16.180 -0.780 16.460 ;
        RECT 14.210 16.180 14.490 16.460 ;
        RECT 14.610 16.180 14.890 16.460 ;
        RECT 15.010 16.180 15.290 16.460 ;
        RECT 15.410 16.180 15.690 16.460 ;
        RECT 41.350 16.180 41.630 16.460 ;
        RECT 41.750 16.180 42.030 16.460 ;
        RECT 42.150 16.180 42.430 16.460 ;
        RECT 42.550 16.180 42.830 16.460 ;
        RECT 50.920 16.180 51.200 16.460 ;
        RECT 51.320 16.180 51.600 16.460 ;
        RECT 51.720 16.180 52.000 16.460 ;
        RECT 52.120 16.180 52.400 16.460 ;
        RECT 52.520 16.180 52.800 16.460 ;
        RECT 52.920 16.180 53.200 16.460 ;
        RECT 53.320 16.180 53.600 16.460 ;
        RECT 53.720 16.180 54.000 16.460 ;
        RECT 54.120 16.180 54.400 16.460 ;
        RECT 54.520 16.180 54.800 16.460 ;
        RECT -4.660 10.740 -4.380 11.020 ;
        RECT -4.260 10.740 -3.980 11.020 ;
        RECT -3.860 10.740 -3.580 11.020 ;
        RECT -3.460 10.740 -3.180 11.020 ;
        RECT -3.060 10.740 -2.780 11.020 ;
        RECT -2.660 10.740 -2.380 11.020 ;
        RECT -2.260 10.740 -1.980 11.020 ;
        RECT -1.860 10.740 -1.580 11.020 ;
        RECT -1.460 10.740 -1.180 11.020 ;
        RECT -1.060 10.740 -0.780 11.020 ;
        RECT 14.210 10.740 14.490 11.020 ;
        RECT 14.610 10.740 14.890 11.020 ;
        RECT 15.010 10.740 15.290 11.020 ;
        RECT 15.410 10.740 15.690 11.020 ;
        RECT 41.350 10.740 41.630 11.020 ;
        RECT 41.750 10.740 42.030 11.020 ;
        RECT 42.150 10.740 42.430 11.020 ;
        RECT 42.550 10.740 42.830 11.020 ;
        RECT 50.920 10.740 51.200 11.020 ;
        RECT 51.320 10.740 51.600 11.020 ;
        RECT 51.720 10.740 52.000 11.020 ;
        RECT 52.120 10.740 52.400 11.020 ;
        RECT 52.520 10.740 52.800 11.020 ;
        RECT 52.920 10.740 53.200 11.020 ;
        RECT 53.320 10.740 53.600 11.020 ;
        RECT 53.720 10.740 54.000 11.020 ;
        RECT 54.120 10.740 54.400 11.020 ;
        RECT 54.520 10.740 54.800 11.020 ;
        RECT -4.660 5.300 -4.380 5.580 ;
        RECT -4.260 5.300 -3.980 5.580 ;
        RECT -3.860 5.300 -3.580 5.580 ;
        RECT -3.460 5.300 -3.180 5.580 ;
        RECT -3.060 5.300 -2.780 5.580 ;
        RECT -2.660 5.300 -2.380 5.580 ;
        RECT -2.260 5.300 -1.980 5.580 ;
        RECT -1.860 5.300 -1.580 5.580 ;
        RECT -1.460 5.300 -1.180 5.580 ;
        RECT -1.060 5.300 -0.780 5.580 ;
        RECT 14.210 5.300 14.490 5.580 ;
        RECT 14.610 5.300 14.890 5.580 ;
        RECT 15.010 5.300 15.290 5.580 ;
        RECT 15.410 5.300 15.690 5.580 ;
        RECT 41.350 5.300 41.630 5.580 ;
        RECT 41.750 5.300 42.030 5.580 ;
        RECT 42.150 5.300 42.430 5.580 ;
        RECT 42.550 5.300 42.830 5.580 ;
        RECT 50.920 5.300 51.200 5.580 ;
        RECT 51.320 5.300 51.600 5.580 ;
        RECT 51.720 5.300 52.000 5.580 ;
        RECT 52.120 5.300 52.400 5.580 ;
        RECT 52.520 5.300 52.800 5.580 ;
        RECT 52.920 5.300 53.200 5.580 ;
        RECT 53.320 5.300 53.600 5.580 ;
        RECT 53.720 5.300 54.000 5.580 ;
        RECT 54.120 5.300 54.400 5.580 ;
        RECT 54.520 5.300 54.800 5.580 ;
      LAYER met3 ;
        RECT -4.820 37.915 -0.620 38.245 ;
        RECT 14.150 37.915 15.750 38.245 ;
        RECT 41.290 37.915 42.890 38.245 ;
        RECT 50.760 37.915 54.960 38.245 ;
        RECT -4.820 32.475 -0.620 32.805 ;
        RECT 14.150 32.475 15.750 32.805 ;
        RECT 41.290 32.475 42.890 32.805 ;
        RECT 50.760 32.475 54.960 32.805 ;
        RECT -4.820 27.035 -0.620 27.365 ;
        RECT 14.150 27.035 15.750 27.365 ;
        RECT 41.290 27.035 42.890 27.365 ;
        RECT 50.760 27.035 54.960 27.365 ;
        RECT -4.820 21.595 -0.620 21.925 ;
        RECT 14.150 21.595 15.750 21.925 ;
        RECT 41.290 21.595 42.890 21.925 ;
        RECT 50.760 21.595 54.960 21.925 ;
        RECT -4.820 16.155 -0.620 16.485 ;
        RECT 14.150 16.155 15.750 16.485 ;
        RECT 41.290 16.155 42.890 16.485 ;
        RECT 50.760 16.155 54.960 16.485 ;
        RECT -4.820 10.715 -0.620 11.045 ;
        RECT 14.150 10.715 15.750 11.045 ;
        RECT 41.290 10.715 42.890 11.045 ;
        RECT 50.760 10.715 54.960 11.045 ;
        RECT -4.820 5.275 -0.620 5.605 ;
        RECT 14.150 5.275 15.750 5.605 ;
        RECT 41.290 5.275 42.890 5.605 ;
        RECT 50.760 5.275 54.960 5.605 ;
      LAYER via3 ;
        RECT -4.680 37.920 -4.360 38.240 ;
        RECT -4.280 37.920 -3.960 38.240 ;
        RECT -3.880 37.920 -3.560 38.240 ;
        RECT -3.480 37.920 -3.160 38.240 ;
        RECT -3.080 37.920 -2.760 38.240 ;
        RECT -2.680 37.920 -2.360 38.240 ;
        RECT -2.280 37.920 -1.960 38.240 ;
        RECT -1.880 37.920 -1.560 38.240 ;
        RECT -1.480 37.920 -1.160 38.240 ;
        RECT -1.080 37.920 -0.760 38.240 ;
        RECT 14.190 37.920 14.510 38.240 ;
        RECT 14.590 37.920 14.910 38.240 ;
        RECT 14.990 37.920 15.310 38.240 ;
        RECT 15.390 37.920 15.710 38.240 ;
        RECT 41.330 37.920 41.650 38.240 ;
        RECT 41.730 37.920 42.050 38.240 ;
        RECT 42.130 37.920 42.450 38.240 ;
        RECT 42.530 37.920 42.850 38.240 ;
        RECT 50.900 37.920 51.220 38.240 ;
        RECT 51.300 37.920 51.620 38.240 ;
        RECT 51.700 37.920 52.020 38.240 ;
        RECT 52.100 37.920 52.420 38.240 ;
        RECT 52.500 37.920 52.820 38.240 ;
        RECT 52.900 37.920 53.220 38.240 ;
        RECT 53.300 37.920 53.620 38.240 ;
        RECT 53.700 37.920 54.020 38.240 ;
        RECT 54.100 37.920 54.420 38.240 ;
        RECT 54.500 37.920 54.820 38.240 ;
        RECT -4.680 32.480 -4.360 32.800 ;
        RECT -4.280 32.480 -3.960 32.800 ;
        RECT -3.880 32.480 -3.560 32.800 ;
        RECT -3.480 32.480 -3.160 32.800 ;
        RECT -3.080 32.480 -2.760 32.800 ;
        RECT -2.680 32.480 -2.360 32.800 ;
        RECT -2.280 32.480 -1.960 32.800 ;
        RECT -1.880 32.480 -1.560 32.800 ;
        RECT -1.480 32.480 -1.160 32.800 ;
        RECT -1.080 32.480 -0.760 32.800 ;
        RECT 14.190 32.480 14.510 32.800 ;
        RECT 14.590 32.480 14.910 32.800 ;
        RECT 14.990 32.480 15.310 32.800 ;
        RECT 15.390 32.480 15.710 32.800 ;
        RECT 41.330 32.480 41.650 32.800 ;
        RECT 41.730 32.480 42.050 32.800 ;
        RECT 42.130 32.480 42.450 32.800 ;
        RECT 42.530 32.480 42.850 32.800 ;
        RECT 50.900 32.480 51.220 32.800 ;
        RECT 51.300 32.480 51.620 32.800 ;
        RECT 51.700 32.480 52.020 32.800 ;
        RECT 52.100 32.480 52.420 32.800 ;
        RECT 52.500 32.480 52.820 32.800 ;
        RECT 52.900 32.480 53.220 32.800 ;
        RECT 53.300 32.480 53.620 32.800 ;
        RECT 53.700 32.480 54.020 32.800 ;
        RECT 54.100 32.480 54.420 32.800 ;
        RECT 54.500 32.480 54.820 32.800 ;
        RECT -4.680 27.040 -4.360 27.360 ;
        RECT -4.280 27.040 -3.960 27.360 ;
        RECT -3.880 27.040 -3.560 27.360 ;
        RECT -3.480 27.040 -3.160 27.360 ;
        RECT -3.080 27.040 -2.760 27.360 ;
        RECT -2.680 27.040 -2.360 27.360 ;
        RECT -2.280 27.040 -1.960 27.360 ;
        RECT -1.880 27.040 -1.560 27.360 ;
        RECT -1.480 27.040 -1.160 27.360 ;
        RECT -1.080 27.040 -0.760 27.360 ;
        RECT 14.190 27.040 14.510 27.360 ;
        RECT 14.590 27.040 14.910 27.360 ;
        RECT 14.990 27.040 15.310 27.360 ;
        RECT 15.390 27.040 15.710 27.360 ;
        RECT 41.330 27.040 41.650 27.360 ;
        RECT 41.730 27.040 42.050 27.360 ;
        RECT 42.130 27.040 42.450 27.360 ;
        RECT 42.530 27.040 42.850 27.360 ;
        RECT 50.900 27.040 51.220 27.360 ;
        RECT 51.300 27.040 51.620 27.360 ;
        RECT 51.700 27.040 52.020 27.360 ;
        RECT 52.100 27.040 52.420 27.360 ;
        RECT 52.500 27.040 52.820 27.360 ;
        RECT 52.900 27.040 53.220 27.360 ;
        RECT 53.300 27.040 53.620 27.360 ;
        RECT 53.700 27.040 54.020 27.360 ;
        RECT 54.100 27.040 54.420 27.360 ;
        RECT 54.500 27.040 54.820 27.360 ;
        RECT -4.680 21.600 -4.360 21.920 ;
        RECT -4.280 21.600 -3.960 21.920 ;
        RECT -3.880 21.600 -3.560 21.920 ;
        RECT -3.480 21.600 -3.160 21.920 ;
        RECT -3.080 21.600 -2.760 21.920 ;
        RECT -2.680 21.600 -2.360 21.920 ;
        RECT -2.280 21.600 -1.960 21.920 ;
        RECT -1.880 21.600 -1.560 21.920 ;
        RECT -1.480 21.600 -1.160 21.920 ;
        RECT -1.080 21.600 -0.760 21.920 ;
        RECT 14.190 21.600 14.510 21.920 ;
        RECT 14.590 21.600 14.910 21.920 ;
        RECT 14.990 21.600 15.310 21.920 ;
        RECT 15.390 21.600 15.710 21.920 ;
        RECT 41.330 21.600 41.650 21.920 ;
        RECT 41.730 21.600 42.050 21.920 ;
        RECT 42.130 21.600 42.450 21.920 ;
        RECT 42.530 21.600 42.850 21.920 ;
        RECT 50.900 21.600 51.220 21.920 ;
        RECT 51.300 21.600 51.620 21.920 ;
        RECT 51.700 21.600 52.020 21.920 ;
        RECT 52.100 21.600 52.420 21.920 ;
        RECT 52.500 21.600 52.820 21.920 ;
        RECT 52.900 21.600 53.220 21.920 ;
        RECT 53.300 21.600 53.620 21.920 ;
        RECT 53.700 21.600 54.020 21.920 ;
        RECT 54.100 21.600 54.420 21.920 ;
        RECT 54.500 21.600 54.820 21.920 ;
        RECT -4.680 16.160 -4.360 16.480 ;
        RECT -4.280 16.160 -3.960 16.480 ;
        RECT -3.880 16.160 -3.560 16.480 ;
        RECT -3.480 16.160 -3.160 16.480 ;
        RECT -3.080 16.160 -2.760 16.480 ;
        RECT -2.680 16.160 -2.360 16.480 ;
        RECT -2.280 16.160 -1.960 16.480 ;
        RECT -1.880 16.160 -1.560 16.480 ;
        RECT -1.480 16.160 -1.160 16.480 ;
        RECT -1.080 16.160 -0.760 16.480 ;
        RECT 14.190 16.160 14.510 16.480 ;
        RECT 14.590 16.160 14.910 16.480 ;
        RECT 14.990 16.160 15.310 16.480 ;
        RECT 15.390 16.160 15.710 16.480 ;
        RECT 41.330 16.160 41.650 16.480 ;
        RECT 41.730 16.160 42.050 16.480 ;
        RECT 42.130 16.160 42.450 16.480 ;
        RECT 42.530 16.160 42.850 16.480 ;
        RECT 50.900 16.160 51.220 16.480 ;
        RECT 51.300 16.160 51.620 16.480 ;
        RECT 51.700 16.160 52.020 16.480 ;
        RECT 52.100 16.160 52.420 16.480 ;
        RECT 52.500 16.160 52.820 16.480 ;
        RECT 52.900 16.160 53.220 16.480 ;
        RECT 53.300 16.160 53.620 16.480 ;
        RECT 53.700 16.160 54.020 16.480 ;
        RECT 54.100 16.160 54.420 16.480 ;
        RECT 54.500 16.160 54.820 16.480 ;
        RECT -4.680 10.720 -4.360 11.040 ;
        RECT -4.280 10.720 -3.960 11.040 ;
        RECT -3.880 10.720 -3.560 11.040 ;
        RECT -3.480 10.720 -3.160 11.040 ;
        RECT -3.080 10.720 -2.760 11.040 ;
        RECT -2.680 10.720 -2.360 11.040 ;
        RECT -2.280 10.720 -1.960 11.040 ;
        RECT -1.880 10.720 -1.560 11.040 ;
        RECT -1.480 10.720 -1.160 11.040 ;
        RECT -1.080 10.720 -0.760 11.040 ;
        RECT 14.190 10.720 14.510 11.040 ;
        RECT 14.590 10.720 14.910 11.040 ;
        RECT 14.990 10.720 15.310 11.040 ;
        RECT 15.390 10.720 15.710 11.040 ;
        RECT 41.330 10.720 41.650 11.040 ;
        RECT 41.730 10.720 42.050 11.040 ;
        RECT 42.130 10.720 42.450 11.040 ;
        RECT 42.530 10.720 42.850 11.040 ;
        RECT 50.900 10.720 51.220 11.040 ;
        RECT 51.300 10.720 51.620 11.040 ;
        RECT 51.700 10.720 52.020 11.040 ;
        RECT 52.100 10.720 52.420 11.040 ;
        RECT 52.500 10.720 52.820 11.040 ;
        RECT 52.900 10.720 53.220 11.040 ;
        RECT 53.300 10.720 53.620 11.040 ;
        RECT 53.700 10.720 54.020 11.040 ;
        RECT 54.100 10.720 54.420 11.040 ;
        RECT 54.500 10.720 54.820 11.040 ;
        RECT -4.680 5.280 -4.360 5.600 ;
        RECT -4.280 5.280 -3.960 5.600 ;
        RECT -3.880 5.280 -3.560 5.600 ;
        RECT -3.480 5.280 -3.160 5.600 ;
        RECT -3.080 5.280 -2.760 5.600 ;
        RECT -2.680 5.280 -2.360 5.600 ;
        RECT -2.280 5.280 -1.960 5.600 ;
        RECT -1.880 5.280 -1.560 5.600 ;
        RECT -1.480 5.280 -1.160 5.600 ;
        RECT -1.080 5.280 -0.760 5.600 ;
        RECT 14.190 5.280 14.510 5.600 ;
        RECT 14.590 5.280 14.910 5.600 ;
        RECT 14.990 5.280 15.310 5.600 ;
        RECT 15.390 5.280 15.710 5.600 ;
        RECT 41.330 5.280 41.650 5.600 ;
        RECT 41.730 5.280 42.050 5.600 ;
        RECT 42.130 5.280 42.450 5.600 ;
        RECT 42.530 5.280 42.850 5.600 ;
        RECT 50.900 5.280 51.220 5.600 ;
        RECT 51.300 5.280 51.620 5.600 ;
        RECT 51.700 5.280 52.020 5.600 ;
        RECT 52.100 5.280 52.420 5.600 ;
        RECT 52.500 5.280 52.820 5.600 ;
        RECT 52.900 5.280 53.220 5.600 ;
        RECT 53.300 5.280 53.620 5.600 ;
        RECT 53.700 5.280 54.020 5.600 ;
        RECT 54.100 5.280 54.420 5.600 ;
        RECT 54.500 5.280 54.820 5.600 ;
      LAYER met4 ;
        RECT -4.820 -3.480 -0.620 44.280 ;
        RECT 14.150 -9.280 15.750 50.080 ;
        RECT 41.290 -9.280 42.890 50.080 ;
        RECT 50.760 -3.480 54.960 44.280 ;
      LAYER via4 ;
        RECT -4.110 40.790 -1.330 43.570 ;
        RECT -4.110 15.490 -2.930 16.670 ;
        RECT -2.510 15.490 -1.330 16.670 ;
        RECT -4.110 -2.770 -1.330 0.010 ;
        RECT 14.360 42.390 15.540 43.570 ;
        RECT 14.360 40.790 15.540 41.970 ;
        RECT 14.360 15.490 15.540 16.670 ;
        RECT 14.360 -1.170 15.540 0.010 ;
        RECT 14.360 -2.770 15.540 -1.590 ;
        RECT 41.500 42.390 42.680 43.570 ;
        RECT 41.500 40.790 42.680 41.970 ;
        RECT 41.500 15.490 42.680 16.670 ;
        RECT 41.500 -1.170 42.680 0.010 ;
        RECT 41.500 -2.770 42.680 -1.590 ;
        RECT 51.470 40.790 54.250 43.570 ;
        RECT 51.470 15.490 52.650 16.670 ;
        RECT 53.070 15.490 54.250 16.670 ;
        RECT 51.470 -2.770 54.250 0.010 ;
      LAYER met5 ;
        RECT -4.820 40.080 54.960 44.280 ;
        RECT -10.620 15.280 60.760 16.880 ;
        RECT -4.820 -3.480 54.960 0.720 ;
    END
  END VPWR
  PIN VGND
    ANTENNAGATEAREA 23.750999 ;
    ANTENNADIFFAREA 24.261250 ;
    PORT
      LAYER pwell ;
        RECT 15.195 35.550 15.625 36.335 ;
        RECT 28.995 35.550 29.425 36.335 ;
        RECT 42.795 35.550 43.225 36.335 ;
        RECT 28.995 34.385 29.425 35.170 ;
        RECT 15.195 30.110 15.625 30.895 ;
        RECT 42.795 30.110 43.225 30.895 ;
        RECT 28.995 28.945 29.425 29.730 ;
        RECT 15.195 24.670 15.625 25.455 ;
        RECT 42.795 24.670 43.225 25.455 ;
        RECT 28.995 23.505 29.425 24.290 ;
        RECT 15.195 19.230 15.625 20.015 ;
        RECT 42.795 19.230 43.225 20.015 ;
        RECT 28.995 18.065 29.425 18.850 ;
        RECT 15.195 13.790 15.625 14.575 ;
        RECT 42.795 13.790 43.225 14.575 ;
        RECT 28.995 12.625 29.425 13.410 ;
        RECT 15.195 8.350 15.625 9.135 ;
        RECT 42.795 8.350 43.225 9.135 ;
        RECT 28.995 7.185 29.425 7.970 ;
        RECT 15.195 2.910 15.625 3.695 ;
        RECT 28.995 2.910 29.425 3.695 ;
        RECT 42.795 2.910 43.225 3.695 ;
      LAYER li1 ;
        RECT 1.465 36.215 2.215 36.735 ;
        RECT 47.925 36.215 48.675 36.735 ;
        RECT 1.465 35.445 3.135 36.215 ;
        RECT 15.265 35.445 15.555 36.170 ;
        RECT 29.065 35.445 29.355 36.170 ;
        RECT 42.865 35.445 43.155 36.170 ;
        RECT 47.005 35.445 48.675 36.215 ;
        RECT 1.380 35.275 48.760 35.445 ;
        RECT 1.465 34.505 3.135 35.275 ;
        RECT 29.065 34.550 29.355 35.275 ;
        RECT 1.465 33.985 2.215 34.505 ;
        RECT 40.340 34.455 40.570 35.275 ;
        RECT 47.005 34.505 48.675 35.275 ;
        RECT 47.925 33.985 48.675 34.505 ;
        RECT 1.465 30.775 2.215 31.295 ;
        RECT 47.925 30.775 48.675 31.295 ;
        RECT 1.465 30.005 3.135 30.775 ;
        RECT 15.265 30.005 15.555 30.730 ;
        RECT 19.820 30.005 20.150 30.365 ;
        RECT 28.615 30.005 28.945 30.405 ;
        RECT 29.455 30.005 29.785 30.405 ;
        RECT 30.475 30.005 30.735 30.495 ;
        RECT 37.355 30.005 37.655 30.735 ;
        RECT 38.660 30.005 38.990 30.395 ;
        RECT 42.865 30.005 43.155 30.730 ;
        RECT 47.005 30.005 48.675 30.775 ;
        RECT 1.380 29.835 48.760 30.005 ;
        RECT 1.465 29.065 3.135 29.835 ;
        RECT 10.235 29.475 10.565 29.835 ;
        RECT 14.300 29.475 14.630 29.835 ;
        RECT 1.465 28.545 2.215 29.065 ;
        RECT 17.105 29.035 17.415 29.835 ;
        RECT 20.350 29.435 20.680 29.835 ;
        RECT 21.190 29.325 21.505 29.835 ;
        RECT 22.195 29.325 22.435 29.835 ;
        RECT 24.930 29.475 25.260 29.835 ;
        RECT 29.065 29.110 29.355 29.835 ;
        RECT 33.155 29.095 33.490 29.835 ;
        RECT 35.575 29.435 35.905 29.835 ;
        RECT 36.415 29.435 36.745 29.835 ;
        RECT 39.210 29.445 39.540 29.835 ;
        RECT 40.545 29.105 40.845 29.835 ;
        RECT 43.765 29.035 44.075 29.835 ;
        RECT 47.005 29.065 48.675 29.835 ;
        RECT 47.925 28.545 48.675 29.065 ;
        RECT 1.465 25.335 2.215 25.855 ;
        RECT 1.465 24.565 3.135 25.335 ;
        RECT 6.760 24.565 6.990 25.385 ;
        RECT 10.215 24.565 10.545 25.305 ;
        RECT 11.055 24.565 11.725 24.970 ;
        RECT 12.915 24.565 13.245 25.305 ;
        RECT 15.265 24.565 15.555 25.290 ;
        RECT 17.625 24.565 17.835 25.385 ;
        RECT 18.505 24.565 18.735 25.385 ;
        RECT 20.785 24.565 21.045 25.045 ;
        RECT 22.570 24.565 22.910 25.295 ;
        RECT 25.355 24.565 25.685 24.945 ;
        RECT 26.195 24.565 26.525 24.945 ;
        RECT 30.915 24.565 31.245 24.945 ;
        RECT 31.755 24.565 32.085 24.945 ;
        RECT 35.525 24.565 35.865 24.925 ;
        RECT 36.395 24.565 36.725 24.925 ;
        RECT 37.330 24.565 38.105 24.925 ;
        RECT 38.675 24.565 39.005 24.925 ;
        RECT 40.365 24.565 40.645 25.365 ;
        RECT 47.925 25.335 48.675 25.855 ;
        RECT 42.865 24.565 43.155 25.290 ;
        RECT 47.005 24.565 48.675 25.335 ;
        RECT 1.380 24.395 48.760 24.565 ;
        RECT 1.465 23.625 3.135 24.395 ;
        RECT 1.465 23.105 2.215 23.625 ;
        RECT 7.915 23.585 8.185 24.395 ;
        RECT 8.855 23.585 9.095 24.395 ;
        RECT 11.130 23.655 11.465 24.395 ;
        RECT 17.565 23.575 17.825 24.395 ;
        RECT 19.855 23.935 20.185 24.395 ;
        RECT 24.035 24.035 24.365 24.395 ;
        RECT 29.065 23.670 29.355 24.395 ;
        RECT 38.995 23.935 39.245 24.395 ;
        RECT 42.415 23.585 42.685 24.395 ;
        RECT 43.355 23.585 43.595 24.395 ;
        RECT 47.005 23.625 48.675 24.395 ;
        RECT 47.925 23.105 48.675 23.625 ;
        RECT 1.465 19.895 2.215 20.415 ;
        RECT 1.465 19.125 3.135 19.895 ;
        RECT 10.210 19.125 10.540 19.485 ;
        RECT 15.265 19.125 15.555 19.850 ;
        RECT 18.955 19.125 19.225 19.935 ;
        RECT 19.895 19.125 20.135 19.935 ;
        RECT 22.405 19.125 22.575 19.595 ;
        RECT 23.245 19.125 23.415 19.595 ;
        RECT 24.085 19.125 24.785 19.595 ;
        RECT 25.455 19.125 25.625 19.595 ;
        RECT 28.150 19.125 28.425 19.945 ;
        RECT 29.095 19.125 29.265 19.595 ;
        RECT 29.935 19.125 30.665 19.595 ;
        RECT 31.335 19.125 31.540 19.935 ;
        RECT 32.275 19.125 32.565 19.865 ;
        RECT 39.665 19.125 39.905 19.935 ;
        RECT 40.575 19.125 40.845 19.935 ;
        RECT 47.925 19.895 48.675 20.415 ;
        RECT 42.865 19.125 43.155 19.850 ;
        RECT 47.005 19.125 48.675 19.895 ;
        RECT 1.380 18.955 48.760 19.125 ;
        RECT 1.465 18.185 3.135 18.955 ;
        RECT 1.465 17.665 2.215 18.185 ;
        RECT 8.875 18.155 9.125 18.955 ;
        RECT 9.815 18.495 10.040 18.955 ;
        RECT 14.395 18.495 14.565 18.955 ;
        RECT 15.795 18.495 15.965 18.955 ;
        RECT 18.915 18.415 19.165 18.955 ;
        RECT 24.975 18.135 25.145 18.955 ;
        RECT 25.815 18.565 26.165 18.955 ;
        RECT 29.065 18.230 29.355 18.955 ;
        RECT 42.865 18.155 43.175 18.955 ;
        RECT 47.005 18.185 48.675 18.955 ;
        RECT 47.925 17.665 48.675 18.185 ;
        RECT 1.465 14.455 2.215 14.975 ;
        RECT 1.465 13.685 3.135 14.455 ;
        RECT 11.635 13.685 11.805 14.145 ;
        RECT 12.995 13.685 13.215 14.145 ;
        RECT 15.265 13.685 15.555 14.410 ;
        RECT 18.440 13.685 18.770 14.045 ;
        RECT 23.985 13.685 24.295 14.485 ;
        RECT 27.205 13.685 27.515 14.485 ;
        RECT 47.925 14.455 48.675 14.975 ;
        RECT 42.865 13.685 43.155 14.410 ;
        RECT 47.005 13.685 48.675 14.455 ;
        RECT 1.380 13.515 48.760 13.685 ;
        RECT 1.465 12.745 3.135 13.515 ;
        RECT 1.465 12.225 2.215 12.745 ;
        RECT 5.890 12.695 6.120 13.515 ;
        RECT 8.825 12.775 9.100 13.515 ;
        RECT 10.735 13.045 10.905 13.515 ;
        RECT 20.795 13.115 21.175 13.515 ;
        RECT 21.685 13.115 22.015 13.515 ;
        RECT 25.340 13.155 25.670 13.515 ;
        RECT 29.065 12.790 29.355 13.515 ;
        RECT 47.005 12.745 48.675 13.515 ;
        RECT 47.925 12.225 48.675 12.745 ;
        RECT 1.465 9.015 2.215 9.535 ;
        RECT 47.925 9.015 48.675 9.535 ;
        RECT 1.465 8.245 3.135 9.015 ;
        RECT 15.265 8.245 15.555 8.970 ;
        RECT 42.865 8.245 43.155 8.970 ;
        RECT 47.005 8.245 48.675 9.015 ;
        RECT 1.380 8.075 48.760 8.245 ;
        RECT 1.465 7.305 3.135 8.075 ;
        RECT 29.065 7.350 29.355 8.075 ;
        RECT 1.465 6.785 2.215 7.305 ;
        RECT 44.020 7.255 44.250 8.075 ;
        RECT 47.005 7.305 48.675 8.075 ;
        RECT 47.925 6.785 48.675 7.305 ;
        RECT 1.465 3.575 2.215 4.095 ;
        RECT 47.925 3.575 48.675 4.095 ;
        RECT 1.465 2.805 3.135 3.575 ;
        RECT 15.265 2.805 15.555 3.530 ;
        RECT 29.065 2.805 29.355 3.530 ;
        RECT 42.865 2.805 43.155 3.530 ;
        RECT 47.005 2.805 48.675 3.575 ;
        RECT 1.380 2.635 48.760 2.805 ;
      LAYER mcon ;
        RECT 1.525 35.275 1.695 35.445 ;
        RECT 1.985 35.275 2.155 35.445 ;
        RECT 2.445 35.275 2.615 35.445 ;
        RECT 2.905 35.275 3.075 35.445 ;
        RECT 3.365 35.275 3.535 35.445 ;
        RECT 3.825 35.275 3.995 35.445 ;
        RECT 4.285 35.275 4.455 35.445 ;
        RECT 4.745 35.275 4.915 35.445 ;
        RECT 5.205 35.275 5.375 35.445 ;
        RECT 5.665 35.275 5.835 35.445 ;
        RECT 6.125 35.275 6.295 35.445 ;
        RECT 6.585 35.275 6.755 35.445 ;
        RECT 7.045 35.275 7.215 35.445 ;
        RECT 7.505 35.275 7.675 35.445 ;
        RECT 7.965 35.275 8.135 35.445 ;
        RECT 8.425 35.275 8.595 35.445 ;
        RECT 8.885 35.275 9.055 35.445 ;
        RECT 9.345 35.275 9.515 35.445 ;
        RECT 9.805 35.275 9.975 35.445 ;
        RECT 10.265 35.275 10.435 35.445 ;
        RECT 10.725 35.275 10.895 35.445 ;
        RECT 11.185 35.275 11.355 35.445 ;
        RECT 11.645 35.275 11.815 35.445 ;
        RECT 12.105 35.275 12.275 35.445 ;
        RECT 12.565 35.275 12.735 35.445 ;
        RECT 13.025 35.275 13.195 35.445 ;
        RECT 13.485 35.275 13.655 35.445 ;
        RECT 13.945 35.275 14.115 35.445 ;
        RECT 14.405 35.275 14.575 35.445 ;
        RECT 14.865 35.275 15.035 35.445 ;
        RECT 15.325 35.275 15.495 35.445 ;
        RECT 15.785 35.275 15.955 35.445 ;
        RECT 16.245 35.275 16.415 35.445 ;
        RECT 16.705 35.275 16.875 35.445 ;
        RECT 17.165 35.275 17.335 35.445 ;
        RECT 17.625 35.275 17.795 35.445 ;
        RECT 18.085 35.275 18.255 35.445 ;
        RECT 18.545 35.275 18.715 35.445 ;
        RECT 19.005 35.275 19.175 35.445 ;
        RECT 19.465 35.275 19.635 35.445 ;
        RECT 19.925 35.275 20.095 35.445 ;
        RECT 20.385 35.275 20.555 35.445 ;
        RECT 20.845 35.275 21.015 35.445 ;
        RECT 21.305 35.275 21.475 35.445 ;
        RECT 21.765 35.275 21.935 35.445 ;
        RECT 22.225 35.275 22.395 35.445 ;
        RECT 22.685 35.275 22.855 35.445 ;
        RECT 23.145 35.275 23.315 35.445 ;
        RECT 23.605 35.275 23.775 35.445 ;
        RECT 24.065 35.275 24.235 35.445 ;
        RECT 24.525 35.275 24.695 35.445 ;
        RECT 24.985 35.275 25.155 35.445 ;
        RECT 25.445 35.275 25.615 35.445 ;
        RECT 25.905 35.275 26.075 35.445 ;
        RECT 26.365 35.275 26.535 35.445 ;
        RECT 26.825 35.275 26.995 35.445 ;
        RECT 27.285 35.275 27.455 35.445 ;
        RECT 27.745 35.275 27.915 35.445 ;
        RECT 28.205 35.275 28.375 35.445 ;
        RECT 28.665 35.275 28.835 35.445 ;
        RECT 29.125 35.275 29.295 35.445 ;
        RECT 29.585 35.275 29.755 35.445 ;
        RECT 30.045 35.275 30.215 35.445 ;
        RECT 30.505 35.275 30.675 35.445 ;
        RECT 30.965 35.275 31.135 35.445 ;
        RECT 31.425 35.275 31.595 35.445 ;
        RECT 31.885 35.275 32.055 35.445 ;
        RECT 32.345 35.275 32.515 35.445 ;
        RECT 32.805 35.275 32.975 35.445 ;
        RECT 33.265 35.275 33.435 35.445 ;
        RECT 33.725 35.275 33.895 35.445 ;
        RECT 34.185 35.275 34.355 35.445 ;
        RECT 34.645 35.275 34.815 35.445 ;
        RECT 35.105 35.275 35.275 35.445 ;
        RECT 35.565 35.275 35.735 35.445 ;
        RECT 36.025 35.275 36.195 35.445 ;
        RECT 36.485 35.275 36.655 35.445 ;
        RECT 36.945 35.275 37.115 35.445 ;
        RECT 37.405 35.275 37.575 35.445 ;
        RECT 37.865 35.275 38.035 35.445 ;
        RECT 38.325 35.275 38.495 35.445 ;
        RECT 38.785 35.275 38.955 35.445 ;
        RECT 39.245 35.275 39.415 35.445 ;
        RECT 39.705 35.275 39.875 35.445 ;
        RECT 40.165 35.275 40.335 35.445 ;
        RECT 40.625 35.275 40.795 35.445 ;
        RECT 41.085 35.275 41.255 35.445 ;
        RECT 41.545 35.275 41.715 35.445 ;
        RECT 42.005 35.275 42.175 35.445 ;
        RECT 42.465 35.275 42.635 35.445 ;
        RECT 42.925 35.275 43.095 35.445 ;
        RECT 43.385 35.275 43.555 35.445 ;
        RECT 43.845 35.275 44.015 35.445 ;
        RECT 44.305 35.275 44.475 35.445 ;
        RECT 44.765 35.275 44.935 35.445 ;
        RECT 45.225 35.275 45.395 35.445 ;
        RECT 45.685 35.275 45.855 35.445 ;
        RECT 46.145 35.275 46.315 35.445 ;
        RECT 46.605 35.275 46.775 35.445 ;
        RECT 47.065 35.275 47.235 35.445 ;
        RECT 47.525 35.275 47.695 35.445 ;
        RECT 47.985 35.275 48.155 35.445 ;
        RECT 48.445 35.275 48.615 35.445 ;
        RECT 1.525 29.835 1.695 30.005 ;
        RECT 1.985 29.835 2.155 30.005 ;
        RECT 2.445 29.835 2.615 30.005 ;
        RECT 2.905 29.835 3.075 30.005 ;
        RECT 3.365 29.835 3.535 30.005 ;
        RECT 3.825 29.835 3.995 30.005 ;
        RECT 4.285 29.835 4.455 30.005 ;
        RECT 4.745 29.835 4.915 30.005 ;
        RECT 5.205 29.835 5.375 30.005 ;
        RECT 5.665 29.835 5.835 30.005 ;
        RECT 6.125 29.835 6.295 30.005 ;
        RECT 6.585 29.835 6.755 30.005 ;
        RECT 7.045 29.835 7.215 30.005 ;
        RECT 7.505 29.835 7.675 30.005 ;
        RECT 7.965 29.835 8.135 30.005 ;
        RECT 8.425 29.835 8.595 30.005 ;
        RECT 8.885 29.835 9.055 30.005 ;
        RECT 9.345 29.835 9.515 30.005 ;
        RECT 9.805 29.835 9.975 30.005 ;
        RECT 10.265 29.835 10.435 30.005 ;
        RECT 10.725 29.835 10.895 30.005 ;
        RECT 11.185 29.835 11.355 30.005 ;
        RECT 11.645 29.835 11.815 30.005 ;
        RECT 12.105 29.835 12.275 30.005 ;
        RECT 12.565 29.835 12.735 30.005 ;
        RECT 13.025 29.835 13.195 30.005 ;
        RECT 13.485 29.835 13.655 30.005 ;
        RECT 13.945 29.835 14.115 30.005 ;
        RECT 14.405 29.835 14.575 30.005 ;
        RECT 14.865 29.835 15.035 30.005 ;
        RECT 15.325 29.835 15.495 30.005 ;
        RECT 15.785 29.835 15.955 30.005 ;
        RECT 16.245 29.835 16.415 30.005 ;
        RECT 16.705 29.835 16.875 30.005 ;
        RECT 17.165 29.835 17.335 30.005 ;
        RECT 17.625 29.835 17.795 30.005 ;
        RECT 18.085 29.835 18.255 30.005 ;
        RECT 18.545 29.835 18.715 30.005 ;
        RECT 19.005 29.835 19.175 30.005 ;
        RECT 19.465 29.835 19.635 30.005 ;
        RECT 19.925 29.835 20.095 30.005 ;
        RECT 20.385 29.835 20.555 30.005 ;
        RECT 20.845 29.835 21.015 30.005 ;
        RECT 21.305 29.835 21.475 30.005 ;
        RECT 21.765 29.835 21.935 30.005 ;
        RECT 22.225 29.835 22.395 30.005 ;
        RECT 22.685 29.835 22.855 30.005 ;
        RECT 23.145 29.835 23.315 30.005 ;
        RECT 23.605 29.835 23.775 30.005 ;
        RECT 24.065 29.835 24.235 30.005 ;
        RECT 24.525 29.835 24.695 30.005 ;
        RECT 24.985 29.835 25.155 30.005 ;
        RECT 25.445 29.835 25.615 30.005 ;
        RECT 25.905 29.835 26.075 30.005 ;
        RECT 26.365 29.835 26.535 30.005 ;
        RECT 26.825 29.835 26.995 30.005 ;
        RECT 27.285 29.835 27.455 30.005 ;
        RECT 27.745 29.835 27.915 30.005 ;
        RECT 28.205 29.835 28.375 30.005 ;
        RECT 28.665 29.835 28.835 30.005 ;
        RECT 29.125 29.835 29.295 30.005 ;
        RECT 29.585 29.835 29.755 30.005 ;
        RECT 30.045 29.835 30.215 30.005 ;
        RECT 30.505 29.835 30.675 30.005 ;
        RECT 30.965 29.835 31.135 30.005 ;
        RECT 31.425 29.835 31.595 30.005 ;
        RECT 31.885 29.835 32.055 30.005 ;
        RECT 32.345 29.835 32.515 30.005 ;
        RECT 32.805 29.835 32.975 30.005 ;
        RECT 33.265 29.835 33.435 30.005 ;
        RECT 33.725 29.835 33.895 30.005 ;
        RECT 34.185 29.835 34.355 30.005 ;
        RECT 34.645 29.835 34.815 30.005 ;
        RECT 35.105 29.835 35.275 30.005 ;
        RECT 35.565 29.835 35.735 30.005 ;
        RECT 36.025 29.835 36.195 30.005 ;
        RECT 36.485 29.835 36.655 30.005 ;
        RECT 36.945 29.835 37.115 30.005 ;
        RECT 37.405 29.835 37.575 30.005 ;
        RECT 37.865 29.835 38.035 30.005 ;
        RECT 38.325 29.835 38.495 30.005 ;
        RECT 38.785 29.835 38.955 30.005 ;
        RECT 39.245 29.835 39.415 30.005 ;
        RECT 39.705 29.835 39.875 30.005 ;
        RECT 40.165 29.835 40.335 30.005 ;
        RECT 40.625 29.835 40.795 30.005 ;
        RECT 41.085 29.835 41.255 30.005 ;
        RECT 41.545 29.835 41.715 30.005 ;
        RECT 42.005 29.835 42.175 30.005 ;
        RECT 42.465 29.835 42.635 30.005 ;
        RECT 42.925 29.835 43.095 30.005 ;
        RECT 43.385 29.835 43.555 30.005 ;
        RECT 43.845 29.835 44.015 30.005 ;
        RECT 44.305 29.835 44.475 30.005 ;
        RECT 44.765 29.835 44.935 30.005 ;
        RECT 45.225 29.835 45.395 30.005 ;
        RECT 45.685 29.835 45.855 30.005 ;
        RECT 46.145 29.835 46.315 30.005 ;
        RECT 46.605 29.835 46.775 30.005 ;
        RECT 47.065 29.835 47.235 30.005 ;
        RECT 47.525 29.835 47.695 30.005 ;
        RECT 47.985 29.835 48.155 30.005 ;
        RECT 48.445 29.835 48.615 30.005 ;
        RECT 1.525 24.395 1.695 24.565 ;
        RECT 1.985 24.395 2.155 24.565 ;
        RECT 2.445 24.395 2.615 24.565 ;
        RECT 2.905 24.395 3.075 24.565 ;
        RECT 3.365 24.395 3.535 24.565 ;
        RECT 3.825 24.395 3.995 24.565 ;
        RECT 4.285 24.395 4.455 24.565 ;
        RECT 4.745 24.395 4.915 24.565 ;
        RECT 5.205 24.395 5.375 24.565 ;
        RECT 5.665 24.395 5.835 24.565 ;
        RECT 6.125 24.395 6.295 24.565 ;
        RECT 6.585 24.395 6.755 24.565 ;
        RECT 7.045 24.395 7.215 24.565 ;
        RECT 7.505 24.395 7.675 24.565 ;
        RECT 7.965 24.395 8.135 24.565 ;
        RECT 8.425 24.395 8.595 24.565 ;
        RECT 8.885 24.395 9.055 24.565 ;
        RECT 9.345 24.395 9.515 24.565 ;
        RECT 9.805 24.395 9.975 24.565 ;
        RECT 10.265 24.395 10.435 24.565 ;
        RECT 10.725 24.395 10.895 24.565 ;
        RECT 11.185 24.395 11.355 24.565 ;
        RECT 11.645 24.395 11.815 24.565 ;
        RECT 12.105 24.395 12.275 24.565 ;
        RECT 12.565 24.395 12.735 24.565 ;
        RECT 13.025 24.395 13.195 24.565 ;
        RECT 13.485 24.395 13.655 24.565 ;
        RECT 13.945 24.395 14.115 24.565 ;
        RECT 14.405 24.395 14.575 24.565 ;
        RECT 14.865 24.395 15.035 24.565 ;
        RECT 15.325 24.395 15.495 24.565 ;
        RECT 15.785 24.395 15.955 24.565 ;
        RECT 16.245 24.395 16.415 24.565 ;
        RECT 16.705 24.395 16.875 24.565 ;
        RECT 17.165 24.395 17.335 24.565 ;
        RECT 17.625 24.395 17.795 24.565 ;
        RECT 18.085 24.395 18.255 24.565 ;
        RECT 18.545 24.395 18.715 24.565 ;
        RECT 19.005 24.395 19.175 24.565 ;
        RECT 19.465 24.395 19.635 24.565 ;
        RECT 19.925 24.395 20.095 24.565 ;
        RECT 20.385 24.395 20.555 24.565 ;
        RECT 20.845 24.395 21.015 24.565 ;
        RECT 21.305 24.395 21.475 24.565 ;
        RECT 21.765 24.395 21.935 24.565 ;
        RECT 22.225 24.395 22.395 24.565 ;
        RECT 22.685 24.395 22.855 24.565 ;
        RECT 23.145 24.395 23.315 24.565 ;
        RECT 23.605 24.395 23.775 24.565 ;
        RECT 24.065 24.395 24.235 24.565 ;
        RECT 24.525 24.395 24.695 24.565 ;
        RECT 24.985 24.395 25.155 24.565 ;
        RECT 25.445 24.395 25.615 24.565 ;
        RECT 25.905 24.395 26.075 24.565 ;
        RECT 26.365 24.395 26.535 24.565 ;
        RECT 26.825 24.395 26.995 24.565 ;
        RECT 27.285 24.395 27.455 24.565 ;
        RECT 27.745 24.395 27.915 24.565 ;
        RECT 28.205 24.395 28.375 24.565 ;
        RECT 28.665 24.395 28.835 24.565 ;
        RECT 29.125 24.395 29.295 24.565 ;
        RECT 29.585 24.395 29.755 24.565 ;
        RECT 30.045 24.395 30.215 24.565 ;
        RECT 30.505 24.395 30.675 24.565 ;
        RECT 30.965 24.395 31.135 24.565 ;
        RECT 31.425 24.395 31.595 24.565 ;
        RECT 31.885 24.395 32.055 24.565 ;
        RECT 32.345 24.395 32.515 24.565 ;
        RECT 32.805 24.395 32.975 24.565 ;
        RECT 33.265 24.395 33.435 24.565 ;
        RECT 33.725 24.395 33.895 24.565 ;
        RECT 34.185 24.395 34.355 24.565 ;
        RECT 34.645 24.395 34.815 24.565 ;
        RECT 35.105 24.395 35.275 24.565 ;
        RECT 35.565 24.395 35.735 24.565 ;
        RECT 36.025 24.395 36.195 24.565 ;
        RECT 36.485 24.395 36.655 24.565 ;
        RECT 36.945 24.395 37.115 24.565 ;
        RECT 37.405 24.395 37.575 24.565 ;
        RECT 37.865 24.395 38.035 24.565 ;
        RECT 38.325 24.395 38.495 24.565 ;
        RECT 38.785 24.395 38.955 24.565 ;
        RECT 39.245 24.395 39.415 24.565 ;
        RECT 39.705 24.395 39.875 24.565 ;
        RECT 40.165 24.395 40.335 24.565 ;
        RECT 40.625 24.395 40.795 24.565 ;
        RECT 41.085 24.395 41.255 24.565 ;
        RECT 41.545 24.395 41.715 24.565 ;
        RECT 42.005 24.395 42.175 24.565 ;
        RECT 42.465 24.395 42.635 24.565 ;
        RECT 42.925 24.395 43.095 24.565 ;
        RECT 43.385 24.395 43.555 24.565 ;
        RECT 43.845 24.395 44.015 24.565 ;
        RECT 44.305 24.395 44.475 24.565 ;
        RECT 44.765 24.395 44.935 24.565 ;
        RECT 45.225 24.395 45.395 24.565 ;
        RECT 45.685 24.395 45.855 24.565 ;
        RECT 46.145 24.395 46.315 24.565 ;
        RECT 46.605 24.395 46.775 24.565 ;
        RECT 47.065 24.395 47.235 24.565 ;
        RECT 47.525 24.395 47.695 24.565 ;
        RECT 47.985 24.395 48.155 24.565 ;
        RECT 48.445 24.395 48.615 24.565 ;
        RECT 1.525 18.955 1.695 19.125 ;
        RECT 1.985 18.955 2.155 19.125 ;
        RECT 2.445 18.955 2.615 19.125 ;
        RECT 2.905 18.955 3.075 19.125 ;
        RECT 3.365 18.955 3.535 19.125 ;
        RECT 3.825 18.955 3.995 19.125 ;
        RECT 4.285 18.955 4.455 19.125 ;
        RECT 4.745 18.955 4.915 19.125 ;
        RECT 5.205 18.955 5.375 19.125 ;
        RECT 5.665 18.955 5.835 19.125 ;
        RECT 6.125 18.955 6.295 19.125 ;
        RECT 6.585 18.955 6.755 19.125 ;
        RECT 7.045 18.955 7.215 19.125 ;
        RECT 7.505 18.955 7.675 19.125 ;
        RECT 7.965 18.955 8.135 19.125 ;
        RECT 8.425 18.955 8.595 19.125 ;
        RECT 8.885 18.955 9.055 19.125 ;
        RECT 9.345 18.955 9.515 19.125 ;
        RECT 9.805 18.955 9.975 19.125 ;
        RECT 10.265 18.955 10.435 19.125 ;
        RECT 10.725 18.955 10.895 19.125 ;
        RECT 11.185 18.955 11.355 19.125 ;
        RECT 11.645 18.955 11.815 19.125 ;
        RECT 12.105 18.955 12.275 19.125 ;
        RECT 12.565 18.955 12.735 19.125 ;
        RECT 13.025 18.955 13.195 19.125 ;
        RECT 13.485 18.955 13.655 19.125 ;
        RECT 13.945 18.955 14.115 19.125 ;
        RECT 14.405 18.955 14.575 19.125 ;
        RECT 14.865 18.955 15.035 19.125 ;
        RECT 15.325 18.955 15.495 19.125 ;
        RECT 15.785 18.955 15.955 19.125 ;
        RECT 16.245 18.955 16.415 19.125 ;
        RECT 16.705 18.955 16.875 19.125 ;
        RECT 17.165 18.955 17.335 19.125 ;
        RECT 17.625 18.955 17.795 19.125 ;
        RECT 18.085 18.955 18.255 19.125 ;
        RECT 18.545 18.955 18.715 19.125 ;
        RECT 19.005 18.955 19.175 19.125 ;
        RECT 19.465 18.955 19.635 19.125 ;
        RECT 19.925 18.955 20.095 19.125 ;
        RECT 20.385 18.955 20.555 19.125 ;
        RECT 20.845 18.955 21.015 19.125 ;
        RECT 21.305 18.955 21.475 19.125 ;
        RECT 21.765 18.955 21.935 19.125 ;
        RECT 22.225 18.955 22.395 19.125 ;
        RECT 22.685 18.955 22.855 19.125 ;
        RECT 23.145 18.955 23.315 19.125 ;
        RECT 23.605 18.955 23.775 19.125 ;
        RECT 24.065 18.955 24.235 19.125 ;
        RECT 24.525 18.955 24.695 19.125 ;
        RECT 24.985 18.955 25.155 19.125 ;
        RECT 25.445 18.955 25.615 19.125 ;
        RECT 25.905 18.955 26.075 19.125 ;
        RECT 26.365 18.955 26.535 19.125 ;
        RECT 26.825 18.955 26.995 19.125 ;
        RECT 27.285 18.955 27.455 19.125 ;
        RECT 27.745 18.955 27.915 19.125 ;
        RECT 28.205 18.955 28.375 19.125 ;
        RECT 28.665 18.955 28.835 19.125 ;
        RECT 29.125 18.955 29.295 19.125 ;
        RECT 29.585 18.955 29.755 19.125 ;
        RECT 30.045 18.955 30.215 19.125 ;
        RECT 30.505 18.955 30.675 19.125 ;
        RECT 30.965 18.955 31.135 19.125 ;
        RECT 31.425 18.955 31.595 19.125 ;
        RECT 31.885 18.955 32.055 19.125 ;
        RECT 32.345 18.955 32.515 19.125 ;
        RECT 32.805 18.955 32.975 19.125 ;
        RECT 33.265 18.955 33.435 19.125 ;
        RECT 33.725 18.955 33.895 19.125 ;
        RECT 34.185 18.955 34.355 19.125 ;
        RECT 34.645 18.955 34.815 19.125 ;
        RECT 35.105 18.955 35.275 19.125 ;
        RECT 35.565 18.955 35.735 19.125 ;
        RECT 36.025 18.955 36.195 19.125 ;
        RECT 36.485 18.955 36.655 19.125 ;
        RECT 36.945 18.955 37.115 19.125 ;
        RECT 37.405 18.955 37.575 19.125 ;
        RECT 37.865 18.955 38.035 19.125 ;
        RECT 38.325 18.955 38.495 19.125 ;
        RECT 38.785 18.955 38.955 19.125 ;
        RECT 39.245 18.955 39.415 19.125 ;
        RECT 39.705 18.955 39.875 19.125 ;
        RECT 40.165 18.955 40.335 19.125 ;
        RECT 40.625 18.955 40.795 19.125 ;
        RECT 41.085 18.955 41.255 19.125 ;
        RECT 41.545 18.955 41.715 19.125 ;
        RECT 42.005 18.955 42.175 19.125 ;
        RECT 42.465 18.955 42.635 19.125 ;
        RECT 42.925 18.955 43.095 19.125 ;
        RECT 43.385 18.955 43.555 19.125 ;
        RECT 43.845 18.955 44.015 19.125 ;
        RECT 44.305 18.955 44.475 19.125 ;
        RECT 44.765 18.955 44.935 19.125 ;
        RECT 45.225 18.955 45.395 19.125 ;
        RECT 45.685 18.955 45.855 19.125 ;
        RECT 46.145 18.955 46.315 19.125 ;
        RECT 46.605 18.955 46.775 19.125 ;
        RECT 47.065 18.955 47.235 19.125 ;
        RECT 47.525 18.955 47.695 19.125 ;
        RECT 47.985 18.955 48.155 19.125 ;
        RECT 48.445 18.955 48.615 19.125 ;
        RECT 1.525 13.515 1.695 13.685 ;
        RECT 1.985 13.515 2.155 13.685 ;
        RECT 2.445 13.515 2.615 13.685 ;
        RECT 2.905 13.515 3.075 13.685 ;
        RECT 3.365 13.515 3.535 13.685 ;
        RECT 3.825 13.515 3.995 13.685 ;
        RECT 4.285 13.515 4.455 13.685 ;
        RECT 4.745 13.515 4.915 13.685 ;
        RECT 5.205 13.515 5.375 13.685 ;
        RECT 5.665 13.515 5.835 13.685 ;
        RECT 6.125 13.515 6.295 13.685 ;
        RECT 6.585 13.515 6.755 13.685 ;
        RECT 7.045 13.515 7.215 13.685 ;
        RECT 7.505 13.515 7.675 13.685 ;
        RECT 7.965 13.515 8.135 13.685 ;
        RECT 8.425 13.515 8.595 13.685 ;
        RECT 8.885 13.515 9.055 13.685 ;
        RECT 9.345 13.515 9.515 13.685 ;
        RECT 9.805 13.515 9.975 13.685 ;
        RECT 10.265 13.515 10.435 13.685 ;
        RECT 10.725 13.515 10.895 13.685 ;
        RECT 11.185 13.515 11.355 13.685 ;
        RECT 11.645 13.515 11.815 13.685 ;
        RECT 12.105 13.515 12.275 13.685 ;
        RECT 12.565 13.515 12.735 13.685 ;
        RECT 13.025 13.515 13.195 13.685 ;
        RECT 13.485 13.515 13.655 13.685 ;
        RECT 13.945 13.515 14.115 13.685 ;
        RECT 14.405 13.515 14.575 13.685 ;
        RECT 14.865 13.515 15.035 13.685 ;
        RECT 15.325 13.515 15.495 13.685 ;
        RECT 15.785 13.515 15.955 13.685 ;
        RECT 16.245 13.515 16.415 13.685 ;
        RECT 16.705 13.515 16.875 13.685 ;
        RECT 17.165 13.515 17.335 13.685 ;
        RECT 17.625 13.515 17.795 13.685 ;
        RECT 18.085 13.515 18.255 13.685 ;
        RECT 18.545 13.515 18.715 13.685 ;
        RECT 19.005 13.515 19.175 13.685 ;
        RECT 19.465 13.515 19.635 13.685 ;
        RECT 19.925 13.515 20.095 13.685 ;
        RECT 20.385 13.515 20.555 13.685 ;
        RECT 20.845 13.515 21.015 13.685 ;
        RECT 21.305 13.515 21.475 13.685 ;
        RECT 21.765 13.515 21.935 13.685 ;
        RECT 22.225 13.515 22.395 13.685 ;
        RECT 22.685 13.515 22.855 13.685 ;
        RECT 23.145 13.515 23.315 13.685 ;
        RECT 23.605 13.515 23.775 13.685 ;
        RECT 24.065 13.515 24.235 13.685 ;
        RECT 24.525 13.515 24.695 13.685 ;
        RECT 24.985 13.515 25.155 13.685 ;
        RECT 25.445 13.515 25.615 13.685 ;
        RECT 25.905 13.515 26.075 13.685 ;
        RECT 26.365 13.515 26.535 13.685 ;
        RECT 26.825 13.515 26.995 13.685 ;
        RECT 27.285 13.515 27.455 13.685 ;
        RECT 27.745 13.515 27.915 13.685 ;
        RECT 28.205 13.515 28.375 13.685 ;
        RECT 28.665 13.515 28.835 13.685 ;
        RECT 29.125 13.515 29.295 13.685 ;
        RECT 29.585 13.515 29.755 13.685 ;
        RECT 30.045 13.515 30.215 13.685 ;
        RECT 30.505 13.515 30.675 13.685 ;
        RECT 30.965 13.515 31.135 13.685 ;
        RECT 31.425 13.515 31.595 13.685 ;
        RECT 31.885 13.515 32.055 13.685 ;
        RECT 32.345 13.515 32.515 13.685 ;
        RECT 32.805 13.515 32.975 13.685 ;
        RECT 33.265 13.515 33.435 13.685 ;
        RECT 33.725 13.515 33.895 13.685 ;
        RECT 34.185 13.515 34.355 13.685 ;
        RECT 34.645 13.515 34.815 13.685 ;
        RECT 35.105 13.515 35.275 13.685 ;
        RECT 35.565 13.515 35.735 13.685 ;
        RECT 36.025 13.515 36.195 13.685 ;
        RECT 36.485 13.515 36.655 13.685 ;
        RECT 36.945 13.515 37.115 13.685 ;
        RECT 37.405 13.515 37.575 13.685 ;
        RECT 37.865 13.515 38.035 13.685 ;
        RECT 38.325 13.515 38.495 13.685 ;
        RECT 38.785 13.515 38.955 13.685 ;
        RECT 39.245 13.515 39.415 13.685 ;
        RECT 39.705 13.515 39.875 13.685 ;
        RECT 40.165 13.515 40.335 13.685 ;
        RECT 40.625 13.515 40.795 13.685 ;
        RECT 41.085 13.515 41.255 13.685 ;
        RECT 41.545 13.515 41.715 13.685 ;
        RECT 42.005 13.515 42.175 13.685 ;
        RECT 42.465 13.515 42.635 13.685 ;
        RECT 42.925 13.515 43.095 13.685 ;
        RECT 43.385 13.515 43.555 13.685 ;
        RECT 43.845 13.515 44.015 13.685 ;
        RECT 44.305 13.515 44.475 13.685 ;
        RECT 44.765 13.515 44.935 13.685 ;
        RECT 45.225 13.515 45.395 13.685 ;
        RECT 45.685 13.515 45.855 13.685 ;
        RECT 46.145 13.515 46.315 13.685 ;
        RECT 46.605 13.515 46.775 13.685 ;
        RECT 47.065 13.515 47.235 13.685 ;
        RECT 47.525 13.515 47.695 13.685 ;
        RECT 47.985 13.515 48.155 13.685 ;
        RECT 48.445 13.515 48.615 13.685 ;
        RECT 1.525 8.075 1.695 8.245 ;
        RECT 1.985 8.075 2.155 8.245 ;
        RECT 2.445 8.075 2.615 8.245 ;
        RECT 2.905 8.075 3.075 8.245 ;
        RECT 3.365 8.075 3.535 8.245 ;
        RECT 3.825 8.075 3.995 8.245 ;
        RECT 4.285 8.075 4.455 8.245 ;
        RECT 4.745 8.075 4.915 8.245 ;
        RECT 5.205 8.075 5.375 8.245 ;
        RECT 5.665 8.075 5.835 8.245 ;
        RECT 6.125 8.075 6.295 8.245 ;
        RECT 6.585 8.075 6.755 8.245 ;
        RECT 7.045 8.075 7.215 8.245 ;
        RECT 7.505 8.075 7.675 8.245 ;
        RECT 7.965 8.075 8.135 8.245 ;
        RECT 8.425 8.075 8.595 8.245 ;
        RECT 8.885 8.075 9.055 8.245 ;
        RECT 9.345 8.075 9.515 8.245 ;
        RECT 9.805 8.075 9.975 8.245 ;
        RECT 10.265 8.075 10.435 8.245 ;
        RECT 10.725 8.075 10.895 8.245 ;
        RECT 11.185 8.075 11.355 8.245 ;
        RECT 11.645 8.075 11.815 8.245 ;
        RECT 12.105 8.075 12.275 8.245 ;
        RECT 12.565 8.075 12.735 8.245 ;
        RECT 13.025 8.075 13.195 8.245 ;
        RECT 13.485 8.075 13.655 8.245 ;
        RECT 13.945 8.075 14.115 8.245 ;
        RECT 14.405 8.075 14.575 8.245 ;
        RECT 14.865 8.075 15.035 8.245 ;
        RECT 15.325 8.075 15.495 8.245 ;
        RECT 15.785 8.075 15.955 8.245 ;
        RECT 16.245 8.075 16.415 8.245 ;
        RECT 16.705 8.075 16.875 8.245 ;
        RECT 17.165 8.075 17.335 8.245 ;
        RECT 17.625 8.075 17.795 8.245 ;
        RECT 18.085 8.075 18.255 8.245 ;
        RECT 18.545 8.075 18.715 8.245 ;
        RECT 19.005 8.075 19.175 8.245 ;
        RECT 19.465 8.075 19.635 8.245 ;
        RECT 19.925 8.075 20.095 8.245 ;
        RECT 20.385 8.075 20.555 8.245 ;
        RECT 20.845 8.075 21.015 8.245 ;
        RECT 21.305 8.075 21.475 8.245 ;
        RECT 21.765 8.075 21.935 8.245 ;
        RECT 22.225 8.075 22.395 8.245 ;
        RECT 22.685 8.075 22.855 8.245 ;
        RECT 23.145 8.075 23.315 8.245 ;
        RECT 23.605 8.075 23.775 8.245 ;
        RECT 24.065 8.075 24.235 8.245 ;
        RECT 24.525 8.075 24.695 8.245 ;
        RECT 24.985 8.075 25.155 8.245 ;
        RECT 25.445 8.075 25.615 8.245 ;
        RECT 25.905 8.075 26.075 8.245 ;
        RECT 26.365 8.075 26.535 8.245 ;
        RECT 26.825 8.075 26.995 8.245 ;
        RECT 27.285 8.075 27.455 8.245 ;
        RECT 27.745 8.075 27.915 8.245 ;
        RECT 28.205 8.075 28.375 8.245 ;
        RECT 28.665 8.075 28.835 8.245 ;
        RECT 29.125 8.075 29.295 8.245 ;
        RECT 29.585 8.075 29.755 8.245 ;
        RECT 30.045 8.075 30.215 8.245 ;
        RECT 30.505 8.075 30.675 8.245 ;
        RECT 30.965 8.075 31.135 8.245 ;
        RECT 31.425 8.075 31.595 8.245 ;
        RECT 31.885 8.075 32.055 8.245 ;
        RECT 32.345 8.075 32.515 8.245 ;
        RECT 32.805 8.075 32.975 8.245 ;
        RECT 33.265 8.075 33.435 8.245 ;
        RECT 33.725 8.075 33.895 8.245 ;
        RECT 34.185 8.075 34.355 8.245 ;
        RECT 34.645 8.075 34.815 8.245 ;
        RECT 35.105 8.075 35.275 8.245 ;
        RECT 35.565 8.075 35.735 8.245 ;
        RECT 36.025 8.075 36.195 8.245 ;
        RECT 36.485 8.075 36.655 8.245 ;
        RECT 36.945 8.075 37.115 8.245 ;
        RECT 37.405 8.075 37.575 8.245 ;
        RECT 37.865 8.075 38.035 8.245 ;
        RECT 38.325 8.075 38.495 8.245 ;
        RECT 38.785 8.075 38.955 8.245 ;
        RECT 39.245 8.075 39.415 8.245 ;
        RECT 39.705 8.075 39.875 8.245 ;
        RECT 40.165 8.075 40.335 8.245 ;
        RECT 40.625 8.075 40.795 8.245 ;
        RECT 41.085 8.075 41.255 8.245 ;
        RECT 41.545 8.075 41.715 8.245 ;
        RECT 42.005 8.075 42.175 8.245 ;
        RECT 42.465 8.075 42.635 8.245 ;
        RECT 42.925 8.075 43.095 8.245 ;
        RECT 43.385 8.075 43.555 8.245 ;
        RECT 43.845 8.075 44.015 8.245 ;
        RECT 44.305 8.075 44.475 8.245 ;
        RECT 44.765 8.075 44.935 8.245 ;
        RECT 45.225 8.075 45.395 8.245 ;
        RECT 45.685 8.075 45.855 8.245 ;
        RECT 46.145 8.075 46.315 8.245 ;
        RECT 46.605 8.075 46.775 8.245 ;
        RECT 47.065 8.075 47.235 8.245 ;
        RECT 47.525 8.075 47.695 8.245 ;
        RECT 47.985 8.075 48.155 8.245 ;
        RECT 48.445 8.075 48.615 8.245 ;
        RECT 1.525 2.635 1.695 2.805 ;
        RECT 1.985 2.635 2.155 2.805 ;
        RECT 2.445 2.635 2.615 2.805 ;
        RECT 2.905 2.635 3.075 2.805 ;
        RECT 3.365 2.635 3.535 2.805 ;
        RECT 3.825 2.635 3.995 2.805 ;
        RECT 4.285 2.635 4.455 2.805 ;
        RECT 4.745 2.635 4.915 2.805 ;
        RECT 5.205 2.635 5.375 2.805 ;
        RECT 5.665 2.635 5.835 2.805 ;
        RECT 6.125 2.635 6.295 2.805 ;
        RECT 6.585 2.635 6.755 2.805 ;
        RECT 7.045 2.635 7.215 2.805 ;
        RECT 7.505 2.635 7.675 2.805 ;
        RECT 7.965 2.635 8.135 2.805 ;
        RECT 8.425 2.635 8.595 2.805 ;
        RECT 8.885 2.635 9.055 2.805 ;
        RECT 9.345 2.635 9.515 2.805 ;
        RECT 9.805 2.635 9.975 2.805 ;
        RECT 10.265 2.635 10.435 2.805 ;
        RECT 10.725 2.635 10.895 2.805 ;
        RECT 11.185 2.635 11.355 2.805 ;
        RECT 11.645 2.635 11.815 2.805 ;
        RECT 12.105 2.635 12.275 2.805 ;
        RECT 12.565 2.635 12.735 2.805 ;
        RECT 13.025 2.635 13.195 2.805 ;
        RECT 13.485 2.635 13.655 2.805 ;
        RECT 13.945 2.635 14.115 2.805 ;
        RECT 14.405 2.635 14.575 2.805 ;
        RECT 14.865 2.635 15.035 2.805 ;
        RECT 15.325 2.635 15.495 2.805 ;
        RECT 15.785 2.635 15.955 2.805 ;
        RECT 16.245 2.635 16.415 2.805 ;
        RECT 16.705 2.635 16.875 2.805 ;
        RECT 17.165 2.635 17.335 2.805 ;
        RECT 17.625 2.635 17.795 2.805 ;
        RECT 18.085 2.635 18.255 2.805 ;
        RECT 18.545 2.635 18.715 2.805 ;
        RECT 19.005 2.635 19.175 2.805 ;
        RECT 19.465 2.635 19.635 2.805 ;
        RECT 19.925 2.635 20.095 2.805 ;
        RECT 20.385 2.635 20.555 2.805 ;
        RECT 20.845 2.635 21.015 2.805 ;
        RECT 21.305 2.635 21.475 2.805 ;
        RECT 21.765 2.635 21.935 2.805 ;
        RECT 22.225 2.635 22.395 2.805 ;
        RECT 22.685 2.635 22.855 2.805 ;
        RECT 23.145 2.635 23.315 2.805 ;
        RECT 23.605 2.635 23.775 2.805 ;
        RECT 24.065 2.635 24.235 2.805 ;
        RECT 24.525 2.635 24.695 2.805 ;
        RECT 24.985 2.635 25.155 2.805 ;
        RECT 25.445 2.635 25.615 2.805 ;
        RECT 25.905 2.635 26.075 2.805 ;
        RECT 26.365 2.635 26.535 2.805 ;
        RECT 26.825 2.635 26.995 2.805 ;
        RECT 27.285 2.635 27.455 2.805 ;
        RECT 27.745 2.635 27.915 2.805 ;
        RECT 28.205 2.635 28.375 2.805 ;
        RECT 28.665 2.635 28.835 2.805 ;
        RECT 29.125 2.635 29.295 2.805 ;
        RECT 29.585 2.635 29.755 2.805 ;
        RECT 30.045 2.635 30.215 2.805 ;
        RECT 30.505 2.635 30.675 2.805 ;
        RECT 30.965 2.635 31.135 2.805 ;
        RECT 31.425 2.635 31.595 2.805 ;
        RECT 31.885 2.635 32.055 2.805 ;
        RECT 32.345 2.635 32.515 2.805 ;
        RECT 32.805 2.635 32.975 2.805 ;
        RECT 33.265 2.635 33.435 2.805 ;
        RECT 33.725 2.635 33.895 2.805 ;
        RECT 34.185 2.635 34.355 2.805 ;
        RECT 34.645 2.635 34.815 2.805 ;
        RECT 35.105 2.635 35.275 2.805 ;
        RECT 35.565 2.635 35.735 2.805 ;
        RECT 36.025 2.635 36.195 2.805 ;
        RECT 36.485 2.635 36.655 2.805 ;
        RECT 36.945 2.635 37.115 2.805 ;
        RECT 37.405 2.635 37.575 2.805 ;
        RECT 37.865 2.635 38.035 2.805 ;
        RECT 38.325 2.635 38.495 2.805 ;
        RECT 38.785 2.635 38.955 2.805 ;
        RECT 39.245 2.635 39.415 2.805 ;
        RECT 39.705 2.635 39.875 2.805 ;
        RECT 40.165 2.635 40.335 2.805 ;
        RECT 40.625 2.635 40.795 2.805 ;
        RECT 41.085 2.635 41.255 2.805 ;
        RECT 41.545 2.635 41.715 2.805 ;
        RECT 42.005 2.635 42.175 2.805 ;
        RECT 42.465 2.635 42.635 2.805 ;
        RECT 42.925 2.635 43.095 2.805 ;
        RECT 43.385 2.635 43.555 2.805 ;
        RECT 43.845 2.635 44.015 2.805 ;
        RECT 44.305 2.635 44.475 2.805 ;
        RECT 44.765 2.635 44.935 2.805 ;
        RECT 45.225 2.635 45.395 2.805 ;
        RECT 45.685 2.635 45.855 2.805 ;
        RECT 46.145 2.635 46.315 2.805 ;
        RECT 46.605 2.635 46.775 2.805 ;
        RECT 47.065 2.635 47.235 2.805 ;
        RECT 47.525 2.635 47.695 2.805 ;
        RECT 47.985 2.635 48.155 2.805 ;
        RECT 48.445 2.635 48.615 2.805 ;
      LAYER met1 ;
        RECT -10.620 35.120 60.760 35.600 ;
        RECT -10.620 29.680 60.760 30.160 ;
        RECT -10.620 24.240 60.760 24.720 ;
        RECT -10.620 18.800 60.760 19.280 ;
        RECT -10.620 13.360 60.760 13.840 ;
        RECT -10.620 7.920 60.760 8.400 ;
        RECT -10.620 2.480 60.760 2.960 ;
      LAYER via ;
        RECT -10.570 35.230 -10.310 35.490 ;
        RECT -10.250 35.230 -9.990 35.490 ;
        RECT -9.930 35.230 -9.670 35.490 ;
        RECT -9.610 35.230 -9.350 35.490 ;
        RECT -9.290 35.230 -9.030 35.490 ;
        RECT -8.970 35.230 -8.710 35.490 ;
        RECT -8.650 35.230 -8.390 35.490 ;
        RECT -8.330 35.230 -8.070 35.490 ;
        RECT -8.010 35.230 -7.750 35.490 ;
        RECT -7.690 35.230 -7.430 35.490 ;
        RECT -7.370 35.230 -7.110 35.490 ;
        RECT -7.050 35.230 -6.790 35.490 ;
        RECT -6.730 35.230 -6.470 35.490 ;
        RECT 27.750 35.230 28.010 35.490 ;
        RECT 28.070 35.230 28.330 35.490 ;
        RECT 28.390 35.230 28.650 35.490 ;
        RECT 28.710 35.230 28.970 35.490 ;
        RECT 29.030 35.230 29.290 35.490 ;
        RECT 56.610 35.230 56.870 35.490 ;
        RECT 56.930 35.230 57.190 35.490 ;
        RECT 57.250 35.230 57.510 35.490 ;
        RECT 57.570 35.230 57.830 35.490 ;
        RECT 57.890 35.230 58.150 35.490 ;
        RECT 58.210 35.230 58.470 35.490 ;
        RECT 58.530 35.230 58.790 35.490 ;
        RECT 58.850 35.230 59.110 35.490 ;
        RECT 59.170 35.230 59.430 35.490 ;
        RECT 59.490 35.230 59.750 35.490 ;
        RECT 59.810 35.230 60.070 35.490 ;
        RECT 60.130 35.230 60.390 35.490 ;
        RECT 60.450 35.230 60.710 35.490 ;
        RECT -10.570 29.790 -10.310 30.050 ;
        RECT -10.250 29.790 -9.990 30.050 ;
        RECT -9.930 29.790 -9.670 30.050 ;
        RECT -9.610 29.790 -9.350 30.050 ;
        RECT -9.290 29.790 -9.030 30.050 ;
        RECT -8.970 29.790 -8.710 30.050 ;
        RECT -8.650 29.790 -8.390 30.050 ;
        RECT -8.330 29.790 -8.070 30.050 ;
        RECT -8.010 29.790 -7.750 30.050 ;
        RECT -7.690 29.790 -7.430 30.050 ;
        RECT -7.370 29.790 -7.110 30.050 ;
        RECT -7.050 29.790 -6.790 30.050 ;
        RECT -6.730 29.790 -6.470 30.050 ;
        RECT 27.750 29.790 28.010 30.050 ;
        RECT 28.070 29.790 28.330 30.050 ;
        RECT 28.390 29.790 28.650 30.050 ;
        RECT 28.710 29.790 28.970 30.050 ;
        RECT 29.030 29.790 29.290 30.050 ;
        RECT 56.610 29.790 56.870 30.050 ;
        RECT 56.930 29.790 57.190 30.050 ;
        RECT 57.250 29.790 57.510 30.050 ;
        RECT 57.570 29.790 57.830 30.050 ;
        RECT 57.890 29.790 58.150 30.050 ;
        RECT 58.210 29.790 58.470 30.050 ;
        RECT 58.530 29.790 58.790 30.050 ;
        RECT 58.850 29.790 59.110 30.050 ;
        RECT 59.170 29.790 59.430 30.050 ;
        RECT 59.490 29.790 59.750 30.050 ;
        RECT 59.810 29.790 60.070 30.050 ;
        RECT 60.130 29.790 60.390 30.050 ;
        RECT 60.450 29.790 60.710 30.050 ;
        RECT -10.570 24.350 -10.310 24.610 ;
        RECT -10.250 24.350 -9.990 24.610 ;
        RECT -9.930 24.350 -9.670 24.610 ;
        RECT -9.610 24.350 -9.350 24.610 ;
        RECT -9.290 24.350 -9.030 24.610 ;
        RECT -8.970 24.350 -8.710 24.610 ;
        RECT -8.650 24.350 -8.390 24.610 ;
        RECT -8.330 24.350 -8.070 24.610 ;
        RECT -8.010 24.350 -7.750 24.610 ;
        RECT -7.690 24.350 -7.430 24.610 ;
        RECT -7.370 24.350 -7.110 24.610 ;
        RECT -7.050 24.350 -6.790 24.610 ;
        RECT -6.730 24.350 -6.470 24.610 ;
        RECT 27.750 24.350 28.010 24.610 ;
        RECT 28.070 24.350 28.330 24.610 ;
        RECT 28.390 24.350 28.650 24.610 ;
        RECT 28.710 24.350 28.970 24.610 ;
        RECT 29.030 24.350 29.290 24.610 ;
        RECT 56.610 24.350 56.870 24.610 ;
        RECT 56.930 24.350 57.190 24.610 ;
        RECT 57.250 24.350 57.510 24.610 ;
        RECT 57.570 24.350 57.830 24.610 ;
        RECT 57.890 24.350 58.150 24.610 ;
        RECT 58.210 24.350 58.470 24.610 ;
        RECT 58.530 24.350 58.790 24.610 ;
        RECT 58.850 24.350 59.110 24.610 ;
        RECT 59.170 24.350 59.430 24.610 ;
        RECT 59.490 24.350 59.750 24.610 ;
        RECT 59.810 24.350 60.070 24.610 ;
        RECT 60.130 24.350 60.390 24.610 ;
        RECT 60.450 24.350 60.710 24.610 ;
        RECT -10.570 18.910 -10.310 19.170 ;
        RECT -10.250 18.910 -9.990 19.170 ;
        RECT -9.930 18.910 -9.670 19.170 ;
        RECT -9.610 18.910 -9.350 19.170 ;
        RECT -9.290 18.910 -9.030 19.170 ;
        RECT -8.970 18.910 -8.710 19.170 ;
        RECT -8.650 18.910 -8.390 19.170 ;
        RECT -8.330 18.910 -8.070 19.170 ;
        RECT -8.010 18.910 -7.750 19.170 ;
        RECT -7.690 18.910 -7.430 19.170 ;
        RECT -7.370 18.910 -7.110 19.170 ;
        RECT -7.050 18.910 -6.790 19.170 ;
        RECT -6.730 18.910 -6.470 19.170 ;
        RECT 27.750 18.910 28.010 19.170 ;
        RECT 28.070 18.910 28.330 19.170 ;
        RECT 28.390 18.910 28.650 19.170 ;
        RECT 28.710 18.910 28.970 19.170 ;
        RECT 29.030 18.910 29.290 19.170 ;
        RECT 56.610 18.910 56.870 19.170 ;
        RECT 56.930 18.910 57.190 19.170 ;
        RECT 57.250 18.910 57.510 19.170 ;
        RECT 57.570 18.910 57.830 19.170 ;
        RECT 57.890 18.910 58.150 19.170 ;
        RECT 58.210 18.910 58.470 19.170 ;
        RECT 58.530 18.910 58.790 19.170 ;
        RECT 58.850 18.910 59.110 19.170 ;
        RECT 59.170 18.910 59.430 19.170 ;
        RECT 59.490 18.910 59.750 19.170 ;
        RECT 59.810 18.910 60.070 19.170 ;
        RECT 60.130 18.910 60.390 19.170 ;
        RECT 60.450 18.910 60.710 19.170 ;
        RECT -10.570 13.470 -10.310 13.730 ;
        RECT -10.250 13.470 -9.990 13.730 ;
        RECT -9.930 13.470 -9.670 13.730 ;
        RECT -9.610 13.470 -9.350 13.730 ;
        RECT -9.290 13.470 -9.030 13.730 ;
        RECT -8.970 13.470 -8.710 13.730 ;
        RECT -8.650 13.470 -8.390 13.730 ;
        RECT -8.330 13.470 -8.070 13.730 ;
        RECT -8.010 13.470 -7.750 13.730 ;
        RECT -7.690 13.470 -7.430 13.730 ;
        RECT -7.370 13.470 -7.110 13.730 ;
        RECT -7.050 13.470 -6.790 13.730 ;
        RECT -6.730 13.470 -6.470 13.730 ;
        RECT 27.750 13.470 28.010 13.730 ;
        RECT 28.070 13.470 28.330 13.730 ;
        RECT 28.390 13.470 28.650 13.730 ;
        RECT 28.710 13.470 28.970 13.730 ;
        RECT 29.030 13.470 29.290 13.730 ;
        RECT 56.610 13.470 56.870 13.730 ;
        RECT 56.930 13.470 57.190 13.730 ;
        RECT 57.250 13.470 57.510 13.730 ;
        RECT 57.570 13.470 57.830 13.730 ;
        RECT 57.890 13.470 58.150 13.730 ;
        RECT 58.210 13.470 58.470 13.730 ;
        RECT 58.530 13.470 58.790 13.730 ;
        RECT 58.850 13.470 59.110 13.730 ;
        RECT 59.170 13.470 59.430 13.730 ;
        RECT 59.490 13.470 59.750 13.730 ;
        RECT 59.810 13.470 60.070 13.730 ;
        RECT 60.130 13.470 60.390 13.730 ;
        RECT 60.450 13.470 60.710 13.730 ;
        RECT -10.570 8.030 -10.310 8.290 ;
        RECT -10.250 8.030 -9.990 8.290 ;
        RECT -9.930 8.030 -9.670 8.290 ;
        RECT -9.610 8.030 -9.350 8.290 ;
        RECT -9.290 8.030 -9.030 8.290 ;
        RECT -8.970 8.030 -8.710 8.290 ;
        RECT -8.650 8.030 -8.390 8.290 ;
        RECT -8.330 8.030 -8.070 8.290 ;
        RECT -8.010 8.030 -7.750 8.290 ;
        RECT -7.690 8.030 -7.430 8.290 ;
        RECT -7.370 8.030 -7.110 8.290 ;
        RECT -7.050 8.030 -6.790 8.290 ;
        RECT -6.730 8.030 -6.470 8.290 ;
        RECT 27.750 8.030 28.010 8.290 ;
        RECT 28.070 8.030 28.330 8.290 ;
        RECT 28.390 8.030 28.650 8.290 ;
        RECT 28.710 8.030 28.970 8.290 ;
        RECT 29.030 8.030 29.290 8.290 ;
        RECT 56.610 8.030 56.870 8.290 ;
        RECT 56.930 8.030 57.190 8.290 ;
        RECT 57.250 8.030 57.510 8.290 ;
        RECT 57.570 8.030 57.830 8.290 ;
        RECT 57.890 8.030 58.150 8.290 ;
        RECT 58.210 8.030 58.470 8.290 ;
        RECT 58.530 8.030 58.790 8.290 ;
        RECT 58.850 8.030 59.110 8.290 ;
        RECT 59.170 8.030 59.430 8.290 ;
        RECT 59.490 8.030 59.750 8.290 ;
        RECT 59.810 8.030 60.070 8.290 ;
        RECT 60.130 8.030 60.390 8.290 ;
        RECT 60.450 8.030 60.710 8.290 ;
        RECT -10.570 2.590 -10.310 2.850 ;
        RECT -10.250 2.590 -9.990 2.850 ;
        RECT -9.930 2.590 -9.670 2.850 ;
        RECT -9.610 2.590 -9.350 2.850 ;
        RECT -9.290 2.590 -9.030 2.850 ;
        RECT -8.970 2.590 -8.710 2.850 ;
        RECT -8.650 2.590 -8.390 2.850 ;
        RECT -8.330 2.590 -8.070 2.850 ;
        RECT -8.010 2.590 -7.750 2.850 ;
        RECT -7.690 2.590 -7.430 2.850 ;
        RECT -7.370 2.590 -7.110 2.850 ;
        RECT -7.050 2.590 -6.790 2.850 ;
        RECT -6.730 2.590 -6.470 2.850 ;
        RECT 27.750 2.590 28.010 2.850 ;
        RECT 28.070 2.590 28.330 2.850 ;
        RECT 28.390 2.590 28.650 2.850 ;
        RECT 28.710 2.590 28.970 2.850 ;
        RECT 29.030 2.590 29.290 2.850 ;
        RECT 56.610 2.590 56.870 2.850 ;
        RECT 56.930 2.590 57.190 2.850 ;
        RECT 57.250 2.590 57.510 2.850 ;
        RECT 57.570 2.590 57.830 2.850 ;
        RECT 57.890 2.590 58.150 2.850 ;
        RECT 58.210 2.590 58.470 2.850 ;
        RECT 58.530 2.590 58.790 2.850 ;
        RECT 58.850 2.590 59.110 2.850 ;
        RECT 59.170 2.590 59.430 2.850 ;
        RECT 59.490 2.590 59.750 2.850 ;
        RECT 59.810 2.590 60.070 2.850 ;
        RECT 60.130 2.590 60.390 2.850 ;
        RECT 60.450 2.590 60.710 2.850 ;
      LAYER met2 ;
        RECT -10.570 35.120 -6.470 35.600 ;
        RECT 27.750 35.120 29.290 35.600 ;
        RECT 56.610 35.120 60.710 35.600 ;
        RECT -10.570 29.680 -6.470 30.160 ;
        RECT 27.750 29.680 29.290 30.160 ;
        RECT 56.610 29.680 60.710 30.160 ;
        RECT -10.570 24.240 -6.470 24.720 ;
        RECT 27.750 24.240 29.290 24.720 ;
        RECT 56.610 24.240 60.710 24.720 ;
        RECT -10.570 18.800 -6.470 19.280 ;
        RECT 27.750 18.800 29.290 19.280 ;
        RECT 56.610 18.800 60.710 19.280 ;
        RECT -10.570 13.360 -6.470 13.840 ;
        RECT 27.750 13.360 29.290 13.840 ;
        RECT 56.610 13.360 60.710 13.840 ;
        RECT -10.570 7.920 -6.470 8.400 ;
        RECT 27.750 7.920 29.290 8.400 ;
        RECT 56.610 7.920 60.710 8.400 ;
        RECT -10.570 2.480 -6.470 2.960 ;
        RECT 27.750 2.480 29.290 2.960 ;
        RECT 56.610 2.480 60.710 2.960 ;
      LAYER via2 ;
        RECT -10.460 35.220 -10.180 35.500 ;
        RECT -10.060 35.220 -9.780 35.500 ;
        RECT -9.660 35.220 -9.380 35.500 ;
        RECT -9.260 35.220 -8.980 35.500 ;
        RECT -8.860 35.220 -8.580 35.500 ;
        RECT -8.460 35.220 -8.180 35.500 ;
        RECT -8.060 35.220 -7.780 35.500 ;
        RECT -7.660 35.220 -7.380 35.500 ;
        RECT -7.260 35.220 -6.980 35.500 ;
        RECT -6.860 35.220 -6.580 35.500 ;
        RECT 27.780 35.220 28.060 35.500 ;
        RECT 28.180 35.220 28.460 35.500 ;
        RECT 28.580 35.220 28.860 35.500 ;
        RECT 28.980 35.220 29.260 35.500 ;
        RECT 56.720 35.220 57.000 35.500 ;
        RECT 57.120 35.220 57.400 35.500 ;
        RECT 57.520 35.220 57.800 35.500 ;
        RECT 57.920 35.220 58.200 35.500 ;
        RECT 58.320 35.220 58.600 35.500 ;
        RECT 58.720 35.220 59.000 35.500 ;
        RECT 59.120 35.220 59.400 35.500 ;
        RECT 59.520 35.220 59.800 35.500 ;
        RECT 59.920 35.220 60.200 35.500 ;
        RECT 60.320 35.220 60.600 35.500 ;
        RECT -10.460 29.780 -10.180 30.060 ;
        RECT -10.060 29.780 -9.780 30.060 ;
        RECT -9.660 29.780 -9.380 30.060 ;
        RECT -9.260 29.780 -8.980 30.060 ;
        RECT -8.860 29.780 -8.580 30.060 ;
        RECT -8.460 29.780 -8.180 30.060 ;
        RECT -8.060 29.780 -7.780 30.060 ;
        RECT -7.660 29.780 -7.380 30.060 ;
        RECT -7.260 29.780 -6.980 30.060 ;
        RECT -6.860 29.780 -6.580 30.060 ;
        RECT 27.780 29.780 28.060 30.060 ;
        RECT 28.180 29.780 28.460 30.060 ;
        RECT 28.580 29.780 28.860 30.060 ;
        RECT 28.980 29.780 29.260 30.060 ;
        RECT 56.720 29.780 57.000 30.060 ;
        RECT 57.120 29.780 57.400 30.060 ;
        RECT 57.520 29.780 57.800 30.060 ;
        RECT 57.920 29.780 58.200 30.060 ;
        RECT 58.320 29.780 58.600 30.060 ;
        RECT 58.720 29.780 59.000 30.060 ;
        RECT 59.120 29.780 59.400 30.060 ;
        RECT 59.520 29.780 59.800 30.060 ;
        RECT 59.920 29.780 60.200 30.060 ;
        RECT 60.320 29.780 60.600 30.060 ;
        RECT -10.460 24.340 -10.180 24.620 ;
        RECT -10.060 24.340 -9.780 24.620 ;
        RECT -9.660 24.340 -9.380 24.620 ;
        RECT -9.260 24.340 -8.980 24.620 ;
        RECT -8.860 24.340 -8.580 24.620 ;
        RECT -8.460 24.340 -8.180 24.620 ;
        RECT -8.060 24.340 -7.780 24.620 ;
        RECT -7.660 24.340 -7.380 24.620 ;
        RECT -7.260 24.340 -6.980 24.620 ;
        RECT -6.860 24.340 -6.580 24.620 ;
        RECT 27.780 24.340 28.060 24.620 ;
        RECT 28.180 24.340 28.460 24.620 ;
        RECT 28.580 24.340 28.860 24.620 ;
        RECT 28.980 24.340 29.260 24.620 ;
        RECT 56.720 24.340 57.000 24.620 ;
        RECT 57.120 24.340 57.400 24.620 ;
        RECT 57.520 24.340 57.800 24.620 ;
        RECT 57.920 24.340 58.200 24.620 ;
        RECT 58.320 24.340 58.600 24.620 ;
        RECT 58.720 24.340 59.000 24.620 ;
        RECT 59.120 24.340 59.400 24.620 ;
        RECT 59.520 24.340 59.800 24.620 ;
        RECT 59.920 24.340 60.200 24.620 ;
        RECT 60.320 24.340 60.600 24.620 ;
        RECT -10.460 18.900 -10.180 19.180 ;
        RECT -10.060 18.900 -9.780 19.180 ;
        RECT -9.660 18.900 -9.380 19.180 ;
        RECT -9.260 18.900 -8.980 19.180 ;
        RECT -8.860 18.900 -8.580 19.180 ;
        RECT -8.460 18.900 -8.180 19.180 ;
        RECT -8.060 18.900 -7.780 19.180 ;
        RECT -7.660 18.900 -7.380 19.180 ;
        RECT -7.260 18.900 -6.980 19.180 ;
        RECT -6.860 18.900 -6.580 19.180 ;
        RECT 27.780 18.900 28.060 19.180 ;
        RECT 28.180 18.900 28.460 19.180 ;
        RECT 28.580 18.900 28.860 19.180 ;
        RECT 28.980 18.900 29.260 19.180 ;
        RECT 56.720 18.900 57.000 19.180 ;
        RECT 57.120 18.900 57.400 19.180 ;
        RECT 57.520 18.900 57.800 19.180 ;
        RECT 57.920 18.900 58.200 19.180 ;
        RECT 58.320 18.900 58.600 19.180 ;
        RECT 58.720 18.900 59.000 19.180 ;
        RECT 59.120 18.900 59.400 19.180 ;
        RECT 59.520 18.900 59.800 19.180 ;
        RECT 59.920 18.900 60.200 19.180 ;
        RECT 60.320 18.900 60.600 19.180 ;
        RECT -10.460 13.460 -10.180 13.740 ;
        RECT -10.060 13.460 -9.780 13.740 ;
        RECT -9.660 13.460 -9.380 13.740 ;
        RECT -9.260 13.460 -8.980 13.740 ;
        RECT -8.860 13.460 -8.580 13.740 ;
        RECT -8.460 13.460 -8.180 13.740 ;
        RECT -8.060 13.460 -7.780 13.740 ;
        RECT -7.660 13.460 -7.380 13.740 ;
        RECT -7.260 13.460 -6.980 13.740 ;
        RECT -6.860 13.460 -6.580 13.740 ;
        RECT 27.780 13.460 28.060 13.740 ;
        RECT 28.180 13.460 28.460 13.740 ;
        RECT 28.580 13.460 28.860 13.740 ;
        RECT 28.980 13.460 29.260 13.740 ;
        RECT 56.720 13.460 57.000 13.740 ;
        RECT 57.120 13.460 57.400 13.740 ;
        RECT 57.520 13.460 57.800 13.740 ;
        RECT 57.920 13.460 58.200 13.740 ;
        RECT 58.320 13.460 58.600 13.740 ;
        RECT 58.720 13.460 59.000 13.740 ;
        RECT 59.120 13.460 59.400 13.740 ;
        RECT 59.520 13.460 59.800 13.740 ;
        RECT 59.920 13.460 60.200 13.740 ;
        RECT 60.320 13.460 60.600 13.740 ;
        RECT -10.460 8.020 -10.180 8.300 ;
        RECT -10.060 8.020 -9.780 8.300 ;
        RECT -9.660 8.020 -9.380 8.300 ;
        RECT -9.260 8.020 -8.980 8.300 ;
        RECT -8.860 8.020 -8.580 8.300 ;
        RECT -8.460 8.020 -8.180 8.300 ;
        RECT -8.060 8.020 -7.780 8.300 ;
        RECT -7.660 8.020 -7.380 8.300 ;
        RECT -7.260 8.020 -6.980 8.300 ;
        RECT -6.860 8.020 -6.580 8.300 ;
        RECT 27.780 8.020 28.060 8.300 ;
        RECT 28.180 8.020 28.460 8.300 ;
        RECT 28.580 8.020 28.860 8.300 ;
        RECT 28.980 8.020 29.260 8.300 ;
        RECT 56.720 8.020 57.000 8.300 ;
        RECT 57.120 8.020 57.400 8.300 ;
        RECT 57.520 8.020 57.800 8.300 ;
        RECT 57.920 8.020 58.200 8.300 ;
        RECT 58.320 8.020 58.600 8.300 ;
        RECT 58.720 8.020 59.000 8.300 ;
        RECT 59.120 8.020 59.400 8.300 ;
        RECT 59.520 8.020 59.800 8.300 ;
        RECT 59.920 8.020 60.200 8.300 ;
        RECT 60.320 8.020 60.600 8.300 ;
        RECT -10.460 2.580 -10.180 2.860 ;
        RECT -10.060 2.580 -9.780 2.860 ;
        RECT -9.660 2.580 -9.380 2.860 ;
        RECT -9.260 2.580 -8.980 2.860 ;
        RECT -8.860 2.580 -8.580 2.860 ;
        RECT -8.460 2.580 -8.180 2.860 ;
        RECT -8.060 2.580 -7.780 2.860 ;
        RECT -7.660 2.580 -7.380 2.860 ;
        RECT -7.260 2.580 -6.980 2.860 ;
        RECT -6.860 2.580 -6.580 2.860 ;
        RECT 27.780 2.580 28.060 2.860 ;
        RECT 28.180 2.580 28.460 2.860 ;
        RECT 28.580 2.580 28.860 2.860 ;
        RECT 28.980 2.580 29.260 2.860 ;
        RECT 56.720 2.580 57.000 2.860 ;
        RECT 57.120 2.580 57.400 2.860 ;
        RECT 57.520 2.580 57.800 2.860 ;
        RECT 57.920 2.580 58.200 2.860 ;
        RECT 58.320 2.580 58.600 2.860 ;
        RECT 58.720 2.580 59.000 2.860 ;
        RECT 59.120 2.580 59.400 2.860 ;
        RECT 59.520 2.580 59.800 2.860 ;
        RECT 59.920 2.580 60.200 2.860 ;
        RECT 60.320 2.580 60.600 2.860 ;
      LAYER met3 ;
        RECT -10.620 35.195 -6.420 35.525 ;
        RECT 27.720 35.195 29.320 35.525 ;
        RECT 56.560 35.195 60.760 35.525 ;
        RECT -10.620 29.755 -6.420 30.085 ;
        RECT 27.720 29.755 29.320 30.085 ;
        RECT 56.560 29.755 60.760 30.085 ;
        RECT -10.620 24.315 -6.420 24.645 ;
        RECT 27.720 24.315 29.320 24.645 ;
        RECT 56.560 24.315 60.760 24.645 ;
        RECT -10.620 18.875 -6.420 19.205 ;
        RECT 27.720 18.875 29.320 19.205 ;
        RECT 56.560 18.875 60.760 19.205 ;
        RECT -10.620 13.435 -6.420 13.765 ;
        RECT 27.720 13.435 29.320 13.765 ;
        RECT 56.560 13.435 60.760 13.765 ;
        RECT -10.620 7.995 -6.420 8.325 ;
        RECT 27.720 7.995 29.320 8.325 ;
        RECT 56.560 7.995 60.760 8.325 ;
        RECT -10.620 2.555 -6.420 2.885 ;
        RECT 27.720 2.555 29.320 2.885 ;
        RECT 56.560 2.555 60.760 2.885 ;
      LAYER via3 ;
        RECT -10.480 35.200 -10.160 35.520 ;
        RECT -10.080 35.200 -9.760 35.520 ;
        RECT -9.680 35.200 -9.360 35.520 ;
        RECT -9.280 35.200 -8.960 35.520 ;
        RECT -8.880 35.200 -8.560 35.520 ;
        RECT -8.480 35.200 -8.160 35.520 ;
        RECT -8.080 35.200 -7.760 35.520 ;
        RECT -7.680 35.200 -7.360 35.520 ;
        RECT -7.280 35.200 -6.960 35.520 ;
        RECT -6.880 35.200 -6.560 35.520 ;
        RECT 27.760 35.200 28.080 35.520 ;
        RECT 28.160 35.200 28.480 35.520 ;
        RECT 28.560 35.200 28.880 35.520 ;
        RECT 28.960 35.200 29.280 35.520 ;
        RECT 56.700 35.200 57.020 35.520 ;
        RECT 57.100 35.200 57.420 35.520 ;
        RECT 57.500 35.200 57.820 35.520 ;
        RECT 57.900 35.200 58.220 35.520 ;
        RECT 58.300 35.200 58.620 35.520 ;
        RECT 58.700 35.200 59.020 35.520 ;
        RECT 59.100 35.200 59.420 35.520 ;
        RECT 59.500 35.200 59.820 35.520 ;
        RECT 59.900 35.200 60.220 35.520 ;
        RECT 60.300 35.200 60.620 35.520 ;
        RECT -10.480 29.760 -10.160 30.080 ;
        RECT -10.080 29.760 -9.760 30.080 ;
        RECT -9.680 29.760 -9.360 30.080 ;
        RECT -9.280 29.760 -8.960 30.080 ;
        RECT -8.880 29.760 -8.560 30.080 ;
        RECT -8.480 29.760 -8.160 30.080 ;
        RECT -8.080 29.760 -7.760 30.080 ;
        RECT -7.680 29.760 -7.360 30.080 ;
        RECT -7.280 29.760 -6.960 30.080 ;
        RECT -6.880 29.760 -6.560 30.080 ;
        RECT 27.760 29.760 28.080 30.080 ;
        RECT 28.160 29.760 28.480 30.080 ;
        RECT 28.560 29.760 28.880 30.080 ;
        RECT 28.960 29.760 29.280 30.080 ;
        RECT 56.700 29.760 57.020 30.080 ;
        RECT 57.100 29.760 57.420 30.080 ;
        RECT 57.500 29.760 57.820 30.080 ;
        RECT 57.900 29.760 58.220 30.080 ;
        RECT 58.300 29.760 58.620 30.080 ;
        RECT 58.700 29.760 59.020 30.080 ;
        RECT 59.100 29.760 59.420 30.080 ;
        RECT 59.500 29.760 59.820 30.080 ;
        RECT 59.900 29.760 60.220 30.080 ;
        RECT 60.300 29.760 60.620 30.080 ;
        RECT -10.480 24.320 -10.160 24.640 ;
        RECT -10.080 24.320 -9.760 24.640 ;
        RECT -9.680 24.320 -9.360 24.640 ;
        RECT -9.280 24.320 -8.960 24.640 ;
        RECT -8.880 24.320 -8.560 24.640 ;
        RECT -8.480 24.320 -8.160 24.640 ;
        RECT -8.080 24.320 -7.760 24.640 ;
        RECT -7.680 24.320 -7.360 24.640 ;
        RECT -7.280 24.320 -6.960 24.640 ;
        RECT -6.880 24.320 -6.560 24.640 ;
        RECT 27.760 24.320 28.080 24.640 ;
        RECT 28.160 24.320 28.480 24.640 ;
        RECT 28.560 24.320 28.880 24.640 ;
        RECT 28.960 24.320 29.280 24.640 ;
        RECT 56.700 24.320 57.020 24.640 ;
        RECT 57.100 24.320 57.420 24.640 ;
        RECT 57.500 24.320 57.820 24.640 ;
        RECT 57.900 24.320 58.220 24.640 ;
        RECT 58.300 24.320 58.620 24.640 ;
        RECT 58.700 24.320 59.020 24.640 ;
        RECT 59.100 24.320 59.420 24.640 ;
        RECT 59.500 24.320 59.820 24.640 ;
        RECT 59.900 24.320 60.220 24.640 ;
        RECT 60.300 24.320 60.620 24.640 ;
        RECT -10.480 18.880 -10.160 19.200 ;
        RECT -10.080 18.880 -9.760 19.200 ;
        RECT -9.680 18.880 -9.360 19.200 ;
        RECT -9.280 18.880 -8.960 19.200 ;
        RECT -8.880 18.880 -8.560 19.200 ;
        RECT -8.480 18.880 -8.160 19.200 ;
        RECT -8.080 18.880 -7.760 19.200 ;
        RECT -7.680 18.880 -7.360 19.200 ;
        RECT -7.280 18.880 -6.960 19.200 ;
        RECT -6.880 18.880 -6.560 19.200 ;
        RECT 27.760 18.880 28.080 19.200 ;
        RECT 28.160 18.880 28.480 19.200 ;
        RECT 28.560 18.880 28.880 19.200 ;
        RECT 28.960 18.880 29.280 19.200 ;
        RECT 56.700 18.880 57.020 19.200 ;
        RECT 57.100 18.880 57.420 19.200 ;
        RECT 57.500 18.880 57.820 19.200 ;
        RECT 57.900 18.880 58.220 19.200 ;
        RECT 58.300 18.880 58.620 19.200 ;
        RECT 58.700 18.880 59.020 19.200 ;
        RECT 59.100 18.880 59.420 19.200 ;
        RECT 59.500 18.880 59.820 19.200 ;
        RECT 59.900 18.880 60.220 19.200 ;
        RECT 60.300 18.880 60.620 19.200 ;
        RECT -10.480 13.440 -10.160 13.760 ;
        RECT -10.080 13.440 -9.760 13.760 ;
        RECT -9.680 13.440 -9.360 13.760 ;
        RECT -9.280 13.440 -8.960 13.760 ;
        RECT -8.880 13.440 -8.560 13.760 ;
        RECT -8.480 13.440 -8.160 13.760 ;
        RECT -8.080 13.440 -7.760 13.760 ;
        RECT -7.680 13.440 -7.360 13.760 ;
        RECT -7.280 13.440 -6.960 13.760 ;
        RECT -6.880 13.440 -6.560 13.760 ;
        RECT 27.760 13.440 28.080 13.760 ;
        RECT 28.160 13.440 28.480 13.760 ;
        RECT 28.560 13.440 28.880 13.760 ;
        RECT 28.960 13.440 29.280 13.760 ;
        RECT 56.700 13.440 57.020 13.760 ;
        RECT 57.100 13.440 57.420 13.760 ;
        RECT 57.500 13.440 57.820 13.760 ;
        RECT 57.900 13.440 58.220 13.760 ;
        RECT 58.300 13.440 58.620 13.760 ;
        RECT 58.700 13.440 59.020 13.760 ;
        RECT 59.100 13.440 59.420 13.760 ;
        RECT 59.500 13.440 59.820 13.760 ;
        RECT 59.900 13.440 60.220 13.760 ;
        RECT 60.300 13.440 60.620 13.760 ;
        RECT -10.480 8.000 -10.160 8.320 ;
        RECT -10.080 8.000 -9.760 8.320 ;
        RECT -9.680 8.000 -9.360 8.320 ;
        RECT -9.280 8.000 -8.960 8.320 ;
        RECT -8.880 8.000 -8.560 8.320 ;
        RECT -8.480 8.000 -8.160 8.320 ;
        RECT -8.080 8.000 -7.760 8.320 ;
        RECT -7.680 8.000 -7.360 8.320 ;
        RECT -7.280 8.000 -6.960 8.320 ;
        RECT -6.880 8.000 -6.560 8.320 ;
        RECT 27.760 8.000 28.080 8.320 ;
        RECT 28.160 8.000 28.480 8.320 ;
        RECT 28.560 8.000 28.880 8.320 ;
        RECT 28.960 8.000 29.280 8.320 ;
        RECT 56.700 8.000 57.020 8.320 ;
        RECT 57.100 8.000 57.420 8.320 ;
        RECT 57.500 8.000 57.820 8.320 ;
        RECT 57.900 8.000 58.220 8.320 ;
        RECT 58.300 8.000 58.620 8.320 ;
        RECT 58.700 8.000 59.020 8.320 ;
        RECT 59.100 8.000 59.420 8.320 ;
        RECT 59.500 8.000 59.820 8.320 ;
        RECT 59.900 8.000 60.220 8.320 ;
        RECT 60.300 8.000 60.620 8.320 ;
        RECT -10.480 2.560 -10.160 2.880 ;
        RECT -10.080 2.560 -9.760 2.880 ;
        RECT -9.680 2.560 -9.360 2.880 ;
        RECT -9.280 2.560 -8.960 2.880 ;
        RECT -8.880 2.560 -8.560 2.880 ;
        RECT -8.480 2.560 -8.160 2.880 ;
        RECT -8.080 2.560 -7.760 2.880 ;
        RECT -7.680 2.560 -7.360 2.880 ;
        RECT -7.280 2.560 -6.960 2.880 ;
        RECT -6.880 2.560 -6.560 2.880 ;
        RECT 27.760 2.560 28.080 2.880 ;
        RECT 28.160 2.560 28.480 2.880 ;
        RECT 28.560 2.560 28.880 2.880 ;
        RECT 28.960 2.560 29.280 2.880 ;
        RECT 56.700 2.560 57.020 2.880 ;
        RECT 57.100 2.560 57.420 2.880 ;
        RECT 57.500 2.560 57.820 2.880 ;
        RECT 57.900 2.560 58.220 2.880 ;
        RECT 58.300 2.560 58.620 2.880 ;
        RECT 58.700 2.560 59.020 2.880 ;
        RECT 59.100 2.560 59.420 2.880 ;
        RECT 59.500 2.560 59.820 2.880 ;
        RECT 59.900 2.560 60.220 2.880 ;
        RECT 60.300 2.560 60.620 2.880 ;
      LAYER met4 ;
        RECT -10.620 -9.280 -6.420 50.080 ;
        RECT 27.720 -9.280 29.320 50.080 ;
        RECT 56.560 -9.280 60.760 50.080 ;
      LAYER via4 ;
        RECT -9.910 46.590 -7.130 49.370 ;
        RECT -9.910 29.090 -8.730 30.270 ;
        RECT -8.310 29.090 -7.130 30.270 ;
        RECT -9.910 -8.570 -7.130 -5.790 ;
        RECT 27.930 48.190 29.110 49.370 ;
        RECT 27.930 46.590 29.110 47.770 ;
        RECT 27.930 29.090 29.110 30.270 ;
        RECT 27.930 -6.970 29.110 -5.790 ;
        RECT 27.930 -8.570 29.110 -7.390 ;
        RECT 57.270 46.590 60.050 49.370 ;
        RECT 57.270 29.090 58.450 30.270 ;
        RECT 58.870 29.090 60.050 30.270 ;
        RECT 57.270 -8.570 60.050 -5.790 ;
      LAYER met5 ;
        RECT -10.620 45.880 60.760 50.080 ;
        RECT -10.620 28.880 60.760 30.480 ;
        RECT -10.620 -9.280 60.760 -5.080 ;
    END
  END VGND
  PIN a[0]
    ANTENNAGATEAREA 1.863000 ;
    PORT
      LAYER li1 ;
        RECT 39.145 23.155 39.485 23.405 ;
        RECT 43.265 23.155 43.615 23.405 ;
        RECT 19.270 22.015 19.745 22.355 ;
        RECT 29.195 20.115 30.700 20.325 ;
        RECT 20.065 18.020 20.615 18.405 ;
        RECT 24.850 17.765 25.545 17.965 ;
        RECT 42.875 17.715 43.210 17.985 ;
      LAYER mcon ;
        RECT 39.245 23.205 39.415 23.375 ;
        RECT 43.385 23.205 43.555 23.375 ;
        RECT 19.465 22.185 19.635 22.355 ;
        RECT 30.505 20.145 30.675 20.315 ;
        RECT 20.385 18.105 20.555 18.275 ;
        RECT 24.985 17.765 25.155 17.935 ;
        RECT 42.925 17.765 43.095 17.935 ;
      LAYER met1 ;
        RECT 39.260 23.560 43.540 23.700 ;
        RECT 39.260 23.405 39.400 23.560 ;
        RECT 43.400 23.405 43.540 23.560 ;
        RECT 39.185 23.175 39.475 23.405 ;
        RECT 43.325 23.360 43.615 23.405 ;
        RECT 43.770 23.360 44.090 23.420 ;
        RECT 43.325 23.220 44.090 23.360 ;
        RECT 43.325 23.175 43.615 23.220 ;
        RECT 43.770 23.160 44.090 23.220 ;
        RECT 19.405 22.340 19.695 22.385 ;
        RECT 19.850 22.340 20.170 22.400 ;
        RECT 19.405 22.200 20.170 22.340 ;
        RECT 19.405 22.155 19.695 22.200 ;
        RECT 19.850 22.140 20.170 22.200 ;
        RECT 30.445 20.115 30.735 20.345 ;
        RECT 24.910 19.960 25.230 20.020 ;
        RECT 30.520 19.960 30.660 20.115 ;
        RECT 43.770 19.960 44.090 20.020 ;
        RECT 24.910 19.820 44.090 19.960 ;
        RECT 24.910 19.760 25.230 19.820 ;
        RECT 43.770 19.760 44.090 19.820 ;
        RECT 19.850 18.260 20.170 18.320 ;
        RECT 20.325 18.260 20.615 18.305 ;
        RECT 19.850 18.120 25.140 18.260 ;
        RECT 19.850 18.060 20.170 18.120 ;
        RECT 20.325 18.075 20.615 18.120 ;
        RECT 25.000 17.980 25.140 18.120 ;
        RECT 24.910 17.920 25.230 17.980 ;
        RECT 24.715 17.780 25.230 17.920 ;
        RECT 24.910 17.720 25.230 17.780 ;
        RECT 42.865 17.920 43.155 17.965 ;
        RECT 43.310 17.920 43.630 17.980 ;
        RECT 42.865 17.780 43.630 17.920 ;
        RECT 42.865 17.735 43.155 17.780 ;
        RECT 43.310 17.720 43.630 17.780 ;
      LAYER via ;
        RECT 43.800 23.160 44.060 23.420 ;
        RECT 19.880 22.140 20.140 22.400 ;
        RECT 24.940 19.760 25.200 20.020 ;
        RECT 43.800 19.760 44.060 20.020 ;
        RECT 19.880 18.060 20.140 18.320 ;
        RECT 24.940 17.720 25.200 17.980 ;
        RECT 43.340 17.720 43.600 17.980 ;
      LAYER met2 ;
        RECT 43.800 23.130 44.060 23.450 ;
        RECT 19.880 22.110 20.140 22.430 ;
        RECT 19.940 18.350 20.080 22.110 ;
        RECT 43.860 20.050 44.000 23.130 ;
        RECT 24.940 19.730 25.200 20.050 ;
        RECT 43.800 19.730 44.060 20.050 ;
        RECT 19.880 18.030 20.140 18.350 ;
        RECT 25.000 18.010 25.140 19.730 ;
        RECT 43.860 18.090 44.000 19.730 ;
        RECT 43.400 18.010 44.000 18.090 ;
        RECT 24.940 17.690 25.200 18.010 ;
        RECT 43.340 17.950 44.000 18.010 ;
        RECT 43.340 17.690 43.600 17.950 ;
        RECT 43.400 0.000 43.540 17.690 ;
    END
  END a[0]
  PIN a[2]
    ANTENNAGATEAREA 1.153500 ;
    PORT
      LAYER li1 ;
        RECT 30.485 30.665 30.735 31.245 ;
        RECT 14.175 28.580 14.575 28.820 ;
        RECT 33.185 28.595 33.470 28.925 ;
        RECT 14.405 28.275 14.575 28.580 ;
        RECT 12.900 25.925 13.195 26.095 ;
        RECT 12.900 25.475 13.190 25.925 ;
        RECT 17.565 22.525 17.905 23.405 ;
        RECT 32.090 20.115 32.575 20.325 ;
      LAYER mcon ;
        RECT 30.505 30.685 30.675 30.855 ;
        RECT 33.265 28.645 33.435 28.815 ;
        RECT 14.405 28.305 14.575 28.475 ;
        RECT 13.025 25.925 13.195 26.095 ;
        RECT 17.625 23.205 17.795 23.375 ;
        RECT 32.345 20.145 32.515 20.315 ;
      LAYER met1 ;
        RECT 30.445 30.840 30.735 30.885 ;
        RECT 33.190 30.840 33.510 30.900 ;
        RECT 30.445 30.700 33.510 30.840 ;
        RECT 30.445 30.655 30.735 30.700 ;
        RECT 17.550 30.500 17.870 30.560 ;
        RECT 30.520 30.500 30.660 30.655 ;
        RECT 33.190 30.640 33.510 30.700 ;
        RECT 17.550 30.360 30.660 30.500 ;
        RECT 17.550 30.300 17.870 30.360 ;
        RECT 33.190 28.800 33.510 28.860 ;
        RECT 32.995 28.660 33.510 28.800 ;
        RECT 33.190 28.600 33.510 28.660 ;
        RECT 14.345 28.460 14.635 28.505 ;
        RECT 17.550 28.460 17.870 28.520 ;
        RECT 14.345 28.320 17.870 28.460 ;
        RECT 14.345 28.275 14.635 28.320 ;
        RECT 17.550 28.260 17.870 28.320 ;
        RECT 12.965 26.080 13.255 26.125 ;
        RECT 17.550 26.080 17.870 26.140 ;
        RECT 12.965 25.940 17.870 26.080 ;
        RECT 12.965 25.895 13.255 25.940 ;
        RECT 17.550 25.880 17.870 25.940 ;
        RECT 17.550 23.360 17.870 23.420 ;
        RECT 17.355 23.220 17.870 23.360 ;
        RECT 17.550 23.160 17.870 23.220 ;
        RECT 32.285 20.300 32.575 20.345 ;
        RECT 33.190 20.300 33.510 20.360 ;
        RECT 32.285 20.160 33.510 20.300 ;
        RECT 32.285 20.115 32.575 20.160 ;
        RECT 33.190 20.100 33.510 20.160 ;
      LAYER via ;
        RECT 17.580 30.300 17.840 30.560 ;
        RECT 33.220 30.640 33.480 30.900 ;
        RECT 33.220 28.600 33.480 28.860 ;
        RECT 17.580 28.260 17.840 28.520 ;
        RECT 17.580 25.880 17.840 26.140 ;
        RECT 17.580 23.160 17.840 23.420 ;
        RECT 33.220 20.100 33.480 20.360 ;
      LAYER met2 ;
        RECT 33.280 30.930 33.420 40.000 ;
        RECT 33.220 30.610 33.480 30.930 ;
        RECT 17.580 30.270 17.840 30.590 ;
        RECT 17.640 28.550 17.780 30.270 ;
        RECT 33.280 28.890 33.420 30.610 ;
        RECT 33.220 28.570 33.480 28.890 ;
        RECT 17.580 28.230 17.840 28.550 ;
        RECT 17.640 26.170 17.780 28.230 ;
        RECT 17.580 25.850 17.840 26.170 ;
        RECT 17.640 23.450 17.780 25.850 ;
        RECT 17.580 23.130 17.840 23.450 ;
        RECT 33.280 20.390 33.420 28.570 ;
        RECT 33.220 20.070 33.480 20.390 ;
    END
  END a[2]
  PIN a[3]
    ANTENNAGATEAREA 1.396500 ;
    PORT
      LAYER li1 ;
        RECT 28.605 30.575 28.865 31.585 ;
        RECT 31.365 28.255 31.605 28.925 ;
        RECT 7.905 23.155 8.255 23.405 ;
        RECT 24.345 17.595 24.590 18.045 ;
        RECT 25.715 17.795 26.315 17.965 ;
        RECT 25.715 17.595 25.885 17.795 ;
        RECT 24.345 17.425 25.885 17.595 ;
        RECT 17.590 14.955 17.805 15.285 ;
      LAYER mcon ;
        RECT 28.665 30.685 28.835 30.855 ;
        RECT 31.425 28.305 31.595 28.475 ;
        RECT 7.965 23.205 8.135 23.375 ;
        RECT 25.445 17.425 25.615 17.595 ;
        RECT 17.625 15.045 17.795 15.215 ;
      LAYER met1 ;
        RECT 28.605 30.840 28.895 30.885 ;
        RECT 29.510 30.840 29.830 30.900 ;
        RECT 28.605 30.700 29.830 30.840 ;
        RECT 28.605 30.655 28.895 30.700 ;
        RECT 29.510 30.640 29.830 30.700 ;
        RECT 29.510 28.460 29.830 28.520 ;
        RECT 31.365 28.460 31.655 28.505 ;
        RECT 29.510 28.320 31.655 28.460 ;
        RECT 29.510 28.260 29.830 28.320 ;
        RECT 31.365 28.275 31.655 28.320 ;
        RECT 7.890 23.360 8.210 23.420 ;
        RECT 7.695 23.220 8.210 23.360 ;
        RECT 7.890 23.160 8.210 23.220 ;
        RECT 25.385 17.580 25.675 17.625 ;
        RECT 25.830 17.580 26.150 17.640 ;
        RECT 29.510 17.580 29.830 17.640 ;
        RECT 25.385 17.440 29.830 17.580 ;
        RECT 25.385 17.395 25.675 17.440 ;
        RECT 7.890 17.240 8.210 17.300 ;
        RECT 17.550 17.240 17.870 17.300 ;
        RECT 25.460 17.240 25.600 17.395 ;
        RECT 25.830 17.380 26.150 17.440 ;
        RECT 29.510 17.380 29.830 17.440 ;
        RECT 7.890 17.100 25.600 17.240 ;
        RECT 7.890 17.040 8.210 17.100 ;
        RECT 17.550 17.040 17.870 17.100 ;
        RECT 17.550 15.200 17.870 15.260 ;
        RECT 17.355 15.060 17.870 15.200 ;
        RECT 17.550 15.000 17.870 15.060 ;
      LAYER via ;
        RECT 29.540 30.640 29.800 30.900 ;
        RECT 29.540 28.260 29.800 28.520 ;
        RECT 7.920 23.160 8.180 23.420 ;
        RECT 7.920 17.040 8.180 17.300 ;
        RECT 17.580 17.040 17.840 17.300 ;
        RECT 25.860 17.380 26.120 17.640 ;
        RECT 29.540 17.380 29.800 17.640 ;
        RECT 17.580 15.000 17.840 15.260 ;
      LAYER met2 ;
        RECT 29.540 30.610 29.800 30.930 ;
        RECT 29.600 28.550 29.740 30.610 ;
        RECT 29.540 28.230 29.800 28.550 ;
        RECT 7.920 23.130 8.180 23.450 ;
        RECT 7.980 17.330 8.120 23.130 ;
        RECT 29.600 17.670 29.740 28.230 ;
        RECT 25.860 17.350 26.120 17.670 ;
        RECT 29.540 17.350 29.800 17.670 ;
        RECT 7.920 17.010 8.180 17.330 ;
        RECT 17.580 17.010 17.840 17.330 ;
        RECT 17.640 15.290 17.780 17.010 ;
        RECT 17.580 14.970 17.840 15.290 ;
        RECT 25.920 0.000 26.060 17.350 ;
    END
  END a[3]
  PIN a[4]
    ANTENNAGATEAREA 1.149000 ;
    PORT
      LAYER li1 ;
        RECT 29.125 31.165 29.365 32.370 ;
        RECT 29.125 30.995 29.575 31.165 ;
        RECT 32.230 29.095 32.580 29.620 ;
        RECT 14.765 28.305 15.095 28.965 ;
        RECT 32.230 28.925 32.435 29.095 ;
        RECT 32.125 28.595 32.435 28.925 ;
        RECT 35.505 28.255 35.775 29.265 ;
        RECT 6.760 25.555 7.090 25.795 ;
      LAYER mcon ;
        RECT 29.125 31.025 29.295 31.195 ;
        RECT 32.345 29.325 32.515 29.495 ;
        RECT 14.865 28.645 15.035 28.815 ;
        RECT 35.565 28.985 35.735 29.155 ;
        RECT 6.920 25.585 7.090 25.755 ;
      LAYER met1 ;
        RECT 29.065 31.180 29.355 31.225 ;
        RECT 29.970 31.180 30.290 31.240 ;
        RECT 20.860 31.040 30.290 31.180 ;
        RECT 12.950 30.840 13.270 30.900 ;
        RECT 20.860 30.840 21.000 31.040 ;
        RECT 29.065 30.995 29.355 31.040 ;
        RECT 29.970 30.980 30.290 31.040 ;
        RECT 12.950 30.700 21.000 30.840 ;
        RECT 12.950 30.640 13.270 30.700 ;
        RECT 29.970 29.480 30.290 29.540 ;
        RECT 32.285 29.480 32.575 29.525 ;
        RECT 29.970 29.340 35.720 29.480 ;
        RECT 29.970 29.280 30.290 29.340 ;
        RECT 32.285 29.295 32.575 29.340 ;
        RECT 6.970 29.140 7.290 29.200 ;
        RECT 12.950 29.140 13.270 29.200 ;
        RECT 35.580 29.185 35.720 29.340 ;
        RECT 6.970 29.000 13.270 29.140 ;
        RECT 6.970 28.940 7.290 29.000 ;
        RECT 12.950 28.940 13.270 29.000 ;
        RECT 35.505 28.955 35.795 29.185 ;
        RECT 13.040 28.800 13.180 28.940 ;
        RECT 14.805 28.800 15.095 28.845 ;
        RECT 13.040 28.660 15.095 28.800 ;
        RECT 14.805 28.615 15.095 28.660 ;
        RECT 6.970 25.785 7.290 25.800 ;
        RECT 6.860 25.555 7.290 25.785 ;
        RECT 6.970 25.540 7.290 25.555 ;
      LAYER via ;
        RECT 12.980 30.640 13.240 30.900 ;
        RECT 30.000 30.980 30.260 31.240 ;
        RECT 30.000 29.280 30.260 29.540 ;
        RECT 7.000 28.940 7.260 29.200 ;
        RECT 12.980 28.940 13.240 29.200 ;
        RECT 7.000 25.540 7.260 25.800 ;
      LAYER met2 ;
        RECT 6.600 29.140 6.740 40.000 ;
        RECT 30.000 30.950 30.260 31.270 ;
        RECT 12.980 30.610 13.240 30.930 ;
        RECT 13.040 29.230 13.180 30.610 ;
        RECT 30.060 29.570 30.200 30.950 ;
        RECT 30.000 29.250 30.260 29.570 ;
        RECT 7.000 29.140 7.260 29.230 ;
        RECT 6.600 29.000 7.260 29.140 ;
        RECT 6.600 25.740 6.740 29.000 ;
        RECT 7.000 28.910 7.260 29.000 ;
        RECT 12.980 28.910 13.240 29.230 ;
        RECT 7.000 25.740 7.260 25.830 ;
        RECT 6.600 25.600 7.260 25.740 ;
        RECT 7.000 25.510 7.260 25.600 ;
    END
  END a[4]
  PIN a[5]
    ANTENNAGATEAREA 1.351500 ;
    PORT
      LAYER li1 ;
        RECT 29.535 31.535 29.790 32.370 ;
        RECT 29.535 31.335 29.975 31.535 ;
        RECT 29.745 30.915 29.975 31.335 ;
        RECT 32.770 28.925 32.985 29.620 ;
        RECT 17.960 28.595 18.295 28.845 ;
        RECT 32.605 28.595 32.985 28.925 ;
        RECT 13.450 28.235 13.665 28.565 ;
        RECT 13.015 22.815 13.255 23.485 ;
        RECT 24.965 22.825 25.210 23.185 ;
      LAYER mcon ;
        RECT 29.585 31.365 29.755 31.535 ;
        RECT 32.805 28.985 32.975 29.155 ;
        RECT 18.085 28.645 18.255 28.815 ;
        RECT 13.485 28.305 13.655 28.475 ;
        RECT 13.025 23.205 13.195 23.375 ;
        RECT 24.985 22.865 25.155 23.035 ;
      LAYER met1 ;
        RECT 24.450 31.520 24.770 31.580 ;
        RECT 29.525 31.520 29.815 31.565 ;
        RECT 24.450 31.380 29.815 31.520 ;
        RECT 24.450 31.320 24.770 31.380 ;
        RECT 29.525 31.335 29.815 31.380 ;
        RECT 13.410 29.140 13.730 29.200 ;
        RECT 24.910 29.140 25.230 29.200 ;
        RECT 32.745 29.140 33.035 29.185 ;
        RECT 13.410 29.000 18.240 29.140 ;
        RECT 13.410 28.940 13.730 29.000 ;
        RECT 18.100 28.845 18.240 29.000 ;
        RECT 24.910 29.000 33.035 29.140 ;
        RECT 24.910 28.940 25.230 29.000 ;
        RECT 32.745 28.955 33.035 29.000 ;
        RECT 18.025 28.615 18.315 28.845 ;
        RECT 13.410 28.460 13.730 28.520 ;
        RECT 13.215 28.320 13.730 28.460 ;
        RECT 18.100 28.460 18.240 28.615 ;
        RECT 23.990 28.460 24.310 28.520 ;
        RECT 18.100 28.320 24.310 28.460 ;
        RECT 13.410 28.260 13.730 28.320 ;
        RECT 23.990 28.260 24.310 28.320 ;
        RECT 12.965 23.360 13.255 23.405 ;
        RECT 13.410 23.360 13.730 23.420 ;
        RECT 12.965 23.220 13.730 23.360 ;
        RECT 12.965 23.175 13.255 23.220 ;
        RECT 13.410 23.160 13.730 23.220 ;
        RECT 24.910 23.020 25.230 23.080 ;
        RECT 24.910 22.880 25.425 23.020 ;
        RECT 24.910 22.820 25.230 22.880 ;
      LAYER via ;
        RECT 24.480 31.320 24.740 31.580 ;
        RECT 13.440 28.940 13.700 29.200 ;
        RECT 24.940 28.940 25.200 29.200 ;
        RECT 13.440 28.260 13.700 28.520 ;
        RECT 24.020 28.260 24.280 28.520 ;
        RECT 13.440 23.160 13.700 23.420 ;
        RECT 24.940 22.820 25.200 23.080 ;
      LAYER met2 ;
        RECT 24.080 31.520 24.220 40.000 ;
        RECT 24.480 31.520 24.740 31.610 ;
        RECT 24.080 31.380 24.740 31.520 ;
        RECT 24.480 31.290 24.740 31.380 ;
        RECT 13.440 28.910 13.700 29.230 ;
        RECT 24.540 29.140 24.680 31.290 ;
        RECT 24.940 29.140 25.200 29.230 ;
        RECT 24.540 29.000 25.200 29.140 ;
        RECT 13.500 28.550 13.640 28.910 ;
        RECT 13.440 28.230 13.700 28.550 ;
        RECT 24.020 28.460 24.280 28.550 ;
        RECT 24.540 28.460 24.680 29.000 ;
        RECT 24.940 28.910 25.200 29.000 ;
        RECT 24.020 28.320 24.680 28.460 ;
        RECT 24.020 28.230 24.280 28.320 ;
        RECT 13.500 23.450 13.640 28.230 ;
        RECT 24.540 23.530 24.680 28.320 ;
        RECT 13.440 23.130 13.700 23.450 ;
        RECT 24.540 23.390 25.140 23.530 ;
        RECT 25.000 23.110 25.140 23.390 ;
        RECT 24.940 22.790 25.200 23.110 ;
    END
  END a[5]
  PIN s[0]
    ANTENNADIFFAREA 0.474000 ;
    PORT
      LAYER li1 ;
        RECT 9.855 12.955 10.025 13.345 ;
        RECT 9.855 12.775 10.095 12.955 ;
        RECT 9.925 12.145 10.095 12.775 ;
        RECT 9.925 11.975 10.535 12.145 ;
        RECT 10.210 11.135 10.535 11.975 ;
      LAYER mcon ;
        RECT 10.265 11.645 10.435 11.815 ;
      LAYER met1 ;
        RECT 0.070 11.800 0.390 11.860 ;
        RECT 10.205 11.800 10.495 11.845 ;
        RECT 0.070 11.660 10.495 11.800 ;
        RECT 0.070 11.600 0.390 11.660 ;
        RECT 10.205 11.615 10.495 11.660 ;
      LAYER via ;
        RECT 0.100 11.600 0.360 11.860 ;
      LAYER met2 ;
        RECT 0.100 11.570 0.360 11.890 ;
        RECT 0.160 0.000 0.300 11.570 ;
    END
  END s[0]
  PIN s[10]
    ANTENNADIFFAREA 0.429000 ;
    PORT
      LAYER li1 ;
        RECT 40.740 34.475 41.070 35.105 ;
        RECT 40.840 33.875 41.070 34.475 ;
        RECT 40.740 32.895 41.070 33.875 ;
      LAYER mcon ;
        RECT 40.855 34.765 41.025 34.935 ;
      LAYER met1 ;
        RECT 40.795 34.920 41.085 34.965 ;
        RECT 49.290 34.920 49.610 34.980 ;
        RECT 40.795 34.780 49.610 34.920 ;
        RECT 40.795 34.735 41.085 34.780 ;
        RECT 49.290 34.720 49.610 34.780 ;
      LAYER via ;
        RECT 49.320 34.720 49.580 34.980 ;
      LAYER met2 ;
        RECT 49.840 35.090 49.980 40.000 ;
        RECT 49.380 35.010 49.980 35.090 ;
        RECT 49.320 34.950 49.980 35.010 ;
        RECT 49.320 34.690 49.580 34.950 ;
    END
  END s[10]
  PIN s[11]
    ANTENNAGATEAREA 0.247500 ;
    ANTENNADIFFAREA 0.447000 ;
    PORT
      LAYER li1 ;
        RECT 40.340 34.045 40.670 34.285 ;
        RECT 38.730 31.605 39.005 32.375 ;
        RECT 38.420 31.415 39.005 31.605 ;
        RECT 38.420 30.745 38.595 31.415 ;
        RECT 38.265 30.565 38.595 30.745 ;
        RECT 38.265 30.185 38.490 30.565 ;
      LAYER mcon ;
        RECT 40.340 34.085 40.510 34.255 ;
        RECT 38.785 31.705 38.955 31.875 ;
      LAYER met1 ;
        RECT 38.710 34.240 39.030 34.300 ;
        RECT 40.280 34.240 40.570 34.285 ;
        RECT 38.710 34.100 40.570 34.240 ;
        RECT 38.710 34.040 39.030 34.100 ;
        RECT 40.280 34.055 40.570 34.100 ;
        RECT 34.570 31.860 34.890 31.920 ;
        RECT 38.710 31.860 39.030 31.920 ;
        RECT 34.570 31.720 39.030 31.860 ;
        RECT 34.570 31.660 34.890 31.720 ;
        RECT 38.710 31.660 39.030 31.720 ;
      LAYER via ;
        RECT 38.740 34.040 39.000 34.300 ;
        RECT 34.600 31.660 34.860 31.920 ;
        RECT 38.740 31.660 39.000 31.920 ;
      LAYER met2 ;
        RECT 38.740 34.010 39.000 34.330 ;
        RECT 38.800 31.950 38.940 34.010 ;
        RECT 34.600 31.630 34.860 31.950 ;
        RECT 38.740 31.630 39.000 31.950 ;
        RECT 34.660 20.130 34.800 31.630 ;
        RECT 34.200 19.990 34.800 20.130 ;
        RECT 34.200 0.000 34.340 19.990 ;
    END
  END s[11]
  PIN s[1]
    ANTENNAGATEAREA 0.126000 ;
    ANTENNADIFFAREA 0.517000 ;
    PORT
      LAYER li1 ;
        RECT 11.155 28.965 11.325 29.530 ;
        RECT 10.805 28.795 11.325 28.965 ;
        RECT 10.805 28.415 10.975 28.795 ;
        RECT 10.625 28.135 10.975 28.415 ;
        RECT 10.625 27.455 10.955 28.135 ;
        RECT 8.825 12.255 9.275 12.605 ;
        RECT 8.825 11.155 9.095 12.255 ;
      LAYER mcon ;
        RECT 10.725 27.625 10.895 27.795 ;
        RECT 8.885 12.325 9.055 12.495 ;
      LAYER met1 ;
        RECT 10.650 27.780 10.970 27.840 ;
        RECT 10.455 27.640 10.970 27.780 ;
        RECT 10.650 27.580 10.970 27.640 ;
        RECT 10.650 12.820 10.970 12.880 ;
        RECT 8.900 12.680 10.970 12.820 ;
        RECT 8.350 12.480 8.670 12.540 ;
        RECT 8.900 12.525 9.040 12.680 ;
        RECT 10.650 12.620 10.970 12.680 ;
        RECT 8.825 12.480 9.115 12.525 ;
        RECT 8.350 12.340 9.115 12.480 ;
        RECT 8.350 12.280 8.670 12.340 ;
        RECT 8.825 12.295 9.115 12.340 ;
      LAYER via ;
        RECT 10.680 27.580 10.940 27.840 ;
        RECT 8.380 12.280 8.640 12.540 ;
        RECT 10.680 12.620 10.940 12.880 ;
      LAYER met2 ;
        RECT 10.680 27.550 10.940 27.870 ;
        RECT 10.740 12.910 10.880 27.550 ;
        RECT 10.680 12.590 10.940 12.910 ;
        RECT 8.380 12.250 8.640 12.570 ;
        RECT 8.440 0.000 8.580 12.250 ;
    END
  END s[1]
  PIN s[5]
    ANTENNADIFFAREA 0.439000 ;
    PORT
      LAYER li1 ;
        RECT 23.515 15.085 23.845 16.065 ;
        RECT 23.610 14.485 23.780 15.085 ;
        RECT 23.085 13.855 23.780 14.485 ;
      LAYER mcon ;
        RECT 23.605 15.725 23.775 15.895 ;
      LAYER met1 ;
        RECT 23.545 15.880 23.835 15.925 ;
        RECT 44.690 15.880 45.010 15.940 ;
        RECT 23.545 15.740 45.010 15.880 ;
        RECT 23.545 15.695 23.835 15.740 ;
        RECT 44.690 15.680 45.010 15.740 ;
      LAYER via ;
        RECT 44.720 15.680 44.980 15.940 ;
      LAYER met2 ;
        RECT 41.560 39.170 41.700 40.000 ;
        RECT 42.020 39.710 44.920 39.850 ;
        RECT 42.020 39.170 42.160 39.710 ;
        RECT 41.560 39.030 42.160 39.170 ;
        RECT 44.780 15.970 44.920 39.710 ;
        RECT 44.720 15.650 44.980 15.970 ;
    END
  END s[5]
  PIN s[6]
    ANTENNAGATEAREA 0.285000 ;
    ANTENNADIFFAREA 0.439000 ;
    PORT
      LAYER li1 ;
        RECT 26.735 15.085 27.065 16.065 ;
        RECT 26.830 14.485 27.000 15.085 ;
        RECT 26.305 13.855 27.000 14.485 ;
        RECT 25.215 12.260 25.615 12.500 ;
        RECT 25.445 11.955 25.615 12.260 ;
        RECT 21.265 11.185 22.455 11.475 ;
      LAYER mcon ;
        RECT 26.365 14.025 26.535 14.195 ;
        RECT 25.445 11.985 25.615 12.155 ;
        RECT 21.305 11.305 21.475 11.475 ;
      LAYER met1 ;
        RECT 25.370 14.180 25.690 14.240 ;
        RECT 26.305 14.180 26.595 14.225 ;
        RECT 25.370 14.040 26.595 14.180 ;
        RECT 25.370 13.980 25.690 14.040 ;
        RECT 26.305 13.995 26.595 14.040 ;
        RECT 25.370 12.140 25.690 12.200 ;
        RECT 25.175 12.000 25.690 12.140 ;
        RECT 25.370 11.940 25.690 12.000 ;
        RECT 16.630 11.460 16.950 11.520 ;
        RECT 21.245 11.460 21.535 11.505 ;
        RECT 25.370 11.460 25.690 11.520 ;
        RECT 16.630 11.320 25.690 11.460 ;
        RECT 16.630 11.260 16.950 11.320 ;
        RECT 21.245 11.275 21.535 11.320 ;
        RECT 25.370 11.260 25.690 11.320 ;
      LAYER via ;
        RECT 25.400 13.980 25.660 14.240 ;
        RECT 25.400 11.940 25.660 12.200 ;
        RECT 16.660 11.260 16.920 11.520 ;
        RECT 25.400 11.260 25.660 11.520 ;
      LAYER met2 ;
        RECT 25.400 13.950 25.660 14.270 ;
        RECT 25.460 12.230 25.600 13.950 ;
        RECT 25.400 11.910 25.660 12.230 ;
        RECT 25.460 11.550 25.600 11.910 ;
        RECT 16.660 11.230 16.920 11.550 ;
        RECT 25.400 11.230 25.660 11.550 ;
        RECT 16.720 0.000 16.860 11.230 ;
    END
  END s[6]
  PIN s[8]
    ANTENNAGATEAREA 0.654000 ;
    ANTENNADIFFAREA 0.445500 ;
    PORT
      LAYER li1 ;
        RECT 17.115 28.595 17.450 28.865 ;
        RECT 12.365 25.475 12.730 26.095 ;
        RECT 12.560 25.415 12.730 25.475 ;
        RECT 18.005 25.965 18.335 26.945 ;
        RECT 12.560 25.245 12.735 25.415 ;
        RECT 18.005 25.365 18.255 25.965 ;
        RECT 12.560 24.905 12.730 25.245 ;
        RECT 18.005 24.735 18.335 25.365 ;
        RECT 18.905 14.555 19.235 15.215 ;
      LAYER mcon ;
        RECT 17.165 28.645 17.335 28.815 ;
        RECT 18.085 26.605 18.255 26.775 ;
        RECT 12.565 25.245 12.735 25.415 ;
        RECT 19.005 14.705 19.175 14.875 ;
      LAYER met1 ;
        RECT 16.170 28.800 16.490 28.860 ;
        RECT 17.105 28.800 17.395 28.845 ;
        RECT 16.170 28.660 17.395 28.800 ;
        RECT 16.170 28.600 16.490 28.660 ;
        RECT 17.105 28.615 17.395 28.660 ;
        RECT 16.170 26.760 16.490 26.820 ;
        RECT 18.025 26.760 18.315 26.805 ;
        RECT 16.170 26.620 18.315 26.760 ;
        RECT 16.170 26.560 16.490 26.620 ;
        RECT 18.025 26.575 18.315 26.620 ;
        RECT 12.505 25.400 12.795 25.445 ;
        RECT 16.170 25.400 16.490 25.460 ;
        RECT 12.505 25.260 16.490 25.400 ;
        RECT 12.505 25.215 12.795 25.260 ;
        RECT 16.170 25.200 16.490 25.260 ;
        RECT 16.170 14.860 16.490 14.920 ;
        RECT 18.945 14.860 19.235 14.905 ;
        RECT 16.170 14.720 19.235 14.860 ;
        RECT 16.170 14.660 16.490 14.720 ;
        RECT 18.945 14.675 19.235 14.720 ;
      LAYER via ;
        RECT 16.200 28.600 16.460 28.860 ;
        RECT 16.200 26.560 16.460 26.820 ;
        RECT 16.200 25.200 16.460 25.460 ;
        RECT 16.200 14.660 16.460 14.920 ;
      LAYER met2 ;
        RECT 15.800 39.170 15.940 40.000 ;
        RECT 15.800 39.030 16.400 39.170 ;
        RECT 16.260 28.890 16.400 39.030 ;
        RECT 16.200 28.570 16.460 28.890 ;
        RECT 16.260 26.850 16.400 28.570 ;
        RECT 16.200 26.530 16.460 26.850 ;
        RECT 16.260 25.490 16.400 26.530 ;
        RECT 16.200 25.170 16.460 25.490 ;
        RECT 16.260 14.950 16.400 25.170 ;
        RECT 16.200 14.630 16.460 14.950 ;
    END
  END s[8]
  PIN a[1]
    ANTENNAGATEAREA 1.489500 ;
    PORT
      LAYER li1 ;
        RECT 19.465 23.755 19.665 24.175 ;
        RECT 19.465 23.235 19.875 23.755 ;
        RECT 39.705 23.155 40.380 23.405 ;
        RECT 42.405 23.155 42.755 23.405 ;
        RECT 40.115 22.795 40.380 23.155 ;
        RECT 28.170 20.115 29.025 20.325 ;
        RECT 16.145 17.765 16.475 17.965 ;
        RECT 16.245 17.425 16.475 17.765 ;
        RECT 43.720 17.715 44.055 17.965 ;
      LAYER mcon ;
        RECT 19.465 23.545 19.635 23.715 ;
        RECT 42.465 23.205 42.635 23.375 ;
        RECT 40.165 22.865 40.335 23.035 ;
        RECT 28.665 20.145 28.835 20.315 ;
        RECT 16.245 17.765 16.415 17.935 ;
        RECT 43.845 17.765 44.015 17.935 ;
      LAYER met1 ;
        RECT 19.405 23.515 19.695 23.745 ;
        RECT 18.010 22.680 18.330 22.740 ;
        RECT 19.480 22.680 19.620 23.515 ;
        RECT 42.405 23.175 42.695 23.405 ;
        RECT 28.590 23.020 28.910 23.080 ;
        RECT 40.105 23.020 40.395 23.065 ;
        RECT 42.480 23.020 42.620 23.175 ;
        RECT 44.230 23.020 44.550 23.080 ;
        RECT 28.590 22.880 44.550 23.020 ;
        RECT 28.590 22.820 28.910 22.880 ;
        RECT 40.105 22.835 40.395 22.880 ;
        RECT 44.230 22.820 44.550 22.880 ;
        RECT 28.680 22.680 28.820 22.820 ;
        RECT 18.010 22.540 28.820 22.680 ;
        RECT 18.010 22.480 18.330 22.540 ;
        RECT 28.590 20.300 28.910 20.360 ;
        RECT 28.395 20.160 28.910 20.300 ;
        RECT 28.590 20.100 28.910 20.160 ;
        RECT 16.185 17.920 16.475 17.965 ;
        RECT 18.010 17.920 18.330 17.980 ;
        RECT 16.185 17.780 18.330 17.920 ;
        RECT 16.185 17.735 16.475 17.780 ;
        RECT 18.010 17.720 18.330 17.780 ;
        RECT 43.785 17.920 44.075 17.965 ;
        RECT 44.230 17.920 44.550 17.980 ;
        RECT 43.785 17.780 44.550 17.920 ;
        RECT 43.785 17.735 44.075 17.780 ;
        RECT 44.230 17.720 44.550 17.780 ;
      LAYER via ;
        RECT 18.040 22.480 18.300 22.740 ;
        RECT 28.620 22.820 28.880 23.080 ;
        RECT 44.260 22.820 44.520 23.080 ;
        RECT 28.620 20.100 28.880 20.360 ;
        RECT 18.040 17.720 18.300 17.980 ;
        RECT 44.260 17.720 44.520 17.980 ;
      LAYER met2 ;
        RECT 44.250 27.355 44.530 27.725 ;
        RECT 44.320 23.110 44.460 27.355 ;
        RECT 28.620 22.790 28.880 23.110 ;
        RECT 44.260 22.790 44.520 23.110 ;
        RECT 18.040 22.450 18.300 22.770 ;
        RECT 18.100 18.010 18.240 22.450 ;
        RECT 28.680 20.390 28.820 22.790 ;
        RECT 28.620 20.070 28.880 20.390 ;
        RECT 44.320 18.010 44.460 22.790 ;
        RECT 18.040 17.690 18.300 18.010 ;
        RECT 44.260 17.690 44.520 18.010 ;
      LAYER via2 ;
        RECT 44.250 27.400 44.530 27.680 ;
      LAYER met3 ;
        RECT 44.225 27.690 44.555 27.705 ;
        RECT 44.225 27.390 50.000 27.690 ;
        RECT 44.225 27.375 44.555 27.390 ;
    END
  END a[1]
  PIN s[2]
    ANTENNADIFFAREA 0.429000 ;
    PORT
      LAYER li1 ;
        RECT 5.390 12.715 5.720 13.345 ;
        RECT 5.390 12.115 5.620 12.715 ;
        RECT 5.390 11.135 5.720 12.115 ;
      LAYER mcon ;
        RECT 5.435 12.665 5.605 12.835 ;
      LAYER met1 ;
        RECT 2.830 12.820 3.150 12.880 ;
        RECT 5.375 12.820 5.665 12.865 ;
        RECT 2.830 12.680 5.665 12.820 ;
        RECT 2.830 12.620 3.150 12.680 ;
        RECT 5.375 12.635 5.665 12.680 ;
      LAYER via ;
        RECT 2.860 12.620 3.120 12.880 ;
      LAYER met2 ;
        RECT 2.860 12.765 3.120 12.910 ;
        RECT 2.850 12.395 3.130 12.765 ;
      LAYER via2 ;
        RECT 2.850 12.440 3.130 12.720 ;
      LAYER met3 ;
        RECT 2.825 12.730 3.155 12.745 ;
        RECT 0.000 12.430 3.155 12.730 ;
        RECT 2.825 12.415 3.155 12.430 ;
    END
  END s[2]
  PIN s[3]
    ANTENNADIFFAREA 0.480500 ;
    PORT
      LAYER li1 ;
        RECT 10.250 15.055 10.500 15.725 ;
        RECT 10.250 14.195 10.440 15.055 ;
      LAYER mcon ;
        RECT 10.265 15.385 10.435 15.555 ;
      LAYER met1 ;
        RECT 10.205 15.540 10.495 15.585 ;
        RECT 27.670 15.540 27.990 15.600 ;
        RECT 10.205 15.400 27.990 15.540 ;
        RECT 10.205 15.355 10.495 15.400 ;
        RECT 27.670 15.340 27.990 15.400 ;
      LAYER via ;
        RECT 27.700 15.340 27.960 15.600 ;
      LAYER met2 ;
        RECT 27.700 15.485 27.960 15.630 ;
        RECT 27.690 15.115 27.970 15.485 ;
      LAYER via2 ;
        RECT 27.690 15.160 27.970 15.440 ;
      LAYER met3 ;
        RECT 27.665 15.450 27.995 15.465 ;
        RECT 27.665 15.150 50.000 15.450 ;
        RECT 27.665 15.135 27.995 15.150 ;
    END
  END s[3]
  PIN s[4]
    ANTENNAGATEAREA 1.027500 ;
    ANTENNADIFFAREA 1.443500 ;
    PORT
      LAYER li1 ;
        RECT 30.915 26.395 32.085 26.565 ;
        RECT 10.270 25.755 10.640 26.095 ;
        RECT 10.265 25.585 10.640 25.755 ;
        RECT 10.270 25.475 10.640 25.585 ;
        RECT 31.885 25.285 32.085 26.395 ;
        RECT 28.815 25.115 32.425 25.285 ;
        RECT 31.415 24.735 31.585 25.115 ;
        RECT 32.255 24.735 32.425 25.115 ;
        RECT 11.150 23.155 11.435 23.485 ;
        RECT 15.505 17.945 15.835 17.965 ;
        RECT 15.505 17.765 15.955 17.945 ;
        RECT 15.740 16.650 15.955 17.765 ;
        RECT 22.110 12.275 22.455 12.605 ;
        RECT 24.490 11.915 24.705 12.245 ;
      LAYER mcon ;
        RECT 31.885 25.245 32.055 25.415 ;
        RECT 11.185 23.205 11.355 23.375 ;
        RECT 15.785 17.425 15.955 17.595 ;
        RECT 22.225 12.325 22.395 12.495 ;
        RECT 24.525 11.985 24.695 12.155 ;
      LAYER met1 ;
        RECT 10.190 25.740 10.510 25.800 ;
        RECT 9.995 25.600 10.510 25.740 ;
        RECT 10.190 25.540 10.510 25.600 ;
        RECT 31.825 25.215 32.115 25.445 ;
        RECT 16.630 25.060 16.950 25.120 ;
        RECT 31.900 25.060 32.040 25.215 ;
        RECT 16.630 24.920 32.040 25.060 ;
        RECT 16.630 24.860 16.950 24.920 ;
        RECT 10.190 23.360 10.510 23.420 ;
        RECT 11.125 23.360 11.415 23.405 ;
        RECT 10.190 23.220 11.415 23.360 ;
        RECT 10.190 23.160 10.510 23.220 ;
        RECT 11.125 23.175 11.415 23.220 ;
        RECT 11.200 23.020 11.340 23.175 ;
        RECT 16.630 23.020 16.950 23.080 ;
        RECT 11.200 22.880 16.950 23.020 ;
        RECT 16.630 22.820 16.950 22.880 ;
        RECT 15.725 17.580 16.015 17.625 ;
        RECT 16.630 17.580 16.950 17.640 ;
        RECT 21.230 17.580 21.550 17.640 ;
        RECT 15.725 17.440 21.550 17.580 ;
        RECT 15.725 17.395 16.015 17.440 ;
        RECT 16.630 17.380 16.950 17.440 ;
        RECT 21.230 17.380 21.550 17.440 ;
        RECT 21.230 12.480 21.550 12.540 ;
        RECT 22.165 12.480 22.455 12.525 ;
        RECT 21.230 12.340 24.680 12.480 ;
        RECT 21.230 12.280 21.550 12.340 ;
        RECT 22.165 12.295 22.455 12.340 ;
        RECT 24.540 12.185 24.680 12.340 ;
        RECT 24.465 11.955 24.755 12.185 ;
      LAYER via ;
        RECT 10.220 25.540 10.480 25.800 ;
        RECT 16.660 24.860 16.920 25.120 ;
        RECT 10.220 23.160 10.480 23.420 ;
        RECT 16.660 22.820 16.920 23.080 ;
        RECT 16.660 17.380 16.920 17.640 ;
        RECT 21.260 17.380 21.520 17.640 ;
        RECT 21.260 12.280 21.520 12.540 ;
      LAYER met2 ;
        RECT 10.220 25.510 10.480 25.830 ;
        RECT 10.280 25.005 10.420 25.510 ;
        RECT 10.210 24.635 10.490 25.005 ;
        RECT 16.660 24.830 16.920 25.150 ;
        RECT 10.280 23.450 10.420 24.635 ;
        RECT 10.220 23.130 10.480 23.450 ;
        RECT 16.720 23.110 16.860 24.830 ;
        RECT 16.660 22.790 16.920 23.110 ;
        RECT 16.720 17.670 16.860 22.790 ;
        RECT 16.660 17.350 16.920 17.670 ;
        RECT 21.260 17.350 21.520 17.670 ;
        RECT 21.320 12.570 21.460 17.350 ;
        RECT 21.260 12.250 21.520 12.570 ;
      LAYER via2 ;
        RECT 10.210 24.680 10.490 24.960 ;
      LAYER met3 ;
        RECT 10.185 24.970 10.515 24.985 ;
        RECT 0.000 24.670 10.515 24.970 ;
        RECT 10.185 24.655 10.515 24.670 ;
    END
  END s[4]
  PIN s[7]
    ANTENNADIFFAREA 0.290500 ;
    PORT
      LAYER li1 ;
        RECT 19.400 31.600 19.735 32.385 ;
        RECT 19.355 31.430 19.735 31.600 ;
        RECT 19.355 31.045 19.525 31.430 ;
        RECT 18.960 30.875 19.525 31.045 ;
        RECT 18.960 30.200 19.245 30.875 ;
      LAYER mcon ;
        RECT 19.465 32.045 19.635 32.215 ;
      LAYER met1 ;
        RECT 19.390 32.200 19.710 32.260 ;
        RECT 19.195 32.060 19.710 32.200 ;
        RECT 19.390 32.000 19.710 32.060 ;
      LAYER via ;
        RECT 19.420 32.000 19.680 32.260 ;
      LAYER met2 ;
        RECT 19.410 36.875 19.690 37.245 ;
        RECT 19.480 32.290 19.620 36.875 ;
        RECT 19.420 31.970 19.680 32.290 ;
      LAYER via2 ;
        RECT 19.410 36.920 19.690 37.200 ;
      LAYER met3 ;
        RECT 0.000 38.270 13.490 38.570 ;
        RECT 13.190 37.210 13.490 38.270 ;
        RECT 19.385 37.210 19.715 37.225 ;
        RECT 13.190 36.910 19.715 37.210 ;
        RECT 19.385 36.895 19.715 36.910 ;
    END
  END s[7]
  PIN s[9]
    ANTENNADIFFAREA 0.429000 ;
    PORT
      LAYER li1 ;
        RECT 44.420 7.275 44.750 7.905 ;
        RECT 44.520 6.675 44.750 7.275 ;
        RECT 44.420 5.695 44.750 6.675 ;
      LAYER mcon ;
        RECT 44.535 5.865 44.705 6.035 ;
      LAYER met1 ;
        RECT 44.475 6.020 44.765 6.065 ;
        RECT 46.990 6.020 47.310 6.080 ;
        RECT 44.475 5.880 47.310 6.020 ;
        RECT 44.475 5.835 44.765 5.880 ;
        RECT 46.990 5.820 47.310 5.880 ;
      LAYER via ;
        RECT 47.020 5.820 47.280 6.080 ;
      LAYER met2 ;
        RECT 47.020 5.790 47.280 6.110 ;
        RECT 47.080 1.885 47.220 5.790 ;
        RECT 47.010 1.515 47.290 1.885 ;
      LAYER via2 ;
        RECT 47.010 1.560 47.290 1.840 ;
      LAYER met3 ;
        RECT 46.985 1.850 47.315 1.865 ;
        RECT 46.985 1.550 50.000 1.850 ;
        RECT 46.985 1.535 47.315 1.550 ;
    END
  END s[9]
  OBS
      LAYER pwell ;
        RECT 1.385 35.465 3.215 36.275 ;
        RECT 1.525 35.255 1.695 35.465 ;
        RECT 1.385 34.445 3.215 35.255 ;
        RECT 3.350 35.240 3.570 35.480 ;
        RECT 7.030 35.240 7.250 35.480 ;
        RECT 10.710 35.240 10.930 35.480 ;
        RECT 14.390 35.310 14.610 35.480 ;
        RECT 15.770 35.240 15.990 35.410 ;
        RECT 18.070 35.310 18.290 35.480 ;
        RECT 19.450 35.240 19.670 35.410 ;
        RECT 21.750 35.310 21.970 35.480 ;
        RECT 23.130 35.240 23.350 35.410 ;
        RECT 25.430 35.310 25.650 35.480 ;
        RECT 26.855 35.300 26.965 35.420 ;
        RECT 28.660 35.305 28.780 35.415 ;
        RECT 29.570 35.240 29.790 35.480 ;
        RECT 33.250 35.240 33.470 35.480 ;
        RECT 36.975 35.410 37.085 35.420 ;
        RECT 36.930 35.240 37.150 35.410 ;
        RECT 38.795 35.300 38.955 35.410 ;
        RECT 39.700 35.305 39.820 35.415 ;
        RECT 40.165 35.275 40.335 35.445 ;
        RECT 40.655 35.300 40.765 35.420 ;
        RECT 41.530 35.310 41.750 35.480 ;
        RECT 46.925 35.465 48.755 36.275 ;
        RECT 42.460 35.305 42.580 35.415 ;
        RECT 40.230 35.255 40.335 35.275 ;
        RECT 40.230 34.345 41.160 35.255 ;
        RECT 43.370 35.240 43.590 35.410 ;
        RECT 45.255 35.300 45.365 35.420 ;
        RECT 48.445 35.255 48.615 35.465 ;
        RECT 46.925 34.445 48.755 35.255 ;
        RECT 1.385 30.025 3.215 30.835 ;
        RECT 1.525 29.815 1.695 30.025 ;
        RECT 1.385 29.005 3.215 29.815 ;
        RECT 3.350 29.800 3.570 30.040 ;
        RECT 18.870 30.025 20.670 30.705 ;
        RECT 28.525 30.025 30.815 30.935 ;
        RECT 37.265 30.025 39.080 30.935 ;
        RECT 46.925 30.025 48.755 30.835 ;
        RECT 7.075 29.970 7.185 29.980 ;
        RECT 7.030 29.800 7.250 29.970 ;
        RECT 8.895 29.860 9.055 29.970 ;
        RECT 9.810 29.815 9.980 30.005 ;
        RECT 10.710 29.815 10.930 29.970 ;
        RECT 11.675 29.860 11.785 29.980 ;
        RECT 14.415 29.870 14.575 29.980 ;
        RECT 14.865 29.815 15.035 30.005 ;
        RECT 15.355 29.860 15.465 29.980 ;
        RECT 15.815 29.860 15.925 29.980 ;
        RECT 17.160 29.815 17.330 30.005 ;
        RECT 17.635 29.870 17.795 29.980 ;
        RECT 18.575 29.975 18.685 29.980 ;
        RECT 18.540 29.865 18.685 29.975 ;
        RECT 18.575 29.860 18.685 29.865 ;
        RECT 20.385 29.835 20.555 30.025 ;
        RECT 20.830 29.815 21.050 29.970 ;
        RECT 22.220 29.815 22.390 30.005 ;
        RECT 22.715 29.860 22.825 29.980 ;
        RECT 24.525 29.970 24.695 30.005 ;
        RECT 24.510 29.815 24.730 29.970 ;
        RECT 26.395 29.860 26.505 29.980 ;
        RECT 28.200 29.970 28.320 29.975 ;
        RECT 28.200 29.865 28.375 29.970 ;
        RECT 28.215 29.860 28.375 29.865 ;
        RECT 29.615 29.860 29.725 29.980 ;
        RECT 30.505 29.835 30.675 30.025 ;
        RECT 9.665 28.905 11.495 29.815 ;
        RECT 13.350 29.135 15.150 29.815 ;
        RECT 17.045 28.905 18.395 29.815 ;
        RECT 20.260 29.135 22.535 29.815 ;
        RECT 24.410 29.135 26.210 29.815 ;
        RECT 30.950 29.800 31.170 29.970 ;
        RECT 33.260 29.815 33.430 30.005 ;
        RECT 33.755 29.860 33.865 29.980 ;
        RECT 34.675 29.860 34.785 29.980 ;
        RECT 36.495 29.870 36.655 29.980 ;
        RECT 36.940 29.815 37.110 30.005 ;
        RECT 37.435 29.860 37.545 29.980 ;
        RECT 38.785 29.835 38.955 30.025 ;
        RECT 39.245 29.970 39.415 30.005 ;
        RECT 39.230 29.815 39.450 29.970 ;
        RECT 41.115 29.860 41.225 29.980 ;
        RECT 43.370 29.815 43.590 29.970 ;
        RECT 43.850 29.815 44.020 30.005 ;
        RECT 44.335 29.860 44.445 29.980 ;
        RECT 46.155 29.860 46.315 29.970 ;
        RECT 48.445 29.815 48.615 30.025 ;
        RECT 20.260 28.905 21.630 29.135 ;
        RECT 31.285 28.905 33.575 29.815 ;
        RECT 35.485 28.905 37.255 29.815 ;
        RECT 39.120 28.905 40.935 29.815 ;
        RECT 42.785 28.905 44.135 29.815 ;
        RECT 46.925 29.005 48.755 29.815 ;
        RECT 1.385 24.585 3.215 25.395 ;
        RECT 1.525 24.375 1.695 24.585 ;
        RECT 3.350 24.430 3.570 24.600 ;
        RECT 6.650 24.585 7.580 25.495 ;
        RECT 10.125 24.585 13.335 25.495 ;
        RECT 6.650 24.565 6.755 24.585 ;
        RECT 5.215 24.430 5.375 24.540 ;
        RECT 3.395 24.420 3.505 24.430 ;
        RECT 6.120 24.425 6.240 24.535 ;
        RECT 6.585 24.395 6.755 24.565 ;
        RECT 7.055 24.420 7.215 24.530 ;
        RECT 7.995 24.420 8.105 24.540 ;
        RECT 8.880 24.375 9.050 24.565 ;
        RECT 9.375 24.420 9.485 24.540 ;
        RECT 9.800 24.425 9.920 24.535 ;
        RECT 10.265 24.395 10.435 24.585 ;
        RECT 11.190 24.375 11.360 24.565 ;
        RECT 13.470 24.430 13.690 24.600 ;
        RECT 17.495 24.585 18.845 25.495 ;
        RECT 20.705 24.585 22.995 25.495 ;
        RECT 24.845 24.585 32.655 25.495 ;
        RECT 13.515 24.420 13.625 24.430 ;
        RECT 15.815 24.420 15.925 24.540 ;
        RECT 17.160 24.425 17.280 24.535 ;
        RECT 1.385 23.565 3.215 24.375 ;
        RECT 7.845 23.465 9.195 24.375 ;
        RECT 11.045 23.465 13.335 24.375 ;
        RECT 17.630 24.345 17.800 24.565 ;
        RECT 18.545 24.395 18.715 24.585 ;
        RECT 19.035 24.420 19.145 24.540 ;
        RECT 20.875 24.420 20.985 24.540 ;
        RECT 22.680 24.530 22.850 24.585 ;
        RECT 22.680 24.420 22.855 24.530 ;
        RECT 23.175 24.420 23.285 24.540 ;
        RECT 22.680 24.395 22.850 24.420 ;
        RECT 23.610 24.375 23.780 24.565 ;
        RECT 24.990 24.395 25.160 24.585 ;
        RECT 25.430 24.430 25.650 24.585 ;
        RECT 29.570 24.430 29.790 24.585 ;
        RECT 32.835 24.420 32.945 24.540 ;
        RECT 33.250 24.430 33.470 24.600 ;
        RECT 35.425 24.585 40.735 25.495 ;
        RECT 46.925 24.585 48.755 25.395 ;
        RECT 34.655 24.430 34.815 24.540 ;
        RECT 35.565 24.395 35.735 24.585 ;
        RECT 36.955 24.420 37.115 24.530 ;
        RECT 37.860 24.425 37.980 24.535 ;
        RECT 40.165 24.395 40.335 24.565 ;
        RECT 40.655 24.420 40.765 24.540 ;
        RECT 41.115 24.420 41.225 24.540 ;
        RECT 43.380 24.530 43.550 24.565 ;
        RECT 40.165 24.375 40.315 24.395 ;
        RECT 43.370 24.375 43.590 24.530 ;
        RECT 43.875 24.420 43.985 24.540 ;
        RECT 45.695 24.420 45.855 24.530 ;
        RECT 46.600 24.425 46.720 24.535 ;
        RECT 48.445 24.375 48.615 24.585 ;
        RECT 19.760 24.345 20.695 24.375 ;
        RECT 17.630 24.145 20.695 24.345 ;
        RECT 17.485 23.665 20.695 24.145 ;
        RECT 17.485 23.465 18.415 23.665 ;
        RECT 19.745 23.465 20.695 23.665 ;
        RECT 23.465 23.465 25.295 24.375 ;
        RECT 38.385 23.555 40.315 24.375 ;
        RECT 38.385 23.465 39.335 23.555 ;
        RECT 42.345 23.465 43.695 24.375 ;
        RECT 46.925 23.565 48.755 24.375 ;
        RECT 1.385 19.145 3.215 19.955 ;
        RECT 1.525 18.935 1.695 19.145 ;
        RECT 1.385 18.125 3.215 18.935 ;
        RECT 3.350 18.920 3.570 19.160 ;
        RECT 9.690 19.145 11.490 19.825 ;
        RECT 18.885 19.145 20.235 20.055 ;
        RECT 22.180 19.145 26.215 20.055 ;
        RECT 28.065 19.375 32.655 20.055 ;
        RECT 28.065 19.145 31.695 19.375 ;
        RECT 7.075 19.090 7.185 19.100 ;
        RECT 7.055 18.980 7.215 19.090 ;
        RECT 7.960 18.985 8.080 19.095 ;
        RECT 8.430 18.935 8.600 19.125 ;
        RECT 8.895 18.990 9.055 19.100 ;
        RECT 9.805 18.955 9.975 19.145 ;
        RECT 11.630 18.935 11.850 19.090 ;
        RECT 12.135 18.980 12.245 19.100 ;
        RECT 13.945 18.935 14.115 19.125 ;
        RECT 15.815 18.980 15.925 19.100 ;
        RECT 16.735 18.980 16.845 19.100 ;
        RECT 17.635 18.990 17.795 19.100 ;
        RECT 18.540 18.985 18.660 19.095 ;
        RECT 19.920 18.955 20.090 19.145 ;
        RECT 20.385 18.935 20.555 19.125 ;
        RECT 20.875 18.980 20.985 19.100 ;
        RECT 22.695 18.980 22.855 19.090 ;
        RECT 23.600 18.985 23.720 19.095 ;
        RECT 24.065 18.935 24.235 19.125 ;
        RECT 25.900 18.955 26.070 19.145 ;
        RECT 26.395 18.980 26.505 19.100 ;
        RECT 27.315 18.980 27.425 19.100 ;
        RECT 28.210 18.955 28.380 19.145 ;
        RECT 29.570 18.990 29.790 19.145 ;
        RECT 8.285 18.920 11.850 18.935 ;
        RECT 8.285 18.025 11.760 18.920 ;
        RECT 13.805 18.025 16.555 18.935 ;
        RECT 18.405 18.255 20.695 18.935 ;
        RECT 18.405 18.025 19.325 18.255 ;
        RECT 24.025 18.025 27.135 18.935 ;
        RECT 32.790 18.920 33.010 19.090 ;
        RECT 33.250 18.990 33.470 19.160 ;
        RECT 36.515 18.980 36.625 19.100 ;
        RECT 36.930 18.990 37.150 19.160 ;
        RECT 39.565 19.145 40.915 20.055 ;
        RECT 46.925 19.145 48.755 19.955 ;
        RECT 38.335 18.990 38.495 19.100 ;
        RECT 39.240 18.985 39.360 19.095 ;
        RECT 39.710 18.955 39.880 19.145 ;
        RECT 40.655 18.980 40.765 19.100 ;
        RECT 41.115 18.980 41.225 19.100 ;
        RECT 42.460 18.985 42.580 19.095 ;
        RECT 42.920 18.935 43.090 19.125 ;
        RECT 43.370 18.935 43.590 19.090 ;
        RECT 44.335 18.980 44.445 19.100 ;
        RECT 46.155 18.980 46.315 19.090 ;
        RECT 48.445 18.935 48.615 19.145 ;
        RECT 42.805 18.025 44.155 18.935 ;
        RECT 46.925 18.125 48.755 18.935 ;
        RECT 1.385 13.705 3.215 14.515 ;
        RECT 9.665 13.705 13.335 14.615 ;
        RECT 1.525 13.495 1.695 13.705 ;
        RECT 3.395 13.650 3.505 13.660 ;
        RECT 1.385 12.685 3.215 13.495 ;
        RECT 3.350 13.480 3.570 13.650 ;
        RECT 6.125 13.515 6.295 13.685 ;
        RECT 6.615 13.540 6.725 13.660 ;
        RECT 7.075 13.540 7.185 13.660 ;
        RECT 8.420 13.545 8.540 13.655 ;
        RECT 6.125 13.495 6.230 13.515 ;
        RECT 5.300 12.585 6.230 13.495 ;
        RECT 8.885 13.495 9.055 13.685 ;
        RECT 9.805 13.515 9.975 13.705 ;
        RECT 11.630 13.550 11.850 13.705 ;
        RECT 13.515 13.540 13.625 13.660 ;
        RECT 15.310 13.550 15.530 13.720 ;
        RECT 17.490 13.705 19.290 14.385 ;
        RECT 23.005 13.705 24.355 14.615 ;
        RECT 26.225 13.705 27.575 14.615 ;
        RECT 15.815 13.540 15.925 13.660 ;
        RECT 19.005 13.515 19.175 13.705 ;
        RECT 8.885 13.265 11.495 13.495 ;
        RECT 19.450 13.480 19.670 13.650 ;
        RECT 19.920 13.545 20.040 13.655 ;
        RECT 8.745 12.585 11.495 13.265 ;
        RECT 20.245 13.465 21.200 13.495 ;
        RECT 22.230 13.465 22.400 13.685 ;
        RECT 22.715 13.540 22.825 13.660 ;
        RECT 24.070 13.515 24.240 13.705 ;
        RECT 24.555 13.540 24.665 13.660 ;
        RECT 25.905 13.495 26.075 13.685 ;
        RECT 26.395 13.540 26.505 13.660 ;
        RECT 27.290 13.515 27.460 13.705 ;
        RECT 20.245 12.785 22.525 13.465 ;
        RECT 24.390 12.815 26.190 13.495 ;
        RECT 27.730 13.480 27.950 13.650 ;
        RECT 28.215 13.540 28.375 13.650 ;
        RECT 29.570 13.550 29.790 13.720 ;
        RECT 31.410 13.480 31.630 13.650 ;
        RECT 33.250 13.550 33.470 13.720 ;
        RECT 35.090 13.480 35.310 13.650 ;
        RECT 36.930 13.550 37.150 13.720 ;
        RECT 38.770 13.480 38.990 13.650 ;
        RECT 40.610 13.550 40.830 13.720 ;
        RECT 46.925 13.705 48.755 14.515 ;
        RECT 42.460 13.545 42.580 13.655 ;
        RECT 43.370 13.480 43.590 13.650 ;
        RECT 44.335 13.540 44.445 13.660 ;
        RECT 46.155 13.540 46.315 13.650 ;
        RECT 48.445 13.495 48.615 13.705 ;
        RECT 20.245 12.585 21.200 12.785 ;
        RECT 46.925 12.685 48.755 13.495 ;
        RECT 1.385 8.265 3.215 9.075 ;
        RECT 1.525 8.055 1.695 8.265 ;
        RECT 1.385 7.245 3.215 8.055 ;
        RECT 3.350 8.040 3.570 8.280 ;
        RECT 7.030 8.040 7.250 8.280 ;
        RECT 10.710 8.040 10.930 8.280 ;
        RECT 14.390 8.110 14.610 8.280 ;
        RECT 15.770 8.040 15.990 8.210 ;
        RECT 18.070 8.110 18.290 8.280 ;
        RECT 19.450 8.040 19.670 8.210 ;
        RECT 21.750 8.110 21.970 8.280 ;
        RECT 23.130 8.040 23.350 8.210 ;
        RECT 25.430 8.110 25.650 8.280 ;
        RECT 26.810 8.040 27.030 8.210 ;
        RECT 29.570 8.110 29.790 8.280 ;
        RECT 30.490 8.040 30.710 8.210 ;
        RECT 33.250 8.110 33.470 8.280 ;
        RECT 34.170 8.040 34.390 8.210 ;
        RECT 36.930 8.110 37.150 8.280 ;
        RECT 46.925 8.265 48.755 9.075 ;
        RECT 37.850 8.040 38.070 8.210 ;
        RECT 40.655 8.100 40.765 8.220 ;
        RECT 41.555 8.110 41.715 8.220 ;
        RECT 42.460 8.210 42.580 8.215 ;
        RECT 43.380 8.210 43.500 8.215 ;
        RECT 42.460 8.105 42.635 8.210 ;
        RECT 42.475 8.100 42.635 8.105 ;
        RECT 43.370 8.040 43.590 8.210 ;
        RECT 43.845 8.075 44.015 8.245 ;
        RECT 45.255 8.100 45.365 8.220 ;
        RECT 43.910 8.055 44.015 8.075 ;
        RECT 48.445 8.055 48.615 8.265 ;
        RECT 43.910 7.145 44.840 8.055 ;
        RECT 46.925 7.245 48.755 8.055 ;
        RECT 1.385 2.825 3.215 3.635 ;
        RECT 46.925 2.825 48.755 3.635 ;
        RECT 1.525 2.635 1.695 2.825 ;
        RECT 3.350 2.600 3.570 2.770 ;
        RECT 7.030 2.600 7.250 2.770 ;
        RECT 10.710 2.600 10.930 2.770 ;
        RECT 14.415 2.670 14.575 2.780 ;
        RECT 15.770 2.600 15.990 2.770 ;
        RECT 19.450 2.600 19.670 2.770 ;
        RECT 23.130 2.600 23.350 2.770 ;
        RECT 26.855 2.660 26.965 2.780 ;
        RECT 28.660 2.665 28.780 2.775 ;
        RECT 29.570 2.600 29.790 2.770 ;
        RECT 33.250 2.600 33.470 2.770 ;
        RECT 36.930 2.600 37.150 2.770 ;
        RECT 40.655 2.660 40.765 2.780 ;
        RECT 42.460 2.665 42.580 2.775 ;
        RECT 43.370 2.600 43.590 2.770 ;
        RECT 48.445 2.635 48.615 2.825 ;
      LAYER li1 ;
        RECT 18.970 31.275 19.185 31.605 ;
        RECT 30.395 31.585 30.730 32.370 ;
        RECT 19.925 31.260 20.095 31.565 ;
        RECT 19.695 31.020 20.095 31.260 ;
        RECT 20.285 30.875 20.615 31.535 ;
        RECT 30.145 31.415 30.730 31.585 ;
        RECT 37.355 31.945 37.685 32.375 ;
        RECT 38.230 31.945 38.560 32.375 ;
        RECT 37.355 31.775 38.560 31.945 ;
        RECT 37.355 31.445 38.250 31.775 ;
        RECT 30.145 30.745 30.315 31.415 ;
        RECT 37.360 30.915 37.655 31.245 ;
        RECT 37.835 30.915 38.250 31.245 ;
        RECT 19.415 30.535 20.580 30.705 ;
        RECT 19.415 30.200 19.650 30.535 ;
        RECT 20.320 30.200 20.580 30.535 ;
        RECT 29.115 30.575 30.315 30.745 ;
        RECT 29.115 30.305 29.285 30.575 ;
        RECT 29.960 30.565 30.315 30.575 ;
        RECT 29.960 30.305 30.225 30.565 ;
        RECT 37.835 30.295 38.065 30.915 ;
        RECT 38.765 30.595 39.005 31.245 ;
        RECT 9.750 29.305 10.040 29.655 ;
        RECT 10.735 29.305 10.965 29.610 ;
        RECT 9.750 29.135 10.965 29.305 ;
        RECT 13.440 28.965 13.725 29.640 ;
        RECT 13.895 29.305 14.130 29.640 ;
        RECT 14.800 29.305 15.060 29.640 ;
        RECT 13.895 29.135 15.060 29.305 ;
        RECT 17.620 29.035 18.315 29.665 ;
        RECT 20.850 29.265 21.020 29.535 ;
        RECT 21.735 29.325 22.025 29.665 ;
        RECT 20.325 29.095 21.020 29.265 ;
        RECT 9.810 28.815 10.070 28.925 ;
        RECT 9.805 28.645 10.070 28.815 ;
        RECT 9.810 28.595 10.070 28.645 ;
        RECT 10.250 28.595 10.635 28.925 ;
        RECT 13.440 28.795 14.005 28.965 ;
        RECT 10.250 27.545 10.445 28.595 ;
        RECT 11.165 28.265 11.410 28.625 ;
        RECT 13.835 28.410 14.005 28.795 ;
        RECT 17.620 28.435 17.790 29.035 ;
        RECT 13.835 28.240 14.215 28.410 ;
        RECT 13.880 27.455 14.215 28.240 ;
        RECT 17.555 27.455 17.885 28.435 ;
        RECT 20.325 28.085 20.755 29.095 ;
        RECT 20.925 28.425 21.095 28.925 ;
        RECT 21.265 28.595 21.675 29.155 ;
        RECT 21.845 28.425 22.025 29.325 ;
        RECT 24.500 29.305 24.760 29.640 ;
        RECT 25.430 29.305 25.665 29.640 ;
        RECT 22.195 28.815 22.390 29.155 ;
        RECT 24.500 29.135 25.665 29.305 ;
        RECT 25.835 28.965 26.120 29.640 ;
        RECT 31.365 29.095 32.060 29.665 ;
        RECT 36.075 29.265 36.245 29.535 ;
        RECT 36.915 29.265 37.170 29.535 ;
        RECT 39.710 29.275 39.935 29.655 ;
        RECT 35.945 29.095 37.170 29.265 ;
        RECT 22.195 28.645 22.395 28.815 ;
        RECT 22.195 28.595 22.390 28.645 ;
        RECT 20.925 28.255 22.385 28.425 ;
        RECT 24.465 28.305 24.795 28.965 ;
        RECT 24.985 28.580 25.385 28.820 ;
        RECT 25.555 28.795 26.120 28.965 ;
        RECT 24.985 28.275 25.155 28.580 ;
        RECT 25.555 28.410 25.725 28.795 ;
        RECT 20.325 27.915 21.100 28.085 ;
        RECT 22.025 28.080 22.385 28.255 ;
        RECT 25.345 28.240 25.725 28.410 ;
        RECT 20.770 27.455 21.100 27.915 ;
        RECT 25.345 27.455 25.680 28.240 ;
        RECT 25.895 28.235 26.110 28.565 ;
        RECT 31.785 28.425 31.955 29.095 ;
        RECT 35.945 28.425 36.115 29.095 ;
        RECT 36.285 28.595 36.665 28.925 ;
        RECT 36.835 28.595 37.170 28.925 ;
        RECT 39.195 28.595 39.435 29.245 ;
        RECT 39.605 29.095 39.935 29.275 ;
        RECT 31.785 28.255 33.065 28.425 ;
        RECT 35.945 28.255 36.260 28.425 ;
        RECT 31.865 27.455 32.195 28.255 ;
        RECT 32.735 27.455 33.065 28.255 ;
        RECT 36.090 27.795 36.260 28.255 ;
        RECT 36.430 27.915 36.665 28.595 ;
        RECT 39.605 28.425 39.780 29.095 ;
        RECT 40.135 28.925 40.365 29.545 ;
        RECT 42.865 29.035 43.560 29.665 ;
        RECT 39.950 28.595 40.365 28.925 ;
        RECT 40.545 28.595 40.840 28.925 ;
        RECT 42.885 28.595 43.220 28.845 ;
        RECT 43.390 28.475 43.560 29.035 ;
        RECT 43.730 28.595 44.065 28.865 ;
        RECT 43.385 28.435 43.560 28.475 ;
        RECT 36.025 27.640 36.260 27.795 ;
        RECT 36.835 27.640 37.170 28.425 ;
        RECT 36.025 27.625 37.170 27.640 ;
        RECT 36.090 27.470 37.170 27.625 ;
        RECT 39.195 28.235 39.780 28.425 ;
        RECT 39.195 27.465 39.470 28.235 ;
        RECT 39.950 28.065 40.845 28.395 ;
        RECT 39.640 27.895 40.845 28.065 ;
        RECT 39.640 27.465 39.970 27.895 ;
        RECT 40.515 27.465 40.845 27.895 ;
        RECT 43.295 27.455 43.625 28.435 ;
        RECT 7.160 25.965 7.490 26.945 ;
        RECT 7.260 25.365 7.490 25.965 ;
        RECT 10.995 26.095 11.325 26.945 ;
        RECT 11.540 26.435 11.905 26.945 ;
        RECT 12.075 26.715 12.405 26.945 ;
        RECT 12.235 26.435 12.405 26.715 ;
        RECT 12.995 26.435 13.250 26.945 ;
        RECT 11.540 26.265 12.065 26.435 ;
        RECT 12.235 26.265 13.250 26.435 ;
        RECT 10.995 25.925 11.700 26.095 ;
        RECT 10.845 25.490 11.360 25.755 ;
        RECT 7.160 24.735 7.490 25.365 ;
        RECT 11.530 25.310 11.700 25.925 ;
        RECT 10.715 25.140 11.700 25.310 ;
        RECT 11.895 25.305 12.065 26.265 ;
        RECT 20.790 26.145 21.125 26.925 ;
        RECT 21.305 26.485 21.530 26.895 ;
        RECT 22.235 26.485 22.410 26.895 ;
        RECT 21.305 26.315 22.410 26.485 ;
        RECT 25.015 26.145 25.185 26.945 ;
        RECT 25.855 26.145 26.025 26.945 ;
        RECT 26.695 26.145 26.865 26.945 ;
        RECT 27.535 26.145 27.705 26.945 ;
        RECT 28.375 26.145 28.545 26.945 ;
        RECT 29.235 26.145 29.405 26.945 ;
        RECT 30.075 26.905 30.245 26.945 ;
        RECT 30.075 26.735 32.505 26.905 ;
        RECT 30.075 26.145 30.245 26.735 ;
        RECT 20.790 25.975 21.375 26.145 ;
        RECT 18.425 25.555 18.755 25.805 ;
        RECT 20.785 25.475 21.035 25.805 ;
        RECT 21.205 25.305 21.375 25.975 ;
        RECT 21.545 26.095 21.930 26.145 ;
        RECT 21.545 25.925 21.935 26.095 ;
        RECT 25.015 25.975 30.245 26.145 ;
        RECT 21.545 25.475 21.730 25.925 ;
        RECT 21.945 25.415 22.390 25.755 ;
        RECT 22.635 25.475 22.915 25.805 ;
        RECT 24.960 25.475 26.575 25.805 ;
        RECT 26.775 25.475 28.390 25.805 ;
        RECT 28.665 25.475 30.260 25.805 ;
        RECT 30.510 25.475 31.695 26.110 ;
        RECT 32.255 25.975 32.505 26.735 ;
        RECT 37.875 26.775 38.885 26.945 ;
        RECT 36.045 26.235 36.215 26.665 ;
        RECT 36.905 26.235 37.155 26.665 ;
        RECT 35.565 26.065 37.155 26.235 ;
        RECT 37.875 26.175 38.045 26.775 ;
        RECT 10.715 24.735 10.885 25.140 ;
        RECT 11.895 24.735 12.325 25.305 ;
        RECT 21.205 25.195 21.620 25.305 ;
        RECT 21.215 24.775 21.620 25.195 ;
        RECT 21.945 25.245 22.395 25.415 ;
        RECT 21.945 24.815 22.390 25.245 ;
        RECT 25.015 25.115 28.625 25.285 ;
        RECT 35.565 25.265 36.050 26.065 ;
        RECT 36.220 25.475 37.625 25.805 ;
        RECT 37.815 25.475 38.125 26.005 ;
        RECT 37.455 25.265 37.625 25.475 ;
        RECT 38.295 25.320 38.465 26.605 ;
        RECT 38.705 26.500 38.885 26.775 ;
        RECT 39.555 26.500 39.725 26.945 ;
        RECT 40.450 26.500 40.780 26.875 ;
        RECT 38.705 26.330 40.780 26.500 ;
        RECT 38.705 25.925 38.885 26.330 ;
        RECT 39.065 25.990 40.355 26.160 ;
        RECT 39.065 25.755 39.240 25.990 ;
        RECT 40.105 25.770 40.355 25.990 ;
        RECT 40.525 25.940 40.780 26.330 ;
        RECT 38.785 25.585 39.240 25.755 ;
        RECT 38.845 25.490 39.240 25.585 ;
        RECT 39.410 25.490 39.935 25.755 ;
        RECT 40.105 25.535 40.520 25.770 ;
        RECT 38.295 25.265 39.785 25.320 ;
        RECT 25.015 24.735 25.185 25.115 ;
        RECT 25.855 24.735 26.025 25.115 ;
        RECT 26.695 24.735 26.865 25.115 ;
        RECT 35.565 25.095 37.155 25.265 ;
        RECT 37.455 25.150 39.785 25.265 ;
        RECT 37.455 25.095 38.465 25.150 ;
        RECT 27.035 24.775 30.405 24.945 ;
        RECT 38.295 24.735 38.465 25.095 ;
        RECT 39.505 24.885 39.785 25.150 ;
        RECT 8.355 23.585 8.685 24.225 ;
        RECT 8.425 22.985 8.595 23.585 ;
        RECT 11.635 23.485 11.850 24.180 ;
        RECT 12.040 23.655 12.390 24.180 ;
        RECT 12.560 23.655 13.255 24.225 ;
        RECT 12.185 23.485 12.390 23.655 ;
        RECT 8.765 23.155 9.115 23.405 ;
        RECT 11.635 23.155 12.015 23.485 ;
        RECT 12.185 23.155 12.495 23.485 ;
        RECT 12.665 22.985 12.835 23.655 ;
        RECT 17.995 23.575 18.325 23.995 ;
        RECT 18.505 23.910 19.295 24.175 ;
        RECT 8.425 22.815 9.105 22.985 ;
        RECT 8.775 22.030 9.105 22.815 ;
        RECT 11.555 22.815 12.835 22.985 ;
        RECT 18.075 23.485 18.325 23.575 ;
        RECT 18.075 23.235 18.870 23.485 ;
        RECT 11.555 22.015 11.885 22.815 ;
        RECT 12.425 22.015 12.755 22.815 ;
        RECT 18.075 22.015 18.245 23.235 ;
        RECT 19.040 23.055 19.295 23.910 ;
        RECT 20.355 23.745 20.615 24.225 ;
        RECT 20.045 23.055 20.275 23.485 ;
        RECT 18.485 22.885 20.275 23.055 ;
        RECT 18.485 22.520 18.735 22.885 ;
        RECT 19.455 22.590 20.170 22.885 ;
        RECT 20.445 22.715 20.615 23.745 ;
        RECT 23.550 23.865 23.840 24.215 ;
        RECT 24.535 23.865 24.765 24.170 ;
        RECT 23.550 23.695 24.765 23.865 ;
        RECT 24.955 24.055 25.125 24.090 ;
        RECT 24.955 23.885 25.155 24.055 ;
        RECT 38.265 23.935 38.825 24.225 ;
        RECT 24.955 23.525 25.125 23.885 ;
        RECT 23.610 23.375 23.870 23.485 ;
        RECT 23.605 23.205 23.870 23.375 ;
        RECT 23.610 23.155 23.870 23.205 ;
        RECT 24.050 23.155 24.435 23.485 ;
        RECT 24.605 23.355 25.125 23.525 ;
        RECT 20.340 22.015 20.615 22.715 ;
        RECT 24.050 22.105 24.245 23.155 ;
        RECT 24.605 22.975 24.775 23.355 ;
        RECT 24.425 22.695 24.775 22.975 ;
        RECT 24.425 22.015 24.755 22.695 ;
        RECT 38.265 22.565 38.515 23.935 ;
        RECT 39.865 23.765 40.195 24.125 ;
        RECT 38.805 23.575 40.195 23.765 ;
        RECT 42.855 23.585 43.185 24.225 ;
        RECT 38.805 23.485 38.975 23.575 ;
        RECT 38.685 23.155 38.975 23.485 ;
        RECT 38.805 22.905 38.975 23.155 ;
        RECT 42.925 22.985 43.095 23.585 ;
        RECT 38.805 22.735 39.745 22.905 ;
        RECT 42.925 22.815 43.605 22.985 ;
        RECT 38.265 22.015 38.725 22.565 ;
        RECT 39.445 22.185 39.745 22.735 ;
        RECT 43.275 22.030 43.605 22.815 ;
        RECT 10.625 20.720 10.960 21.505 ;
        RECT 9.745 19.995 10.075 20.655 ;
        RECT 10.265 20.380 10.435 20.685 ;
        RECT 10.625 20.550 11.005 20.720 ;
        RECT 10.265 20.140 10.665 20.380 ;
        RECT 10.835 20.165 11.005 20.550 ;
        RECT 11.175 20.395 11.390 20.725 ;
        RECT 19.815 20.705 20.145 21.490 ;
        RECT 19.465 20.535 20.145 20.705 ;
        RECT 22.785 20.665 23.035 21.505 ;
        RECT 23.625 20.665 23.875 21.505 ;
        RECT 24.955 21.335 26.135 21.505 ;
        RECT 24.955 20.705 25.220 21.335 ;
        RECT 10.835 19.995 11.400 20.165 ;
        RECT 18.945 20.115 19.295 20.365 ;
        RECT 9.780 19.655 10.945 19.825 ;
        RECT 9.780 19.320 10.040 19.655 ;
        RECT 10.710 19.320 10.945 19.655 ;
        RECT 11.115 19.320 11.400 19.995 ;
        RECT 19.465 19.935 19.635 20.535 ;
        RECT 22.165 20.495 23.875 20.665 ;
        RECT 24.130 20.535 25.220 20.705 ;
        RECT 19.805 20.115 20.155 20.365 ;
        RECT 22.165 19.945 22.455 20.495 ;
        RECT 23.605 20.485 23.775 20.495 ;
        RECT 24.130 20.285 24.350 20.535 ;
        RECT 25.390 20.365 25.625 21.090 ;
        RECT 25.795 20.535 26.135 21.335 ;
        RECT 28.150 20.665 28.465 21.505 ;
        RECT 29.055 20.665 29.305 21.505 ;
        RECT 29.475 21.335 31.540 21.505 ;
        RECT 29.475 20.835 29.725 21.335 ;
        RECT 29.895 20.665 30.145 21.165 ;
        RECT 28.150 20.495 30.145 20.665 ;
        RECT 30.435 20.495 30.705 21.335 ;
        RECT 22.625 20.115 24.350 20.285 ;
        RECT 24.520 20.115 24.995 20.365 ;
        RECT 25.165 20.115 25.625 20.365 ;
        RECT 25.795 20.115 26.135 20.365 ;
        RECT 24.130 19.945 24.350 20.115 ;
        RECT 30.875 19.945 31.125 21.165 ;
        RECT 31.295 20.495 31.540 21.335 ;
        RECT 31.750 20.495 32.105 20.910 ;
        RECT 39.655 20.705 39.985 21.490 ;
        RECT 39.655 20.535 40.335 20.705 ;
        RECT 31.750 20.325 31.920 20.495 ;
        RECT 31.295 20.115 31.920 20.325 ;
        RECT 39.645 20.115 39.995 20.365 ;
        RECT 31.750 19.945 31.920 20.115 ;
        RECT 19.395 19.295 19.725 19.935 ;
        RECT 22.165 19.775 23.915 19.945 ;
        RECT 22.745 19.305 23.075 19.775 ;
        RECT 23.585 19.305 23.915 19.775 ;
        RECT 24.130 19.765 26.135 19.945 ;
        RECT 24.955 19.295 25.285 19.765 ;
        RECT 25.795 19.295 26.135 19.765 ;
        RECT 28.595 19.765 31.165 19.945 ;
        RECT 28.595 19.295 28.925 19.765 ;
        RECT 29.435 19.295 29.765 19.765 ;
        RECT 30.835 19.295 31.165 19.765 ;
        RECT 31.750 19.420 32.105 19.945 ;
        RECT 40.165 19.935 40.335 20.535 ;
        RECT 40.505 20.115 40.855 20.365 ;
        RECT 40.075 19.295 40.405 19.935 ;
        RECT 8.365 18.155 8.705 18.785 ;
        RECT 9.315 18.305 9.645 18.785 ;
        RECT 10.210 18.305 10.540 18.785 ;
        RECT 8.365 17.545 8.540 18.155 ;
        RECT 9.315 18.135 10.540 18.305 ;
        RECT 11.170 18.175 11.670 18.785 ;
        RECT 8.710 17.795 9.405 17.965 ;
        RECT 9.235 17.545 9.405 17.795 ;
        RECT 9.580 17.765 10.000 17.965 ;
        RECT 10.170 17.765 10.500 17.965 ;
        RECT 10.670 17.765 11.000 17.965 ;
        RECT 11.170 17.545 11.340 18.175 ;
        RECT 13.885 18.010 14.225 18.785 ;
        RECT 14.805 18.520 15.165 18.785 ;
        RECT 14.805 18.515 15.160 18.520 ;
        RECT 14.805 18.505 15.155 18.515 ;
        RECT 14.805 18.500 15.150 18.505 ;
        RECT 14.805 18.490 15.145 18.500 ;
        RECT 14.805 18.485 15.140 18.490 ;
        RECT 14.805 18.475 15.130 18.485 ;
        RECT 14.805 18.465 15.120 18.475 ;
        RECT 14.805 18.325 15.105 18.465 ;
        RECT 14.395 18.135 15.105 18.325 ;
        RECT 15.295 18.325 15.625 18.405 ;
        RECT 16.135 18.325 16.475 18.785 ;
        RECT 15.295 18.135 16.475 18.325 ;
        RECT 18.485 18.305 18.745 18.785 ;
        RECT 11.525 17.715 11.875 17.965 ;
        RECT 8.365 16.575 8.705 17.545 ;
        RECT 9.235 17.375 11.670 17.545 ;
        RECT 10.210 16.575 10.540 17.375 ;
        RECT 11.340 16.575 11.670 17.375 ;
        RECT 13.885 16.575 14.165 18.010 ;
        RECT 14.395 17.565 14.680 18.135 ;
        RECT 14.865 17.735 15.335 17.965 ;
        RECT 14.395 17.350 15.545 17.565 ;
        RECT 15.215 16.575 15.545 17.350 ;
        RECT 18.485 17.275 18.655 18.305 ;
        RECT 19.335 18.250 19.555 18.735 ;
        RECT 18.825 17.655 19.055 18.050 ;
        RECT 19.225 17.825 19.555 18.250 ;
        RECT 19.725 18.575 20.615 18.745 ;
        RECT 19.725 17.850 19.895 18.575 ;
        RECT 24.005 18.215 24.470 18.760 ;
        RECT 25.315 18.305 25.645 18.785 ;
        RECT 26.335 18.385 26.565 18.785 ;
        RECT 26.055 18.305 26.565 18.385 ;
        RECT 25.315 18.215 26.565 18.305 ;
        RECT 26.735 18.215 27.055 18.695 ;
        RECT 19.725 17.780 20.615 17.850 ;
        RECT 19.720 17.755 20.615 17.780 ;
        RECT 19.710 17.740 20.615 17.755 ;
        RECT 19.705 17.725 20.615 17.740 ;
        RECT 19.695 17.720 20.615 17.725 ;
        RECT 19.690 17.710 20.615 17.720 ;
        RECT 19.685 17.700 20.615 17.710 ;
        RECT 19.675 17.695 20.615 17.700 ;
        RECT 19.665 17.685 20.615 17.695 ;
        RECT 19.655 17.680 20.615 17.685 ;
        RECT 19.655 17.675 19.990 17.680 ;
        RECT 19.640 17.670 19.990 17.675 ;
        RECT 19.625 17.660 19.990 17.670 ;
        RECT 19.600 17.655 19.990 17.660 ;
        RECT 18.825 17.650 19.990 17.655 ;
        RECT 18.825 17.615 19.960 17.650 ;
        RECT 18.825 17.590 19.925 17.615 ;
        RECT 18.825 17.560 19.895 17.590 ;
        RECT 18.825 17.530 19.875 17.560 ;
        RECT 18.825 17.500 19.855 17.530 ;
        RECT 18.825 17.490 19.785 17.500 ;
        RECT 18.825 17.480 19.760 17.490 ;
        RECT 18.825 17.465 19.740 17.480 ;
        RECT 18.825 17.450 19.720 17.465 ;
        RECT 18.930 17.440 19.715 17.450 ;
        RECT 18.930 17.405 19.700 17.440 ;
        RECT 18.485 16.575 18.760 17.275 ;
        RECT 18.930 17.155 19.685 17.405 ;
        RECT 20.355 17.230 20.615 17.680 ;
        RECT 24.005 17.255 24.175 18.215 ;
        RECT 25.315 18.135 26.225 18.215 ;
        RECT 26.545 17.625 26.715 18.045 ;
        RECT 26.055 17.455 26.715 17.625 ;
        RECT 26.055 17.255 26.225 17.455 ;
        RECT 26.885 17.285 27.055 18.215 ;
        RECT 43.380 18.155 44.075 18.785 ;
        RECT 43.380 17.555 43.550 18.155 ;
        RECT 24.005 17.085 26.225 17.255 ;
        RECT 26.395 17.085 27.055 17.285 ;
        RECT 19.355 16.575 19.835 16.915 ;
        RECT 24.475 16.575 24.805 17.085 ;
        RECT 26.395 16.915 26.565 17.085 ;
        RECT 26.185 16.745 26.565 16.915 ;
        RECT 43.315 16.575 43.645 17.555 ;
        RECT 9.780 15.895 11.235 16.065 ;
        RECT 9.780 15.055 10.080 15.895 ;
        RECT 10.695 15.045 10.895 15.710 ;
        RECT 11.065 15.250 11.235 15.895 ;
        RECT 11.945 15.250 12.275 16.065 ;
        RECT 11.065 15.080 12.275 15.250 ;
        RECT 10.695 14.925 10.865 15.045 ;
        RECT 9.745 14.660 10.080 14.885 ;
        RECT 10.615 14.755 10.865 14.925 ;
        RECT 12.520 14.910 12.745 16.065 ;
        RECT 18.020 15.280 18.355 16.065 ;
        RECT 10.615 14.595 10.785 14.755 ;
        RECT 11.045 14.675 12.745 14.910 ;
        RECT 9.745 14.065 10.005 14.485 ;
        RECT 10.955 14.425 12.280 14.485 ;
        RECT 10.615 14.315 12.280 14.425 ;
        RECT 10.615 14.255 11.180 14.315 ;
        RECT 9.745 14.025 10.100 14.065 ;
        RECT 10.625 14.025 11.465 14.065 ;
        RECT 9.745 13.855 11.465 14.025 ;
        RECT 12.045 13.855 12.280 14.315 ;
        RECT 12.460 14.085 12.745 14.675 ;
        RECT 12.920 14.360 13.255 15.220 ;
        RECT 17.975 15.110 18.355 15.280 ;
        RECT 17.975 14.725 18.145 15.110 ;
        RECT 18.545 14.940 18.715 15.245 ;
        RECT 17.580 14.555 18.145 14.725 ;
        RECT 18.315 14.700 18.715 14.940 ;
        RECT 23.105 14.675 23.440 14.925 ;
        RECT 23.950 14.655 24.285 14.925 ;
        RECT 26.325 14.675 26.660 14.925 ;
        RECT 27.170 14.655 27.505 14.925 ;
        RECT 12.460 13.855 12.825 14.085 ;
        RECT 17.580 13.880 17.865 14.555 ;
        RECT 18.035 14.215 19.200 14.385 ;
        RECT 18.035 13.880 18.270 14.215 ;
        RECT 18.940 13.880 19.200 14.215 ;
        RECT 10.230 13.115 10.560 13.345 ;
        RECT 9.320 12.945 9.510 13.105 ;
        RECT 9.320 12.775 9.630 12.945 ;
        RECT 9.460 12.605 9.630 12.775 ;
        RECT 10.310 12.865 10.480 13.115 ;
        RECT 11.075 12.865 11.405 13.330 ;
        RECT 10.310 12.695 11.405 12.865 ;
        RECT 20.330 12.840 20.605 13.185 ;
        RECT 21.345 12.945 21.515 13.295 ;
        RECT 22.185 12.945 22.440 13.295 ;
        RECT 5.790 12.285 6.120 12.525 ;
        RECT 9.460 12.065 9.755 12.605 ;
        RECT 10.265 12.315 10.765 12.525 ;
        RECT 10.935 12.315 11.415 12.525 ;
        RECT 9.265 11.895 9.755 12.065 ;
        RECT 20.330 12.105 20.500 12.840 ;
        RECT 20.775 12.775 22.440 12.945 ;
        RECT 20.775 12.605 20.945 12.775 ;
        RECT 24.480 12.645 24.765 13.320 ;
        RECT 24.935 12.985 25.170 13.320 ;
        RECT 25.840 12.985 26.100 13.320 ;
        RECT 24.935 12.815 26.100 12.985 ;
        RECT 20.670 12.275 20.945 12.605 ;
        RECT 21.115 12.275 21.940 12.605 ;
        RECT 24.480 12.475 25.045 12.645 ;
        RECT 20.775 12.105 20.945 12.275 ;
        RECT 9.265 11.390 9.540 11.895 ;
        RECT 20.330 11.135 20.605 12.105 ;
        RECT 20.775 11.935 21.435 12.105 ;
        RECT 21.745 11.985 21.940 12.275 ;
        RECT 21.265 11.815 21.435 11.935 ;
        RECT 22.110 11.815 22.435 12.105 ;
        RECT 24.875 12.090 25.045 12.475 ;
        RECT 24.875 11.920 25.255 12.090 ;
        RECT 25.805 11.985 26.135 12.645 ;
        RECT 21.265 11.645 22.435 11.815 ;
        RECT 24.920 11.135 25.255 11.920 ;
        RECT 44.020 6.845 44.350 7.085 ;
      LAYER mcon ;
        RECT 30.505 31.705 30.675 31.875 ;
        RECT 19.005 31.365 19.175 31.535 ;
        RECT 19.925 31.025 20.095 31.195 ;
        RECT 20.385 31.365 20.555 31.535 ;
        RECT 37.405 31.025 37.575 31.195 ;
        RECT 38.785 30.685 38.955 30.855 ;
        RECT 37.865 30.345 38.035 30.515 ;
        RECT 11.185 28.305 11.355 28.475 ;
        RECT 20.385 28.985 20.555 29.155 ;
        RECT 10.265 27.965 10.435 28.135 ;
        RECT 13.945 27.625 14.115 27.795 ;
        RECT 21.305 28.645 21.475 28.815 ;
        RECT 22.225 28.645 22.395 28.815 ;
        RECT 24.525 28.645 24.695 28.815 ;
        RECT 24.985 28.305 25.155 28.475 ;
        RECT 25.905 28.305 26.075 28.475 ;
        RECT 36.945 28.645 37.115 28.815 ;
        RECT 39.245 28.645 39.415 28.815 ;
        RECT 17.625 27.625 17.795 27.795 ;
        RECT 25.445 27.965 25.615 28.135 ;
        RECT 32.805 27.965 32.975 28.135 ;
        RECT 40.165 28.645 40.335 28.815 ;
        RECT 40.625 28.645 40.795 28.815 ;
        RECT 42.925 28.645 43.095 28.815 ;
        RECT 43.845 28.645 44.015 28.815 ;
        RECT 36.485 27.965 36.655 28.135 ;
        RECT 39.245 27.625 39.415 27.795 ;
        RECT 43.385 28.305 43.555 28.475 ;
        RECT 11.645 26.605 11.815 26.775 ;
        RECT 20.845 26.605 21.015 26.775 ;
        RECT 11.185 25.585 11.355 25.755 ;
        RECT 7.275 24.905 7.445 25.075 ;
        RECT 18.545 25.585 18.715 25.755 ;
        RECT 20.845 25.585 21.015 25.755 ;
        RECT 21.765 25.925 21.935 26.095 ;
        RECT 31.425 25.925 31.595 26.095 ;
        RECT 22.685 25.585 22.855 25.755 ;
        RECT 24.985 25.585 25.155 25.755 ;
        RECT 26.825 25.585 26.995 25.755 ;
        RECT 28.665 25.585 28.835 25.755 ;
        RECT 37.865 25.585 38.035 25.755 ;
        RECT 22.225 25.245 22.395 25.415 ;
        RECT 35.565 25.245 35.735 25.415 ;
        RECT 38.785 25.585 38.955 25.755 ;
        RECT 39.705 25.585 39.875 25.755 ;
        RECT 8.425 23.885 8.595 24.055 ;
        RECT 12.105 23.885 12.275 24.055 ;
        RECT 8.885 23.205 9.055 23.375 ;
        RECT 11.645 23.205 11.815 23.375 ;
        RECT 11.645 22.185 11.815 22.355 ;
        RECT 20.385 23.885 20.555 24.055 ;
        RECT 24.985 23.885 25.155 24.055 ;
        RECT 38.325 23.885 38.495 24.055 ;
        RECT 24.065 23.205 24.235 23.375 ;
        RECT 42.925 23.885 43.095 24.055 ;
        RECT 9.805 20.485 9.975 20.655 ;
        RECT 10.265 20.145 10.435 20.315 ;
        RECT 11.185 20.485 11.355 20.655 ;
        RECT 19.005 20.145 19.175 20.315 ;
        RECT 19.925 20.145 20.095 20.315 ;
        RECT 25.445 20.825 25.615 20.995 ;
        RECT 24.525 20.145 24.695 20.315 ;
        RECT 25.905 20.145 26.075 20.315 ;
        RECT 40.165 20.485 40.335 20.655 ;
        RECT 39.705 20.145 39.875 20.315 ;
        RECT 11.185 19.465 11.355 19.635 ;
        RECT 19.465 19.465 19.635 19.635 ;
        RECT 28.665 19.465 28.835 19.635 ;
        RECT 40.625 20.145 40.795 20.315 ;
        RECT 13.945 18.445 14.115 18.615 ;
        RECT 9.805 17.765 9.975 17.935 ;
        RECT 10.265 17.765 10.435 17.935 ;
        RECT 10.725 17.765 10.895 17.935 ;
        RECT 11.645 17.765 11.815 17.935 ;
        RECT 8.425 16.745 8.595 16.915 ;
        RECT 14.865 17.765 15.035 17.935 ;
        RECT 19.385 18.105 19.555 18.275 ;
        RECT 26.825 18.445 26.995 18.615 ;
        RECT 43.385 18.445 43.555 18.615 ;
        RECT 18.545 16.745 18.715 16.915 ;
        RECT 19.465 16.745 19.635 16.915 ;
        RECT 10.725 15.045 10.895 15.215 ;
        RECT 9.805 14.705 9.975 14.875 ;
        RECT 18.085 15.725 18.255 15.895 ;
        RECT 18.545 15.045 18.715 15.215 ;
        RECT 13.025 14.365 13.195 14.535 ;
        RECT 23.145 14.705 23.315 14.875 ;
        RECT 24.065 14.705 24.235 14.875 ;
        RECT 26.365 14.705 26.535 14.875 ;
        RECT 27.285 14.705 27.455 14.875 ;
        RECT 20.385 13.005 20.555 13.175 ;
        RECT 5.950 12.325 6.120 12.495 ;
        RECT 10.265 12.325 10.435 12.495 ;
        RECT 11.185 12.325 11.355 12.495 ;
        RECT 24.525 13.005 24.695 13.175 ;
        RECT 21.765 11.985 21.935 12.155 ;
        RECT 25.905 11.985 26.075 12.155 ;
        RECT 44.020 6.885 44.190 7.055 ;
      LAYER met1 ;
        RECT 20.400 32.060 31.120 32.200 ;
        RECT 18.930 31.520 19.250 31.580 ;
        RECT 20.400 31.565 20.540 32.060 ;
        RECT 30.445 31.675 30.735 31.905 ;
        RECT 18.735 31.380 19.250 31.520 ;
        RECT 18.930 31.320 19.250 31.380 ;
        RECT 20.325 31.335 20.615 31.565 ;
        RECT 19.850 31.180 20.170 31.240 ;
        RECT 19.655 31.040 20.170 31.180 ;
        RECT 30.520 31.180 30.660 31.675 ;
        RECT 30.980 31.520 31.120 32.060 ;
        RECT 37.790 31.520 38.110 31.580 ;
        RECT 30.980 31.380 38.110 31.520 ;
        RECT 37.790 31.320 38.110 31.380 ;
        RECT 37.345 31.180 37.635 31.225 ;
        RECT 43.770 31.180 44.090 31.240 ;
        RECT 30.520 31.040 44.090 31.180 ;
        RECT 19.850 30.980 20.170 31.040 ;
        RECT 37.345 30.995 37.635 31.040 ;
        RECT 43.770 30.980 44.090 31.040 ;
        RECT 38.725 30.840 39.015 30.885 ;
        RECT 39.170 30.840 39.490 30.900 ;
        RECT 38.725 30.700 39.490 30.840 ;
        RECT 38.725 30.655 39.015 30.700 ;
        RECT 39.170 30.640 39.490 30.700 ;
        RECT 36.410 30.500 36.730 30.560 ;
        RECT 37.805 30.500 38.095 30.545 ;
        RECT 36.410 30.360 38.095 30.500 ;
        RECT 36.410 30.300 36.730 30.360 ;
        RECT 37.805 30.315 38.095 30.360 ;
        RECT 19.850 29.140 20.170 29.200 ;
        RECT 20.325 29.140 20.615 29.185 ;
        RECT 19.850 29.000 24.680 29.140 ;
        RECT 19.850 28.940 20.170 29.000 ;
        RECT 20.325 28.955 20.615 29.000 ;
        RECT 9.730 28.800 10.050 28.860 ;
        RECT 21.230 28.800 21.550 28.860 ;
        RECT 22.150 28.800 22.470 28.860 ;
        RECT 24.540 28.845 24.680 29.000 ;
        RECT 9.535 28.660 10.050 28.800 ;
        RECT 21.035 28.660 21.550 28.800 ;
        RECT 21.955 28.660 22.470 28.800 ;
        RECT 9.730 28.600 10.050 28.660 ;
        RECT 21.230 28.600 21.550 28.660 ;
        RECT 22.150 28.600 22.470 28.660 ;
        RECT 24.465 28.615 24.755 28.845 ;
        RECT 36.870 28.800 37.190 28.860 ;
        RECT 39.170 28.800 39.490 28.860 ;
        RECT 40.090 28.800 40.410 28.860 ;
        RECT 36.675 28.660 37.190 28.800 ;
        RECT 38.975 28.660 39.490 28.800 ;
        RECT 39.895 28.660 40.410 28.800 ;
        RECT 36.870 28.600 37.190 28.660 ;
        RECT 39.170 28.600 39.490 28.660 ;
        RECT 40.090 28.600 40.410 28.660 ;
        RECT 40.565 28.615 40.855 28.845 ;
        RECT 42.850 28.800 43.170 28.860 ;
        RECT 43.770 28.800 44.090 28.860 ;
        RECT 42.655 28.660 43.170 28.800 ;
        RECT 43.575 28.660 44.090 28.800 ;
        RECT 11.110 28.460 11.430 28.520 ;
        RECT 24.910 28.460 25.230 28.520 ;
        RECT 25.830 28.460 26.150 28.520 ;
        RECT 38.710 28.460 39.030 28.520 ;
        RECT 10.915 28.320 11.430 28.460 ;
        RECT 24.715 28.320 25.230 28.460 ;
        RECT 25.635 28.320 26.150 28.460 ;
        RECT 11.110 28.260 11.430 28.320 ;
        RECT 24.910 28.260 25.230 28.320 ;
        RECT 25.830 28.260 26.150 28.320 ;
        RECT 34.430 28.320 39.030 28.460 ;
        RECT 40.640 28.460 40.780 28.615 ;
        RECT 42.850 28.600 43.170 28.660 ;
        RECT 43.770 28.600 44.090 28.660 ;
        RECT 43.325 28.460 43.615 28.505 ;
        RECT 40.640 28.320 43.615 28.460 ;
        RECT 10.205 28.120 10.495 28.165 ;
        RECT 25.385 28.120 25.675 28.165 ;
        RECT 10.205 27.980 25.675 28.120 ;
        RECT 10.205 27.935 10.495 27.980 ;
        RECT 25.385 27.935 25.675 27.980 ;
        RECT 32.745 28.120 33.035 28.165 ;
        RECT 34.430 28.120 34.570 28.320 ;
        RECT 38.710 28.260 39.030 28.320 ;
        RECT 43.325 28.275 43.615 28.320 ;
        RECT 36.410 28.120 36.730 28.180 ;
        RECT 32.745 27.980 34.570 28.120 ;
        RECT 36.215 27.980 36.730 28.120 ;
        RECT 32.745 27.935 33.035 27.980 ;
        RECT 36.410 27.920 36.730 27.980 ;
        RECT 11.570 27.780 11.890 27.840 ;
        RECT 13.885 27.780 14.175 27.825 ;
        RECT 11.570 27.640 14.175 27.780 ;
        RECT 11.570 27.580 11.890 27.640 ;
        RECT 13.885 27.595 14.175 27.640 ;
        RECT 17.565 27.780 17.855 27.825 ;
        RECT 18.930 27.780 19.250 27.840 ;
        RECT 35.950 27.780 36.270 27.840 ;
        RECT 17.565 27.640 19.250 27.780 ;
        RECT 35.755 27.640 36.270 27.780 ;
        RECT 17.565 27.595 17.855 27.640 ;
        RECT 18.930 27.580 19.250 27.640 ;
        RECT 35.950 27.580 36.270 27.640 ;
        RECT 37.790 27.780 38.110 27.840 ;
        RECT 39.185 27.780 39.475 27.825 ;
        RECT 37.790 27.640 39.475 27.780 ;
        RECT 37.790 27.580 38.110 27.640 ;
        RECT 39.185 27.595 39.475 27.640 ;
        RECT 11.110 26.760 11.430 26.820 ;
        RECT 11.585 26.760 11.875 26.805 ;
        RECT 11.110 26.620 11.875 26.760 ;
        RECT 11.110 26.560 11.430 26.620 ;
        RECT 11.585 26.575 11.875 26.620 ;
        RECT 20.785 26.760 21.075 26.805 ;
        RECT 24.910 26.760 25.230 26.820 ;
        RECT 20.785 26.620 25.230 26.760 ;
        RECT 20.785 26.575 21.075 26.620 ;
        RECT 24.910 26.560 25.230 26.620 ;
        RECT 36.410 26.420 36.730 26.480 ;
        RECT 43.310 26.420 43.630 26.480 ;
        RECT 35.975 26.280 43.630 26.420 ;
        RECT 36.410 26.220 36.730 26.280 ;
        RECT 43.310 26.220 43.630 26.280 ;
        RECT 21.705 26.080 21.995 26.125 ;
        RECT 25.830 26.080 26.150 26.140 ;
        RECT 31.365 26.080 31.655 26.125 ;
        RECT 35.950 26.080 36.270 26.140 ;
        RECT 18.560 25.940 28.820 26.080 ;
        RECT 18.560 25.800 18.700 25.940 ;
        RECT 21.705 25.895 21.995 25.940 ;
        RECT 25.830 25.880 26.150 25.940 ;
        RECT 11.125 25.740 11.415 25.785 ;
        RECT 11.570 25.740 11.890 25.800 ;
        RECT 18.470 25.740 18.790 25.800 ;
        RECT 11.125 25.600 11.890 25.740 ;
        RECT 18.275 25.600 18.790 25.740 ;
        RECT 11.125 25.555 11.415 25.600 ;
        RECT 11.570 25.540 11.890 25.600 ;
        RECT 18.470 25.540 18.790 25.600 ;
        RECT 19.390 25.740 19.710 25.800 ;
        RECT 20.785 25.740 21.075 25.785 ;
        RECT 19.390 25.600 21.075 25.740 ;
        RECT 19.390 25.540 19.710 25.600 ;
        RECT 20.785 25.555 21.075 25.600 ;
        RECT 22.625 25.740 22.915 25.785 ;
        RECT 24.910 25.740 25.230 25.800 ;
        RECT 28.680 25.785 28.820 25.940 ;
        RECT 31.365 25.940 36.270 26.080 ;
        RECT 31.365 25.895 31.655 25.940 ;
        RECT 35.950 25.880 36.270 25.940 ;
        RECT 22.625 25.600 25.230 25.740 ;
        RECT 22.625 25.555 22.915 25.600 ;
        RECT 24.910 25.540 25.230 25.600 ;
        RECT 26.765 25.555 27.055 25.785 ;
        RECT 28.605 25.740 28.895 25.785 ;
        RECT 36.500 25.740 36.640 26.220 ;
        RECT 36.870 26.080 37.190 26.140 ;
        RECT 36.870 25.940 39.860 26.080 ;
        RECT 36.870 25.880 37.190 25.940 ;
        RECT 37.805 25.740 38.095 25.785 ;
        RECT 38.710 25.740 39.030 25.800 ;
        RECT 39.720 25.785 39.860 25.940 ;
        RECT 28.605 25.600 34.570 25.740 ;
        RECT 36.500 25.600 38.095 25.740 ;
        RECT 38.515 25.600 39.030 25.740 ;
        RECT 28.605 25.555 28.895 25.600 ;
        RECT 22.165 25.400 22.455 25.445 ;
        RECT 23.530 25.400 23.850 25.460 ;
        RECT 26.840 25.400 26.980 25.555 ;
        RECT 22.165 25.260 26.980 25.400 ;
        RECT 34.430 25.400 34.570 25.600 ;
        RECT 37.805 25.555 38.095 25.600 ;
        RECT 38.710 25.540 39.030 25.600 ;
        RECT 39.645 25.555 39.935 25.785 ;
        RECT 35.505 25.400 35.795 25.445 ;
        RECT 40.090 25.400 40.410 25.460 ;
        RECT 34.430 25.260 40.410 25.400 ;
        RECT 22.165 25.215 22.455 25.260 ;
        RECT 23.530 25.200 23.850 25.260 ;
        RECT 35.505 25.215 35.795 25.260 ;
        RECT 40.090 25.200 40.410 25.260 ;
        RECT 7.215 25.060 7.505 25.105 ;
        RECT 9.270 25.060 9.590 25.120 ;
        RECT 7.215 24.920 9.590 25.060 ;
        RECT 7.215 24.875 7.505 24.920 ;
        RECT 9.270 24.860 9.590 24.920 ;
        RECT 8.365 24.040 8.655 24.085 ;
        RECT 9.730 24.040 10.050 24.100 ;
        RECT 8.365 23.900 10.050 24.040 ;
        RECT 8.365 23.855 8.655 23.900 ;
        RECT 9.730 23.840 10.050 23.900 ;
        RECT 12.045 24.040 12.335 24.085 ;
        RECT 18.470 24.040 18.790 24.100 ;
        RECT 20.310 24.040 20.630 24.100 ;
        RECT 22.150 24.040 22.470 24.100 ;
        RECT 24.910 24.040 25.230 24.100 ;
        RECT 12.045 23.900 18.790 24.040 ;
        RECT 19.875 23.900 22.470 24.040 ;
        RECT 24.715 23.900 25.230 24.040 ;
        RECT 12.045 23.855 12.335 23.900 ;
        RECT 18.470 23.840 18.790 23.900 ;
        RECT 20.310 23.840 20.630 23.900 ;
        RECT 22.150 23.840 22.470 23.900 ;
        RECT 24.910 23.840 25.230 23.900 ;
        RECT 36.870 24.040 37.190 24.100 ;
        RECT 38.265 24.040 38.555 24.085 ;
        RECT 36.870 23.900 38.555 24.040 ;
        RECT 36.870 23.840 37.190 23.900 ;
        RECT 38.265 23.855 38.555 23.900 ;
        RECT 42.865 24.040 43.155 24.085 ;
        RECT 43.310 24.040 43.630 24.100 ;
        RECT 42.865 23.900 43.630 24.040 ;
        RECT 42.865 23.855 43.155 23.900 ;
        RECT 43.310 23.840 43.630 23.900 ;
        RECT 22.240 23.700 22.380 23.840 ;
        RECT 8.900 23.560 11.800 23.700 ;
        RECT 22.240 23.560 24.220 23.700 ;
        RECT 8.900 23.405 9.040 23.560 ;
        RECT 11.660 23.405 11.800 23.560 ;
        RECT 8.825 23.175 9.115 23.405 ;
        RECT 11.585 23.360 11.875 23.405 ;
        RECT 12.030 23.360 12.350 23.420 ;
        RECT 11.585 23.220 12.350 23.360 ;
        RECT 11.585 23.175 11.875 23.220 ;
        RECT 12.030 23.160 12.350 23.220 ;
        RECT 21.230 23.360 21.550 23.420 ;
        RECT 24.080 23.405 24.220 23.560 ;
        RECT 23.545 23.360 23.835 23.405 ;
        RECT 21.230 23.220 23.835 23.360 ;
        RECT 21.230 23.160 21.550 23.220 ;
        RECT 23.545 23.175 23.835 23.220 ;
        RECT 24.005 23.175 24.295 23.405 ;
        RECT 23.620 23.020 23.760 23.175 ;
        RECT 24.450 23.020 24.770 23.080 ;
        RECT 23.620 22.880 24.770 23.020 ;
        RECT 24.450 22.820 24.770 22.880 ;
        RECT 11.110 22.340 11.430 22.400 ;
        RECT 11.585 22.340 11.875 22.385 ;
        RECT 11.110 22.200 11.875 22.340 ;
        RECT 11.110 22.140 11.430 22.200 ;
        RECT 11.585 22.155 11.875 22.200 ;
        RECT 19.390 20.980 19.710 21.040 ;
        RECT 9.820 20.840 19.710 20.980 ;
        RECT 9.270 20.640 9.590 20.700 ;
        RECT 9.820 20.685 9.960 20.840 ;
        RECT 19.390 20.780 19.710 20.840 ;
        RECT 20.310 20.980 20.630 21.040 ;
        RECT 25.385 20.980 25.675 21.025 ;
        RECT 20.310 20.840 25.675 20.980 ;
        RECT 20.310 20.780 20.630 20.840 ;
        RECT 25.385 20.795 25.675 20.840 ;
        RECT 9.745 20.640 10.035 20.685 ;
        RECT 9.270 20.500 10.035 20.640 ;
        RECT 9.270 20.440 9.590 20.500 ;
        RECT 9.745 20.455 10.035 20.500 ;
        RECT 11.125 20.640 11.415 20.685 ;
        RECT 11.570 20.640 11.890 20.700 ;
        RECT 23.530 20.640 23.850 20.700 ;
        RECT 11.125 20.500 11.890 20.640 ;
        RECT 23.335 20.500 23.850 20.640 ;
        RECT 11.125 20.455 11.415 20.500 ;
        RECT 11.570 20.440 11.890 20.500 ;
        RECT 23.530 20.440 23.850 20.500 ;
        RECT 39.170 20.640 39.490 20.700 ;
        RECT 40.105 20.640 40.395 20.685 ;
        RECT 39.170 20.500 40.395 20.640 ;
        RECT 39.170 20.440 39.490 20.500 ;
        RECT 40.105 20.455 40.395 20.500 ;
        RECT 10.190 20.300 10.510 20.360 ;
        RECT 9.995 20.160 10.510 20.300 ;
        RECT 10.190 20.100 10.510 20.160 ;
        RECT 18.945 20.115 19.235 20.345 ;
        RECT 19.865 20.300 20.155 20.345 ;
        RECT 20.310 20.300 20.630 20.360 ;
        RECT 24.450 20.300 24.770 20.360 ;
        RECT 19.865 20.160 20.630 20.300 ;
        RECT 24.015 20.160 24.770 20.300 ;
        RECT 19.865 20.115 20.155 20.160 ;
        RECT 19.020 19.960 19.160 20.115 ;
        RECT 20.310 20.100 20.630 20.160 ;
        RECT 24.450 20.100 24.770 20.160 ;
        RECT 25.845 20.300 26.135 20.345 ;
        RECT 26.750 20.300 27.070 20.360 ;
        RECT 25.845 20.160 27.070 20.300 ;
        RECT 25.845 20.115 26.135 20.160 ;
        RECT 26.750 20.100 27.070 20.160 ;
        RECT 38.710 20.300 39.030 20.360 ;
        RECT 39.645 20.300 39.935 20.345 ;
        RECT 38.710 20.160 39.935 20.300 ;
        RECT 38.710 20.100 39.030 20.160 ;
        RECT 39.645 20.115 39.935 20.160 ;
        RECT 40.565 20.300 40.855 20.345 ;
        RECT 43.310 20.300 43.630 20.360 ;
        RECT 40.565 20.160 43.630 20.300 ;
        RECT 40.565 20.115 40.855 20.160 ;
        RECT 43.310 20.100 43.630 20.160 ;
        RECT 24.540 19.960 24.680 20.100 ;
        RECT 19.020 19.820 24.680 19.960 ;
        RECT 9.730 19.620 10.050 19.680 ;
        RECT 11.125 19.620 11.415 19.665 ;
        RECT 9.730 19.480 11.415 19.620 ;
        RECT 9.730 19.420 10.050 19.480 ;
        RECT 11.125 19.435 11.415 19.480 ;
        RECT 19.405 19.620 19.695 19.665 ;
        RECT 20.770 19.620 21.090 19.680 ;
        RECT 19.405 19.480 21.090 19.620 ;
        RECT 24.540 19.620 24.680 19.820 ;
        RECT 28.605 19.620 28.895 19.665 ;
        RECT 24.540 19.480 28.895 19.620 ;
        RECT 19.405 19.435 19.695 19.480 ;
        RECT 20.770 19.420 21.090 19.480 ;
        RECT 28.605 19.435 28.895 19.480 ;
        RECT 10.190 18.600 10.510 18.660 ;
        RECT 13.885 18.600 14.175 18.645 ;
        RECT 26.750 18.600 27.070 18.660 ;
        RECT 43.310 18.600 43.630 18.660 ;
        RECT 10.190 18.460 14.175 18.600 ;
        RECT 26.555 18.460 27.070 18.600 ;
        RECT 43.115 18.460 43.630 18.600 ;
        RECT 10.190 18.400 10.510 18.460 ;
        RECT 13.885 18.415 14.175 18.460 ;
        RECT 26.750 18.400 27.070 18.460 ;
        RECT 43.310 18.400 43.630 18.460 ;
        RECT 9.270 17.920 9.590 17.980 ;
        RECT 10.280 17.965 10.420 18.400 ;
        RECT 12.030 18.260 12.350 18.320 ;
        RECT 19.325 18.260 19.615 18.305 ;
        RECT 12.030 18.120 19.620 18.260 ;
        RECT 12.030 18.060 12.350 18.120 ;
        RECT 9.745 17.920 10.035 17.965 ;
        RECT 9.270 17.780 10.035 17.920 ;
        RECT 9.270 17.720 9.590 17.780 ;
        RECT 9.745 17.735 10.035 17.780 ;
        RECT 10.205 17.735 10.495 17.965 ;
        RECT 10.665 17.920 10.955 17.965 ;
        RECT 11.110 17.920 11.430 17.980 ;
        RECT 10.665 17.780 11.430 17.920 ;
        RECT 10.665 17.735 10.955 17.780 ;
        RECT 11.110 17.720 11.430 17.780 ;
        RECT 11.570 17.920 11.890 17.980 ;
        RECT 14.880 17.965 15.020 18.120 ;
        RECT 19.325 18.075 19.620 18.120 ;
        RECT 11.570 17.780 12.085 17.920 ;
        RECT 11.570 17.720 11.890 17.780 ;
        RECT 14.805 17.735 15.095 17.965 ;
        RECT 19.480 17.920 19.620 18.075 ;
        RECT 20.770 17.920 21.090 17.980 ;
        RECT 19.480 17.780 21.090 17.920 ;
        RECT 20.770 17.720 21.090 17.780 ;
        RECT 6.510 16.900 6.830 16.960 ;
        RECT 8.365 16.900 8.655 16.945 ;
        RECT 18.470 16.900 18.790 16.960 ;
        RECT 19.390 16.900 19.710 16.960 ;
        RECT 6.510 16.760 8.655 16.900 ;
        RECT 18.275 16.760 18.790 16.900 ;
        RECT 19.195 16.760 19.710 16.900 ;
        RECT 6.510 16.700 6.830 16.760 ;
        RECT 8.365 16.715 8.655 16.760 ;
        RECT 18.470 16.700 18.790 16.760 ;
        RECT 19.390 16.700 19.710 16.760 ;
        RECT 11.570 15.880 11.890 15.940 ;
        RECT 18.025 15.880 18.315 15.925 ;
        RECT 11.570 15.740 18.315 15.880 ;
        RECT 11.570 15.680 11.890 15.740 ;
        RECT 18.025 15.695 18.315 15.740 ;
        RECT 6.510 15.200 6.830 15.260 ;
        RECT 10.665 15.200 10.955 15.245 ;
        RECT 18.470 15.200 18.790 15.260 ;
        RECT 6.510 15.060 10.955 15.200 ;
        RECT 18.275 15.060 18.790 15.200 ;
        RECT 6.510 15.000 6.830 15.060 ;
        RECT 10.665 15.015 10.955 15.060 ;
        RECT 18.470 15.000 18.790 15.060 ;
        RECT 20.770 15.200 21.090 15.260 ;
        RECT 20.770 15.060 27.440 15.200 ;
        RECT 20.770 15.000 21.090 15.060 ;
        RECT 9.730 14.860 10.050 14.920 ;
        RECT 9.535 14.720 10.050 14.860 ;
        RECT 9.730 14.660 10.050 14.720 ;
        RECT 20.310 14.860 20.630 14.920 ;
        RECT 23.085 14.860 23.375 14.905 ;
        RECT 23.990 14.860 24.310 14.920 ;
        RECT 27.300 14.905 27.440 15.060 ;
        RECT 20.310 14.720 23.375 14.860 ;
        RECT 23.795 14.720 24.310 14.860 ;
        RECT 20.310 14.660 20.630 14.720 ;
        RECT 23.085 14.675 23.375 14.720 ;
        RECT 23.990 14.660 24.310 14.720 ;
        RECT 26.305 14.675 26.595 14.905 ;
        RECT 27.225 14.675 27.515 14.905 ;
        RECT 11.110 14.520 11.430 14.580 ;
        RECT 12.965 14.520 13.255 14.565 ;
        RECT 20.400 14.520 20.540 14.660 ;
        RECT 26.380 14.520 26.520 14.675 ;
        RECT 11.110 14.380 20.540 14.520 ;
        RECT 20.860 14.380 26.520 14.520 ;
        RECT 11.110 14.320 11.430 14.380 ;
        RECT 12.965 14.335 13.255 14.380 ;
        RECT 18.930 14.180 19.250 14.240 ;
        RECT 20.860 14.180 21.000 14.380 ;
        RECT 18.930 14.040 21.000 14.180 ;
        RECT 18.930 13.980 19.250 14.040 ;
        RECT 20.310 13.160 20.630 13.220 ;
        RECT 20.115 13.020 20.630 13.160 ;
        RECT 20.310 12.960 20.630 13.020 ;
        RECT 23.990 13.160 24.310 13.220 ;
        RECT 24.465 13.160 24.755 13.205 ;
        RECT 23.990 13.020 24.755 13.160 ;
        RECT 23.990 12.960 24.310 13.020 ;
        RECT 24.465 12.975 24.755 13.020 ;
        RECT 5.890 12.480 6.180 12.525 ;
        RECT 6.510 12.480 6.830 12.540 ;
        RECT 5.890 12.340 6.830 12.480 ;
        RECT 5.890 12.295 6.180 12.340 ;
        RECT 6.510 12.280 6.830 12.340 ;
        RECT 9.730 12.480 10.050 12.540 ;
        RECT 10.205 12.480 10.495 12.525 ;
        RECT 11.110 12.480 11.430 12.540 ;
        RECT 9.730 12.340 10.495 12.480 ;
        RECT 10.915 12.340 11.430 12.480 ;
        RECT 9.730 12.280 10.050 12.340 ;
        RECT 10.205 12.295 10.495 12.340 ;
        RECT 11.110 12.280 11.430 12.340 ;
        RECT 21.705 11.955 21.995 12.185 ;
        RECT 25.845 12.140 26.135 12.185 ;
        RECT 37.790 12.140 38.110 12.200 ;
        RECT 25.845 12.000 38.110 12.140 ;
        RECT 25.845 11.955 26.135 12.000 ;
        RECT 21.780 11.800 21.920 11.955 ;
        RECT 25.920 11.800 26.060 11.955 ;
        RECT 37.790 11.940 38.110 12.000 ;
        RECT 21.780 11.660 26.060 11.800 ;
        RECT 37.790 7.040 38.110 7.100 ;
        RECT 43.960 7.040 44.250 7.085 ;
        RECT 37.790 6.900 44.250 7.040 ;
        RECT 37.790 6.840 38.110 6.900 ;
        RECT 43.960 6.855 44.250 6.900 ;
      LAYER via ;
        RECT 18.960 31.320 19.220 31.580 ;
        RECT 19.880 30.980 20.140 31.240 ;
        RECT 37.820 31.320 38.080 31.580 ;
        RECT 43.800 30.980 44.060 31.240 ;
        RECT 39.200 30.640 39.460 30.900 ;
        RECT 36.440 30.300 36.700 30.560 ;
        RECT 19.880 28.940 20.140 29.200 ;
        RECT 9.760 28.600 10.020 28.860 ;
        RECT 21.260 28.600 21.520 28.860 ;
        RECT 22.180 28.600 22.440 28.860 ;
        RECT 36.900 28.600 37.160 28.860 ;
        RECT 39.200 28.600 39.460 28.860 ;
        RECT 40.120 28.600 40.380 28.860 ;
        RECT 11.140 28.260 11.400 28.520 ;
        RECT 24.940 28.260 25.200 28.520 ;
        RECT 25.860 28.260 26.120 28.520 ;
        RECT 38.740 28.260 39.000 28.520 ;
        RECT 42.880 28.600 43.140 28.860 ;
        RECT 43.800 28.600 44.060 28.860 ;
        RECT 36.440 27.920 36.700 28.180 ;
        RECT 11.600 27.580 11.860 27.840 ;
        RECT 18.960 27.580 19.220 27.840 ;
        RECT 35.980 27.580 36.240 27.840 ;
        RECT 37.820 27.580 38.080 27.840 ;
        RECT 11.140 26.560 11.400 26.820 ;
        RECT 24.940 26.560 25.200 26.820 ;
        RECT 36.440 26.220 36.700 26.480 ;
        RECT 43.340 26.220 43.600 26.480 ;
        RECT 25.860 25.880 26.120 26.140 ;
        RECT 11.600 25.540 11.860 25.800 ;
        RECT 18.500 25.540 18.760 25.800 ;
        RECT 19.420 25.540 19.680 25.800 ;
        RECT 24.940 25.540 25.200 25.800 ;
        RECT 35.980 25.880 36.240 26.140 ;
        RECT 36.900 25.880 37.160 26.140 ;
        RECT 23.560 25.200 23.820 25.460 ;
        RECT 38.740 25.540 39.000 25.800 ;
        RECT 40.120 25.200 40.380 25.460 ;
        RECT 9.300 24.860 9.560 25.120 ;
        RECT 9.760 23.840 10.020 24.100 ;
        RECT 18.500 23.840 18.760 24.100 ;
        RECT 20.340 23.840 20.600 24.100 ;
        RECT 22.180 23.840 22.440 24.100 ;
        RECT 24.940 23.840 25.200 24.100 ;
        RECT 36.900 23.840 37.160 24.100 ;
        RECT 43.340 23.840 43.600 24.100 ;
        RECT 12.060 23.160 12.320 23.420 ;
        RECT 21.260 23.160 21.520 23.420 ;
        RECT 24.480 22.820 24.740 23.080 ;
        RECT 11.140 22.140 11.400 22.400 ;
        RECT 9.300 20.440 9.560 20.700 ;
        RECT 19.420 20.780 19.680 21.040 ;
        RECT 20.340 20.780 20.600 21.040 ;
        RECT 11.600 20.440 11.860 20.700 ;
        RECT 23.560 20.440 23.820 20.700 ;
        RECT 39.200 20.440 39.460 20.700 ;
        RECT 10.220 20.100 10.480 20.360 ;
        RECT 20.340 20.100 20.600 20.360 ;
        RECT 24.480 20.100 24.740 20.360 ;
        RECT 26.780 20.100 27.040 20.360 ;
        RECT 38.740 20.100 39.000 20.360 ;
        RECT 43.340 20.100 43.600 20.360 ;
        RECT 9.760 19.420 10.020 19.680 ;
        RECT 20.800 19.420 21.060 19.680 ;
        RECT 10.220 18.400 10.480 18.660 ;
        RECT 26.780 18.400 27.040 18.660 ;
        RECT 43.340 18.400 43.600 18.660 ;
        RECT 9.300 17.720 9.560 17.980 ;
        RECT 12.060 18.060 12.320 18.320 ;
        RECT 11.140 17.720 11.400 17.980 ;
        RECT 11.600 17.720 11.860 17.980 ;
        RECT 20.800 17.720 21.060 17.980 ;
        RECT 6.540 16.700 6.800 16.960 ;
        RECT 18.500 16.700 18.760 16.960 ;
        RECT 19.420 16.700 19.680 16.960 ;
        RECT 11.600 15.680 11.860 15.940 ;
        RECT 6.540 15.000 6.800 15.260 ;
        RECT 18.500 15.000 18.760 15.260 ;
        RECT 20.800 15.000 21.060 15.260 ;
        RECT 9.760 14.660 10.020 14.920 ;
        RECT 20.340 14.660 20.600 14.920 ;
        RECT 24.020 14.660 24.280 14.920 ;
        RECT 11.140 14.320 11.400 14.580 ;
        RECT 18.960 13.980 19.220 14.240 ;
        RECT 20.340 12.960 20.600 13.220 ;
        RECT 24.020 12.960 24.280 13.220 ;
        RECT 6.540 12.280 6.800 12.540 ;
        RECT 9.760 12.280 10.020 12.540 ;
        RECT 11.140 12.280 11.400 12.540 ;
        RECT 37.820 11.940 38.080 12.200 ;
        RECT 37.820 6.840 38.080 7.100 ;
      LAYER met2 ;
        RECT 18.960 31.290 19.220 31.610 ;
        RECT 37.820 31.290 38.080 31.610 ;
        RECT 9.760 28.570 10.020 28.890 ;
        RECT 9.300 24.830 9.560 25.150 ;
        RECT 9.360 20.730 9.500 24.830 ;
        RECT 9.820 24.130 9.960 28.570 ;
        RECT 11.140 28.230 11.400 28.550 ;
        RECT 11.200 26.850 11.340 28.230 ;
        RECT 19.020 27.870 19.160 31.290 ;
        RECT 19.880 30.950 20.140 31.270 ;
        RECT 19.940 29.230 20.080 30.950 ;
        RECT 36.440 30.270 36.700 30.590 ;
        RECT 19.880 28.910 20.140 29.230 ;
        RECT 21.260 28.570 21.520 28.890 ;
        RECT 22.180 28.570 22.440 28.890 ;
        RECT 11.600 27.550 11.860 27.870 ;
        RECT 18.960 27.550 19.220 27.870 ;
        RECT 11.140 26.530 11.400 26.850 ;
        RECT 11.660 25.830 11.800 27.550 ;
        RECT 11.600 25.510 11.860 25.830 ;
        RECT 18.500 25.510 18.760 25.830 ;
        RECT 18.560 24.130 18.700 25.510 ;
        RECT 9.760 23.810 10.020 24.130 ;
        RECT 18.500 23.810 18.760 24.130 ;
        RECT 12.060 23.130 12.320 23.450 ;
        RECT 11.140 22.110 11.400 22.430 ;
        RECT 9.300 20.410 9.560 20.730 ;
        RECT 9.360 18.010 9.500 20.410 ;
        RECT 10.220 20.070 10.480 20.390 ;
        RECT 9.760 19.390 10.020 19.710 ;
        RECT 9.300 17.690 9.560 18.010 ;
        RECT 6.540 16.670 6.800 16.990 ;
        RECT 6.600 15.290 6.740 16.670 ;
        RECT 6.540 14.970 6.800 15.290 ;
        RECT 6.600 12.570 6.740 14.970 ;
        RECT 9.820 14.950 9.960 19.390 ;
        RECT 10.280 18.690 10.420 20.070 ;
        RECT 10.220 18.370 10.480 18.690 ;
        RECT 11.200 18.010 11.340 22.110 ;
        RECT 11.600 20.410 11.860 20.730 ;
        RECT 11.660 18.010 11.800 20.410 ;
        RECT 12.120 18.350 12.260 23.130 ;
        RECT 12.060 18.030 12.320 18.350 ;
        RECT 11.140 17.690 11.400 18.010 ;
        RECT 11.600 17.690 11.860 18.010 ;
        RECT 11.660 15.970 11.800 17.690 ;
        RECT 18.500 16.670 18.760 16.990 ;
        RECT 11.600 15.650 11.860 15.970 ;
        RECT 18.560 15.290 18.700 16.670 ;
        RECT 18.500 14.970 18.760 15.290 ;
        RECT 9.760 14.630 10.020 14.950 ;
        RECT 9.820 12.570 9.960 14.630 ;
        RECT 11.140 14.290 11.400 14.610 ;
        RECT 11.200 12.570 11.340 14.290 ;
        RECT 19.020 14.270 19.160 27.550 ;
        RECT 19.420 25.510 19.680 25.830 ;
        RECT 19.480 21.070 19.620 25.510 ;
        RECT 20.340 23.810 20.600 24.130 ;
        RECT 20.400 21.070 20.540 23.810 ;
        RECT 21.320 23.450 21.460 28.570 ;
        RECT 22.240 24.130 22.380 28.570 ;
        RECT 24.940 28.230 25.200 28.550 ;
        RECT 25.860 28.230 26.120 28.550 ;
        RECT 25.000 26.850 25.140 28.230 ;
        RECT 24.940 26.530 25.200 26.850 ;
        RECT 25.920 26.170 26.060 28.230 ;
        RECT 36.500 28.210 36.640 30.270 ;
        RECT 36.900 28.570 37.160 28.890 ;
        RECT 36.440 27.890 36.700 28.210 ;
        RECT 35.980 27.550 36.240 27.870 ;
        RECT 36.040 26.170 36.180 27.550 ;
        RECT 36.500 26.510 36.640 27.890 ;
        RECT 36.440 26.190 36.700 26.510 ;
        RECT 36.960 26.170 37.100 28.570 ;
        RECT 37.880 27.870 38.020 31.290 ;
        RECT 43.800 30.950 44.060 31.270 ;
        RECT 39.200 30.610 39.460 30.930 ;
        RECT 39.260 28.890 39.400 30.610 ;
        RECT 43.860 28.890 44.000 30.950 ;
        RECT 39.200 28.570 39.460 28.890 ;
        RECT 40.120 28.570 40.380 28.890 ;
        RECT 42.880 28.800 43.140 28.890 ;
        RECT 42.880 28.660 43.540 28.800 ;
        RECT 42.880 28.570 43.140 28.660 ;
        RECT 38.740 28.230 39.000 28.550 ;
        RECT 37.820 27.550 38.080 27.870 ;
        RECT 25.860 25.850 26.120 26.170 ;
        RECT 35.980 25.850 36.240 26.170 ;
        RECT 36.900 25.850 37.160 26.170 ;
        RECT 24.940 25.510 25.200 25.830 ;
        RECT 23.560 25.170 23.820 25.490 ;
        RECT 22.180 23.810 22.440 24.130 ;
        RECT 21.260 23.130 21.520 23.450 ;
        RECT 19.420 20.750 19.680 21.070 ;
        RECT 20.340 20.750 20.600 21.070 ;
        RECT 19.480 16.990 19.620 20.750 ;
        RECT 20.400 20.390 20.540 20.750 ;
        RECT 23.620 20.730 23.760 25.170 ;
        RECT 25.000 24.130 25.140 25.510 ;
        RECT 36.960 24.130 37.100 25.850 ;
        RECT 24.940 23.810 25.200 24.130 ;
        RECT 36.900 23.810 37.160 24.130 ;
        RECT 24.480 22.790 24.740 23.110 ;
        RECT 23.560 20.410 23.820 20.730 ;
        RECT 24.540 20.390 24.680 22.790 ;
        RECT 20.340 20.070 20.600 20.390 ;
        RECT 24.480 20.070 24.740 20.390 ;
        RECT 26.780 20.070 27.040 20.390 ;
        RECT 20.800 19.390 21.060 19.710 ;
        RECT 20.860 18.010 21.000 19.390 ;
        RECT 26.840 18.690 26.980 20.070 ;
        RECT 26.780 18.370 27.040 18.690 ;
        RECT 20.800 17.690 21.060 18.010 ;
        RECT 19.420 16.670 19.680 16.990 ;
        RECT 20.860 15.290 21.000 17.690 ;
        RECT 20.800 14.970 21.060 15.290 ;
        RECT 20.340 14.630 20.600 14.950 ;
        RECT 24.020 14.630 24.280 14.950 ;
        RECT 18.960 13.950 19.220 14.270 ;
        RECT 20.400 13.250 20.540 14.630 ;
        RECT 24.080 13.250 24.220 14.630 ;
        RECT 20.340 12.930 20.600 13.250 ;
        RECT 24.020 12.930 24.280 13.250 ;
        RECT 6.540 12.250 6.800 12.570 ;
        RECT 9.760 12.250 10.020 12.570 ;
        RECT 11.140 12.250 11.400 12.570 ;
        RECT 37.880 12.230 38.020 27.550 ;
        RECT 38.800 25.830 38.940 28.230 ;
        RECT 38.740 25.510 39.000 25.830 ;
        RECT 38.800 20.390 38.940 25.510 ;
        RECT 39.260 20.730 39.400 28.570 ;
        RECT 40.180 25.490 40.320 28.570 ;
        RECT 43.400 26.510 43.540 28.660 ;
        RECT 43.800 28.570 44.060 28.890 ;
        RECT 43.340 26.190 43.600 26.510 ;
        RECT 40.120 25.170 40.380 25.490 ;
        RECT 43.400 24.130 43.540 26.190 ;
        RECT 43.340 23.810 43.600 24.130 ;
        RECT 39.200 20.410 39.460 20.730 ;
        RECT 38.740 20.070 39.000 20.390 ;
        RECT 43.340 20.070 43.600 20.390 ;
        RECT 43.400 18.690 43.540 20.070 ;
        RECT 43.340 18.370 43.600 18.690 ;
        RECT 37.820 11.910 38.080 12.230 ;
        RECT 37.880 7.130 38.020 11.910 ;
        RECT 37.820 6.810 38.080 7.130 ;
  END
END dcdc_config
END LIBRARY
